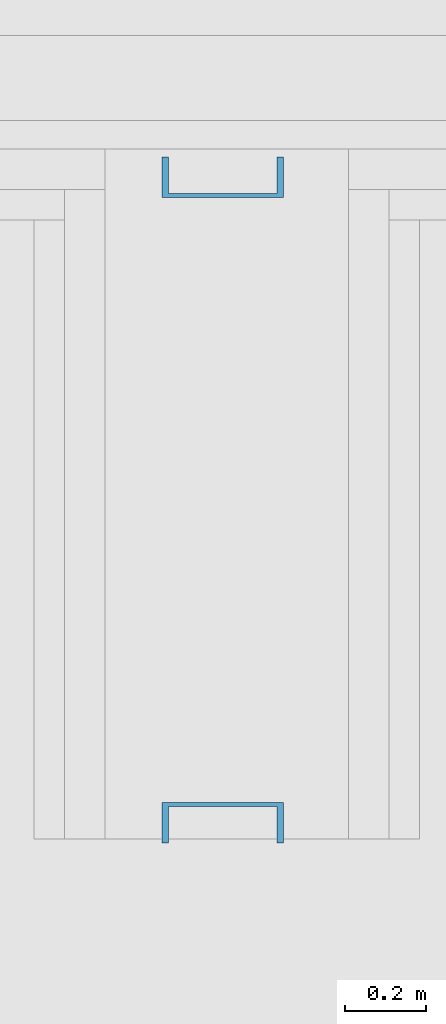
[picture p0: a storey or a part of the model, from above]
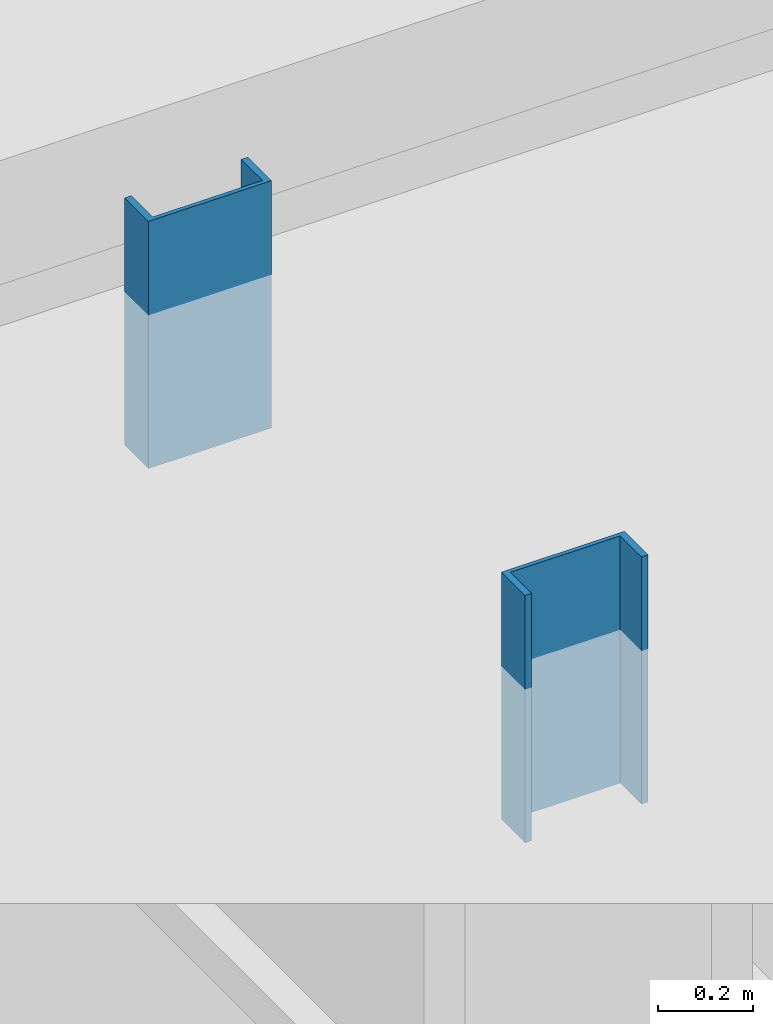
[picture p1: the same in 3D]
Properties of the parts of a building model (IFC2X3), part 1 of 9

# File
Description: ViewDefinition [1, SurfaceGeometryAddOnView, QuantityTakeOffAddOnView, SpaceBoundary2ndLevelAddOnView], Option [Elements to export: Visible elements (on all stories)], Option [Partial Structure Display: Entire Model], Option [IFC Domain: All], Option [Structural Function: All Elements], Option [Convert Grid elements: On], Option [Convert IFC Annotations and ARCHICAD 2D elements: Off], Option [Convert 2D symbols of Doors and Windows: Off], Option [Export geometries that Participates in Collision Detection only: On], Option [Split complex elements: Off], Option [Material Preservation: Explode all], Option [IFC Model position: Project Origin only], Option [Curtain Wall export mode: Container Element], Option [Railing export mode: Container Element], Option [Stair export mode: Container Element], Option [Properties To Export: Current Scheme properties only], Option [Space containment: On], Option [IFC Domain For Space Containment: Custom], Option [Bounding Box: On], Option [Geometry to type objects: On], Option [Element Properties: Off], Option [Building Material Properties: Off], Option [Element Parameters: Off], Option [Component Parameters: IFC Component Quantities Only], Option [IFC Base Quantities: On], Option [Door Window Parameters: Off], Option [IFC Space boundaries: On], Option [ARCHICAD Zone Categories as IFC Space classification data: Off], Option [Element Classifications: On]
File name: P:\Project\2021\21083 1566 Scholen Laren\Archicad\Pdf-Dwg-Ifc-Bimx\21083-TO\IFC\21083-IFC Bouwkundig model.ifc
Time: 2024-04-12T09:14:02
Author: Architect
Organization: Naam bureau
Written by: The EXPRESS Data Manager Version 5.02.0100.09 : 26 Sep 2013
Made in: IFC file generated by GRAPHISOFT ARCHICAD 25.0.0 NED FULL Windows version (IFC add-on version: 7000 NED FULL).
Authorization: The authorising person

# IfcSite, Site
RefLatitude: 51, 27, 0, 0; RefLongitude: 5, 29, 0, 0; RefElevation: 0 mm
BaseQuantities - GrossPerimeter: 0 mm; GrossArea: 0 m2

# IfcBuilding, Naam gebouw
BaseQuantities - GrossFloorArea: 0 m2

# IfcBuildingStorey (5)
In: Naam gebouw
BaseQuantities - GrossFloorArea: 0 m2
Name | Elevation (mm) | NetHeight (mm) = GrossHeight (mm) = Height (mm)
fundering | -1050 | 1050
begane grond | 0 | 3960
verdieping | 3960 | 3960
techniek | 7920 | 3480
dakaanzicht | 11400 | 3500

# IfcBeam: 21 geveldrager (2600+) 208 x 300 (6)
Type - PredefinedType: LINTEL
Classification: 21.22 spouwwanden (NL/SfB (4 cijfers)); Latei (ARCHICAD Classification)
Pset_BeamCommon - Slope: 0 deg; LoadBearing: no; IsExternal: yes; Reference: 21 geveldrager (2600+) 208 x 300
CPset_Phasing - Renovation Phase: Bestaand
BaseQuantities - CrossSectionArea: 0.001983 m2
Name | In | NetSurfaceAreaExtrudedSides (m2) = OuterSurfaceArea (m2) | Length (mm) | TotalSurfaceArea (m2) = GrossSurfaceArea (m2) = NetSurfaceArea (m2) | GrossVolume (m3) = NetVolume (m3)
21_21 geveldrager | begane grond | 33.6494 | 33119.5 | 33.6534 | 0.065676
21_21 geveldrager | begane grond | 29.6365 | 29255 | 29.6405 | 0.0578729
21_21 geveldrager | begane grond | 14.9247 | 14860 | 14.9286 | 0.0291878
21_21 geveldrager | begane grond | 6.87813 | 6855 | 6.8821 | 0.0134537
21_21 geveldrager | verdieping | 14.2494 | 14025 | 14.2534 | 0.0278116
21_21 geveldrager | verdieping | 33.6494 | 33119.5 | 33.6534 | 0.065676

# IfcBeam: 21 geveldrager (3200+) 75 x 300 (4)
In: begane grond
Type - PredefinedType: LINTEL
Classification: 21.22 spouwwanden (NL/SfB (4 cijfers)); Latei (ARCHICAD Classification); Material: Metaal - Staal C beige
Pset_BeamCommon - Slope: 0 deg; LoadBearing: no; IsExternal: yes; Reference: 21 geveldrager (3200+) 75 x 300
CPset_Phasing - Renovation Phase: Bestaand
BaseQuantities - CrossSectionArea: 0.00185 m2
Component Quantities - Metaal - Staal C beige, Component Cross Section Area: 0.00185 m2
Name | NetSurfaceAreaExtrudedSides (m2) = OuterSurfaceArea (m2) | Length (mm) | TotalSurfaceArea (m2) = GrossSurfaceArea (m2) = NetSurfaceArea (m2) | GrossVolume (m3) = NetVolume (m3) = Metaal - Staal C beige, Component Volume (Net) (m3) = Metaal - Staal C beige, Component Volume (Gross) (m3) | Metaal - Staal C beige, Mass (kg)
21_21 geveldrager | 21.4927 | 28722 | 21.4964 | 0.0530147 | 421.467
21_21 geveldrager | 17.8012 | 23800 | 17.8049 | 0.043909 | 349.077
21_21 geveldrager | 1.69872 | 2330 | 1.70242 | 0.0041895 | 33.3065
21_22 geveldrager | 0.562475 | 815 | 0.566175 | 0.00138675 | 11.0247

# IfcBeam: 28 HEB200 200 x 200 (67)
Type - PredefinedType: BEAM
Classification: Balk (ARCHICAD Classification); 28.11 kolom-/liggerconstructies (NL/SfB (4 cijfers))
Pset_BeamCommon - Slope: 0 deg; LoadBearing: yes; IsExternal: no; Reference: 28 HEB200 200 x 200
CPset_Phasing - Renovation Phase: Bestaand
BaseQuantities - CrossSectionArea: 0.00753 m2
Name | In | NetSurfaceAreaExtrudedSides (m2) = OuterSurfaceArea (m2) | Length (mm) | TotalSurfaceArea (m2) = GrossSurfaceArea (m2) = NetSurfaceArea (m2) | GrossVolume (m3) | NetVolume (m3)
30 x 28_Balk-x | begane grond | 0.5319 | 450 | 0.54696 | 0.0033885 | 0.0033885
28_Balk-x | begane grond | 0.46657 | 450 | 0.48163 | 0.0033885 | 0.00292337
28_Balk-x | begane grond | 4.54393 | 3935.8 | 4.55899 | 0.0297872 | 0.0289903
28_Balk-x | begane grond | 3.13411 | 2704.25 | 3.14917 | 0.0216864 | 0.0199231
28_Balk-x | begane grond | 0.520627 | 550 | 0.535687 | 0.00371189 | 0.00331013
5 x 28_Balk-x | begane grond | 0.463409 | 444.5 | 0.478469 | 0.00386862 | 0.00290838
2 x 28_Balk-x | begane grond | 0.5319 | 550 | 0.54696 | 0.0033885 | 0.0033885
28_Balk-x | verdieping | 0.472801 | 400.001 | 0.487861 | 0.00301201 | 0.00301201
28_Balk-x | verdieping | 4.29752 | 3635.8 | 4.31258 | 0.0273776 | 0.0273776
28_Balk-x | verdieping | 2.97618 | 2704.25 | 2.99124 | 0.0215403 | 0.0188632
20 x 28_Balk-x | verdieping | 0.5319 | 450 | 0.54696 | 0.0033885 | 0.0033885
2 x 28_Balk-x | verdieping | 0.5319 | 550 | 0.54696 | 0.0033885 | 0.0033885
28_Balk-x | verdieping | 0.18315 | 450 | 0.19821 | 0.0033885 | 0.00127238 | Material: Metaal - Staal C; Component Quantities - Metaal - Staal C, Mass: 10.1154 kg; Metaal - Staal C, Rectangular Component Height: 15 mm; Metaal - Staal C, Rectangular Component Width: 200 mm; Metaal - Staal C, Component Cross Section Area: 0.003 m2; Metaal - Staal C, Component Volume (Net): 0.00127238 m3; Metaal - Staal C, Component Volume (Gross): 0.00127238 m3

# IfcBeam: 28 HEB280 280 x 280, 28_Balk-x
In: begane grond
Type - PredefinedType: BEAM
Classification: Balk (ARCHICAD Classification); 28.11 kolom-/liggerconstructies (NL/SfB (4 cijfers))
Pset_BeamCommon - Slope: 0 deg; LoadBearing: yes; IsExternal: no; Reference: 28 HEB280 280 x 280
CPset_Phasing - Renovation Phase: Bestaand
BaseQuantities - NetSurfaceAreaExtrudedSides: 23.7237 m2; Length: 14300 mm; CrossSectionArea: 0.011025 m2; OuterSurfaceArea: 23.7237 m2; TotalSurfaceArea: 23.7458 m2; GrossSurfaceArea: 23.7458 m2; GrossVolume: 0.157658 m3; NetSurfaceArea: 23.7458 m2; NetVolume: 0.157658 m3

# IfcBeam: 28 HEB300 300 x 300 (11)
Type - PredefinedType: BEAM
Classification: Balk (ARCHICAD Classification); 28.11 kolom-/liggerconstructies (NL/SfB (4 cijfers))
Pset_BeamCommon - Slope: 0 deg; LoadBearing: yes; IsExternal: no; Reference: 28 HEB300 300 x 300
CPset_Phasing - Renovation Phase: Bestaand
BaseQuantities - CrossSectionArea: 0.014282 m2
Name | In | NetSurfaceAreaExtrudedSides (m2) = OuterSurfaceArea (m2) | Length (mm) | TotalSurfaceArea (m2) = GrossSurfaceArea (m2) = NetSurfaceArea (m2) | GrossVolume (m3) | NetVolume (m3)
28_Balk-x | begane grond | 62.2069 | 34987 | 62.2355 | 0.499684 | 0.499684
28_Balk-x | begane grond | 62.2069 | 34987 | 62.2354 | 0.499684 | 0.499684
28_Balk-x | begane grond | 35.6512 | 20120 | 35.6797 | 0.287639 | 0.28614
28_Balk-x | begane grond | 23.9917 | 13555 | 24.0203 | 0.193593 | 0.192245
28_Balk-x | begane grond | 70.6642 | 39805 | 70.6928 | 0.568495 | 0.567148
28_Balk-x | verdieping | 10.6015 | 6214.5 | 10.63 | 0.0884176 | 0.0849659
28_Balk-x | verdieping | 36.1866 | 20395 | 36.2152 | 0.290865 | 0.290865
28_Balk-x | verdieping | 61.3012 | 34876 | 61.3297 | 0.498256 | 0.491663
28_Balk-x | verdieping | 62.2069 | 34987 | 62.2354 | 0.499684 | 0.499684
28_Balk-x | verdieping | 45.4198 | 25890 | 45.4483 | 0.367619 | 0.364478
28_Balk-x | verdieping | 22.7228 | 13080 | 22.7514 | 0.182524 | 0.182524

# IfcBeam: 28 SFBHE320B/S355 (pet) 425 x 340 (7)
Type - PredefinedType: BEAM
Classification: Balk (ARCHICAD Classification); 28.11 kolom-/liggerconstructies (NL/SfB (4 cijfers))
Pset_BeamCommon - Slope: 0 deg; LoadBearing: yes; IsExternal: no; Reference: 28 SFBHE320B/S355 (pet) 425 x 340
CPset_Phasing - Renovation Phase: Bestaand
BaseQuantities - CrossSectionArea: 0.1109 m2
Name | In | NetSurfaceAreaExtrudedSides (m2) = OuterSurfaceArea (m2) | Length (mm) | TotalSurfaceArea (m2) = GrossSurfaceArea (m2) = NetSurfaceArea (m2) | GrossVolume (m3) | NetVolume (m3)
2 x 28_Balk-x | begane grond | 14.7033 | 9610 | 14.9251 | 1.06575 | 1.06575
28_Balk-x | begane grond | 0.921825 | 602.5 | 1.14362 | 0.0668172 | 0.0668172
28_Balk-x | begane grond | 3.82043 | 2500 | 4.04223 | 0.27725 | 0.277189
2 x 28_Balk-x | verdieping | 3.43615 | 2245.85 | 3.65795 | 0.249065 | 0.249065
28_Balk-x | verdieping | 3.62153 | 2370 | 3.84333 | 0.262833 | 0.262772

# IfcBeam: 28 SFBHE320B/S355 550 x 340 (10)
Type - PredefinedType: BEAM
Classification: Balk (ARCHICAD Classification); 28.11 kolom-/liggerconstructies (NL/SfB (4 cijfers))
Pset_BeamCommon - Slope: 0 deg; LoadBearing: yes; IsExternal: no; Reference: 28 SFBHE320B/S355 550 x 340
CPset_Phasing - Renovation Phase: Bestaand
BaseQuantities - CrossSectionArea: 0.1198 m2
Name | In | NetSurfaceAreaExtrudedSides (m2) = OuterSurfaceArea (m2) | Length (mm) | TotalSurfaceArea (m2) = GrossSurfaceArea (m2) = NetSurfaceArea (m2) | GrossVolume (m3) | NetVolume (m3)
28_Balk-x | begane grond | 23.6691 | 13309.5 | 23.9087 | 1.59448 | 1.58936
28_Balk-x | begane grond | 35.8083 | 20117 | 36.0479 | 2.41002 | 2.41002
28_Balk-x | begane grond | 8.78578 | 4960 | 9.02538 | 0.594208 | 0.592662
28_Balk-x | begane grond | 8.27034 | 4660 | 8.50994 | 0.558268 | 0.55676
28_Balk-x | begane grond | 12.1129 | 6805 | 12.3525 | 0.815239 | 0.815239
28_Balk-x | verdieping | 45.4597 | 26178.5 | 45.6993 | 3.13756 | 3.08051
28_Balk-x | verdieping | 8.01569 | 4510 | 8.25529 | 0.540298 | 0.53944
28_Balk-x | verdieping | 49.904 | 28081.1 | 50.1436 | 3.36412 | 3.35971
28_Balk-x | verdieping | 49.8788 | 28081.1 | 50.1184 | 3.36412 | 3.3606
28_Balk-x | verdieping | 20.5338 | 11560 | 20.7734 | 1.38489 | 1.38334

# IfcBeam: 28 SFHEB200/S440 (pet) 325 x 332 (2)
In: verdieping
Type - PredefinedType: BEAM
Classification: Balk (ARCHICAD Classification); 28.11 kolom-/liggerconstructies (NL/SfB (4 cijfers))
Pset_BeamCommon - Slope: 0 deg; LoadBearing: yes; IsExternal: no; Reference: 28 SFHEB200/S440 (pet) 325 x 332
CPset_Phasing - Renovation Phase: Bestaand
BaseQuantities - NetSurfaceAreaExtrudedSides: 3.24169 m2; Length: 2467.04 mm; CrossSectionArea: 0.07104 m2; OuterSurfaceArea: 3.24169 m2; TotalSurfaceArea: 3.38377 m2; GrossSurfaceArea: 3.38377 m2; GrossVolume: 0.175258 m3; NetSurfaceArea: 3.38377 m2; NetVolume: 0.175258 m3

# IfcBeam: 28 SFHEB200/S440 440 x 332 (2)
In: verdieping
Type - PredefinedType: BEAM
Classification: Balk (ARCHICAD Classification); 28.11 kolom-/liggerconstructies (NL/SfB (4 cijfers))
Pset_BeamCommon - Slope: 0 deg; LoadBearing: yes; IsExternal: no; Reference: 28 SFHEB200/S440 440 x 332
CPset_Phasing - Renovation Phase: Bestaand
BaseQuantities - NetSurfaceAreaExtrudedSides: 3.0494 m2; Length: 1975 mm; CrossSectionArea: 0.07248 m2; OuterSurfaceArea: 3.0494 m2; TotalSurfaceArea: 3.19436 m2; GrossSurfaceArea: 3.19436 m2; GrossVolume: 0.143148 m3; NetSurfaceArea: 3.19436 m2; NetVolume: 0.143148 m3

# IfcBeam: 28 dakrand 500mm 162 x 500 (4)
In: techniek
Type - PredefinedType: LINTEL
Classification: 21.22 spouwwanden (NL/SfB (4 cijfers)); Latei (ARCHICAD Classification)
Pset_BeamCommon - Slope: 0 deg; LoadBearing: no; IsExternal: yes; Reference: 28 dakrand 500mm 162 x 500
CPset_Phasing - Renovation Phase: Bestaand
BaseQuantities - CrossSectionArea: 0.070417 m2
Name | NetSurfaceAreaExtrudedSides (m2) = OuterSurfaceArea (m2) | Length (mm) | TotalSurfaceArea (m2) = GrossSurfaceArea (m2) = NetSurfaceArea (m2) | GrossVolume (m3) | NetVolume (m3)
21_21 geveldrager | 23.0907 | 8340 | 23.2315 | 0.581841 | 0.578875
21_21 geveldrager | 40.5298 | 14650 | 40.6706 | 1.02074 | 1.01553
21_21 geveldrager | 87.5794 | 31550 | 87.7202 | 2.21078 | 2.1995
21_21 geveldrager | 20.2198 | 7338 | 20.3606 | 0.511283 | 0.504103

# IfcBeam: 28 windligger 290 x 180, 28_Balk-x
In: begane grond
Type - PredefinedType: BEAM
Classification: Balk (ARCHICAD Classification); 28.11 kolom-/liggerconstructies (NL/SfB (4 cijfers))
Pset_BeamCommon - Slope: 0 deg; LoadBearing: yes; IsExternal: no; Reference: 28 windligger 290 x 180
CPset_Phasing - Renovation Phase: Bestaand
BaseQuantities - NetSurfaceAreaExtrudedSides: 4.37944 m2; Length: 5450 mm; CrossSectionArea: 0.0265469 m2; OuterSurfaceArea: 4.37944 m2; TotalSurfaceArea: 4.43253 m2; GrossSurfaceArea: 4.43253 m2; GrossVolume: 0.142803 m3; NetSurfaceArea: 4.43253 m2; NetVolume: 0.142803 m3

# IfcBeam: 32 Hout binnenkozijn oregon pine 190 x 75, 28_Balk-x
In: verdieping
Type - PredefinedType: BEAM
Classification: Balk (ARCHICAD Classification); 28.11 kolom-/liggerconstructies (NL/SfB (4 cijfers)); Material: 32 Hout binnenkozijn oregon pine
Pset_BeamCommon - Slope: 0 deg; LoadBearing: yes; IsExternal: no; Reference: 32 Hout binnenkozijn oregon pine 190 x 75
CPset_Phasing - Renovation Phase: Bestaand
BaseQuantities - NetSurfaceAreaExtrudedSides: 0.954 m2; Length: 1800 mm; Width: 190 mm; Depth: 75 mm; CrossSectionArea: 0.01425 m2; OuterSurfaceArea: 0.954 m2; TotalSurfaceArea: 0.9825 m2; GrossSurfaceArea: 0.9825 m2; GrossVolume: 0.02565 m3; NetSurfaceArea: 0.9825 m2; NetVolume: 0.02565 m3
Component Quantities - 32 Hout binnenkozijn oregon pine, Mass: 14.1075 kg; 32 Hout binnenkozijn oregon pine, Projected Component Area (Net): 0.135 m2; 32 Hout binnenkozijn oregon pine, Projected Component Area (Gross): 0.135 m2; 32 Hout binnenkozijn oregon pine, Component Thickness: 190 mm; 32 Hout binnenkozijn oregon pine, Rectangular Component Height: 75 mm; 32 Hout binnenkozijn oregon pine, Rectangular Component Width: 190 mm; 32 Hout binnenkozijn oregon pine, Component Cross Section Area: 0.01425 m2; 32 Hout binnenkozijn oregon pine, Component Volume (Net): 0.02565 m3; 32 Hout binnenkozijn oregon pine, Component Volume (Gross): 0.02565 m3

# IfcBeam: 32 glapkap drsn 60 x 220 (18)
In: techniek
Type - PredefinedType: LINTEL
Classification: 21.22 spouwwanden (NL/SfB (4 cijfers)); Latei (ARCHICAD Classification)
Pset_BeamCommon - LoadBearing: yes; IsExternal: yes; Reference: 32 glapkap drsn 60 x 220
CPset_Phasing - Renovation Phase: Bestaand
BaseQuantities - CrossSectionArea: 0.0118 m2
Name | Slope (deg) | NetSurfaceAreaExtrudedSides (m2) = OuterSurfaceArea (m2) | Length (mm) | TotalSurfaceArea (m2) = GrossSurfaceArea (m2) = NetSurfaceArea (m2) | GrossVolume (m3) | NetVolume (m3)
21_22 geveldrager | 5 | 0.805619 | 1330.03 | 0.829219 | 0.0161664 | 0.014824
21_22 geveldrager | 0 | 4.45102 | 8520 | 4.47462 | 0.101008 | 0.0949741
21_22 geveldrager | 0 | 5.40516 | 8520 | 5.42876 | 0.101008 | 0.0996568
2 x 21_22 geveldrager | 5 | 0.875709 | 1370.03 | 0.899309 | 0.0161664 | 0.0161331
2 x 21_22 geveldrager | 5 | 0.871629 | 1370.03 | 0.895229 | 0.0161664 | 0.0161155
21_22 geveldrager | 5 | 1.93293 | 3091.46 | 1.95653 | 0.0369512 | 0.0356088
21_22 geveldrager | 0 | 4.39767 | 8557.5 | 4.42127 | 0.102394 | 0.0937438
21_22 geveldrager | 0 | 5.33796 | 8557.5 | 5.36156 | 0.102394 | 0.0983585
2 x 21_22 geveldrager | 5 | 2.00302 | 3131.46 | 2.02662 | 0.0369512 | 0.0369179
6 x 21_22 geveldrager | 5 | 1.99894 | 3131.46 | 2.02254 | 0.0369512 | 0.0369003

# IfcBeam: 32 waterslag (dakkap) +200 708 x 66, 28_Balk-x
In: verdieping
Type - PredefinedType: BEAM
Classification: Balk (ARCHICAD Classification); 28.11 kolom-/liggerconstructies (NL/SfB (4 cijfers))
Pset_BeamCommon - Slope: 0 deg; LoadBearing: yes; IsExternal: no; Reference: 32 waterslag (dakkap) +200 708 x 66
CPset_Phasing - Renovation Phase: Bestaand
BaseQuantities - NetSurfaceAreaExtrudedSides: 1.80172 m2; Length: 865 mm; CrossSectionArea: 0.0145938 m2; OuterSurfaceArea: 1.80172 m2; TotalSurfaceArea: 1.83091 m2; GrossSurfaceArea: 1.83091 m2; GrossVolume: 0.00882921 m3; NetSurfaceArea: 1.83091 m2; NetVolume: 0.00882642 m3

# IfcBeam: 32 waterslag (dakkap) 520 x 66 (3)
In: verdieping
Type - PredefinedType: BEAM
Classification: Balk (ARCHICAD Classification); 28.11 kolom-/liggerconstructies (NL/SfB (4 cijfers))
Pset_BeamCommon - Slope: 0 deg; LoadBearing: yes; IsExternal: no; Reference: 32 waterslag (dakkap) 520 x 66
CPset_Phasing - Renovation Phase: Bestaand
BaseQuantities - CrossSectionArea: 0.0104705 m2
Name | NetSurfaceAreaExtrudedSides (m2) = OuterSurfaceArea (m2) | Length (mm) | TotalSurfaceArea (m2) = GrossSurfaceArea (m2) = NetSurfaceArea (m2) | GrossVolume (m3) | NetVolume (m3)
28_Balk-x | 29.4176 | 13443.2 | 29.4385 | 0.138035 | 0.138017
28_Balk-x | 32.1349 | 14920 | 32.1558 | 0.150776 | 0.150776
28_Balk-x | 30.1063 | 14105 | 30.1273 | 0.141258 | 0.141258

# IfcBeam: 34 glazen balustrade 60 x 1200 (4)
Type - PredefinedType: BEAM
Classification: Balk (ARCHICAD Classification); 28.11 kolom-/liggerconstructies (NL/SfB (4 cijfers))
Pset_BeamCommon - LoadBearing: yes; IsExternal: no; Reference: 34 glazen balustrade 60 x 1200
CPset_Phasing - Renovation Phase: Bestaand
BaseQuantities - CrossSectionArea: 0.022944 m2
Name | In | Slope (deg) | NetSurfaceAreaExtrudedSides (m2) = OuterSurfaceArea (m2) | Length (mm) | TotalSurfaceArea (m2) = GrossSurfaceArea (m2) = NetSurfaceArea (m2) | GrossVolume (m3) | NetVolume (m3)
2 x 28_Balk-x | begane grond | 35.7539 | 7.09456 | 3724.26 | 7.14045 | 0.0736797 | 0.0631358
28_Balk-x | verdieping | 0 | 3.97353 | 1705.31 | 4.01942 | 0.0356534 | 0.034134
28_Balk-x | verdieping | 0 | 0.876334 | 505.307 | 0.922222 | 0.00812062 | 0.00732118

# IfcBeam: 34 glazen balustrade 60 x 1370 (2)
In: verdieping
Type - PredefinedType: BEAM
Classification: Balk (ARCHICAD Classification); 28.11 kolom-/liggerconstructies (NL/SfB (4 cijfers))
Pset_BeamCommon - LoadBearing: yes; IsExternal: no; Reference: 34 glazen balustrade 60 x 1370
CPset_Phasing - Renovation Phase: Bestaand
BaseQuantities - CrossSectionArea: 0.025494 m2
Name | Slope (deg) | NetSurfaceAreaExtrudedSides (m2) = OuterSurfaceArea (m2) | Length (mm) | TotalSurfaceArea (m2) = GrossSurfaceArea (m2) = NetSurfaceArea (m2) | GrossVolume (m3) | NetVolume (m3)
28_Balk-x | 35.7539 | 7.25343 | 3774.16 | 7.30442 | 0.0823317 | 0.0645184
28_Balk-x | 0 | 4.64695 | 1755.91 | 4.69794 | 0.0415345 | 0.0393339

# IfcBeam: 34 glazen balustrade 60 x 992 (2)
In: begane grond
Type - PredefinedType: BEAM
Classification: Balk (ARCHICAD Classification); 28.11 kolom-/liggerconstructies (NL/SfB (4 cijfers))
Pset_BeamCommon - Slope: 35.7539 deg; LoadBearing: yes; IsExternal: no; Reference: 34 glazen balustrade 60 x 992
CPset_Phasing - Renovation Phase: Bestaand
BaseQuantities - NetSurfaceAreaExtrudedSides: 5.48389 m2; Length: 3141.41 mm; CrossSectionArea: 0.019817 m2; OuterSurfaceArea: 5.48389 m2; TotalSurfaceArea: 5.52352 m2; GrossSurfaceArea: 5.52352 m2; GrossVolume: 0.0481058 m3; NetSurfaceArea: 5.52352 m2; NetVolume: 0.0481045 m3

# IfcBeam: 42 geleiding strook (mat) 2 x 200 (13)
In: begane grond
Type - PredefinedType: BEAM
Classification: Balk (ARCHICAD Classification); 28.11 kolom-/liggerconstructies (NL/SfB (4 cijfers)); Material: Glas geleiding strook matt
Pset_BeamCommon - Slope: 0 deg; LoadBearing: no; IsExternal: no; Reference: 42 geleiding strook (mat) 2 x 200
CPset_Phasing - Renovation Phase: Bestaand
BaseQuantities - CrossSectionArea: 0.0004 m2
Component Quantities - Glas geleiding strook matt, Rectangular Component Height: 200 mm; Glas geleiding strook matt, Rectangular Component Width: 2 mm; Glas geleiding strook matt, Component Cross Section Area: 0.0004 m2
Name | NetSurfaceAreaExtrudedSides (m2) = OuterSurfaceArea (m2) | Length (mm) | TotalSurfaceArea (m2) = GrossSurfaceArea (m2) = NetSurfaceArea (m2) | GrossVolume (m3) = NetVolume (m3) = Glas geleiding strook matt, Component Volume (Net) (m3) = Glas geleiding strook matt, Component Volume (Gross) (m3) | Glas geleiding strook matt, Mass (kg)
7 x 28_Balk-x | 0.264216 | 654 | 0.265016 | 0.0002616 | 0.570288
2 x 28_Balk-x | 0.280157 | 693.458 | 0.280957 | 0.000277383 | 0.604695
28_Balk-x | 0.339777 | 841.033 | 0.340577 | 0.000336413 | 0.733381
28_Balk-x | 0.190284 | 471 | 0.191084 | 0.0001884 | 0.410712
2 x 28_Balk-x | 0.322897 | 799.25 | 0.323697 | 0.0003197 | 0.696946

# IfcBeam: 42 geleiding strook 20 x 200 (23)
In: begane grond
Type - PredefinedType: BEAM
Classification: Balk (ARCHICAD Classification); 28.11 kolom-/liggerconstructies (NL/SfB (4 cijfers)); Material: Glas geleiding strook
Pset_BeamCommon - Slope: 0 deg; LoadBearing: no; IsExternal: no; Reference: 42 geleiding strook 20 x 200
CPset_Phasing - Renovation Phase: Bestaand
BaseQuantities - CrossSectionArea: 0.004 m2
Component Quantities - Glas geleiding strook, Rectangular Component Height: 200 mm; Glas geleiding strook, Rectangular Component Width: 20 mm; Glas geleiding strook, Component Cross Section Area: 0.004 m2
Name | NetSurfaceAreaExtrudedSides (m2) = OuterSurfaceArea (m2) | Length (mm) | TotalSurfaceArea (m2) = GrossSurfaceArea (m2) = NetSurfaceArea (m2) | GrossVolume (m3) = NetVolume (m3) = Glas geleiding strook, Component Volume (Net) (m3) = Glas geleiding strook, Component Volume (Gross) (m3) | Glas geleiding strook, Mass (kg)
28_Balk-x | 0.319 | 725 | 0.327 | 0.0029 | 6.322
28_Balk-x | 0.65384 | 1496 | 0.66184 | 0.005944 | 12.9579
2 x 28_Balk-x | 0.2376 | 550 | 0.2456 | 0.00216 | 4.7088
28_Balk-x | 0.25124 | 571 | 0.25924 | 0.002284 | 4.97912
28_Balk-x | 0.1474 | 345 | 0.1554 | 0.00134 | 2.9212
28_Balk-x | 3.01884 | 6861 | 3.02684 | 0.027444 | 59.8279
28_Balk-x | 0.077 | 185 | 0.085 | 0.0007 | 1.526
28_Balk-x | 1.03092 | 2353 | 1.03892 | 0.009372 | 20.431
28_Balk-x | 0.25784 | 596 | 0.26584 | 0.002344 | 5.10992
28_Balk-x | 0.30492 | 693 | 0.31292 | 0.002772 | 6.04296
28_Balk-x | 0.75372 | 1723 | 0.76172 | 0.006852 | 14.9374
28_Balk-x | 0.33484 | 761 | 0.34284 | 0.003044 | 6.63592
28_Balk-x | 0.627 | 1425 | 0.635 | 0.0057 | 12.426
28_Balk-x | 2.60084 | 5921 | 2.60884 | 0.023644 | 51.5439
28_Balk-x | 3.77784 | 8586 | 3.78584 | 0.034344 | 74.8699
28_Balk-x | 0.230681 | 534.275 | 0.238681 | 0.0020971 | 4.57168
28_Balk-x | 0.252659 | 574.225 | 0.260659 | 0.0022969 | 5.00724
28_Balk-x | 0.32692 | 743 | 0.33492 | 0.002972 | 6.47896
28_Balk-x | 0.671 | 1525 | 0.679 | 0.0061 | 13.298
28_Balk-x | 0.71676 | 1629 | 0.72476 | 0.006516 | 14.2049
28_Balk-x | 1.54044 | 3501 | 1.54844 | 0.014004 | 30.5287
28_Balk-x | 3.08264 | 7006 | 3.09064 | 0.028024 | 61.0923

# IfcBeam: 80X80X5 80 x 80 (2)
In: techniek
Type - PredefinedType: BEAM
Classification: Balk (ARCHICAD Classification); 28.11 kolom-/liggerconstructies (NL/SfB (4 cijfers)); Material: Metaal - Staal C
Pset_BeamCommon - Slope: 0 deg; LoadBearing: yes; IsExternal: no; Reference: 80X80X5 80 x 80
CPset_Phasing - Renovation Phase: Bestaand
BaseQuantities - CrossSectionArea: 0.0015 m2
Component Quantities - Metaal - Staal C, Component Cross Section Area: 0.0015 m2
Name | NetSurfaceAreaExtrudedSides (m2) = OuterSurfaceArea (m2) | Length (mm) | TotalSurfaceArea (m2) = GrossSurfaceArea (m2) = NetSurfaceArea (m2) | GrossVolume (m3) | NetVolume (m3) = Metaal - Staal C, Component Volume (Net) (m3) = Metaal - Staal C, Component Volume (Gross) (m3) | Metaal - Staal C, Mass (kg)
28_Balk-x | 5.04659 | 8450 | 5.04959 | 0.012705 | 0.0126163 | 100.3
28_Balk-x | 12.1038 | 20195 | 12.1068 | 0.0302925 | 0.0302597 | 240.565

# IfcBeam: ALG - CONSTRUCTIEF 100 x 100 (4)
In: begane grond
Type - PredefinedType: BEAM
Classification: Balk (ARCHICAD Classification); 28.11 kolom-/liggerconstructies (NL/SfB (4 cijfers)); Material: ALG - CONSTRUCTIEF
Pset_BeamCommon - Slope: 0 deg; LoadBearing: yes; IsExternal: no; Reference: ALG - CONSTRUCTIEF 100 x 100
CPset_Phasing - Renovation Phase: Bestaand
BaseQuantities - Width: 100 mm; Depth: 100 mm; CrossSectionArea: 0.01 m2
Component Quantities - ALG - CONSTRUCTIEF, Component Thickness: 100 mm; ALG - CONSTRUCTIEF, Rectangular Component Height: 100 mm; ALG - CONSTRUCTIEF, Rectangular Component Width: 100 mm; ALG - CONSTRUCTIEF, Component Cross Section Area: 0.01 m2
Name | NetSurfaceAreaExtrudedSides (m2) = OuterSurfaceArea (m2) | Length (mm) | TotalSurfaceArea (m2) = GrossSurfaceArea (m2) = NetSurfaceArea (m2) | GrossVolume (m3) | NetVolume (m3) = ALG - CONSTRUCTIEF, Component Volume (Net) (m3) = ALG - CONSTRUCTIEF, Component Volume (Gross) (m3) | ALG - CONSTRUCTIEF, Mass (kg) | ALG - CONSTRUCTIEF, Projected Component Area (Net) (m2) = ALG - CONSTRUCTIEF, Projected Component Area (Gross) (m2)
28_Balk-x | 0.5 | 1250 | 0.52 | 0.0135 | 0.0125 | 28.75 | 0.125
28_Balk-x | 0.52 | 1350 | 0.54 | 0.013 | 0.013 | 29.9 | 0.135
28_Balk-x | 0.405 | 1062.5 | 0.425 | 0.011125 | 0.010125 | 23.2875 | 0.10625
28_Balk-x | 2.8 | 7000 | 2.82 | 0.07 | 0.07 | 161 | 0.7

# IfcBeam: Fundering balk IsoBouw Powerkist 2800 x 850 (26)
In: fundering
Type - PredefinedType: BEAM
Classification: Balk (ARCHICAD Classification); 28.11 kolom-/liggerconstructies (NL/SfB (4 cijfers))
Pset_BeamCommon - Slope: 0 deg; LoadBearing: yes; IsExternal: no; Reference: Fundering balk IsoBouw Powerkist 2800 x 850
CPset_Phasing - Renovation Phase: Bestaand
BaseQuantities - CrossSectionArea: 1.1175 m2
Name | NetSurfaceAreaExtrudedSides (m2) = OuterSurfaceArea (m2) | Length (mm) | TotalSurfaceArea (m2) = GrossSurfaceArea (m2) = NetSurfaceArea (m2) | GrossVolume (m3) | NetVolume (m3)
4 x 28_Balk-x | 5.89448 | 1480 | 8.12948 | 2.29515 | 1.15442
28_Balk-x | 200.404 | 30135 | 202.639 | 35.6598 | 32.5043
28_Balk-x | 22.4512 | 5470 | 24.6862 | 6.78323 | 4.35576
4 x 28_Balk-x | 5.91865 | 1483.45 | 8.15365 | 2.29901 | 1.15828
28_Balk-x | 20.9525 | 3345 | 23.1875 | 3.73804 | 3.57123
28_Balk-x | 47.3641 | 7123.45 | 49.5991 | 7.96046 | 7.73636
2 x 28_Balk-x | 26.2736 | 4475 | 28.5086 | 6.34348 | 4.43352
2 x 28_Balk-x | 45.8817 | 8340 | 48.1167 | 12.0053 | 7.97562
28_Balk-x | 4.30699 | 1785 | 6.54199 | 3.33741 | 1.10142
28_Balk-x | 7.33068 | 1785 | 9.56568 | 3.33741 | 1.42496
28_Balk-x | 266.232 | 39733 | 268.467 | 45.0429 | 43.4576
28_Balk-x | 225.858 | 33083 | 228.093 | 36.9703 | 36.5366
28_Balk-x | 14.3512 | 3345 | 16.5862 | 4.37929 | 2.75389
4 x 28_Balk-x | 5.19377 | 1380 | 7.42877 | 2.1834 | 1.04267
28_Balk-x | 10.6994 | 2155 | 12.9344 | 2.18341 | 1.88579

# IfcBeam: Fundering balk IsoBouw Powerkist buiten 950 x 700 (3)
In: fundering
Type - PredefinedType: BEAM
Classification: Balk (ARCHICAD Classification); 28.11 kolom-/liggerconstructies (NL/SfB (4 cijfers))
Pset_BeamCommon - Slope: 0 deg; LoadBearing: yes; IsExternal: no; Reference: Fundering balk IsoBouw Powerkist buiten 950 x 700
CPset_Phasing - Renovation Phase: Bestaand
BaseQuantities - CrossSectionArea: 0.575001 m2
Name | NetSurfaceAreaExtrudedSides (m2) = OuterSurfaceArea (m2) | Length (mm) | TotalSurfaceArea (m2) = GrossSurfaceArea (m2) = NetSurfaceArea (m2) | GrossVolume (m3) | NetVolume (m3)
28_Balk-x | 6.0555 | 1835 | 7.2055 | 1.05513 | 1.05513
28_Balk-x | 6.1505 | 1885 | 7.3005 | 1.08388 | 1.07788
28_Balk-x | 5.2425 | 1700 | 6.39251 | 1.44413 | 0.948876

# IfcBeam: Fundering balk IsoBouw Powerkist buitenwand 1750 x 850 (14)
In: fundering
Type - PredefinedType: BEAM
Classification: Balk (ARCHICAD Classification); 28.11 kolom-/liggerconstructies (NL/SfB (4 cijfers))
Pset_BeamCommon - Slope: 0 deg; LoadBearing: yes; IsExternal: no; Reference: Fundering balk IsoBouw Powerkist buitenwand 1750 x 850
CPset_Phasing - Renovation Phase: Bestaand
BaseQuantities - CrossSectionArea: 0.815 m2
Name | NetSurfaceAreaExtrudedSides (m2) = OuterSurfaceArea (m2) | Length (mm) | TotalSurfaceArea (m2) = GrossSurfaceArea (m2) = NetSurfaceArea (m2) | GrossVolume (m3) | NetVolume (m3)
28_Balk-x | 33.1224 | 8160 | 34.7524 | 7.38007 | 5.75902
28_Balk-x | 67.8388 | 17705 | 69.4688 | 13.1497 | 11.494
28_Balk-x | 188.748 | 40715 | 190.378 | 32.0991 | 31.5252
28_Balk-x | 68.0436 | 15210 | 69.6736 | 11.3125 | 11.2195
28_Balk-x | 50.7073 | 12145 | 52.3373 | 9.26655 | 8.68128
28_Balk-x | 32.9579 | 7975 | 34.5879 | 5.868 | 5.71056
28_Balk-x | 37.7127 | 8995 | 39.3427 | 6.24731 | 6.24731
28_Balk-x | 37.7885 | 9010 | 39.4185 | 6.25954 | 6.25954
28_Balk-x | 45.4555 | 12065 | 47.0855 | 8.74936 | 7.80175
28_Balk-x | 3.31008 | 2405 | 4.94008 | 0.533825 | 0.533825
28_Balk-x | 138.162 | 28997 | 139.792 | 23.0907 | 22.7019
28_Balk-x | 169.164 | 35897 | 170.794 | 28.1724 | 27.7889
28_Balk-x | 9.16711 | 3563.99 | 10.7971 | 1.4784 | 1.4784
28_Balk-x | 9.16715 | 3564 | 10.7971 | 1.47841 | 1.47841

# IfcBeam: HEB140 140 x 140 (20)
In: verdieping
Type - PredefinedType: BEAM
Classification: Balk (ARCHICAD Classification); 28.11 kolom-/liggerconstructies (NL/SfB (4 cijfers))
Pset_BeamCommon - Slope: 0 deg; LoadBearing: yes; IsExternal: no; Reference: HEB140 140 x 140
CPset_Phasing - Renovation Phase: Bestaand
BaseQuantities - CrossSectionArea: 0.00259 m2
Name | NetSurfaceAreaExtrudedSides (m2) = OuterSurfaceArea (m2) | Length (mm) | TotalSurfaceArea (m2) = GrossSurfaceArea (m2) = NetSurfaceArea (m2) | GrossVolume (m3) = NetVolume (m3)
5 x 28_Balk-x | 0.76775 | 925 | 0.77293 | 0.00239575
7 x 28_Balk-x | 4.10435 | 4945 | 4.10953 | 0.0128075
4 x 28_Balk-x | 3.9757 | 4790 | 3.98088 | 0.0124061
2 x 28_Balk-x | 0.4316 | 520 | 0.43678 | 0.0013468
28_Balk-x | 0.6557 | 790 | 0.66088 | 0.0020461
28_Balk-x | 0.8383 | 1010 | 0.84348 | 0.0026159

# IfcBeam: HEB320 300 x 320, 28_Balk-x
In: begane grond
Type - PredefinedType: BEAM
Classification: Balk (ARCHICAD Classification); 28.11 kolom-/liggerconstructies (NL/SfB (4 cijfers)); Material: Metaal - Staal C
Pset_BeamCommon - Slope: 0 deg; LoadBearing: yes; IsExternal: no; Reference: HEB320 300 x 320
CPset_Phasing - Renovation Phase: Bestaand
BaseQuantities - NetSurfaceAreaExtrudedSides: 71.5565 m2; Length: 39697.8 mm; CrossSectionArea: 0.0155085 m2; OuterSurfaceArea: 71.5565 m2; TotalSurfaceArea: 71.5875 m2; GrossSurfaceArea: 71.5875 m2; GrossVolume: 0.618246 m3; NetSurfaceArea: 71.5875 m2; NetVolume: 0.610081 m3
Component Quantities - Metaal - Staal C, Mass: 4850.14 kg; Metaal - Staal C, Component Cross Section Area: 0.0155085 m2; Metaal - Staal C, Component Volume (Net): 0.610081 m3; Metaal - Staal C, Component Volume (Gross): 0.610081 m3

# IfcBeam: Hout C 38 x 120 (4)
In: begane grond
Type - PredefinedType: BEAM
Classification: Balk (ARCHICAD Classification); 28.11 kolom-/liggerconstructies (NL/SfB (4 cijfers)); Material: Hout C
Pset_BeamCommon - Slope: 0 deg; LoadBearing: yes; IsExternal: no; Reference: Hout C 38 x 120
CPset_Phasing - Renovation Phase: Bestaand
BaseQuantities - NetSurfaceAreaExtrudedSides: 2.09192 m2; Length: 6620 mm; Width: 38 mm; Depth: 120 mm; CrossSectionArea: 0.00456 m2; OuterSurfaceArea: 2.09192 m2; TotalSurfaceArea: 2.10104 m2; GrossSurfaceArea: 2.10104 m2; GrossVolume: 0.0301872 m3; NetSurfaceArea: 2.10104 m2; NetVolume: 0.0301872 m3
Component Quantities - Hout C, Mass: 16.603 kg; Hout C, Projected Component Area (Net): 0.7944 m2; Hout C, Projected Component Area (Gross): 0.7944 m2; Hout C, Component Thickness: 38 mm; Hout C, Rectangular Component Height: 120 mm; Hout C, Rectangular Component Width: 38 mm; Hout C, Component Cross Section Area: 0.00456 m2; Hout C, Component Volume (Net): 0.0301872 m3; Hout C, Component Volume (Gross): 0.0301872 m3

# IfcBeam: IPE200 100 x 200 (4)
In: techniek
Type - PredefinedType: BEAM
Classification: Balk (ARCHICAD Classification); 28.11 kolom-/liggerconstructies (NL/SfB (4 cijfers)); Material: Metaal - Staal C
Pset_BeamCommon - Slope: 0 deg; LoadBearing: yes; IsExternal: no; Reference: IPE200 100 x 200
CPset_Phasing - Renovation Phase: Bestaand
BaseQuantities - NetSurfaceAreaExtrudedSides: 6.66919 m2; Length: 8470 mm; CrossSectionArea: 0.0027248 m2; OuterSurfaceArea: 6.66919 m2; TotalSurfaceArea: 6.67464 m2; GrossSurfaceArea: 6.67464 m2; GrossVolume: 0.0230791 m3; NetSurfaceArea: 6.67464 m2; NetVolume: 0.0230293 m3
Component Quantities - Metaal - Staal C, Mass: 183.083 kg; Metaal - Staal C, Component Cross Section Area: 0.0027248 m2; Metaal - Staal C, Component Volume (Net): 0.0230293 m3; Metaal - Staal C, Component Volume (Gross): 0.0230293 m3

# IfcBeam: L60X6 60 x 60 (12)
In: techniek
Type - PredefinedType: BEAM
Classification: Balk (ARCHICAD Classification); 28.11 kolom-/liggerconstructies (NL/SfB (4 cijfers)); Material: Metaal - Staal C
Pset_BeamCommon - Slope: 0 deg; LoadBearing: yes; IsExternal: no; Reference: L60X6 60 x 60
CPset_Phasing - Renovation Phase: Bestaand
BaseQuantities - CrossSectionArea: 0.000684 m2
Component Quantities - Metaal - Staal C, Component Cross Section Area: 0.000684 m2
Name | NetSurfaceAreaExtrudedSides (m2) = OuterSurfaceArea (m2) | Length (mm) | TotalSurfaceArea (m2) = GrossSurfaceArea (m2) = NetSurfaceArea (m2) | GrossVolume (m3) | NetVolume (m3) = Metaal - Staal C, Component Volume (Net) (m3) = Metaal - Staal C, Component Volume (Gross) (m3) | Metaal - Staal C, Mass (kg)
8 x 28_Balk-x | 1.44951 | 6039.62 | 1.45088 | 0.0041311 | 0.0041311 | 32.8423
2 x 28_Balk-x | 1.15284 | 4803.5 | 1.15421 | 0.00328559 | 0.00328559 | 26.1205
2 x 28_Balk-x | 1.44126 | 6033.83 | 1.44263 | 0.0041311 | 0.00410754 | 32.655

# IfcBeam: Metaal - RVS 40 x 20 (8)
Type - PredefinedType: BEAM
Classification: Balk (ARCHICAD Classification); 28.11 kolom-/liggerconstructies (NL/SfB (4 cijfers)); Material: Metaal - RVS
Pset_BeamCommon - LoadBearing: yes; IsExternal: no; Reference: Metaal - RVS 40 x 20
CPset_Phasing - Renovation Phase: Bestaand
BaseQuantities - Width: 40 mm; Depth: 20 mm; CrossSectionArea: 0.0008 m2
Component Quantities - Metaal - RVS, Component Thickness: 40 mm; Metaal - RVS, Rectangular Component Height: 20 mm; Metaal - RVS, Rectangular Component Width: 40 mm; Metaal - RVS, Component Cross Section Area: 0.0008 m2
Name | In | Slope (deg) | NetSurfaceAreaExtrudedSides (m2) = OuterSurfaceArea (m2) | Length (mm) | TotalSurfaceArea (m2) = GrossSurfaceArea (m2) = NetSurfaceArea (m2) | GrossVolume (m3) | NetVolume (m3) = Metaal - RVS, Component Volume (Net) (m3) = Metaal - RVS, Component Volume (Gross) (m3) | Metaal - RVS, Mass (kg) | Metaal - RVS, Projected Component Area (Net) (m2) = Metaal - RVS, Projected Component Area (Gross) (m2)
2 x 28_Balk-x | begane grond | 35.7539 | 0.399804 | 3343.56 | 0.401404 | 0.00267466 | 0.00266647 | 21.0651 | 0.0666617
2 x 28_Balk-x | begane grond | 35.7539 | 0.292984 | 2458.13 | 0.294584 | 0.00196172 | 0.00195596 | 15.4521 | 0.0488989
28_Balk-x | verdieping | 0 | 0.173613 | 1450 | 0.175213 | 0.00115742 | 0.00115742 | 9.14362 | 0.0289355
28_Balk-x | verdieping | 0 | 0.0296129 | 250 | 0.0312129 | 0.00019742 | 0.00019742 | 1.55962 | 0.00493549
28_Balk-x | verdieping | 35.7539 | 0.447712 | 3741.36 | 0.449312 | 0.00298474 | 0.00298474 | 23.5795 | 0.0746186
28_Balk-x | verdieping | 0 | 0.146667 | 1225.45 | 0.148267 | 0.000977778 | 0.000977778 | 7.72444 | 0.0244444

# IfcBeam: Metaal - Staal C 10 x 60 (8)
In: techniek
Type - PredefinedType: BEAM
Classification: Balk (ARCHICAD Classification); 28.11 kolom-/liggerconstructies (NL/SfB (4 cijfers)); Material: Metaal - Staal C
Pset_BeamCommon - LoadBearing: yes; IsExternal: no; Reference: Metaal - Staal C 10 x 60
CPset_Phasing - Renovation Phase: Bestaand
BaseQuantities - Width: 10 mm; Depth: 60 mm; CrossSectionArea: 0.0006 m2
Component Quantities - Metaal - Staal C, Component Thickness: 10 mm; Metaal - Staal C, Rectangular Component Height: 60 mm; Metaal - Staal C, Rectangular Component Width: 10 mm; Metaal - Staal C, Component Cross Section Area: 0.0006 m2
Name | Slope (deg) | NetSurfaceAreaExtrudedSides (m2) = OuterSurfaceArea (m2) | Length (mm) | TotalSurfaceArea (m2) = GrossSurfaceArea (m2) = NetSurfaceArea (m2) | GrossVolume (m3) = NetVolume (m3) = Metaal - Staal C, Component Volume (Net) (m3) = Metaal - Staal C, Component Volume (Gross) (m3) | Metaal - Staal C, Mass (kg) | Metaal - Staal C, Projected Component Area (Net) (m2) = Metaal - Staal C, Projected Component Area (Gross) (m2)
4 x 28_Balk-x | -28.2374 | 0.686497 | 4935.77 | 0.687697 | 0.00294213 | 23.3899 | 0.294213
4 x 28_Balk-x | -29.1481 | 0.666847 | 4796.65 | 0.668047 | 0.00285792 | 22.7204 | 0.285792

# IfcBeam: Metaal - Staal C 80 x 6, 28_Balk-x
In: begane grond
Type - PredefinedType: BEAM
Classification: Balk (ARCHICAD Classification); 28.11 kolom-/liggerconstructies (NL/SfB (4 cijfers)); Material: Metaal - Staal C
Pset_BeamCommon - Slope: 0 deg; LoadBearing: yes; IsExternal: no; Reference: Metaal - Staal C 80 x 6
CPset_Phasing - Renovation Phase: Bestaand
BaseQuantities - NetSurfaceAreaExtrudedSides: 0.31046 m2; Length: 1805 mm; Width: 80 mm; Depth: 6 mm; CrossSectionArea: 0.00048 m2; OuterSurfaceArea: 0.31046 m2; TotalSurfaceArea: 0.31142 m2; GrossSurfaceArea: 0.31142 m2; GrossVolume: 0.0008664 m3; NetSurfaceArea: 0.31142 m2; NetVolume: 0.0008664 m3
Component Quantities - Metaal - Staal C, Mass: 6.88788 kg; Metaal - Staal C, Projected Component Area (Net): 0.01083 m2; Metaal - Staal C, Projected Component Area (Gross): 0.01083 m2; Metaal - Staal C, Component Thickness: 80 mm; Metaal - Staal C, Rectangular Component Height: 6 mm; Metaal - Staal C, Rectangular Component Width: 80 mm; Metaal - Staal C, Component Cross Section Area: 0.00048 m2; Metaal - Staal C, Component Volume (Net): 0.0008664 m3; Metaal - Staal C, Component Volume (Gross): 0.0008664 m3

# IfcBeam: Metaal - Staal C wit D40 (2)
In: begane grond
Type - PredefinedType: BEAM
Classification: Balk (ARCHICAD Classification); 28.11 kolom-/liggerconstructies (NL/SfB (4 cijfers)); Material: Metaal - Staal C wit
Pset_BeamCommon - Slope: 0 deg; LoadBearing: no; IsExternal: no; Reference: Metaal - Staal C wit D40
CPset_Phasing - Renovation Phase: Bestaand
BaseQuantities - NetSurfaceAreaExtrudedSides: 0.323689 m2; Length: 2605.5 mm; Width: 40 mm; Depth: 40 mm; CrossSectionArea: 0.00125664 m2; OuterSurfaceArea: 0.323689 m2; TotalSurfaceArea: 0.326203 m2; GrossSurfaceArea: 0.326203 m2; GrossVolume: 0.0031266 m3; NetSurfaceArea: 0.326203 m2; NetVolume: 0.0031266 m3
Component Quantities - Metaal - Staal C wit, Mass: 24.8565 kg; Metaal - Staal C wit, Projected Component Area (Net): 0.10422 m2; Metaal - Staal C wit, Projected Component Area (Gross): 0.10422 m2; Metaal - Staal C wit, Component Thickness: 40 mm; Metaal - Staal C wit, Component Cross Section Area: 0.00125664 m2; Metaal - Staal C wit, Component Volume (Net): 0.0031266 m3; Metaal - Staal C wit, Component Volume (Gross): 0.0031266 m3

# IfcBeam: Profiel T algemeen 100 x 100 (4)
In: begane grond
Type - PredefinedType: BEAM
Classification: Balk (ARCHICAD Classification); 28.11 kolom-/liggerconstructies (NL/SfB (4 cijfers)); Material: Metaal - Staal AFW
Pset_BeamCommon - Slope: 0 deg; LoadBearing: yes; IsExternal: no; Reference: Profiel T algemeen 100 x 100
CPset_Phasing - Renovation Phase: Bestaand
BaseQuantities - CrossSectionArea: 0.0019 m2
Component Quantities - Metaal - Staal AFW, Component Cross Section Area: 0.0019 m2
Name | NetSurfaceAreaExtrudedSides (m2) = OuterSurfaceArea (m2) | Length (mm) | TotalSurfaceArea (m2) = GrossSurfaceArea (m2) = NetSurfaceArea (m2) | GrossVolume (m3) | NetVolume (m3) = Metaal - Staal AFW, Component Volume (Net) (m3) = Metaal - Staal AFW, Component Volume (Gross) (m3) | Metaal - Staal AFW, Mass (kg)
2 x 28_Balk-x | 0.2776 | 694 | 0.2814 | 0.0016074 | 0.0013186 | 10.4829
2 x 28_Balk-x | 0.2416 | 604 | 0.2454 | 0.0014364 | 0.0011476 | 9.12342

# IfcBeam: UNP140 60 x 140 (4)
In: verdieping
Type - PredefinedType: BEAM
Classification: Balk (ARCHICAD Classification); 28.11 kolom-/liggerconstructies (NL/SfB (4 cijfers)); Material: Metaal - Staal C
Pset_BeamCommon - Slope: 0 deg; LoadBearing: yes; IsExternal: no; Reference: UNP140 60 x 140
CPset_Phasing - Renovation Phase: Bestaand
BaseQuantities - CrossSectionArea: 0.00204 m2
Component Quantities - Metaal - Staal C, Component Cross Section Area: 0.00204 m2
Name | NetSurfaceAreaExtrudedSides (m2) = OuterSurfaceArea (m2) | Length (mm) | TotalSurfaceArea (m2) = GrossSurfaceArea (m2) = NetSurfaceArea (m2) | GrossVolume (m3) | NetVolume (m3) = Metaal - Staal C, Component Volume (Net) (m3) = Metaal - Staal C, Component Volume (Gross) (m3) | Metaal - Staal C, Mass (kg)
28_Balk-x | 3.73595 | 7400 | 3.74003 | 0.015096 | 0.0150598 | 119.725
28_Balk-x | 4.56619 | 9042.25 | 4.57027 | 0.0184073 | 0.0184073 | 146.338
28_Balk-x | 7.24272 | 14350 | 7.2468 | 0.0291961 | 0.0291961 | 232.109
28_Balk-x | 15.7882 | 31220.2 | 15.7923 | 0.0636503 | 0.0636503 | 506.02

# IfcBeam: UNP300 100 x 300 (7)
In: begane grond
Type - PredefinedType: BEAM
Classification: Balk (ARCHICAD Classification); 28.11 kolom-/liggerconstructies (NL/SfB (4 cijfers)); Material: Metaal - Staal C
Pset_BeamCommon - LoadBearing: yes; IsExternal: no; Reference: UNP300 100 x 300
CPset_Phasing - Renovation Phase: Bestaand
BaseQuantities - CrossSectionArea: 0.00588 m2
Component Quantities - Metaal - Staal C, Component Cross Section Area: 0.00588 m2
Name | Slope (deg) | NetSurfaceAreaExtrudedSides (m2) = OuterSurfaceArea (m2) | Length (mm) | TotalSurfaceArea (m2) = GrossSurfaceArea (m2) = NetSurfaceArea (m2) | GrossVolume (m3) | NetVolume (m3) = Metaal - Staal C, Component Volume (Net) (m3) = Metaal - Staal C, Component Volume (Gross) (m3) | Metaal - Staal C, Mass (kg)
28_Balk-x | 0 | 1.66238 | 1770 | 1.67414 | 0.0103398 | 0.009993 | 79.4444
28_Balk-x | 0 | 2.19264 | 2290 | 2.2044 | 0.0131184 | 0.0131184 | 104.291
28_Balk-x | 0 | 3.44137 | 3633.67 | 3.45313 | 0.0206669 | 0.0206669 | 164.302
2 x 28_Balk-x | -35.7539 | 6.29723 | 6582.12 | 6.30899 | 0.0377834 | 0.0377834 | 300.378
28_Balk-x | 0 | 1.78104 | 1870 | 1.7928 | 0.0106488 | 0.0106488 | 84.658
28_Balk-x | 0 | 1.31763 | 1433.67 | 1.32939 | 0.00820431 | 0.00785751 | 62.4672

# IfcBeam: VI Garderobe 01 3012 x 1122 (5)
In: begane grond
Type - PredefinedType: BEAM
Classification: Balk (ARCHICAD Classification); 28.11 kolom-/liggerconstructies (NL/SfB (4 cijfers))
Pset_BeamCommon - Slope: 0 deg; LoadBearing: yes; IsExternal: no; Reference: VI Garderobe 01 3012 x 1122
CPset_Phasing - Renovation Phase: Bestaand
BaseQuantities - NetSurfaceAreaExtrudedSides: 0.779137 m2; Length: 18 mm; CrossSectionArea: 3.25284 m2; OuterSurfaceArea: 0.779137 m2; TotalSurfaceArea: 7.28482 m2; GrossSurfaceArea: 7.28482 m2; GrossVolume: 0.0585866 m3; NetSurfaceArea: 7.28482 m2; NetVolume: 0.0585866 m3

# IfcBeam: VI Garderobe 05 2412 x 1122 (4)
Type - PredefinedType: BEAM
Classification: Balk (ARCHICAD Classification); 28.11 kolom-/liggerconstructies (NL/SfB (4 cijfers))
Pset_BeamCommon - Slope: 0 deg; LoadBearing: yes; IsExternal: no; Reference: VI Garderobe 05 2412 x 1122
CPset_Phasing - Renovation Phase: Bestaand
BaseQuantities - NetSurfaceAreaExtrudedSides: 0.623698 m2; Length: 18 mm; CrossSectionArea: 2.60627 m2; OuterSurfaceArea: 0.623698 m2; TotalSurfaceArea: 5.83624 m2; GrossSurfaceArea: 5.83624 m2; GrossVolume: 0.0469412 m3; NetSurfaceArea: 5.83624 m2; NetVolume: 0.0469412 m3
Name | In
2 x 28_Balk-x | begane grond
2 x 28_Balk-x | verdieping

# IfcBeam: VI Garderobe 06 1812 x 1122 (2)
In: begane grond
Type - PredefinedType: BEAM
Classification: Balk (ARCHICAD Classification); 28.11 kolom-/liggerconstructies (NL/SfB (4 cijfers))
Pset_BeamCommon - Slope: 0 deg; LoadBearing: yes; IsExternal: no; Reference: VI Garderobe 06 1812 x 1122
CPset_Phasing - Renovation Phase: Bestaand
BaseQuantities - NetSurfaceAreaExtrudedSides: 0.46826 m2; Length: 18 mm; CrossSectionArea: 1.9597 m2; OuterSurfaceArea: 0.46826 m2; TotalSurfaceArea: 4.38766 m2; GrossSurfaceArea: 4.38766 m2; GrossVolume: 0.0352958 m3; NetSurfaceArea: 4.38766 m2; NetVolume: 0.0352958 m3

# IfcBeam: VI Garderobe 10 3612 x 1122 (5)
In: verdieping
Type - PredefinedType: BEAM
Classification: Balk (ARCHICAD Classification); 28.11 kolom-/liggerconstructies (NL/SfB (4 cijfers))
Pset_BeamCommon - Slope: 0 deg; LoadBearing: yes; IsExternal: no; Reference: VI Garderobe 10 3612 x 1122
CPset_Phasing - Renovation Phase: Bestaand
BaseQuantities - NetSurfaceAreaExtrudedSides: 0.934575 m2; Length: 18 mm; CrossSectionArea: 3.89942 m2; OuterSurfaceArea: 0.934575 m2; TotalSurfaceArea: 8.73341 m2; GrossSurfaceArea: 8.73341 m2; GrossVolume: 0.070232 m3; NetSurfaceArea: 8.73341 m2; NetVolume: 0.070232 m3

# IfcBeam: VI Garderobe 8a 2712 x 1122 (2)
In: verdieping
Type - PredefinedType: BEAM
Classification: Balk (ARCHICAD Classification); 28.11 kolom-/liggerconstructies (NL/SfB (4 cijfers))
Pset_BeamCommon - Slope: 0 deg; LoadBearing: yes; IsExternal: no; Reference: VI Garderobe 8a 2712 x 1122
CPset_Phasing - Renovation Phase: Bestaand
BaseQuantities - NetSurfaceAreaExtrudedSides: 0.701418 m2; Length: 18 mm; CrossSectionArea: 2.92956 m2; OuterSurfaceArea: 0.701418 m2; TotalSurfaceArea: 6.56053 m2; GrossSurfaceArea: 6.56053 m2; GrossVolume: 0.0527639 m3; NetSurfaceArea: 6.56053 m2; NetVolume: 0.0527639 m3

# IfcBeam: VI Garderobe 8b 1512 x 1122 (2)
In: verdieping
Type - PredefinedType: BEAM
Classification: Balk (ARCHICAD Classification); 28.11 kolom-/liggerconstructies (NL/SfB (4 cijfers))
Pset_BeamCommon - Slope: 0 deg; LoadBearing: yes; IsExternal: no; Reference: VI Garderobe 8b 1512 x 1122
CPset_Phasing - Renovation Phase: Bestaand
BaseQuantities - NetSurfaceAreaExtrudedSides: 0.39054 m2; Length: 18 mm; CrossSectionArea: 1.63641 m2; OuterSurfaceArea: 0.39054 m2; TotalSurfaceArea: 3.66336 m2; GrossSurfaceArea: 3.66336 m2; GrossVolume: 0.0294731 m3; NetSurfaceArea: 3.66336 m2; NetVolume: 0.0294731 m3

# IfcBuildingElementPart (2190)
Name | In | Material | Mass (kg) | Component Cross Section Area (m2) | Component Volume (Net) (m3) | Component Volume (Gross) (m3)
ALG - TERREIN | fundering | ALG - TERREIN | 3001.33 | 0.24 | 1.36424 | 1.36424
Isolatie - EPS | fundering | Isolatie - EPS | 19.7349 | 0.0871468 | 0.65783 | 0.65783
Isolatie - EPS | fundering | Isolatie - EPS | 14.2032 | 0.0639266 | 0.473441 | 0.473441
Isolatie - EPS | fundering | Isolatie - EPS | 13.0173 | 0.0639266 | 0.433911 | 0.433911
Beton gewapend C | fundering | Beton gewapend C | 6508.08 | 0.36 | 2.8296 | 2.8296 | Component Quantities - Rectangular Component Height: 600 mm; Rectangular Component Width: 600 mm
2 x Beton gewapend prefab vloer | fundering | Beton gewapend prefab vloer | 187.2 |  | 0.078 | 0.078 | Component Quantities - Projected Component Area (Net): 0.3 m2; Projected Component Area (Gross): 0.3 m2; Component Thickness: 260 mm
2 x Isolatie - EPS vloer | fundering | Isolatie - EPS vloer | 1.08 |  | 0.036 | 0.036 | Component Quantities - Projected Component Area (Net): 0.3 m2; Projected Component Area (Gross): 0.3 m2; Component Thickness: 120 mm
4 x ALG - TERREIN | fundering | ALG - TERREIN | 730.501 | 0.5425 | 0.332046 | 0.332046
4 x Isolatie - EPS | fundering | Isolatie - EPS | 3.4118 | 0.0871469 | 0.113727 | 0.113727
8 x Isolatie - EPS | fundering | Isolatie - EPS | 2.63773 | 0.0639266 | 0.0879242 | 0.0879242
4 x Beton gewapend C | fundering | Beton gewapend C | 1225.44 | 0.36 | 0.532801 | 0.532801 | Component Quantities - Rectangular Component Height: 600 mm; Rectangular Component Width: 600.001 mm
Isolatie - EPS | fundering | Isolatie - EPS | 4.79744 | 0.0871469 | 0.159915 | 0.159915
2 x Isolatie - EPS | fundering | Isolatie - EPS | 3.51916 | 0.0639266 | 0.117305 | 0.117305
Beton gewapend C | fundering | Beton gewapend C | 1519.38 | 0.36 | 0.660601 | 0.660601 | Component Quantities - Rectangular Component Height: 600 mm; Rectangular Component Width: 600.001 mm
ALG - TERREIN | fundering | ALG - TERREIN | 33593.7 | 0.5425 | 15.2698 | 15.2698
Isolatie - EPS | fundering | Isolatie - EPS | 77.8702 | 0.087147 | 2.59567 | 2.59567
Isolatie - EPS | fundering | Isolatie - EPS | 56.3116 | 0.0639266 | 1.87705 | 1.87705
Isolatie - EPS | fundering | Isolatie - EPS | 57.3916 | 0.0639266 | 1.91305 | 1.91305
Beton gewapend C | fundering | Beton gewapend C | 24951.8 | 0.360001 | 10.8486 | 10.8486 | Component Quantities - Rectangular Component Height: 600 mm; Rectangular Component Width: 600.001 mm
ALG - TERREIN | fundering | ALG - TERREIN | 6525.98 | 0.24 | 2.96636 | 2.96636
Isolatie - EPS | fundering | Isolatie - EPS | 37.9326 | 0.0871468 | 1.26442 | 1.26442
Isolatie - EPS | fundering | Isolatie - EPS | 25.771 | 0.0639266 | 0.859033 | 0.859033
Isolatie - EPS | fundering | Isolatie - EPS | 28.4512 | 0.0639266 | 0.948373 | 0.948373
Beton gewapend C | fundering | Beton gewapend C | 12548.3 | 0.36 | 5.4558 | 5.4558 | Component Quantities - Rectangular Component Height: 600 mm; Rectangular Component Width: 600 mm
ALG - TERREIN | fundering | ALG - TERREIN | 2894.29 | 0.5425 | 1.31559 | 1.31559
Isolatie - EPS | fundering | Isolatie - EPS | 12.9282 | 0.0871469 | 0.430941 | 0.430941
Isolatie - EPS | fundering | Isolatie - EPS | 9.31251 | 0.0639266 | 0.310417 | 0.310417
Isolatie - EPS | fundering | Isolatie - EPS | 9.88851 | 0.0639266 | 0.329617 | 0.329617
Beton gewapend C | fundering | Beton gewapend C | 4529.16 | 0.36 | 1.9692 | 1.9692 | Component Quantities - Rectangular Component Height: 600 mm; Rectangular Component Width: 600 mm
ALG - TERREIN | fundering | ALG - TERREIN | 19688.3 | 0.24 | 8.94923 | 8.94923
Isolatie - EPS | fundering | Isolatie - EPS | 103.962 | 0.0871468 | 3.46539 | 3.46539
Isolatie - EPS | fundering | Isolatie - EPS | 77.6013 | 0.0639266 | 2.58671 | 2.58671
Isolatie - EPS | fundering | Isolatie - EPS | 68.7669 | 0.0639266 | 2.29223 | 2.29223
Beton gewapend C | fundering | Beton gewapend C | 32732.9 | 0.36 | 14.2317 | 14.2317 | Component Quantities - Rectangular Component Height: 600 mm; Rectangular Component Width: 600 mm
ALG - TERREIN | fundering | ALG - TERREIN | 6723.28 | 0.24 | 3.05604 | 3.05604
Isolatie - EPS | fundering | Isolatie - EPS | 37.2814 | 0.0871468 | 1.24271 | 1.24271
Isolatie - EPS | fundering | Isolatie - EPS | 28.6879 | 0.0639266 | 0.956263 | 0.956263
Isolatie - EPS | fundering | Isolatie - EPS | 24.9277 | 0.0639266 | 0.830923 | 0.830923
Beton gewapend C | fundering | Beton gewapend C | 11807.3 | 0.36 | 5.1336 | 5.1336 | Component Quantities - Rectangular Component Height: 600 mm; Rectangular Component Width: 600 mm
4 x ALG - TERREIN | fundering | ALG - TERREIN | 734.617 | 0.5425 | 0.333917 | 0.333917
4 x Isolatie - EPS | fundering | Isolatie - EPS | 3.42082 | 0.0871469 | 0.114027 | 0.114027
8 x Isolatie - EPS | fundering | Isolatie - EPS | 2.64434 | 0.0639266 | 0.0881447 | 0.0881447
4 x Beton gewapend C | fundering | Beton gewapend C | 1228.3 | 0.36 | 0.534042 | 0.534042 | Component Quantities - Rectangular Component Height: 600 mm; Rectangular Component Width: 600.001 mm
ALG - TERREIN | fundering | ALG - TERREIN | 5163.79 | 0.24 | 2.34718 | 2.34718
Isolatie - EPS | fundering | Isolatie - EPS | 29.4056 | 0.0871468 | 0.980187 | 0.980187
Isolatie - EPS | fundering | Isolatie - EPS | 20.7254 | 0.0639266 | 0.690845 | 0.690845
Isolatie - EPS | fundering | Isolatie - EPS | 20.532 | 0.0639266 | 0.684398 | 0.684398
Beton gewapend C | fundering | Beton gewapend C | 9150.95 | 0.36 | 3.97867 | 3.97867 | Component Quantities - Rectangular Component Height: 600 mm; Rectangular Component Width: 600 mm
ALG - TERREIN | fundering | ALG - TERREIN | 3604.85 | 0.24 | 1.63857 | 1.63857
Isolatie - EPS | fundering | Isolatie - EPS | 18.7825 | 0.0871468 | 0.626083 | 0.626083
Isolatie - EPS | fundering | Isolatie - EPS | 13.8081 | 0.0639266 | 0.460271 | 0.460271
Isolatie - EPS | fundering | Isolatie - EPS | 13.0699 | 0.0639266 | 0.435664 | 0.435664
Beton gewapend C | fundering | Beton gewapend C | 5864.93 | 0.36 | 2.54997 | 2.54997 | Component Quantities - Rectangular Component Height: 600 mm; Rectangular Component Width: 600 mm
ALG - TERREIN | fundering | ALG - TERREIN | 3567.16 | 0.24 | 1.62144 | 1.62144
Isolatie - EPS | fundering | Isolatie - EPS | 21.0329 | 0.0871468 | 0.701096 | 0.701096
Isolatie - EPS | fundering | Isolatie - EPS | 16.7688 | 0.0639266 | 0.55896 | 0.55896
Isolatie - EPS | fundering | Isolatie - EPS | 14.0886 | 0.0639266 | 0.469619 | 0.469619
Beton gewapend C | fundering | Beton gewapend C | 6661.26 | 0.36 | 2.8962 | 2.8962 | Component Quantities - Rectangular Component Height: 600 mm; Rectangular Component Width: 600 mm
ALG - TERREIN | fundering | ALG - TERREIN | 3575.08 | 0.24 | 1.62504 | 1.62504
Isolatie - EPS | fundering | Isolatie - EPS | 21.0721 | 0.0871468 | 0.702403 | 0.702403
Isolatie - EPS | fundering | Isolatie - EPS | 16.7976 | 0.0639266 | 0.559918 | 0.559918
Isolatie - EPS | fundering | Isolatie - EPS | 14.1173 | 0.0639266 | 0.470578 | 0.470578
Beton gewapend C | fundering | Beton gewapend C | 6673.68 | 0.36 | 2.9016 | 2.9016 | Component Quantities - Rectangular Component Height: 600 mm; Rectangular Component Width: 600 mm
ALG - TERREIN | fundering | ALG - TERREIN | 3795.02 | 0.24 | 1.72501 | 1.72501
Isolatie - EPS | fundering | Isolatie - EPS | 27.5476 | 0.0871468 | 0.918254 | 0.918254
Isolatie - EPS | fundering | Isolatie - EPS | 22.6564 | 0.0639266 | 0.755214 | 0.755214
Isolatie - EPS | fundering | Isolatie - EPS | 18.5362 | 0.0639266 | 0.617874 | 0.617874
Beton gewapend C | fundering | Beton gewapend C | 8706.42 | 0.36 | 3.7854 | 3.7854 | Component Quantities - Rectangular Component Height: 600 mm; Rectangular Component Width: 600 mm
ALG - TERREIN | fundering | ALG - TERREIN | 345.84 | 0.24 | 0.1572 | 0.1572
Isolatie - EPS | fundering | Isolatie - EPS | 1.71243 | 0.0871468 | 0.0570812 | 0.0570812
2 x Isolatie - EPS | fundering | Isolatie - EPS | 1.25616 | 0.0639266 | 0.0418719 | 0.0418719
Beton gewapend C | fundering | Beton gewapend C | 542.34 | 0.36 | 0.2358 | 0.2358 | Component Quantities - Rectangular Component Height: 600 mm; Rectangular Component Width: 600 mm
ALG - TERREIN | fundering | ALG - TERREIN | 3635.25 | 0.5425 | 1.65238 | 1.65238
Isolatie - EPS | fundering | Isolatie - EPS | 8.70397 | 0.0871469 | 0.290132 | 0.290132
Isolatie - EPS | fundering | Isolatie - EPS | 6.41503 | 0.0639266 | 0.213834 | 0.213834
Isolatie - EPS | fundering | Isolatie - EPS | 6.32033 | 0.0639266 | 0.210678 | 0.210678
2 x Beton gewapend C | fundering | Beton gewapend C | 2769.66 | 0.36 | 1.2042 | 1.2042 | Component Quantities - Rectangular Component Height: 600 mm; Rectangular Component Width: 600.001 mm
ALG - TERREIN | fundering | ALG - TERREIN | 14217.7 | 0.24 | 6.4626 | 6.4626
Isolatie - EPS | fundering | Isolatie - EPS | 74.568 | 0.0871468 | 2.4856 | 2.4856
Isolatie - EPS | fundering | Isolatie - EPS | 54.8655 | 0.0639266 | 1.82885 | 1.82885
Isolatie - EPS | fundering | Isolatie - EPS | 49.7094 | 0.0639266 | 1.65698 | 1.65698
Beton gewapend C | fundering | Beton gewapend C | 23616.2 | 0.36 | 10.2679 | 10.2679 | Component Quantities - Rectangular Component Height: 600 mm; Rectangular Component Width: 600 mm
ALG - TERREIN | fundering | ALG - TERREIN | 8167.22 | 0.5425 | 3.71237 | 3.71237
Isolatie - EPS | fundering | Isolatie - EPS | 18.6236 | 0.0871469 | 0.620786 | 0.620786
2 x Isolatie - EPS | fundering | Isolatie - EPS | 12.5813 | 0.0639266 | 0.419378 | 0.419378
Beton gewapend C | fundering | Beton gewapend C | 5898.22 | 0.36 | 2.56444 | 2.56444 | Component Quantities - Rectangular Component Height: 600 mm; Rectangular Component Width: 600.001 mm
2 x ALG - TERREIN | fundering | ALG - TERREIN | 4155.85 | 0.5425 | 1.88902 | 1.88902
2 x Isolatie - EPS | fundering | Isolatie - EPS | 11.2419 | 0.0871469 | 0.374732 | 0.374732
4 x Isolatie - EPS | fundering | Isolatie - EPS | 8.38153 | 0.0639266 | 0.279384 | 0.279384
2 x Beton gewapend C | fundering | Beton gewapend C | 3705.3 | 0.36 | 1.611 | 1.611 | Component Quantities - Rectangular Component Height: 600 mm; Rectangular Component Width: 600.001 mm
Beton gewapend prefab vloer | fundering | Beton gewapend prefab vloer | 1061936 |  | 442.473 | 445.124 | Component Quantities - Projected Component Area (Net): 1382.73 m2; Projected Component Area (Gross): 1391.01 m2; Component Thickness: 320 mm
Isolatie - EPS vloer | fundering | Isolatie - EPS vloer | 4977.83 |  | 165.928 | 166.922 | Component Quantities - Projected Component Area (Net): 1382.73 m2; Projected Component Area (Gross): 1391.01 m2; Component Thickness: 120 mm
ALG - TERREIN | fundering | ALG - TERREIN | 17269.8 | 0.24 | 7.84992 | 7.84992
Isolatie - EPS | fundering | Isolatie - EPS | 91.3656 | 0.0871468 | 3.04552 | 3.04552
Isolatie - EPS | fundering | Isolatie - EPS | 68.3614 | 0.0639266 | 2.27871 | 2.27871
Isolatie - EPS | fundering | Isolatie - EPS | 61.3612 | 0.0639266 | 2.04537 | 2.04537
Beton gewapend C | fundering | Beton gewapend C | 28909.6 | 0.36 | 12.5694 | 12.5694 | Component Quantities - Rectangular Component Height: 600 mm; Rectangular Component Width: 600 mm
ALG - TERREIN | fundering | ALG - TERREIN | 957.789 | 0.24 | 0.435358 | 0.435358
Isolatie - EPS | fundering | Isolatie - EPS | 4.74251 | 0.0871468 | 0.158084 | 0.158084
2 x Isolatie - EPS | fundering | Isolatie - EPS | 3.47887 | 0.0639266 | 0.115962 | 0.115962
Beton gewapend C | fundering | Beton gewapend C | 1501.99 | 0.36 | 0.653038 | 0.653038 | Component Quantities - Rectangular Component Height: 600 mm; Rectangular Component Width: 600 mm
2 x ALG - TERREIN | fundering | ALG - TERREIN | 7280.61 | 0.5425 | 3.30937 | 3.30937
2 x Isolatie - EPS | fundering | Isolatie - EPS | 20.8891 | 0.0871469 | 0.696304 | 0.696304
2 x Isolatie - EPS | fundering | Isolatie - EPS | 15.5932 | 0.0639266 | 0.519773 | 0.519773
2 x Isolatie - EPS | fundering | Isolatie - EPS | 13.4332 | 0.0639266 | 0.447773 | 0.447773
2 x Beton gewapend C | fundering | Beton gewapend C | 6905.53 | 0.36 | 3.0024 | 3.0024 | Component Quantities - Rectangular Component Height: 600 mm; Rectangular Component Width: 600.001 mm
Isolatie - EPS | fundering | Isolatie - EPS | 4.92816 | 0.0871469 | 0.164272 | 0.164272
2 x Isolatie - EPS | fundering | Isolatie - EPS | 3.52505 | 0.0639266 | 0.117502 | 0.117502
Beton gewapend C | fundering | Beton gewapend C | 1560.78 | 0.36 | 0.678601 | 0.678601 | Component Quantities - Rectangular Component Height: 600 mm; Rectangular Component Width: 600.001 mm
ALG - TERREIN | fundering | ALG - TERREIN | 228.071 | 0.5425 | 0.103669 | 0.103669
2 x Isolatie - EPS | fundering | Isolatie - EPS | 4.2092 | 0.0871469 | 0.140307 | 0.140307
4 x Isolatie - EPS | fundering | Isolatie - EPS | 3.22265 | 0.0639266 | 0.107422 | 0.107422
2 x Beton gewapend C | fundering | Beton gewapend C | 1477.98 | 0.360001 | 0.642601 | 0.642601 | Component Quantities - Rectangular Component Height: 600 mm; Rectangular Component Width: 600.001 mm
ALG - TERREIN | fundering | ALG - TERREIN | 939.864 | 0.5425 | 0.427211 | 0.427211
Beton gewapend prefab vloer | fundering | Beton gewapend prefab vloer | 80847.7 |  | 33.6866 | 33.6866 | Component Quantities - Projected Component Area (Net): 105.271 m2; Projected Component Area (Gross): 105.271 m2; Component Thickness: 320 mm
Isolatie - EPS vloer | fundering | Isolatie - EPS vloer | 378.974 |  | 12.6325 | 12.6325 | Component Quantities - Projected Component Area (Net): 105.271 m2; Projected Component Area (Gross): 105.271 m2; Component Thickness: 120 mm
ALG - TERREIN | fundering | ALG - TERREIN | 45875.1 | 0.5425 | 20.8523 | 20.8523
Isolatie - EPS | fundering | Isolatie - EPS | 103.421 | 0.0871469 | 3.44736 | 3.44736
Isolatie - EPS | fundering | Isolatie - EPS | 72.7993 | 0.0639266 | 2.42664 | 2.42664
Isolatie - EPS | fundering | Isolatie - EPS | 74.9192 | 0.0639266 | 2.49731 | 2.49731
Beton gewapend C | fundering | Beton gewapend C | 32738.1 | 0.36 | 14.234 | 14.234 | Component Quantities - Rectangular Component Height: 600 mm; Rectangular Component Width: 600.001 mm
ALG - TERREIN | fundering | ALG - TERREIN | 38922.3 | 0.5425 | 17.692 | 17.692
Isolatie - EPS | fundering | Isolatie - EPS | 86.4924 | 0.0871469 | 2.88308 | 2.88308
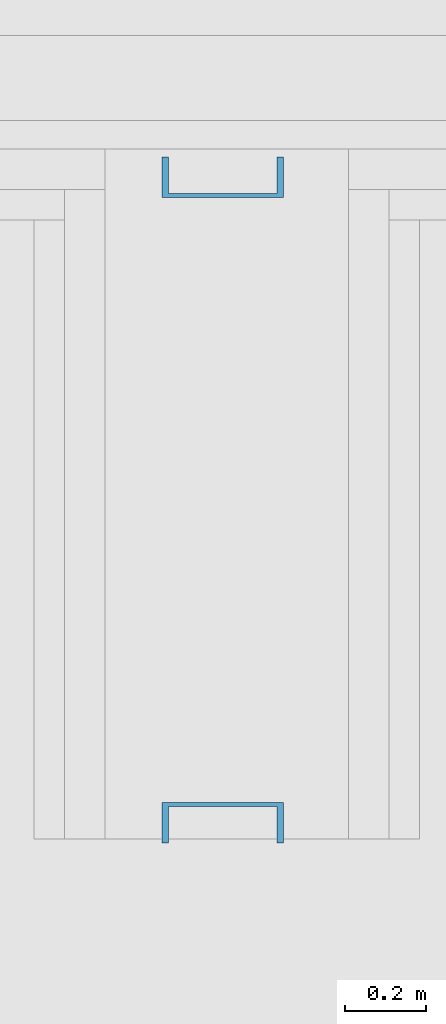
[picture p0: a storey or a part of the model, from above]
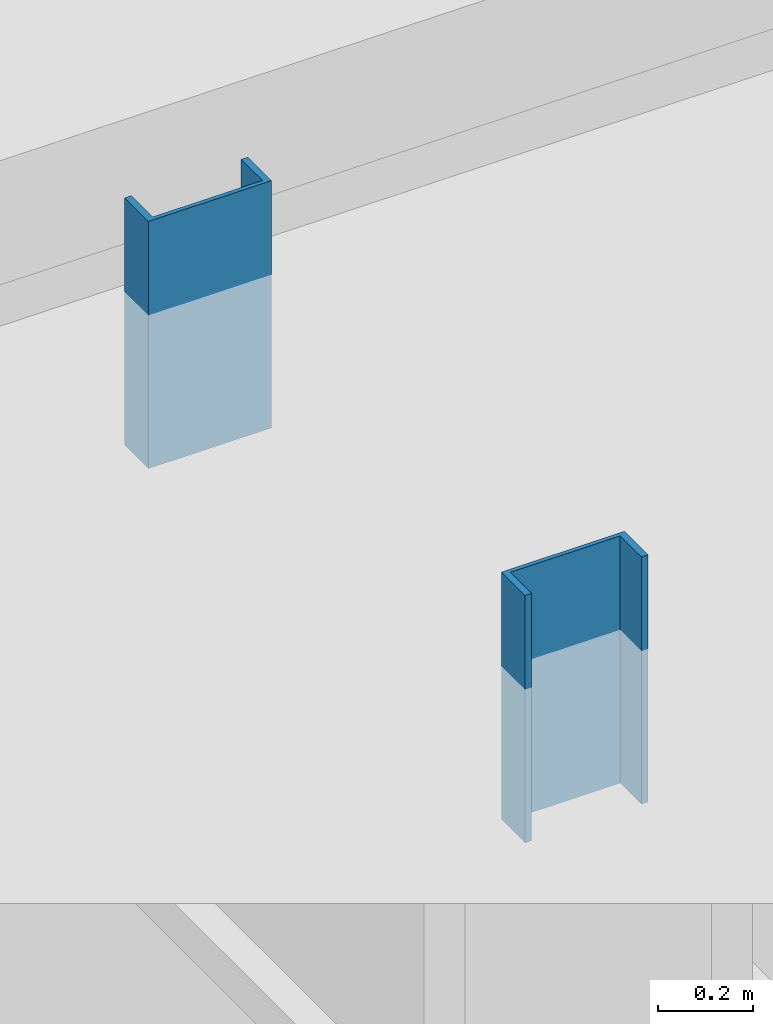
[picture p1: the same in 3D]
Properties of the parts of a building model (IFC2X3), part 2 of 9

# IfcBuildingElementPart (2190)
Name | In | Material | Mass (kg) | Component Cross Section Area (m2) | Component Volume (Net) (m3) | Component Volume (Gross) (m3)
Isolatie - EPS | fundering | Isolatie - EPS | 62.4565 | 0.0639266 | 2.08188 | 2.08188
Isolatie - EPS | fundering | Isolatie - EPS | 59.8956 | 0.0639266 | 1.99652 | 1.99652
Beton gewapend C | fundering | Beton gewapend C | 27331.3 | 0.36 | 11.8832 | 11.8832 | Component Quantities - Rectangular Component Height: 600 mm; Rectangular Component Width: 600.001 mm
ALG - TERREIN | fundering | ALG - TERREIN | 2032.28 | 0.5425 | 0.923763 | 0.923763
Isolatie - EPS | fundering | Isolatie - EPS | 7.90083 | 0.0871469 | 0.263361 | 0.263361
Isolatie - EPS | fundering | Isolatie - EPS | 6.21442 | 0.0639266 | 0.207147 | 0.207147
Isolatie - EPS | fundering | Isolatie - EPS | 4.66252 | 0.0639266 | 0.155417 | 0.155417
ALG - TERREIN | fundering | ALG - TERREIN | 957.792 | 0.24 | 0.43536 | 0.43536
Isolatie - EPS | fundering | Isolatie - EPS | 4.74253 | 0.0871468 | 0.158084 | 0.158084
2 x Isolatie - EPS | fundering | Isolatie - EPS | 3.47889 | 0.0639266 | 0.115963 | 0.115963
Beton gewapend C | fundering | Beton gewapend C | 1501.99 | 0.36 | 0.65304 | 0.65304 | Component Quantities - Rectangular Component Height: 600 mm; Rectangular Component Width: 600 mm
4 x ALG - TERREIN | fundering | ALG - TERREIN | 611.151 | 0.5425 | 0.277796 | 0.277796
3 x Isolatie - EPS | fundering | Isolatie - EPS | 3.15036 | 0.087147 | 0.105012 | 0.105012
8 x Isolatie - EPS | fundering | Isolatie - EPS | 2.44595 | 0.0639266 | 0.0815315 | 0.0815315
3 x Beton gewapend C | fundering | Beton gewapend C | 1142.64 | 0.360001 | 0.496801 | 0.496801 | Component Quantities - Rectangular Component Height: 600 mm; Rectangular Component Width: 600.001 mm
Isolatie - EPS | fundering | Isolatie - EPS | 3.15037 | 0.087147 | 0.105012 | 0.105012
Beton gewapend C | fundering | Beton gewapend C | 1142.64 | 0.360001 | 0.496802 | 0.496802 | Component Quantities - Rectangular Component Height: 600 mm; Rectangular Component Width: 600.002 mm
ALG - TERREIN | fundering | ALG - TERREIN | 1853.56 | 0.5425 | 0.842526 | 0.842526
Isolatie - EPS | fundering | Isolatie - EPS | 4.63947 | 0.0871471 | 0.154649 | 0.154649
2 x Isolatie - EPS | fundering | Isolatie - EPS | 2.63714 | 0.0639266 | 0.0879046 | 0.0879046
Beton gewapend C | fundering | Beton gewapend C | 1639.45 | 0.360002 | 0.712804 | 0.712804 | Component Quantities - Rectangular Component Height: 600 mm; Rectangular Component Width: 600.003 mm
Isolatie - EPS | fundering | Isolatie - EPS | 3.98697 | 0.0871469 | 0.132899 | 0.132899
2 x Isolatie - EPS | fundering | Isolatie - EPS | 3.05964 | 0.0639266 | 0.101988 | 0.101988
Beton gewapend C | fundering | Beton gewapend C | 1407.6 | 0.360001 | 0.612001 | 0.612001 | Component Quantities - Rectangular Component Height: 600 mm; Rectangular Component Width: 600.001 mm
48 vloeivloer Bolidt | begane grond | 48 vloeivloer Bolidt | 0.344441 | 0.0000999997 | 0.000247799 | 0.000247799 | Component Quantities - Rectangular Component Height: 50 mm; Rectangular Component Width: 1.99999 mm
Tegels - Wand | begane grond | Tegels - Wand | 144.865 | 0.0255 | 0.062985 | 0.062985 | Component Quantities - Rectangular Component Height: 2550 mm; Rectangular Component Width: 10 mm
48 vloeivloer Bolidt | begane grond | 48 vloeivloer Bolidt | 0.233241 | 0.0000999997 | 0.0001678 | 0.0001678 | Component Quantities - Rectangular Component Height: 50 mm; Rectangular Component Width: 1.99999 mm
Tegels - Wand | begane grond | Tegels - Wand | 97.9455 | 0.0255 | 0.042585 | 0.042585 | Component Quantities - Rectangular Component Height: 2550 mm; Rectangular Component Width: 10 mm
5 x 32 Hout binnenkozijn | begane grond | 32 Hout binnenkozijn | 3.718 |  | 0.00676 | 0.00676
5 x Membraan - rubber | begane grond | Membraan - rubber | 1.70625 |  | 0.001625 | 0.001625
5 x 32 Hout binnenkozijn oregon pine | begane grond | 32 Hout binnenkozijn oregon pine | 66.6099 |  | 0.121109 | 0.121109
5 x Glas | begane grond | Glas | 108.49 |  | 0.0497659 | 0.0497659
5 x Membraan - rubber | begane grond | Membraan - rubber | 1.02211 |  | 0.000973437 | 0.000973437
7 x  | begane grond |  |  |  | 0.0435626 | 0.0435626
Hout - Multiplex wbp | begane grond | Hout - Multiplex wbp | 152.51 | 0.13662 | 0.217872 | 0.217872 | Component Quantities - Rectangular Component Height: 7590 mm; Rectangular Component Width: 18 mm; Projected Component Area (Net): 12.104 m2; Projected Component Area (Gross): 12.104 m2; Component Thickness: 18 mm
ALG - LICHTE SCHEIDINGSWAND AFW | begane grond | ALG - LICHTE SCHEIDINGSWAND AFW | 116.198 | 0.09108 | 0.145248 | 0.145248 | Component Quantities - Rectangular Component Height: 7590 mm; Rectangular Component Width: 12 mm; Projected Component Area (Net): 12.104 m2; Projected Component Area (Gross): 12.104 m2; Component Thickness: 12 mm
65 x Metaal - Staal C | begane grond | Metaal - Staal C | 10.7325 | 0.003 | 0.00135 | 0.00135 | Component Quantities - Rectangular Component Height: 15 mm; Rectangular Component Width: 200 mm
8 x Metaal - Staal C | begane grond | Metaal - Staal C | 5.47357 | 0.00153 | 0.0006885 | 0.0006885 | Component Quantities - Rectangular Component Height: 170 mm; Rectangular Component Width: 9 mm
2 x Beton gewapend C vloer | begane grond | Beton gewapend C vloer | 2004.07 | 0.0868915 | 0.835027 | 0.835027
4 x Metaal - Staal C | begane grond | Metaal - Staal C | 469.857 | 0.00615 | 0.0591015 | 0.0591015 | Component Quantities - Rectangular Component Height: 20.5 mm; Rectangular Component Width: 300 mm
2 x Metaal - Staal C | begane grond | Metaal - Staal C | 245.128 | 0.0032085 | 0.0308337 | 0.0308337 | Component Quantities - Rectangular Component Height: 279 mm; Rectangular Component Width: 11.5 mm
2 x Metaal - Staal C | begane grond | Metaal - Staal C | 649.396 | 0.0085 | 0.081685 | 0.081685 | Component Quantities - Rectangular Component Height: 20 mm; Rectangular Component Width: 425 mm
Metaal - Staal C | begane grond | Metaal - Staal C | 9.47441 | 0.003 | 0.00119175 | 0.00119175 | Component Quantities - Rectangular Component Height: 15 mm; Rectangular Component Width: 200 mm
Metaal - Staal C | begane grond | Metaal - Staal C | 8.3475 | 0.003 | 0.00105 | 0.00105 | Component Quantities - Rectangular Component Height: 15 mm; Rectangular Component Width: 200 mm
Metaal - Staal C | begane grond | Metaal - Staal C | 5.41884 | 0.00153 | 0.000681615 | 0.000681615 | Component Quantities - Rectangular Component Height: 170 mm; Rectangular Component Width: 9 mm
24 x Metaal - Staal C | begane grond | Metaal - Staal C | 5.47358 | 0.00153 | 0.0006885 | 0.0006885 | Component Quantities - Rectangular Component Height: 170 mm; Rectangular Component Width: 9 mm
2 x Glas | begane grond | Glas | 89.3759 | 0.01635 | 0.0409981 | 0.0503021 | Component Quantities - Rectangular Component Height: 1090 mm; Rectangular Component Width: 15 mm
2 x Membraan - rubber | begane grond | Membraan - rubber | 9.29591 | 0.00265 | 0.00885324 | 0.00885324
2 x Metaal - Staal C wit | begane grond | Metaal - Staal C wit | 53.6013 | 0.002 | 0.0067423 | 0.0067423 | Component Quantities - Rectangular Component Height: 200 mm; Rectangular Component Width: 10 mm
2 x Metaal - Staal C wit | begane grond | Metaal - Staal C wit | 40.0825 | 0.0015 | 0.00504182 | 0.00504182 | Component Quantities - Rectangular Component Height: 150 mm; Rectangular Component Width: 10 mm
2 x Metaal - Staal C wit | begane grond | Metaal - Staal C wit | 11.9275 | 0.000444 | 0.00150032 | 0.00150032
Beton gewapend C vloer | begane grond | Beton gewapend C vloer | 2974.48 | 0.0932915 | 1.23937 | 1.23937
Metaal - Staal C | begane grond | Metaal - Staal C | 629.828 | 0.00615 | 0.0792236 | 0.0792236 | Component Quantities - Rectangular Component Height: 20.5 mm; Rectangular Component Width: 300 mm
Metaal - Staal C | begane grond | Metaal - Staal C | 338.314 | 0.0032085 | 0.0425552 | 0.0425552 | Component Quantities - Rectangular Component Height: 279 mm; Rectangular Component Width: 11.5 mm
Metaal - Staal C | begane grond | Metaal - Staal C | 650.377 | 0.00615 | 0.0818084 | 0.0818084 | Component Quantities - Rectangular Component Height: 20.5 mm; Rectangular Component Width: 300 mm
Metaal - Staal C | begane grond | Metaal - Staal C | 1163.92 | 0.011 | 0.146405 | 0.146405 | Component Quantities - Rectangular Component Height: 20 mm; Rectangular Component Width: 550 mm
Metaal - Staal C | begane grond | Metaal - Staal C | 230.731 | 0.00534071 | 0.0290228 | 0.0290228
Metaal - Staal C | begane grond | Metaal - Staal C | 47.6602 | 0.0011 | 0.005995 | 0.005995 | Component Quantities - Rectangular Component Height: 10 mm; Rectangular Component Width: 110 mm
48 vloeivloer Bolidt | begane grond | 48 vloeivloer Bolidt | 0.170136 | 0.0000999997 | 0.0001224 | 0.0001224 | Component Quantities - Rectangular Component Height: 50 mm; Rectangular Component Width: 1.99999 mm
Tegels - Wand | begane grond | Tegels - Wand | 71.3184 | 0.0255 | 0.031008 | 0.031008 | Component Quantities - Rectangular Component Height: 2550 mm; Rectangular Component Width: 10 mm
2 x Glas | begane grond | Glas | 58.6287 |  | 0.0268939 | 0.0268939
2 x Metaal - Aluminium | begane grond | Metaal - Aluminium | 1.45688 |  | 0.000520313 | 0.000520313
2 x 32 Hout binnenkozijn oregon pine | begane grond | 32 Hout binnenkozijn oregon pine | 54.3715 |  | 0.0988573 | 0.0988573
13 x  | begane grond |  |  |  | 0.0699171 | 0.0699171
3 x Hout C | begane grond | Hout C | 23.4225 |  | 0.0425863 | 0.0425863
3 x Glas | begane grond | Glas | 56.4052 |  | 0.0258739 | 0.0258739
2 x Hout AFW | begane grond | Hout AFW | 2.50688 |  | 0.00455797 | 0.00455797
2 x Metaal - RVS | begane grond | Metaal - RVS | 0.394685 |  | 0.0000499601 | 0.0000499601
2 x Hout AFW | begane grond | Hout AFW | 0.537224 |  | 0.000976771 | 0.000976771
4 x Metaal - RVS | begane grond | Metaal - RVS | 0.129093 |  | 0.0000163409 | 0.0000163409
2 x Hout AFW | begane grond | Hout AFW | 4.6339 |  | 0.00842527 | 0.00842527
2 x Metaal - RVS | begane grond | Metaal - RVS | 0.78937 |  | 0.0000999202 | 0.0000999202
Hout AFW | begane grond | Hout AFW | 0.770311 |  | 0.00140057 | 0.00140057
2 x Glas | begane grond | Glas | 69.9755 | 0.013223 | 0.0320989 | 0.0320989 | Component Quantities - Rectangular Component Height: 881.534 mm; Rectangular Component Width: 15 mm
2 x Membraan - rubber | begane grond | Membraan - rubber | 6.7531 | 0.00265 | 0.00643152 | 0.00643152
2 x Metaal - Staal C wit | begane grond | Metaal - Staal C wit | 38.5973 | 0.002 | 0.004855 | 0.004855 | Component Quantities - Rectangular Component Height: 200 mm; Rectangular Component Width: 10 mm
2 x Metaal - Staal C wit | begane grond | Metaal - Staal C wit | 28.9479 | 0.0015 | 0.00364125 | 0.00364125 | Component Quantities - Rectangular Component Height: 150 mm; Rectangular Component Width: 10 mm
2 x Metaal - Staal C wit | begane grond | Metaal - Staal C wit | 8.56859 | 0.000444 | 0.00107781 | 0.00107781
Hout - Multiplex wbp | begane grond | Hout - Multiplex wbp | 227.482 | 0.13662 | 0.324974 | 0.324974 | Component Quantities - Rectangular Component Height: 7590 mm; Rectangular Component Width: 18 mm; Projected Component Area (Net): 18.0541 m2; Projected Component Area (Gross): 18.0541 m2; Component Thickness: 18 mm
ALG - LICHTE SCHEIDINGSWAND AFW | begane grond | ALG - LICHTE SCHEIDINGSWAND AFW | 173.319 | 0.09108 | 0.216649 | 0.216649 | Component Quantities - Rectangular Component Height: 7590 mm; Rectangular Component Width: 12 mm; Projected Component Area (Net): 18.0541 m2; Projected Component Area (Gross): 18.0541 m2; Component Thickness: 12 mm
3 x Glas sticker | begane grond | Glas sticker | 16.2767 |  | 0.00746636 | 0.00746636
3 x Hout C | begane grond | Hout C | 47.7772 |  | 0.0868676 | 0.0868676
5 x Glas sticker | begane grond | Glas sticker | 24.9117 |  | 0.0114274 | 0.0114274
5 x Hout C | begane grond | Hout C | 45.5986 |  | 0.0829066 | 0.0829066
48 vloeivloer Bolidt | begane grond | 48 vloeivloer Bolidt | 0.0707508 | 0.0000999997 | 0.0000508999 | 0.0000508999 | Component Quantities - Rectangular Component Height: 50 mm; Rectangular Component Width: 1.99999 mm
Tegels - Wand | begane grond | Tegels - Wand | 29.8528 | 0.0255 | 0.0129795 | 0.0129795 | Component Quantities - Rectangular Component Height: 2550 mm; Rectangular Component Width: 10 mm
48 vloeivloer Bolidt | begane grond | 48 vloeivloer Bolidt | 0.126212 | 0.0000999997 | 0.0000907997 | 0.0000907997 | Component Quantities - Rectangular Component Height: 50 mm; Rectangular Component Width: 1.99999 mm
Tegels - Wand | begane grond | Tegels - Wand | 52.785 | 0.0255 | 0.02295 | 0.02295 | Component Quantities - Rectangular Component Height: 2550 mm; Rectangular Component Width: 10 mm
Kunststof Kupan | begane grond | Kunststof Kupan | 43.9806 | 0.0273 | 0.0316407 | 0.0971607 | Component Quantities - Rectangular Component Height: 2100 mm; Rectangular Component Width: 13 mm
Metaal - Aluminium | begane grond | Metaal - Aluminium | 9.9932 | 0.001 | 0.003569 | 0.003569 | Component Quantities - Rectangular Component Height: 50 mm; Rectangular Component Width: 20 mm
Hout - Multiplex wbp | begane grond | Hout - Multiplex wbp | 130.637 | 0.05184 | 0.186624 | 0.186624 | Component Quantities - Rectangular Component Height: 2880 mm; Rectangular Component Width: 18 mm; Projected Component Area (Net): 10.368 m2; Projected Component Area (Gross): 10.368 m2; Component Thickness: 18 mm
ALG - LICHTE SCHEIDINGSWAND AFW | begane grond | ALG - LICHTE SCHEIDINGSWAND AFW | 99.5328 | 0.03456 | 0.124416 | 0.124416 | Component Quantities - Rectangular Component Height: 2880 mm; Rectangular Component Width: 12 mm; Projected Component Area (Net): 10.368 m2; Projected Component Area (Gross): 10.368 m2; Component Thickness: 12 mm
2 x 48 vloeivloer Bolidt | begane grond | 48 vloeivloer Bolidt | 0.198213 | 0.0000999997 | 0.0001426 | 0.0001426 | Component Quantities - Rectangular Component Height: 50 mm; Rectangular Component Width: 1.99999 mm
2 x Tegels - Wand | begane grond | Tegels - Wand | 83.6349 | 0.0255 | 0.036363 | 0.036363 | Component Quantities - Rectangular Component Height: 2550 mm; Rectangular Component Width: 10 mm
2 x 48 vloeivloer Bolidt | begane grond | 48 vloeivloer Bolidt | 0.340549 | 0.0000999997 | 0.000244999 | 0.000244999 | Component Quantities - Rectangular Component Height: 50 mm; Rectangular Component Width: 1.99999 mm
Tegels - Wand | begane grond | Tegels - Wand | 143.67 | 0.0255 | 0.062465 | 0.062465 | Component Quantities - Rectangular Component Height: 2550 mm; Rectangular Component Width: 10 mm
48 vloeivloer Bolidt | begane grond | 48 vloeivloer Bolidt | 0.497341 | 0.0000999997 | 0.000357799 | 0.000357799 | Component Quantities - Rectangular Component Height: 50 mm; Rectangular Component Width: 1.99999 mm
Tegels - Wand | begane grond | Tegels - Wand | 209.381 | 0.0255 | 0.091035 | 0.091035 | Component Quantities - Rectangular Component Height: 2550 mm; Rectangular Component Width: 10 mm
2 x 48 vloeivloer Bolidt | begane grond | 48 vloeivloer Bolidt | 0.339993 | 0.0000999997 | 0.000244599 | 0.000244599 | Component Quantities - Rectangular Component Height: 50 mm; Rectangular Component Width: 1.99999 mm
2 x Tegels - Wand | begane grond | Tegels - Wand | 142.52 | 0.0255 | 0.061965 | 0.061965 | Component Quantities - Rectangular Component Height: 2550 mm; Rectangular Component Width: 10 mm
Metaal - Staal C | begane grond | Metaal - Staal C | 90.4285 | 0.003 | 0.0113747 | 0.0113747 | Component Quantities - Rectangular Component Height: 15 mm; Rectangular Component Width: 200 mm
Metaal - Staal C | begane grond | Metaal - Staal C | 93.8689 | 0.003 | 0.0118074 | 0.0118074 | Component Quantities - Rectangular Component Height: 15 mm; Rectangular Component Width: 200 mm
Metaal - Staal C | begane grond | Metaal - Staal C | 46.1753 | 0.00153 | 0.00580821 | 0.00580821 | Component Quantities - Rectangular Component Height: 170 mm; Rectangular Component Width: 9 mm
48 vloeivloer Bolidt | begane grond | 48 vloeivloer Bolidt | 0.151232 | 0.0000999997 | 0.0001088 | 0.0001088 | Component Quantities - Rectangular Component Height: 50 mm; Rectangular Component Width: 1.99999 mm
Tegels - Wand | begane grond | Tegels - Wand | 63.342 | 0.0255 | 0.02754 | 0.02754 | Component Quantities - Rectangular Component Height: 2550 mm; Rectangular Component Width: 10 mm
ALG - LICHTE SCHEIDINGSWAND AFW | begane grond | ALG - LICHTE SCHEIDINGSWAND AFW | 74.1605 | 0.04356 | 0.0927006 | 0.0927006 | Component Quantities - Rectangular Component Height: 3630 mm; Rectangular Component Width: 12 mm; Projected Component Area (Net): 7.73189 m2; Projected Component Area (Gross): 7.73189 m2; Component Thickness: 12 mm
Hout - Multiplex wbp | begane grond | Hout - Multiplex wbp | 97.6426 | 0.06534 | 0.139489 | 0.139489 | Component Quantities - Rectangular Component Height: 3630 mm; Rectangular Component Width: 18 mm; Projected Component Area (Net): 7.76782 m2; Projected Component Area (Gross): 7.76782 m2; Component Thickness: 18 mm
Kunststof Kupan | begane grond | Kunststof Kupan | 21.1744 | 0.0273 | 0.0152334 | 0.0479934 | Component Quantities - Rectangular Component Height: 2100 mm; Rectangular Component Width: 13 mm
Metaal - Aluminium | begane grond | Metaal - Aluminium | 4.9224 | 0.001 | 0.001758 | 0.001758 | Component Quantities - Rectangular Component Height: 50 mm; Rectangular Component Width: 20 mm
ALG - LICHTE SCHEIDINGSWAND AFW | begane grond | ALG - LICHTE SCHEIDINGSWAND AFW | 34.6886 | 0.04356 | 0.0433608 | 0.0433608 | Component Quantities - Rectangular Component Height: 3630 mm; Rectangular Component Width: 12 mm; Projected Component Area (Net): 3.6134 m2; Projected Component Area (Gross): 3.6134 m2; Component Thickness: 12 mm
Hout - Multiplex wbp | begane grond | Hout - Multiplex wbp | 44.9906 | 0.06534 | 0.0642722 | 0.0642722 | Component Quantities - Rectangular Component Height: 3630 mm; Rectangular Component Width: 18 mm; Projected Component Area (Net): 3.57068 m2; Projected Component Area (Gross): 3.57068 m2; Component Thickness: 18 mm
ALG - LICHTE SCHEIDINGSWAND AFW | begane grond | ALG - LICHTE SCHEIDINGSWAND AFW | 39.1315 | 0.04356 | 0.0489144 | 0.0489144 | Component Quantities - Rectangular Component Height: 3630 mm; Rectangular Component Width: 12 mm; Projected Component Area (Net): 4.0762 m2; Projected Component Area (Gross): 4.0762 m2; Component Thickness: 12 mm
Hout - Multiplex wbp | begane grond | Hout - Multiplex wbp | 51.3601 | 0.06534 | 0.0733716 | 0.0733716 | Component Quantities - Rectangular Component Height: 3630 mm; Rectangular Component Width: 18 mm; Projected Component Area (Net): 4.0762 m2; Projected Component Area (Gross): 4.0762 m2; Component Thickness: 18 mm
48 vloeivloer Bolidt | begane grond | 48 vloeivloer Bolidt | 0.233519 | 0.0000999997 | 0.000168 | 0.000168 | Component Quantities - Rectangular Component Height: 50 mm; Rectangular Component Width: 1.99999 mm
Tegels - Wand | begane grond | Tegels - Wand | 98.532 | 0.0255 | 0.04284 | 0.04284 | Component Quantities - Rectangular Component Height: 2550 mm; Rectangular Component Width: 10 mm
ALG - LICHTE SCHEIDINGSWAND AFW | begane grond | ALG - LICHTE SCHEIDINGSWAND AFW | 41.5526 | 0.04356 | 0.0519408 | 0.0519408 | Component Quantities - Rectangular Component Height: 3630 mm; Rectangular Component Width: 12 mm; Projected Component Area (Net): 4.3284 m2; Projected Component Area (Gross): 4.3284 m2; Component Thickness: 12 mm
Hout - Multiplex wbp | begane grond | Hout - Multiplex wbp | 54.5378 | 0.06534 | 0.0779112 | 0.0779112 | Component Quantities - Rectangular Component Height: 3630 mm; Rectangular Component Width: 18 mm; Projected Component Area (Net): 4.3284 m2; Projected Component Area (Gross): 4.3284 m2; Component Thickness: 18 mm
ALG - LICHTE SCHEIDINGSWAND AFW | begane grond | ALG - LICHTE SCHEIDINGSWAND AFW | 102.528 | 0.04272 | 0.12816 | 0.12816 | Component Quantities - Rectangular Component Height: 3560 mm; Rectangular Component Width: 12 mm; Projected Component Area (Net): 10.68 m2; Projected Component Area (Gross): 10.68 m2; Component Thickness: 12 mm
Hout - Multiplex wbp | begane grond | Hout - Multiplex wbp | 134.568 | 0.06408 | 0.19224 | 0.19224 | Component Quantities - Rectangular Component Height: 3560 mm; Rectangular Component Width: 18 mm; Projected Component Area (Net): 10.68 m2; Projected Component Area (Gross): 10.68 m2; Component Thickness: 18 mm
Tegels - Wand | begane grond | Tegels - Wand | 162.461 | 0.0255 | 0.070635 | 0.070635 | Component Quantities - Rectangular Component Height: 2550 mm; Rectangular Component Width: 10 mm
48 vloeivloer Bolidt | begane grond | 48 vloeivloer Bolidt | 0.386141 | 0.0000999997 | 0.000277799 | 0.000277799 | Component Quantities - Rectangular Component Height: 50 mm; Rectangular Component Width: 1.99999 mm
6 x Membraan - rubber | begane grond | Membraan - rubber | 1.2222 | 0.00015 | 0.001164 | 0.001164 | Component Quantities - Rectangular Component Height: 10 mm; Rectangular Component Width: 15 mm
6 x Membraan - rubber | begane grond | Membraan - rubber | 0.6111 | 0.000075 | 0.000582 | 0.000582 | Component Quantities - Rectangular Component Height: 5 mm; Rectangular Component Width: 15 mm
6 x Membraan - rubber | begane grond | Membraan - rubber | 3.70734 | 0.000455 | 0.0035308 | 0.0035308 | Component Quantities - Rectangular Component Height: 35 mm; Rectangular Component Width: 13 mm
4 x Metaal - Aluminium | begane grond | Metaal - Aluminium | 186.592 | 0.0085 | 0.06664 | 0.06664
5 x Metaal - Aluminium | begane grond | Metaal - Aluminium | 16.464 | 0.00075 | 0.00588 | 0.00588 | Component Quantities - Rectangular Component Height: 15 mm; Rectangular Component Width: 50 mm
Hout AFW | begane grond | Hout AFW | 0.764703 |  | 0.00139037 | 0.00139037
4 x Metaal - Staal C | begane grond | Metaal - Staal C | 1585.44 | 0.0057 | 0.199426 | 0.199426 | Component Quantities - Rectangular Component Height: 19 mm; Rectangular Component Width: 300 mm
2 x Metaal - Staal C | begane grond | Metaal - Staal C | 801.619 | 0.002882 | 0.100833 | 0.100833 | Component Quantities - Rectangular Component Height: 262 mm; Rectangular Component Width: 11 mm
Steen - Baksteen | begane grond | Steen - Baksteen | 385.051 | 0.3031 | 0.240657 | 0.240657 | Component Quantities - Rectangular Component Height: 4330 mm; Rectangular Component Width: 70.0001 mm
Isolatie - Kunststof hard | begane grond | Isolatie - Kunststof hard | 39.6445 | 0.6062 | 0.396445 | 0.396445 | Component Quantities - Rectangular Component Height: 4330 mm; Rectangular Component Width: 140 mm
Membraan - rubber | begane grond | Membraan - rubber | 0.77175 | 0.00015 | 0.000735 | 0.000735 | Component Quantities - Rectangular Component Height: 10 mm; Rectangular Component Width: 15 mm
Membraan - rubber | begane grond | Membraan - rubber | 0.77805 | 0.00015 | 0.000741 | 0.000741 | Component Quantities - Rectangular Component Height: 10 mm; Rectangular Component Width: 15 mm
Membraan - rubber | begane grond | Membraan - rubber | 0.617139 | 0.000075 | 0.000587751 | 0.000587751 | Component Quantities - Rectangular Component Height: 5 mm; Rectangular Component Width: 15 mm
Membraan - rubber | begane grond | Membraan - rubber | 0.6132 | 0.000075 | 0.000584 | 0.000584 | Component Quantities - Rectangular Component Height: 5 mm; Rectangular Component Width: 15 mm
Membraan - rubber | begane grond | Membraan - rubber | 2.286 | 0.000455 | 0.00217714 | 0.00217714 | Component Quantities - Rectangular Component Height: 35 mm; Rectangular Component Width: 13 mm
Membraan - rubber | begane grond | Membraan - rubber | 2.3033 | 0.000455 | 0.00219362 | 0.00219362 | Component Quantities - Rectangular Component Height: 35 mm; Rectangular Component Width: 13 mm
Metaal - Aluminium | begane grond | Metaal - Aluminium | 186.034 | 0.0085 | 0.0664408 | 0.0664408
3 x Metaal - Aluminium | begane grond | Metaal - Aluminium | 8.3328 | 0.0006 | 0.002976 | 0.002976 | Component Quantities - Rectangular Component Height: 50 mm; Rectangular Component Width: 12 mm
Metaal - Aluminium | begane grond | Metaal - Aluminium | 6.3336 | 0.0006 | 0.002262 | 0.002976 | Component Quantities - Rectangular Component Height: 50 mm; Rectangular Component Width: 12 mm
2 x Membraan - rubber | begane grond | Membraan - rubber | 0.296888 | 0.000075 | 0.00028275 | 0.000372 | Component Quantities - Rectangular Component Height: 15 mm; Rectangular Component Width: 5 mm
6 x Membraan - rubber | begane grond | Membraan - rubber | 0.3906 | 0.000075 | 0.000372 | 0.000372 | Component Quantities - Rectangular Component Height: 15 mm; Rectangular Component Width: 5 mm
4 x Membraan - rubber | begane grond | Membraan - rubber | 2.37633 | 0.000455 | 0.00226317 | 0.00226317 | Component Quantities - Rectangular Component Height: 13 mm; Rectangular Component Width: 35 mm
2 x Membraan - rubber | begane grond | Membraan - rubber | 1.8059 | 0.000455 | 0.0017199 | 0.00226307 | Component Quantities - Rectangular Component Height: 13 mm; Rectangular Component Width: 35 mm
Glas | begane grond | Glas | 945.516 | 0.10864 | 0.433723 | 0.54035
Glas | begane grond | Glas | 468.323 | 0.04319 | 0.214827 | 0.214827
2 x Membraan - rubber | begane grond | Membraan - rubber | 2.37622 | 0.000455 | 0.00226307 | 0.00226307 | Component Quantities - Rectangular Component Height: 13 mm; Rectangular Component Width: 35 mm
Glas | begane grond | Glas | 1257.69 | 0.11599 | 0.57692 | 0.57692
6 x Membraan - rubber | begane grond | Membraan - rubber | 0.7812 | 0.00015 | 0.000744 | 0.000744 | Component Quantities - Rectangular Component Height: 15 mm; Rectangular Component Width: 10 mm
2 x Membraan - rubber | begane grond | Membraan - rubber | 0.593775 | 0.00015 | 0.0005655 | 0.000744 | Component Quantities - Rectangular Component Height: 15 mm; Rectangular Component Width: 10 mm
Isolatie - EPS | begane grond | Isolatie - EPS | 7.68936 | 0.051 | 0.256312 | 0.26112 | Component Quantities - Rectangular Component Height: 510 mm; Rectangular Component Width: 100 mm
Metaal - Aluminium | begane grond | Metaal - Aluminium | 45.4147 | 0.00325 | 0.0162195 | 0.0162195
Metaal - Aluminium | begane grond | Metaal - Aluminium | 45.416 | 0.00325 | 0.01622 | 0.01622
Metaal - Aluminium | begane grond | Metaal - Aluminium | 89.9724 | 0.0085 | 0.032133 | 0.0422595
Metaal - Aluminium | begane grond | Metaal - Aluminium | 118.328 | 0.0085 | 0.04226 | 0.04226
2 x Membraan - rubber | begane grond | Membraan - rubber | 1.2348 | 0.00015 | 0.001176 | 0.001176 | Component Quantities - Rectangular Component Height: 10 mm; Rectangular Component Width: 15 mm
2 x Membraan - rubber | begane grond | Membraan - rubber | 0.6174 | 0.000075 | 0.000588 | 0.000588 | Component Quantities - Rectangular Component Height: 5 mm; Rectangular Component Width: 15 mm
Membraan - rubber | begane grond | Membraan - rubber | 3.6582 | 0.000455 | 0.003484 | 0.003484 | Component Quantities - Rectangular Component Height: 35 mm; Rectangular Component Width: 13 mm
Membraan - rubber | begane grond | Membraan - rubber | 3.74556 | 0.000455 | 0.0035672 | 0.0035672 | Component Quantities - Rectangular Component Height: 35 mm; Rectangular Component Width: 13 mm
Isolatie - Kunststof hard | begane grond | Isolatie - Kunststof hard | 272.656 | 0.6146 | 2.72656 | 3.28196 | Component Quantities - Rectangular Component Height: 4390 mm; Rectangular Component Width: 140 mm
Steen - Baksteen | begane grond | Steen - Baksteen | 2250.08 | 0.3073 | 1.4063 | 1.68401 | Component Quantities - Rectangular Component Height: 4390 mm; Rectangular Component Width: 70.0001 mm
36 x Hout - Lockers | begane grond | Hout - Lockers | 1.21032 | 0.112001 | 0.0020172 | 0.0020172
120 x Hout - Lockers | begane grond | Hout - Lockers | 1.17407 | 0.108644 | 0.00195678 | 0.00195678
18 x Hout - Lockers | begane grond | Hout - Lockers | 1.18087 | 0.109274 | 0.00196812 | 0.00196812
60 x Hout - Lockers | begane grond | Hout - Lockers | 1.14549 | 0.105998 | 0.00190915 | 0.00190915
Metaal - Staal C | begane grond | Metaal - Staal C | 905.373 | 0.0057 | 0.113883 | 0.113883 | Component Quantities - Rectangular Component Height: 19 mm; Rectangular Component Width: 300 mm
Metaal - Staal C | begane grond | Metaal - Staal C | 911.738 | 0.0057 | 0.114684 | 0.114684 | Component Quantities - Rectangular Component Height: 19 mm; Rectangular Component Width: 300 mm
Metaal - Staal C | begane grond | Metaal - Staal C | 457.701 | 0.002882 | 0.0575725 | 0.0575725 | Component Quantities - Rectangular Component Height: 262 mm; Rectangular Component Width: 11 mm
48 vloeivloer Bolidt | begane grond | 48 vloeivloer Bolidt | 0.0261319 | 0.0000999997 | 0.0000187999 | 0.0000187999 | Component Quantities - Rectangular Component Height: 50 mm; Rectangular Component Width: 1.99999 mm
Tegels - Wand | begane grond | Tegels - Wand | 10.557 | 0.0255 | 0.00459 | 0.00459 | Component Quantities - Rectangular Component Height: 2550 mm; Rectangular Component Width: 10 mm
Beton gewapend C vloer | begane grond | Beton gewapend C vloer | 4504.19 | 0.0932915 | 1.87675 | 1.87675
2 x Metaal - Staal C | begane grond | Metaal - Staal C | 983.57 | 0.00615 | 0.12372 | 0.12372 | Component Quantities - Rectangular Component Height: 20.5 mm; Rectangular Component Width: 300 mm
Metaal - Staal C | begane grond | Metaal - Staal C | 513.136 | 0.0032085 | 0.0645454 | 0.0645454 | Component Quantities - Rectangular Component Height: 279 mm; Rectangular Component Width: 11.5 mm
Metaal - Staal C | begane grond | Metaal - Staal C | 1759.23 | 0.011 | 0.221287 | 0.221287 | Component Quantities - Rectangular Component Height: 20 mm; Rectangular Component Width: 550 mm
Metaal - Staal C | begane grond | Metaal - Staal C | 604.128 | 0.0057 | 0.0759909 | 0.0759909 | Component Quantities - Rectangular Component Height: 19 mm; Rectangular Component Width: 300 mm
Metaal - Staal C | begane grond | Metaal - Staal C | 614.245 | 0.0057 | 0.0772635 | 0.0772635 | Component Quantities - Rectangular Component Height: 19 mm; Rectangular Component Width: 300 mm
Metaal - Staal C | begane grond | Metaal - Staal C | 309.978 | 0.002882 | 0.0389909 | 0.0389909 | Component Quantities - Rectangular Component Height: 262 mm; Rectangular Component Width: 11 mm
Beton gewapend C vloer | begane grond | Beton gewapend C vloer | 1106.83 | 0.0932915 | 0.46118 | 0.46118
2 x Metaal - Staal C | begane grond | Metaal - Staal C | 242.507 | 0.00615 | 0.030504 | 0.030504 | Component Quantities - Rectangular Component Height: 20.5 mm; Rectangular Component Width: 300 mm
Metaal - Staal C | begane grond | Metaal - Staal C | 126.518 | 0.0032085 | 0.0159142 | 0.0159142 | Component Quantities - Rectangular Component Height: 279 mm; Rectangular Component Width: 11.5 mm
Metaal - Staal C | begane grond | Metaal - Staal C | 433.752 | 0.011 | 0.05456 | 0.05456 | Component Quantities - Rectangular Component Height: 20 mm; Rectangular Component Width: 550 mm
Metaal - Staal C | begane grond | Metaal - Staal C | 1793.65 | 0.0057 | 0.225616 | 0.225616 | Component Quantities - Rectangular Component Height: 19 mm; Rectangular Component Width: 300 mm
Metaal - Staal C | begane grond | Metaal - Staal C | 1803.76 | 0.0057 | 0.226889 | 0.226889 | Component Quantities - Rectangular Component Height: 19 mm; Rectangular Component Width: 300 mm
Metaal - Staal C | begane grond | Metaal - Staal C | 911.415 | 0.002882 | 0.114643 | 0.114643 | Component Quantities - Rectangular Component Height: 262 mm; Rectangular Component Width: 11 mm
Steen - Kalkzandsteen C | begane grond | Steen - Kalkzandsteen C | 16772 | 0.594 | 8.82737 | 15.6469 | Component Quantities - Rectangular Component Height: 3960 mm; Rectangular Component Width: 150 mm
Isolatie - Kunststof hard | begane grond | Isolatie - Kunststof hard | 1126.89 | 0.611 | 11.2689 | 17.7037
24 Hout gevelbekleding Lariks | begane grond | 24 Hout gevelbekleding Lariks | 186.392 | 0.0475 | 0.286758 | 1.38462 | Component Quantities - Rectangular Component Height: 1900 mm; Rectangular Component Width: 25 mm
Steen - Baksteen | begane grond | Steen - Baksteen | 4183.97 | 0.0896001 | 2.61498 | 2.61498 | Component Quantities - Rectangular Component Height: 1280 mm; Rectangular Component Width: 70.0001 mm
Steen - Baksteen | begane grond | Steen - Baksteen | 3549.03 | 0.08155 | 2.21814 | 2.38004 | Component Quantities - Rectangular Component Height: 1165 mm; Rectangular Component Width: 70 mm
Steen - Kalkzandsteen C | begane grond | Steen - Kalkzandsteen C | 4850.97 | 0.594 | 2.55314 | 7.76701 | Component Quantities - Rectangular Component Height: 3960 mm; Rectangular Component Width: 150 mm
Isolatie - Kunststof hard | begane grond | Isolatie - Kunststof hard | 711.777 | 0.611 | 7.11777 | 8.90795
24 Hout gevelbekleding Lariks | begane grond | 24 Hout gevelbekleding Lariks | 242.369 | 0.0475 | 0.372875 | 0.698249 | Component Quantities - Rectangular Component Height: 1900 mm; Rectangular Component Width: 25 mm
Steen - Baksteen | begane grond | Steen - Baksteen | 2130.33 | 0.0896001 | 1.33146 | 1.33146 | Component Quantities - Rectangular Component Height: 1280 mm; Rectangular Component Width: 70.0001 mm
Steen - Baksteen | begane grond | Steen - Baksteen | 1938.93 | 0.08155 | 1.21183 | 1.21183 | Component Quantities - Rectangular Component Height: 1165 mm; Rectangular Component Width: 70 mm
2 x Metaal - Staal C | begane grond | Metaal - Staal C | 477.477 | 0.0042 | 0.06006 | 0.06006 | Component Quantities - Rectangular Component Height: 15 mm; Rectangular Component Width: 280 mm
Metaal - Staal C | begane grond | Metaal - Staal C | 298.423 | 0.002625 | 0.0375375 | 0.0375375 | Component Quantities - Rectangular Component Height: 250 mm; Rectangular Component Width: 10.5 mm
Steen - Kalkzandsteen C | begane grond | Steen - Kalkzandsteen C | 1681.14 | 0.546 | 0.884812 | 0.884812 | Component Quantities - Rectangular Component Height: 3640 mm; Rectangular Component Width: 150 mm
Isolatie - Kunststof hard | begane grond | Isolatie - Kunststof hard | 81.7895 | 0.511 | 0.817895 | 0.817895 | Component Quantities - Rectangular Component Height: 3650 mm; Rectangular Component Width: 140 mm
24 Hout gevelbekleding Lariks | begane grond | 24 Hout gevelbekleding Lariks | 84.4999 | 0.0799999 | 0.13 | 0.13 | Component Quantities - Rectangular Component Height: 3200 mm; Rectangular Component Width: 25 mm
Steen - Kalkzandsteen C | begane grond | Steen - Kalkzandsteen C | 1466.47 | 0.546 | 0.771829 | 0.771829 | Component Quantities - Rectangular Component Height: 3640 mm; Rectangular Component Width: 150 mm
Isolatie - Kunststof hard | begane grond | Isolatie - Kunststof hard | 71.1863 | 0.511 | 0.711863 | 0.711863 | Component Quantities - Rectangular Component Height: 3650 mm; Rectangular Component Width: 140 mm
24 Hout gevelbekleding Lariks | begane grond | 24 Hout gevelbekleding Lariks | 73.7099 | 0.0799999 | 0.1134 | 0.1134 | Component Quantities - Rectangular Component Height: 3200 mm; Rectangular Component Width: 25 mm
Steen - Kalkzandsteen C | begane grond | Steen - Kalkzandsteen C | 1846.15 | 0.546 | 0.97166 | 0.97166 | Component Quantities - Rectangular Component Height: 3640 mm; Rectangular Component Width: 150 mm
Isolatie - Kunststof hard | begane grond | Isolatie - Kunststof hard | 91.188 | 0.511 | 0.91188 | 0.91188 | Component Quantities - Rectangular Component Height: 3650 mm; Rectangular Component Width: 140 mm
24 Hout gevelbekleding Lariks | begane grond | 24 Hout gevelbekleding Lariks | 92.7939 | 0.0799999 | 0.14276 | 0.14276 | Component Quantities - Rectangular Component Height: 3200 mm; Rectangular Component Width: 25 mm
Steen - Kalkzandsteen C | begane grond | Steen - Kalkzandsteen C | 2457.06 | 0.546 | 1.29319 | 1.29319 | Component Quantities - Rectangular Component Height: 3640 mm; Rectangular Component Width: 150 mm
Isolatie - Kunststof hard | begane grond | Isolatie - Kunststof hard | 120.739 | 0.511 | 1.20739 | 1.20739 | Component Quantities - Rectangular Component Height: 3650 mm; Rectangular Component Width: 140 mm
24 Hout gevelbekleding Lariks | begane grond | 24 Hout gevelbekleding Lariks | 123.5 | 0.0799999 | 0.19 | 0.19 | Component Quantities - Rectangular Component Height: 3200 mm; Rectangular Component Width: 25 mm
Beton gewapend prefab wand | begane grond | Beton gewapend prefab wand | 16184.6 | 0.8547 | 6.74358 | 6.74358 | Component Quantities - Rectangular Component Height: 4070 mm; Rectangular Component Width: 210 mm
Beton gewapend prefab wand | begane grond | Beton gewapend prefab wand | 14469.2 | 0.764104 | 6.02884 | 6.02884
Isolatie - Kunststof hard | begane grond | Isolatie - Kunststof hard | 946.89 | 1.1774 | 9.4689 | 9.53694 | Component Quantities - Rectangular Component Height: 8410 mm; Rectangular Component Width: 140 mm
Steen - Baksteen | begane grond | Steen - Baksteen | 7771.52 | 0.5887 | 4.8572 | 4.8921 | Component Quantities - Rectangular Component Height: 8410 mm; Rectangular Component Width: 70 mm
Beton gewapend prefab wand | begane grond | Beton gewapend prefab wand | 1743.48 | 0.8547 | 0.726449 | 0.726449 | Component Quantities - Rectangular Component Height: 4070 mm; Rectangular Component Width: 210 mm
Beton gewapend prefab wand | begane grond | Beton gewapend prefab wand | 1558.77 | 0.764104 | 0.649489 | 0.649489
Isolatie - Kunststof hard | begane grond | Isolatie - Kunststof hard | 113.861 | 1.1774 | 1.13861 | 1.16383 | Component Quantities - Rectangular Component Height: 8410 mm; Rectangular Component Width: 140 mm
Steen - Baksteen | begane grond | Steen - Baksteen | 1046.77 | 0.5887 | 0.654231 | 0.664335 | Component Quantities - Rectangular Component Height: 8410 mm; Rectangular Component Width: 70 mm
Tegels - Wand | begane grond | Tegels - Wand | 16.422 | 0.0255 | 0.00714 | 0.00714 | Component Quantities - Rectangular Component Height: 2550 mm; Rectangular Component Width: 10 mm
48 vloeivloer Bolidt | begane grond | 48 vloeivloer Bolidt | 0.0400319 | 0.0000999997 | 0.0000287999 | 0.0000287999 | Component Quantities - Rectangular Component Height: 50 mm; Rectangular Component Width: 1.99999 mm
Steen - Baksteen | begane grond | Steen - Baksteen | 1019.37 | 0.5887 | 0.637105 | 0.637105 | Component Quantities - Rectangular Component Height: 8410 mm; Rectangular Component Width: 70 mm
Isolatie - Kunststof hard | begane grond | Isolatie - Kunststof hard | 111.853 | 1.1774 | 1.11853 | 1.11853 | Component Quantities - Rectangular Component Height: 8410 mm; Rectangular Component Width: 140 mm
Beton gewapend prefab wand | begane grond | Beton gewapend prefab wand | 1637.04 | 0.8547 | 0.682101 | 0.682101 | Component Quantities - Rectangular Component Height: 4070 mm; Rectangular Component Width: 210 mm
Beton gewapend prefab wand | begane grond | Beton gewapend prefab wand | 1467.12 | 0.764104 | 0.611301 | 0.611301
Steen - Baksteen | begane grond | Steen - Baksteen | 8585.13 | 0.5887 | 5.36571 | 5.36571 | Component Quantities - Rectangular Component Height: 8410 mm; Rectangular Component Width: 70 mm
Isolatie - Kunststof hard | begane grond | Isolatie - Kunststof hard | 1056.13 | 1.1774 | 10.5613 | 10.5613 | Component Quantities - Rectangular Component Height: 8410 mm; Rectangular Component Width: 140 mm
Beton gewapend prefab wand | begane grond | Beton gewapend prefab wand | 17704.3 | 0.8547 | 7.3768 | 7.3768 | Component Quantities - Rectangular Component Height: 4070 mm; Rectangular Component Width: 210 mm
Beton gewapend prefab wand | begane grond | Beton gewapend prefab wand | 15804.2 | 0.764104 | 6.58508 | 6.58508
Metaal - Staal C | begane grond | Metaal - Staal C | 487.105 | 0.00185 | 0.0612711 | 0.0612711
Metaal - Staal C | begane grond | Metaal - Staal C | 35.0189 | 0.000133 | 0.00440489 | 0.00440489 | Component Quantities - Rectangular Component Height: 1 mm; Rectangular Component Width: 133 mm
Isolatie - Kunststof hard | begane grond | Isolatie - Kunststof hard | 91.282 | 0.6146 | 0.91282 | 0.91282 | Component Quantities - Rectangular Component Height: 4390 mm; Rectangular Component Width: 140 mm
Steen - Baksteen | begane grond | Steen - Baksteen | 730.256 | 0.3073 | 0.45641 | 0.45641 | Component Quantities - Rectangular Component Height: 4390 mm; Rectangular Component Width: 70.0001 mm
ALG - LICHTE SCHEIDINGSWAND | begane grond | ALG - LICHTE SCHEIDINGSWAND | 759.707 | 0.388 | 0.949634 | 3.05006 | Component Quantities - Rectangular Component Height: 3880 mm; Rectangular Component Width: 100 mm; Projected Component Area (Net): 10.0699 m2; Projected Component Area (Gross): 31.1044 m2; Component Thickness: 100 mm
ALG - LICHTE SCHEIDINGSWAND | begane grond | ALG - LICHTE SCHEIDINGSWAND | 874.404 | 0.388 | 1.093 | 3.22502 | Component Quantities - Rectangular Component Height: 3880 mm; Rectangular Component Width: 100 mm; Projected Component Area (Net): 12.3998 m2; Projected Component Area (Gross): 33.7202 m2; Component Thickness: 100 mm
Metaal - Staal C | begane grond | Metaal - Staal C | 64.4964 | 0.003 | 0.00811275 | 0.00811275 | Component Quantities - Rectangular Component Height: 15 mm; Rectangular Component Width: 200 mm
Metaal - Staal C | begane grond | Metaal - Staal C | 61.056 | 0.003 | 0.00768 | 0.00768 | Component Quantities - Rectangular Component Height: 15 mm; Rectangular Component Width: 200 mm
Metaal - Staal C | begane grond | Metaal - Staal C | 32.8364 | 0.00153 | 0.00413036 | 0.00413036 | Component Quantities - Rectangular Component Height: 170 mm; Rectangular Component Width: 9 mm
48 vloeivloer Bolidt | begane grond | 48 vloeivloer Bolidt | 0.016124 | 0.0000999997 | 0.0000116 | 0.0000116 | Component Quantities - Rectangular Component Height: 50 mm; Rectangular Component Width: 1.99999 mm
Tegels - Wand | begane grond | Tegels - Wand | 6.8034 | 0.0255 | 0.002958 | 0.002958 | Component Quantities - Rectangular Component Height: 2550 mm; Rectangular Component Width: 10 mm
48 vloeivloer Bolidt | begane grond | 48 vloeivloer Bolidt | 0.181672 | 0.0000999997 | 0.0001307 | 0.0001307 | Component Quantities - Rectangular Component Height: 50 mm; Rectangular Component Width: 1.99999 mm
Tegels - Wand | begane grond | Tegels - Wand | 77.1248 | 0.0255 | 0.0335325 | 0.0335325 | Component Quantities - Rectangular Component Height: 2550 mm; Rectangular Component Width: 10 mm
48 vloeivloer Bolidt | begane grond | 48 vloeivloer Bolidt | 0.163255 | 0.0000999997 | 0.00011745 | 0.00011745 | Component Quantities - Rectangular Component Height: 50 mm; Rectangular Component Width: 1.99999 mm
Tegels - Wand | begane grond | Tegels - Wand | 69.3536 | 0.0255 | 0.0301538 | 0.0301538 | Component Quantities - Rectangular Component Height: 2550 mm; Rectangular Component Width: 10 mm
48 vloeivloer Bolidt | begane grond | 48 vloeivloer Bolidt | 0.184452 | 0.0000999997 | 0.0001327 | 0.0001327 | Component Quantities - Rectangular Component Height: 50 mm; Rectangular Component Width: 1.99999 mm
Tegels - Wand | begane grond | Tegels - Wand | 78.2978 | 0.0255 | 0.0340425 | 0.0340425 | Component Quantities - Rectangular Component Height: 2550 mm; Rectangular Component Width: 10 mm
48 vloeivloer Bolidt | begane grond | 48 vloeivloer Bolidt | 0.380099 | 0.000100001 | 0.000273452 | 0.000273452 | Component Quantities - Rectangular Component Height: 50 mm; Rectangular Component Width: 2.00002 mm
Tegels - Wand | begane grond | Tegels - Wand | 110.386 | 0.0175 | 0.0479938 | 0.0479938 | Component Quantities - Rectangular Component Height: 1750 mm; Rectangular Component Width: 10 mm
48 vloeivloer Bolidt | begane grond | 48 vloeivloer Bolidt | 0.411722 | 0.000100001 | 0.000296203 | 0.000296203 | Component Quantities - Rectangular Component Height: 50 mm; Rectangular Component Width: 2.00002 mm
Tegels - Wand | begane grond | Tegels - Wand | 119.543 | 0.0175 | 0.051975 | 0.051975 | Component Quantities - Rectangular Component Height: 1750 mm; Rectangular Component Width: 10 mm
48 vloeivloer Bolidt | begane grond | 48 vloeivloer Bolidt | 0.301911 | 0.000100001 | 0.000217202 | 0.000217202 | Component Quantities - Rectangular Component Height: 50 mm; Rectangular Component Width: 2.00002 mm
Tegels - Wand | begane grond | Tegels - Wand | 87.7451 | 0.0175 | 0.03815 | 0.03815 | Component Quantities - Rectangular Component Height: 1750 mm; Rectangular Component Width: 10 mm
48 vloeivloer Bolidt | begane grond | 48 vloeivloer Bolidt | 0.125101 | 0.000100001 | 0.0000900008 | 0.0000900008 | Component Quantities - Rectangular Component Height: 50 mm; Rectangular Component Width: 2.00002 mm
Tegels - Wand | begane grond | Tegels - Wand | 36.225 | 0.0175 | 0.01575 | 0.01575 | Component Quantities - Rectangular Component Height: 1750 mm; Rectangular Component Width: 10 mm
48 vloeivloer Bolidt | begane grond | 48 vloeivloer Bolidt | 0.0781882 | 0.000100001 | 0.0000562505 | 0.0000562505 | Component Quantities - Rectangular Component Height: 50 mm; Rectangular Component Width: 2.00002 mm
Tegels - Wand | begane grond | Tegels - Wand | 22.6406 | 0.0175 | 0.00984376 | 0.00984376 | Component Quantities - Rectangular Component Height: 1750 mm; Rectangular Component Width: 10 mm
48 vloeivloer Bolidt | begane grond | 48 vloeivloer Bolidt | 0.0530985 | 0.000100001 | 0.0000382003 | 0.0000382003 | Component Quantities - Rectangular Component Height: 50 mm; Rectangular Component Width: 2.00002 mm
Tegels - Wand | begane grond | Tegels - Wand | 15.6975 | 0.0175 | 0.00682501 | 0.00682501 | Component Quantities - Rectangular Component Height: 1750 mm; Rectangular Component Width: 10 mm
48 vloeivloer Bolidt | begane grond | 48 vloeivloer Bolidt | 0.0856247 | 0.000100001 | 0.0000616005 | 0.0000616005 | Component Quantities - Rectangular Component Height: 50 mm; Rectangular Component Width: 2.00002 mm
Tegels - Wand | begane grond | Tegels - Wand | 24.794 | 0.0175 | 0.01078 | 0.01078 | Component Quantities - Rectangular Component Height: 1750 mm; Rectangular Component Width: 10 mm
48 vloeivloer Bolidt | begane grond | 48 vloeivloer Bolidt | 0.153873 | 0.0000999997 | 0.0001107 | 0.0001107 | Component Quantities - Rectangular Component Height: 50 mm; Rectangular Component Width: 1.99999 mm
Tegels - Wand | begane grond | Tegels - Wand | 65.3948 | 0.0255 | 0.0284325 | 0.0284325 | Component Quantities - Rectangular Component Height: 2550 mm; Rectangular Component Width: 10 mm
3 x 48 vloeivloer Bolidt | begane grond | 48 vloeivloer Bolidt | 0.161518 | 0.0000999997 | 0.0001162 | 0.0001162 | Component Quantities - Rectangular Component Height: 50 mm; Rectangular Component Width: 1.99999 mm
3 x Tegels - Wand | begane grond | Tegels - Wand | 68.6205 | 0.0255 | 0.029835 | 0.029835 | Component Quantities - Rectangular Component Height: 2550 mm; Rectangular Component Width: 10 mm
48 vloeivloer Bolidt | begane grond | 48 vloeivloer Bolidt | 0.00875697 | 0.0000999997 | 0.00000629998 | 0.00000629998 | Component Quantities - Rectangular Component Height: 50 mm; Rectangular Component Width: 1.99999 mm
Tegels - Wand | begane grond | Tegels - Wand | 4.16415 | 0.0255 | 0.0018105 | 0.0018105 | Component Quantities - Rectangular Component Height: 2550 mm; Rectangular Component Width: 10 mm
48 vloeivloer Bolidt | begane grond | 48 vloeivloer Bolidt | 0.16124 | 0.0000999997 | 0.000116 | 0.000116 | Component Quantities - Rectangular Component Height: 50 mm; Rectangular Component Width: 1.99999 mm
Tegels - Wand | begane grond | Tegels - Wand | 68.034 | 0.0255 | 0.02958 | 0.02958 | Component Quantities - Rectangular Component Height: 2550 mm; Rectangular Component Width: 10 mm
48 vloeivloer Bolidt | begane grond | 48 vloeivloer Bolidt | 0.147618 | 0.0000999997 | 0.0001062 | 0.0001062 | Component Quantities - Rectangular Component Height: 50 mm; Rectangular Component Width: 1.99999 mm
Tegels - Wand | begane grond | Tegels - Wand | 62.7555 | 0.0255 | 0.027285 | 0.027285 | Component Quantities - Rectangular Component Height: 2550 mm; Rectangular Component Width: 10 mm
48 vloeivloer Bolidt | begane grond | 48 vloeivloer Bolidt | 0.0573373 | 0.0000999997 | 0.0000412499 | 0.0000412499 | Component Quantities - Rectangular Component Height: 50 mm; Rectangular Component Width: 1.99999 mm
Tegels - Wand | begane grond | Tegels - Wand | 24.1931 | 0.0255 | 0.0105188 | 0.0105188 | Component Quantities - Rectangular Component Height: 2550 mm; Rectangular Component Width: 10 mm
48 vloeivloer Bolidt | begane grond | 48 vloeivloer Bolidt | 0.141085 | 0.0000999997 | 0.0001015 | 0.0001015 | Component Quantities - Rectangular Component Height: 50 mm; Rectangular Component Width: 1.99999 mm
Tegels - Wand | begane grond | Tegels - Wand | 59.5298 | 0.0255 | 0.0258825 | 0.0258825 | Component Quantities - Rectangular Component Height: 2550 mm; Rectangular Component Width: 10 mm
48 vloeivloer Bolidt | begane grond | 48 vloeivloer Bolidt | 0.244917 | 0.0000999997 | 0.000176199 | 0.000176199 | Component Quantities - Rectangular Component Height: 50 mm; Rectangular Component Width: 1.99999 mm
Tegels - Wand | begane grond | Tegels - Wand | 103.81 | 0.0255 | 0.045135 | 0.045135 | Component Quantities - Rectangular Component Height: 2550 mm; Rectangular Component Width: 10 mm
48 vloeivloer Bolidt | begane grond | 48 vloeivloer Bolidt | 0.288702 | 0.0000999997 | 0.000207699 | 0.000207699 | Component Quantities - Rectangular Component Height: 50 mm; Rectangular Component Width: 1.99999 mm
Tegels - Wand | begane grond | Tegels - Wand | 122.285 | 0.0255 | 0.0531675 | 0.0531675 | Component Quantities - Rectangular Component Height: 2550 mm; Rectangular Component Width: 10 mm
48 vloeivloer Bolidt | begane grond | 48 vloeivloer Bolidt | 0.0773151 | 0.0000999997 | 0.0000556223 | 0.0000556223 | Component Quantities - Rectangular Component Height: 50 mm; Rectangular Component Width: 1.99999 mm
Tegels - Wand | begane grond | Tegels - Wand | 33.0918 | 0.0255 | 0.0143877 | 0.0143877 | Component Quantities - Rectangular Component Height: 2550 mm; Rectangular Component Width: 10 mm
48 vloeivloer Bolidt | begane grond | 48 vloeivloer Bolidt | 0.077044 | 0.0000999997 | 0.0000554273 | 0.0000554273 | Component Quantities - Rectangular Component Height: 50 mm; Rectangular Component Width: 1.99999 mm
Tegels - Wand | begane grond | Tegels - Wand | 32.5082 | 0.0255 | 0.014134 | 0.014134 | Component Quantities - Rectangular Component Height: 2550 mm; Rectangular Component Width: 10 mm
48 vloeivloer Bolidt | begane grond | 48 vloeivloer Bolidt | 0.163047 | 0.0000999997 | 0.0001173 | 0.0001173 | Component Quantities - Rectangular Component Height: 50 mm; Rectangular Component Width: 1.99999 mm
Tegels - Wand | begane grond | Tegels - Wand | 68.7964 | 0.0255 | 0.0299115 | 0.0299115 | Component Quantities - Rectangular Component Height: 2550 mm; Rectangular Component Width: 10 mm
2 x 48 vloeivloer Bolidt | begane grond | 48 vloeivloer Bolidt | 0.1709 | 0.0000999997 | 0.00012295 | 0.00012295 | Component Quantities - Rectangular Component Height: 50 mm; Rectangular Component Width: 1.99999 mm
2 x Tegels - Wand | begane grond | Tegels - Wand | 72.5794 | 0.0255 | 0.0315563 | 0.0315563 | Component Quantities - Rectangular Component Height: 2550 mm; Rectangular Component Width: 10 mm
48 vloeivloer Bolidt | begane grond | 48 vloeivloer Bolidt | 0.0257844 | 0.0000999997 | 0.0000185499 | 0.0000185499 | Component Quantities - Rectangular Component Height: 50 mm; Rectangular Component Width: 1.99999 mm
Tegels - Wand | begane grond | Tegels - Wand | 11.3488 | 0.0255 | 0.00493425 | 0.00493425 | Component Quantities - Rectangular Component Height: 2550 mm; Rectangular Component Width: 10 mm
48 vloeivloer Bolidt | begane grond | 48 vloeivloer Bolidt | 0.0255064 | 0.0000999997 | 0.0000183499 | 0.0000183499 | Component Quantities - Rectangular Component Height: 50 mm; Rectangular Component Width: 1.99999 mm
Tegels - Wand | begane grond | Tegels - Wand | 10.7623 | 0.0255 | 0.00467925 | 0.00467925 | Component Quantities - Rectangular Component Height: 2550 mm; Rectangular Component Width: 10 mm
48 vloeivloer Bolidt | begane grond | 48 vloeivloer Bolidt | 0.163325 | 0.0000999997 | 0.0001175 | 0.0001175 | Component Quantities - Rectangular Component Height: 50 mm; Rectangular Component Width: 1.99999 mm
Tegels - Wand | begane grond | Tegels - Wand | 69.383 | 0.0255 | 0.0301665 | 0.0301665 | Component Quantities - Rectangular Component Height: 2550 mm; Rectangular Component Width: 10 mm
Kunststof Kupan | begane grond | Kunststof Kupan | 36.3532 | 0.0273 | 0.0261534 | 0.0752934 | Component Quantities - Rectangular Component Height: 2100 mm; Rectangular Component Width: 13 mm
Metaal - Aluminium | begane grond | Metaal - Aluminium | 7.7224 | 0.001 | 0.002758 | 0.002758 | Component Quantities - Rectangular Component Height: 50 mm; Rectangular Component Width: 20 mm
ALG - LICHTE SCHEIDINGSWAND AFW | begane grond | ALG - LICHTE SCHEIDINGSWAND AFW | 77.4144 | 0.03456 | 0.096768 | 0.096768 | Component Quantities - Rectangular Component Height: 2880 mm; Rectangular Component Width: 12 mm; Projected Component Area (Net): 8.064 m2; Projected Component Area (Gross): 8.064 m2; Component Thickness: 12 mm
Hout - Multiplex wbp | begane grond | Hout - Multiplex wbp | 101.606 | 0.05184 | 0.145152 | 0.145152 | Component Quantities - Rectangular Component Height: 2880 mm; Rectangular Component Width: 18 mm; Projected Component Area (Net): 8.064 m2; Projected Component Area (Gross): 8.064 m2; Component Thickness: 18 mm
Tegels - Wand | begane grond | Tegels - Wand | 143.693 | 0.0255 | 0.062475 | 0.062475 | Component Quantities - Rectangular Component Height: 2550 mm; Rectangular Component Width: 10 mm
Steen - Kalkzandsteen C | begane grond | Steen - Kalkzandsteen C | 4520.98 | 0.5445 | 2.37946 | 2.37946 | Component Quantities - Rectangular Component Height: 3630 mm; Rectangular Component Width: 150 mm
Isolatie - Kunststof hard | begane grond | Isolatie - Kunststof hard | 281.487 | 0.6146 | 2.81487 | 2.81487 | Component Quantities - Rectangular Component Height: 4390 mm; Rectangular Component Width: 140 mm
Steen - Baksteen | begane grond | Steen - Baksteen | 2353.74 | 0.3073 | 1.47109 | 1.47109 | Component Quantities - Rectangular Component Height: 4390 mm; Rectangular Component Width: 70.0001 mm
Steen - Kalkzandsteen C | begane grond | Steen - Kalkzandsteen C | 10769.7 | 0.5445 | 5.66824 | 5.66824 | Component Quantities - Rectangular Component Height: 3630 mm; Rectangular Component Width: 150 mm
Isolatie - Kunststof hard | begane grond | Isolatie - Kunststof hard | 665.612 | 0.6146 | 6.65612 | 6.65612 | Component Quantities - Rectangular Component Height: 4390 mm; Rectangular Component Width: 140 mm
Steen - Baksteen | begane grond | Steen - Baksteen | 5428.15 | 0.3073 | 3.39259 | 3.39259 | Component Quantities - Rectangular Component Height: 4390 mm; Rectangular Component Width: 70.0001 mm
Steen - Kalkzandsteen C | begane grond | Steen - Kalkzandsteen C | 4125.79 | 0.546 | 2.17147 | 2.17147 | Component Quantities - Rectangular Component Height: 3640 mm; Rectangular Component Width: 150 mm
Isolatie - Kunststof hard | begane grond | Isolatie - Kunststof hard | 203.787 | 0.511 | 2.03787 | 2.03787 | Component Quantities - Rectangular Component Height: 3650 mm; Rectangular Component Width: 140 mm
24 Hout gevelbekleding Lariks | begane grond | 24 Hout gevelbekleding Lariks | 207.376 | 0.0799999 | 0.31904 | 0.31904 | Component Quantities - Rectangular Component Height: 3200 mm; Rectangular Component Width: 25 mm
Metaal - Staal C | begane grond | Metaal - Staal C | 429.306 | 0.00185 | 0.0540008 | 0.0540008
Metaal - Staal C | begane grond | Metaal - Staal C | 30.7832 | 0.000133 | 0.0038721 | 0.0038721 | Component Quantities - Rectangular Component Height: 1 mm; Rectangular Component Width: 133 mm
Metaal - Staal C | begane grond | Metaal - Staal C | 216.63 | 0.00185 | 0.027249 | 0.027249
Metaal - Staal C | begane grond | Metaal - Staal C | 15.413 | 0.000133 | 0.00193874 | 0.00193874 | Component Quantities - Rectangular Component Height: 1 mm; Rectangular Component Width: 133 mm
Metaal - Staal C | begane grond | Metaal - Staal C | 99.858 | 0.00185 | 0.0125608 | 0.0125608
Metaal - Staal C | begane grond | Metaal - Staal C | 7.09852 | 0.000133 | 0.000892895 | 0.000892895 | Component Quantities - Rectangular Component Height: 1 mm; Rectangular Component Width: 133 mm
Steen - Kalkzandsteen C | begane grond | Steen - Kalkzandsteen C | 3655.2 | 0.594 | 1.92379 | 3.48184 | Component Quantities - Rectangular Component Height: 3960 mm; Rectangular Component Width: 150 mm
Isolatie - Kunststof hard | begane grond | Isolatie - Kunststof hard | 250.777 | 0.611 | 2.50777 | 4.01732
24 Hout gevelbekleding Lariks | begane grond | 24 Hout gevelbekleding Lariks | 27.7875 | 0.0475 | 0.04275 | 0.320625 | Component Quantities - Rectangular Component Height: 1900 mm; Rectangular Component Width: 25 mm
Steen - Baksteen | begane grond | Steen - Baksteen | 972.698 | 0.0896001 | 0.607937 | 0.607937 | Component Quantities - Rectangular Component Height: 1280 mm; Rectangular Component Width: 70.0001 mm
Steen - Baksteen | begane grond | Steen - Baksteen | 885.307 | 0.08155 | 0.553317 | 0.553317 | Component Quantities - Rectangular Component Height: 1165 mm; Rectangular Component Width: 70 mm
Steen - Kalkzandsteen C | begane grond | Steen - Kalkzandsteen C | 234.063 | 0.546 | 0.123191 | 0.123191 | Component Quantities - Rectangular Component Height: 3640 mm; Rectangular Component Width: 150 mm
Isolatie - Kunststof hard | begane grond | Isolatie - Kunststof hard | 9.7461 | 0.4284 | 0.097461 | 0.097461 | Component Quantities - Rectangular Component Height: 3060 mm; Rectangular Component Width: 140 mm
Steen - Baksteen | begane grond | Steen - Baksteen | 77.9689 | 0.2142 | 0.0487305 | 0.0487305 | Component Quantities - Rectangular Component Height: 3060 mm; Rectangular Component Width: 70.0001 mm
Beton gewapend C vloer | begane grond | Beton gewapend C vloer | 1039.75 | 0.0932915 | 0.43323 | 0.43323
2 x Metaal - Staal C | begane grond | Metaal - Staal C | 227.839 | 0.00615 | 0.028659 | 0.028659 | Component Quantities - Rectangular Component Height: 20.5 mm; Rectangular Component Width: 300 mm
Metaal - Staal C | begane grond | Metaal - Staal C | 118.865 | 0.0032085 | 0.0149516 | 0.0149516 | Component Quantities - Rectangular Component Height: 279 mm; Rectangular Component Width: 11.5 mm
Metaal - Staal C | begane grond | Metaal - Staal C | 407.517 | 0.011 | 0.05126 | 0.05126 | Component Quantities - Rectangular Component Height: 20 mm; Rectangular Component Width: 550 mm
Steen - Baksteen | begane grond | Steen - Baksteen | 149.94 | 0.1275 | 0.0937125 | 0.0937125 | Component Quantities - Rectangular Component Height: 1275 mm; Rectangular Component Width: 100 mm; Projected Component Area (Net): 0.937125 m2; Projected Component Area (Gross): 0.937125 m2; Component Thickness: 100 mm
Isolatie - Kunststof hard | begane grond | Isolatie - Kunststof hard | 9.55155 | 0.1785 | 0.0955155 | 0.0955155 | Component Quantities - Rectangular Component Height: 1275 mm; Rectangular Component Width: 140 mm; Projected Component Area (Net): 0.707625 m2; Projected Component Area (Gross): 0.707625 m2; Component Thickness: 140 mm
ALG - LICHTE SCHEIDINGSWAND AFW | begane grond | ALG - LICHTE SCHEIDINGSWAND AFW | 13.8017 | 0.04356 | 0.0172522 | 0.0172522 | Component Quantities - Rectangular Component Height: 3630 mm; Rectangular Component Width: 12 mm; Projected Component Area (Net): 1.43768 m2; Projected Component Area (Gross): 1.43768 m2; Component Thickness: 12 mm
Hout - Multiplex wbp | begane grond | Hout - Multiplex wbp | 17.3074 | 0.06534 | 0.0247248 | 0.0247248 | Component Quantities - Rectangular Component Height: 3630 mm; Rectangular Component Width: 18 mm; Projected Component Area (Net): 1.3736 m2; Projected Component Area (Gross): 1.3736 m2; Component Thickness: 18 mm
Steen - Baksteen | begane grond | Steen - Baksteen | 475.32 | 0.1275 | 0.297075 | 0.297075 | Component Quantities - Rectangular Component Height: 1275 mm; Rectangular Component Width: 100 mm; Projected Component Area (Net): 2.97075 m2; Projected Component Area (Gross): 2.97075 m2; Component Thickness: 100 mm
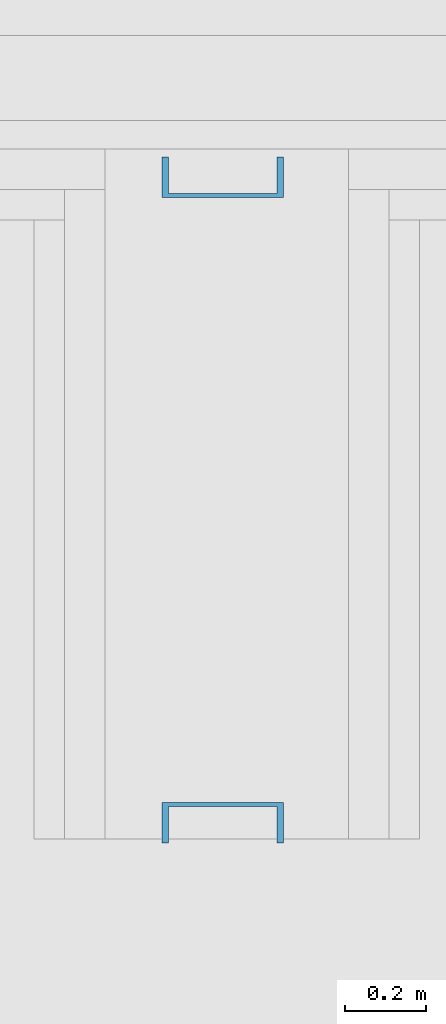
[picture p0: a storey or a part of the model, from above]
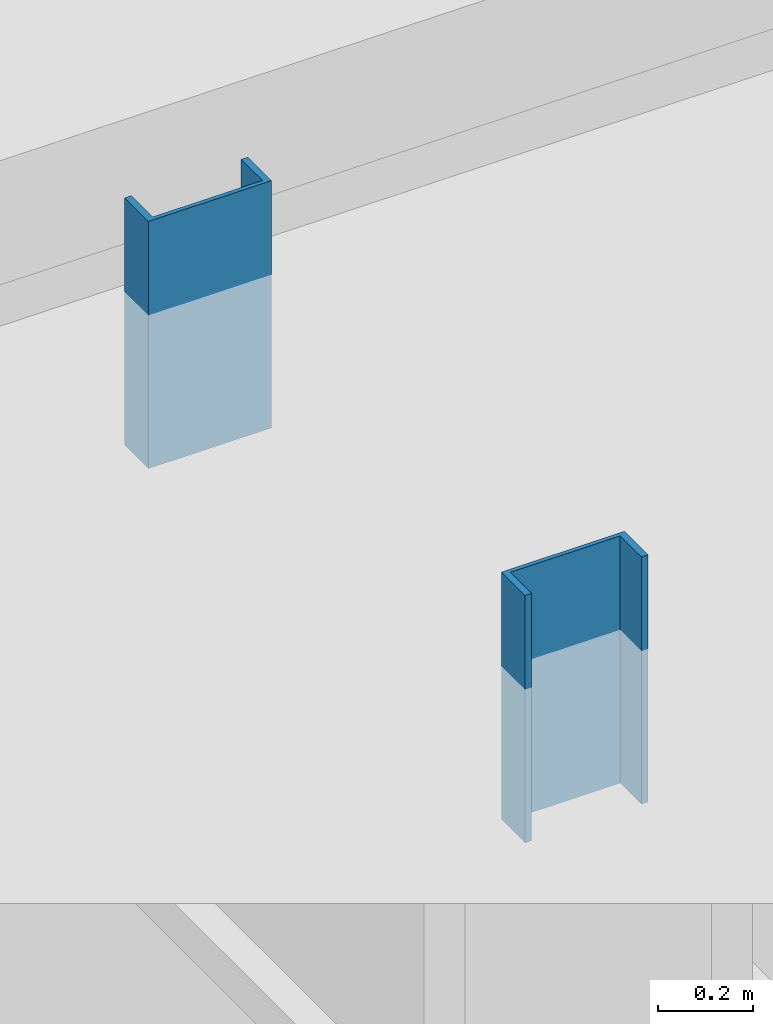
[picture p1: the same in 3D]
Properties of the parts of a building model (IFC2X3), part 3 of 9

# IfcBuildingElementPart (2190)
Name | In | Material | Mass (kg) | Component Cross Section Area (m2) | Component Volume (Net) (m3) | Component Volume (Gross) (m3)
Isolatie - Kunststof hard | begane grond | Isolatie - Kunststof hard | 39.0915 | 0.1785 | 0.390915 | 0.390915 | Component Quantities - Rectangular Component Height: 1275 mm; Rectangular Component Width: 140 mm; Projected Component Area (Net): 2.79225 m2; Projected Component Area (Gross): 2.79225 m2; Component Thickness: 140 mm
2 x Hout C | begane grond | Hout C | 47.5983 |  | 0.0865424 | 0.0865424
2 x Glas sticker | begane grond | Glas sticker | 16.9856 |  | 0.00779158 | 0.00779158
Beton gewapend C vloer | begane grond | Beton gewapend C vloer | 1523.64 | 0.0932915 | 0.634849 | 0.634849
2 x Metaal - Staal C | begane grond | Metaal - Staal C | 332.713 | 0.00615 | 0.0418508 | 0.0418508 | Component Quantities - Rectangular Component Height: 20.5 mm; Rectangular Component Width: 300 mm
Metaal - Staal C | begane grond | Metaal - Staal C | 173.579 | 0.0032085 | 0.0218338 | 0.0218338 | Component Quantities - Rectangular Component Height: 279 mm; Rectangular Component Width: 11.5 mm
Metaal - Staal C | begane grond | Metaal - Staal C | 595.097 | 0.011 | 0.074855 | 0.074855 | Component Quantities - Rectangular Component Height: 20 mm; Rectangular Component Width: 550 mm
Beton gewapend C vloer | begane grond | Beton gewapend C vloer | 125.645 | 0.0868915 | 0.0523521 | 0.0523521
2 x Metaal - Staal C | begane grond | Metaal - Staal C | 29.4577 | 0.00615 | 0.00370537 | 0.00370537 | Component Quantities - Rectangular Component Height: 20.5 mm; Rectangular Component Width: 300 mm
Metaal - Staal C | begane grond | Metaal - Staal C | 15.3683 | 0.0032085 | 0.00193312 | 0.00193312 | Component Quantities - Rectangular Component Height: 279 mm; Rectangular Component Width: 11.5 mm
Metaal - Staal C | begane grond | Metaal - Staal C | 40.7139 | 0.0085 | 0.00512125 | 0.00512125 | Component Quantities - Rectangular Component Height: 20 mm; Rectangular Component Width: 425 mm
Hout - Multiplex wbp | begane grond | Hout - Multiplex wbp | 39.8321 | 0.06534 | 0.056903 | 0.056903 | Component Quantities - Rectangular Component Height: 3630 mm; Rectangular Component Width: 18 mm; Projected Component Area (Net): 3.16128 m2; Projected Component Area (Gross): 3.16128 m2; Component Thickness: 18 mm
ALG - LICHTE SCHEIDINGSWAND AFW | begane grond | ALG - LICHTE SCHEIDINGSWAND AFW | 30.7584 | 0.04356 | 0.038448 | 0.038448 | Component Quantities - Rectangular Component Height: 3630 mm; Rectangular Component Width: 12 mm; Projected Component Area (Net): 3.204 m2; Projected Component Area (Gross): 3.204 m2; Component Thickness: 12 mm
Hout - Multiplex wbp | begane grond | Hout - Multiplex wbp | 24.0358 | 0.06534 | 0.0343368 | 0.0343368 | Component Quantities - Rectangular Component Height: 3630 mm; Rectangular Component Width: 18 mm; Projected Component Area (Net): 1.9076 m2; Projected Component Area (Gross): 1.9076 m2; Component Thickness: 18 mm
ALG - LICHTE SCHEIDINGSWAND AFW | begane grond | ALG - LICHTE SCHEIDINGSWAND AFW | 18.9281 | 0.04356 | 0.0236602 | 0.0236602 | Component Quantities - Rectangular Component Height: 3630 mm; Rectangular Component Width: 12 mm; Projected Component Area (Net): 1.97168 m2; Projected Component Area (Gross): 1.97168 m2; Component Thickness: 12 mm
Steen - Kalkzandsteen C | begane grond | Steen - Kalkzandsteen C | 19782.5 | 0.594 | 10.4119 | 17.9656 | Component Quantities - Rectangular Component Height: 3960 mm; Rectangular Component Width: 150 mm
Isolatie - Kunststof hard | begane grond | Isolatie - Kunststof hard | 725.204 | 0.611 | 7.25204 | 14.343
24 Hout gevelbekleding Lariks | begane grond | 24 Hout gevelbekleding Lariks | 250.381 | 0.0475 | 0.385201 | 1.5727 | Component Quantities - Rectangular Component Height: 1900 mm; Rectangular Component Width: 25 mm
Steen - Baksteen | begane grond | Steen - Baksteen | 37.0827 | 0.0896001 | 0.0231767 | 0.0231767 | Component Quantities - Rectangular Component Height: 1280 mm; Rectangular Component Width: 70.0001 mm
Steen - Baksteen | begane grond | Steen - Baksteen | 3977.41 | 0.08155 | 2.48588 | 2.70008 | Component Quantities - Rectangular Component Height: 1165 mm; Rectangular Component Width: 70 mm
Kunststof - massief | begane grond | Kunststof - massief | 0.0288426 | 0.000250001 | 0.0000207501 | 0.0000207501 | Component Quantities - Rectangular Component Height: 50 mm; Rectangular Component Width: 5.00002 mm
Vilton | begane grond | Vilton | 1.4945 | 0.08415 | 0.00934065 | 0.00934065 | Component Quantities - Rectangular Component Height: 2550 mm; Rectangular Component Width: 33 mm
Kunststof - massief | begane grond | Kunststof - massief | 0.738441 | 0.000250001 | 0.000531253 | 0.000531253 | Component Quantities - Rectangular Component Height: 50 mm; Rectangular Component Width: 5.00002 mm
Vilton | begane grond | Vilton | 28.611 | 0.08415 | 0.178819 | 0.178819 | Component Quantities - Rectangular Component Height: 2550 mm; Rectangular Component Width: 33 mm
2 x Kunststof - massief | begane grond | Kunststof - massief | 0.300589 | 0.000250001 | 0.000216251 | 0.000216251 | Component Quantities - Rectangular Component Height: 50 mm; Rectangular Component Width: 5.00002 mm
2 x Vilton | begane grond | Vilton | 11.2694 | 0.08415 | 0.0704336 | 0.0704336 | Component Quantities - Rectangular Component Height: 2550 mm; Rectangular Component Width: 33 mm
Kunststof - massief | begane grond | Kunststof - massief | 0.302326 | 0.000250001 | 0.000217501 | 0.000217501 | Component Quantities - Rectangular Component Height: 50 mm; Rectangular Component Width: 5.00002 mm
2 x Vilton | begane grond | Vilton | 11.7137 | 0.08415 | 0.0732105 | 0.0732105 | Component Quantities - Rectangular Component Height: 2550 mm; Rectangular Component Width: 33 mm
Kunststof - massief | begane grond | Kunststof - massief | 1.8322 | 0.000250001 | 0.00131813 | 0.00131813 | Component Quantities - Rectangular Component Height: 50 mm; Rectangular Component Width: 5.00002 mm
Vilton | begane grond | Vilton | 70.9888 | 0.08415 | 0.44368 | 0.44368 | Component Quantities - Rectangular Component Height: 2550 mm; Rectangular Component Width: 33 mm
Kunststof - massief | begane grond | Kunststof - massief | 0.0271051 | 0.000250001 | 0.0000195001 | 0.0000195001 | Component Quantities - Rectangular Component Height: 50 mm; Rectangular Component Width: 5.00002 mm
Vilton | begane grond | Vilton | 1.05019 | 0.08415 | 0.0065637 | 0.0065637 | Component Quantities - Rectangular Component Height: 2550 mm; Rectangular Component Width: 33 mm
Kunststof - massief | begane grond | Kunststof - massief | 0.0747127 | 0.000250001 | 0.0000537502 | 0.0000537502 | Component Quantities - Rectangular Component Height: 50 mm; Rectangular Component Width: 5.00002 mm
Vilton | begane grond | Vilton | 3.27175 | 0.08415 | 0.0204484 | 0.0204484 | Component Quantities - Rectangular Component Height: 2550 mm; Rectangular Component Width: 33 mm
Kunststof - massief | begane grond | Kunststof - massief | 0.0521252 | 0.000250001 | 0.0000375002 | 0.0000375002 | Component Quantities - Rectangular Component Height: 50 mm; Rectangular Component Width: 5.00002 mm
Vilton | begane grond | Vilton | 2.0196 | 0.08415 | 0.0126225 | 0.0126225 | Component Quantities - Rectangular Component Height: 2550 mm; Rectangular Component Width: 33 mm
Kunststof - massief | begane grond | Kunststof - massief | 0.0747129 | 0.000250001 | 0.0000537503 | 0.0000537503 | Component Quantities - Rectangular Component Height: 50 mm; Rectangular Component Width: 5.00002 mm
Vilton | begane grond | Vilton | 3.27175 | 0.08415 | 0.0204485 | 0.0204485 | Component Quantities - Rectangular Component Height: 2550 mm; Rectangular Component Width: 33 mm
Kunststof - massief | begane grond | Kunststof - massief | 0.517774 | 0.000250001 | 0.000372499 | 0.000372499 | Component Quantities - Rectangular Component Height: 50 mm; Rectangular Component Width: 5.00002 mm
Vilton | begane grond | Vilton | 20.4382 | 0.08415 | 0.127739 | 0.127739 | Component Quantities - Rectangular Component Height: 2550 mm; Rectangular Component Width: 33 mm
Kunststof - massief | begane grond | Kunststof - massief | 0.0729751 | 0.000250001 | 0.0000525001 | 0.0000525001 | Component Quantities - Rectangular Component Height: 50 mm; Rectangular Component Width: 5.00002 mm
Vilton | begane grond | Vilton | 2.82743 | 0.08415 | 0.0176714 | 0.0176714 | Component Quantities - Rectangular Component Height: 2550 mm; Rectangular Component Width: 33 mm
Kunststof - massief | begane grond | Kunststof - massief | 0.302327 | 0.000250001 | 0.000217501 | 0.000217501 | Component Quantities - Rectangular Component Height: 50 mm; Rectangular Component Width: 5.00002 mm
Kunststof - massief | begane grond | Kunststof - massief | 1.76357 | 0.000250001 | 0.00126876 | 0.00126876 | Component Quantities - Rectangular Component Height: 50 mm; Rectangular Component Width: 5.00002 mm
Vilton | begane grond | Vilton | 68.3298 | 0.08415 | 0.427061 | 0.427061 | Component Quantities - Rectangular Component Height: 2550 mm; Rectangular Component Width: 33 mm
Kunststof - massief | begane grond | Kunststof - massief | 0.0729753 | 0.000250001 | 0.0000525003 | 0.0000525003 | Component Quantities - Rectangular Component Height: 50 mm; Rectangular Component Width: 5.00002 mm
Vilton | begane grond | Vilton | 2.82744 | 0.08415 | 0.0176715 | 0.0176715 | Component Quantities - Rectangular Component Height: 2550 mm; Rectangular Component Width: 33 mm
Beton gewapend C vloer | begane grond | Beton gewapend C vloer | 521.201 | 0.0868915 | 0.217167 | 0.217167
2 x Metaal - Staal C | begane grond | Metaal - Staal C | 122.231 | 0.00615 | 0.015375 | 0.015375 | Component Quantities - Rectangular Component Height: 20.5 mm; Rectangular Component Width: 300 mm
Metaal - Staal C | begane grond | Metaal - Staal C | 63.7689 | 0.0032085 | 0.00802125 | 0.00802125 | Component Quantities - Rectangular Component Height: 279 mm; Rectangular Component Width: 11.5 mm
Metaal - Staal C | begane grond | Metaal - Staal C | 168.937 | 0.0085 | 0.02125 | 0.02125 | Component Quantities - Rectangular Component Height: 20 mm; Rectangular Component Width: 425 mm
Metaal - Staal C | begane grond | Metaal - Staal C | 10.1363 | 0.003 | 0.001275 | 0.001275 | Component Quantities - Rectangular Component Height: 15 mm; Rectangular Component Width: 200 mm
Metaal - Staal C | begane grond | Metaal - Staal C | 5.44682 | 0.00153 | 0.000685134 | 0.000685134 | Component Quantities - Rectangular Component Height: 170 mm; Rectangular Component Width: 9 mm
5 x Metaal - Staal C | begane grond | Metaal - Staal C | 10.6013 | 0.003 | 0.0013335 | 0.0013335 | Component Quantities - Rectangular Component Height: 15 mm; Rectangular Component Width: 200 mm
5 x Metaal - Staal C | begane grond | Metaal - Staal C | 7.155 | 0.003 | 0.0009 | 0.0009 | Component Quantities - Rectangular Component Height: 15 mm; Rectangular Component Width: 200 mm
5 x Metaal - Staal C | begane grond | Metaal - Staal C | 5.36532 | 0.00153 | 0.000674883 | 0.000674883 | Component Quantities - Rectangular Component Height: 170 mm; Rectangular Component Width: 9 mm
Hout - OSB | verdieping | Hout - OSB | 0.954 | 0.00424 | 0.00159 | 0.00159 | Component Quantities - Rectangular Component Height: 530 mm; Rectangular Component Width: 8 mm
Membraan - waterdicht | verdieping | Membraan - waterdicht | 0.548986 | 0.00130061 | 0.000522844 | 0.000522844 | Component Quantities - Rectangular Component Height: 433.535 mm; Rectangular Component Width: 3 mm
Hout - OSB | verdieping | Hout - OSB | 2.94516 | 0.01212 | 0.0049086 | 0.0049086
Isolatie - Kunststof hard | verdieping | Isolatie - Kunststof hard | 1.22098 | 0.02928 | 0.0122098 | 0.0122098 | Component Quantities - Rectangular Component Height: 244 mm; Rectangular Component Width: 120 mm
3 x Hout - Vloer | verdieping | Hout - Vloer | 1.04584 | 0.00456 | 0.00190152 | 0.00190152 | Component Quantities - Rectangular Component Height: 38 mm; Rectangular Component Width: 120 mm
Hout - OSB | verdieping | Hout - OSB | 5.85759 | 0.01818 | 0.00976266 | 0.00976266 | Component Quantities - Rectangular Component Height: 1010 mm; Rectangular Component Width: 18 mm
Isolatie - Kunststof hard | verdieping | Isolatie - Kunststof hard | 2.34654 | 0.04228 | 0.0234654 | 0.0234654 | Component Quantities - Rectangular Component Height: 302 mm; Rectangular Component Width: 140 mm
Steen - Baksteen | verdieping | Steen - Baksteen | 88.0301 | 0.07192 | 0.0550188 | 0.0550188 | Component Quantities - Rectangular Component Height: 1027.43 mm; Rectangular Component Width: 70 mm
Hout - OSB | verdieping | Hout - OSB | 33.4104 | 0.00424 | 0.0556839 | 0.0556839 | Component Quantities - Rectangular Component Height: 530 mm; Rectangular Component Width: 8 mm
Membraan - waterdicht | verdieping | Membraan - waterdicht | 18.0018 | 0.00130061 | 0.0171446 | 0.0171446 | Component Quantities - Rectangular Component Height: 433.535 mm; Rectangular Component Width: 3 mm
Hout - OSB | verdieping | Hout - OSB | 95.9686 | 0.01212 | 0.159948 | 0.159948
Isolatie - Kunststof hard | verdieping | Isolatie - Kunststof hard | 39.0273 | 0.02928 | 0.390273 | 0.390273 | Component Quantities - Rectangular Component Height: 244 mm; Rectangular Component Width: 120 mm
2 x Hout - Vloer | verdieping | Hout - Vloer | 33.4291 | 0.00456 | 0.0607803 | 0.0607803 | Component Quantities - Rectangular Component Height: 38 mm; Rectangular Component Width: 120 mm
Hout - Vloer | verdieping | Hout - Vloer | 33.4291 | 0.00456 | 0.0607802 | 0.0607802 | Component Quantities - Rectangular Component Height: 38 mm; Rectangular Component Width: 120 mm
Hout - OSB | verdieping | Hout - OSB | 146.898 | 0.01818 | 0.24483 | 0.24483 | Component Quantities - Rectangular Component Height: 1010 mm; Rectangular Component Width: 18 mm
Isolatie - Kunststof hard | verdieping | Isolatie - Kunststof hard | 57.6065 | 0.04228 | 0.576065 | 0.576065 | Component Quantities - Rectangular Component Height: 302 mm; Rectangular Component Width: 140 mm
Steen - Baksteen | verdieping | Steen - Baksteen | 1608.13 | 0.07192 | 1.00508 | 1.00508 | Component Quantities - Rectangular Component Height: 1027.43 mm; Rectangular Component Width: 70 mm
Hout - OSB | verdieping | Hout - OSB | 35.4837 | 0.00424 | 0.0591395 | 0.0591395 | Component Quantities - Rectangular Component Height: 530 mm; Rectangular Component Width: 8 mm
Membraan - waterdicht | verdieping | Membraan - waterdicht | 18.888 | 0.00130061 | 0.0179886 | 0.0179886 | Component Quantities - Rectangular Component Height: 433.535 mm; Rectangular Component Width: 3 mm
Hout - OSB | verdieping | Hout - OSB | 101.895 | 0.01212 | 0.169825 | 0.169825
Isolatie - Kunststof hard | verdieping | Isolatie - Kunststof hard | 41.4136 | 0.02928 | 0.414136 | 0.414136 | Component Quantities - Rectangular Component Height: 244 mm; Rectangular Component Width: 120 mm
3 x Hout - Vloer | verdieping | Hout - Vloer | 35.4732 | 0.00456 | 0.0644967 | 0.0644967 | Component Quantities - Rectangular Component Height: 38 mm; Rectangular Component Width: 120 mm
Hout - OSB | verdieping | Hout - OSB | 155.788 | 0.01818 | 0.259647 | 0.259647 | Component Quantities - Rectangular Component Height: 1010 mm; Rectangular Component Width: 18 mm
Isolatie - Kunststof hard | verdieping | Isolatie - Kunststof hard | 61.0523 | 0.04228 | 0.610523 | 0.610523 | Component Quantities - Rectangular Component Height: 302 mm; Rectangular Component Width: 140 mm
Steen - Baksteen | verdieping | Steen - Baksteen | 1701.92 | 0.07192 | 1.0637 | 1.0637 | Component Quantities - Rectangular Component Height: 1027.43 mm; Rectangular Component Width: 70 mm
Hout - OSB | verdieping | Hout - OSB | 33.6559 | 0.00424 | 0.0560932 | 0.0560932 | Component Quantities - Rectangular Component Height: 530 mm; Rectangular Component Width: 8 mm
Membraan - waterdicht | verdieping | Membraan - waterdicht | 18.1015 | 0.00130061 | 0.0172395 | 0.0172395 | Component Quantities - Rectangular Component Height: 433.535 mm; Rectangular Component Width: 3 mm
Hout - OSB | verdieping | Hout - OSB | 96.4773 | 0.01212 | 0.160795 | 0.160795
Isolatie - Kunststof hard | verdieping | Isolatie - Kunststof hard | 39.1971 | 0.02928 | 0.391971 | 0.391971 | Component Quantities - Rectangular Component Height: 244 mm; Rectangular Component Width: 120 mm
Hout - Vloer | verdieping | Hout - Vloer | 33.5716 | 0.00456 | 0.0610392 | 0.0610392 | Component Quantities - Rectangular Component Height: 38 mm; Rectangular Component Width: 120 mm
2 x Hout - Vloer | verdieping | Hout - Vloer | 33.5746 | 0.00456 | 0.0610447 | 0.0610447 | Component Quantities - Rectangular Component Height: 38 mm; Rectangular Component Width: 120 mm
Hout - OSB | verdieping | Hout - OSB | 146.221 | 0.01818 | 0.243702 | 0.243702 | Component Quantities - Rectangular Component Height: 1010 mm; Rectangular Component Width: 18 mm
Isolatie - Kunststof hard | verdieping | Isolatie - Kunststof hard | 57.2683 | 0.04228 | 0.572683 | 0.572683 | Component Quantities - Rectangular Component Height: 302 mm; Rectangular Component Width: 140 mm
Steen - Baksteen | verdieping | Steen - Baksteen | 1574.76 | 0.07192 | 0.984223 | 0.984223 | Component Quantities - Rectangular Component Height: 1027.43 mm; Rectangular Component Width: 70 mm
48 vloeivloer Bolidt | verdieping | 48 vloeivloer Bolidt | 0.170136 | 0.0000999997 | 0.0001224 | 0.0001224 | Component Quantities - Rectangular Component Height: 50 mm; Rectangular Component Width: 1.99999 mm
Tegels - Wand | verdieping | Tegels - Wand | 71.3184 | 0.0255 | 0.031008 | 0.031008 | Component Quantities - Rectangular Component Height: 2550 mm; Rectangular Component Width: 10 mm
10 x 32 Hout binnenkozijn | verdieping | 32 Hout binnenkozijn | 3.718 |  | 0.00676 | 0.00676
10 x Membraan - rubber | verdieping | Membraan - rubber | 1.70625 |  | 0.001625 | 0.001625
44 x Hout - Lockers | verdieping | Hout - Lockers | 1.21032 | 0.112001 | 0.0020172 | 0.0020172
164 x Hout - Lockers | verdieping | Hout - Lockers | 1.17407 | 0.108644 | 0.00195678 | 0.00195678
22 x Hout - Lockers | verdieping | Hout - Lockers | 1.18087 | 0.109274 | 0.00196812 | 0.00196812
82 x Hout - Lockers | verdieping | Hout - Lockers | 1.14549 | 0.105998 | 0.00190915 | 0.00190915
Glas | verdieping | Glas | 53.8308 | 0.01635 | 0.024693 | 0.0257784 | Component Quantities - Rectangular Component Height: 1090 mm; Rectangular Component Width: 15 mm
Membraan - rubber | verdieping | Membraan - rubber | 4.00541 | 0.00265 | 0.00381468 | 0.00381468
Metaal - Staal C wit | verdieping | Metaal - Staal C wit | 22.6447 | 0.002 | 0.00284839 | 0.00284839 | Component Quantities - Rectangular Component Height: 200 mm; Rectangular Component Width: 10 mm
Metaal - Staal C wit | verdieping | Metaal - Staal C wit | 17.0797 | 0.0015 | 0.00214839 | 0.00214839 | Component Quantities - Rectangular Component Height: 150 mm; Rectangular Component Width: 10 mm
Metaal - Staal C wit | verdieping | Metaal - Staal C wit | 5.00436 | 0.000444 | 0.000629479 | 0.000629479
Cement - Dekvloer | verdieping | Cement - Dekvloer | 2380.57 |  | 1.25293 | 1.25293 | Component Quantities - Projected Component Area (Net): 15.8168 m2; Projected Component Area (Gross): 15.8168 m2; Component Thickness: 80 mm
Beton gewapend C vloer | verdieping | Beton gewapend C vloer | 18575.6 |  | 7.73984 | 7.73984 | Component Quantities - Projected Component Area (Net): 24.187 m2; Projected Component Area (Gross): 24.187 m2; Component Thickness: 320 mm
5 x 32 Hout binnenkozijn oregon pine | verdieping | 32 Hout binnenkozijn oregon pine | 66.6099 |  | 0.121109 | 0.121109
5 x Glas | verdieping | Glas | 108.49 |  | 0.0497659 | 0.0497659
5 x Membraan - rubber | verdieping | Membraan - rubber | 1.02211 |  | 0.000973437 | 0.000973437
7 x  | verdieping |  |  |  | 0.0435626 | 0.0435626
Steen - Baksteen | verdieping | Steen - Baksteen | 631.096 | 0.0738501 | 0.394435 | 0.399529 | Component Quantities - Rectangular Component Height: 1055 mm; Rectangular Component Width: 70.0001 mm
Isolatie - Kunststof hard | verdieping | Isolatie - Kunststof hard | 305.906 | 1.3901 | 3.05906 | 6.67489
Steen - Kalkzandsteen C | verdieping | Steen - Kalkzandsteen C | 1583.17 | 0.165 | 0.83325 | 0.83325 | Component Quantities - Rectangular Component Height: 1100 mm; Rectangular Component Width: 150 mm
Steen - Baksteen | verdieping | Steen - Baksteen | 3152.51 | 0.0738501 | 1.97032 | 1.97032 | Component Quantities - Rectangular Component Height: 1055 mm; Rectangular Component Width: 70.0001 mm
Isolatie - Kunststof hard | verdieping | Isolatie - Kunststof hard | 400.573 | 1.3901 | 4.00573 | 36.9634
Steen - Kalkzandsteen C | verdieping | Steen - Kalkzandsteen C | 8276.4 | 0.165 | 4.356 | 4.356 | Component Quantities - Rectangular Component Height: 1100 mm; Rectangular Component Width: 150 mm
48 vloeivloer Bolidt | verdieping | 48 vloeivloer Bolidt | 0.0728358 | 0.0000999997 | 0.0000523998 | 0.0000523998 | Component Quantities - Rectangular Component Height: 50 mm; Rectangular Component Width: 1.99999 mm
Tegels - Wand | verdieping | Tegels - Wand | 30.7326 | 0.0255 | 0.013362 | 0.013362 | Component Quantities - Rectangular Component Height: 2550 mm; Rectangular Component Width: 10 mm
48 vloeivloer Bolidt | verdieping | 48 vloeivloer Bolidt | 0.126212 | 0.0000999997 | 0.0000907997 | 0.0000907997 | Component Quantities - Rectangular Component Height: 50 mm; Rectangular Component Width: 1.99999 mm
Tegels - Wand | verdieping | Tegels - Wand | 52.785 | 0.0255 | 0.02295 | 0.02295 | Component Quantities - Rectangular Component Height: 2550 mm; Rectangular Component Width: 10 mm
ALG - LICHTE SCHEIDINGSWAND | verdieping | ALG - LICHTE SCHEIDINGSWAND | 1409.01 | 0.364 | 1.76126 | 3.28957 | Component Quantities - Rectangular Component Height: 3640 mm; Rectangular Component Width: 100 mm; Projected Component Area (Net): 17.7665 m2; Projected Component Area (Gross): 33.432 m2; Component Thickness: 100 mm
ALG - LICHTE SCHEIDINGSWAND | verdieping | ALG - LICHTE SCHEIDINGSWAND | 1248.51 | 0.364 | 1.56064 | 3.05409 | Component Quantities - Rectangular Component Height: 3640 mm; Rectangular Component Width: 100 mm; Projected Component Area (Net): 17.9062 m2; Projected Component Area (Gross): 32.8407 m2; Component Thickness: 100 mm
Tegels - Wand | verdieping | Tegels - Wand | 90.6729 | 0.0255 | 0.039423 | 0.039423 | Component Quantities - Rectangular Component Height: 2550 mm; Rectangular Component Width: 10 mm
48 vloeivloer Bolidt | verdieping | 48 vloeivloer Bolidt | 0.216005 | 0.0000999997 | 0.0001554 | 0.0001554 | Component Quantities - Rectangular Component Height: 50 mm; Rectangular Component Width: 1.99999 mm
4 x  | verdieping |  |  |  | 0.0699171 | 0.0699171
3 x Hout C | verdieping | Hout C | 23.4225 |  | 0.0425863 | 0.0425863
3 x Glas | verdieping | Glas | 56.4052 |  | 0.0258739 | 0.0258739
2 x Metaal - Staal C | verdieping | Metaal - Staal C | 268.265 | 0.0057 | 0.033744 | 0.033744 | Component Quantities - Rectangular Component Height: 19 mm; Rectangular Component Width: 300 mm
Metaal - Staal C | verdieping | Metaal - Staal C | 138.949 | 0.002882 | 0.0174779 | 0.0174779 | Component Quantities - Rectangular Component Height: 262 mm; Rectangular Component Width: 11 mm
10 x Metaal - Staal C | verdieping | Metaal - Staal C | 7.20667 | 0.00098 | 0.0009065 | 0.0009065 | Component Quantities - Rectangular Component Height: 7 mm; Rectangular Component Width: 140 mm
5 x Metaal - Staal C | verdieping | Metaal - Staal C | 4.63286 | 0.00063 | 0.00058275 | 0.00058275 | Component Quantities - Rectangular Component Height: 126 mm; Rectangular Component Width: 5 mm
2 x Beton gewapend C vloer | verdieping | Beton gewapend C vloer | 282.03 | 0.0595 | 0.117513 | 0.117513
4 x Metaal - Staal C | verdieping | Metaal - Staal C | 47.1037 | 0.003 | 0.005925 | 0.005925 | Component Quantities - Rectangular Component Height: 15 mm; Rectangular Component Width: 200 mm
2 x Metaal - Staal C | verdieping | Metaal - Staal C | 26.6921 | 0.0017 | 0.0033575 | 0.0033575 | Component Quantities - Rectangular Component Height: 170 mm; Rectangular Component Width: 10 mm
2 x Metaal - Staal C | verdieping | Metaal - Staal C | 82.9026 | 0.00528 | 0.010428 | 0.010428 | Component Quantities - Rectangular Component Height: 12 mm; Rectangular Component Width: 440 mm
ALG - LICHTE SCHEIDINGSWAND | verdieping | ALG - LICHTE SCHEIDINGSWAND | 1243.9 | 0.364 | 1.55488 | 3.04833 | Component Quantities - Rectangular Component Height: 3640 mm; Rectangular Component Width: 100 mm; Projected Component Area (Net): 17.9062 m2; Projected Component Area (Gross): 32.8407 m2; Component Thickness: 100 mm
ALG - LICHTE SCHEIDINGSWAND | verdieping | ALG - LICHTE SCHEIDINGSWAND | 1409.05 | 0.364 | 1.76132 | 3.28962 | Component Quantities - Rectangular Component Height: 3640 mm; Rectangular Component Width: 100 mm; Projected Component Area (Net): 17.7677 m2; Projected Component Area (Gross): 33.4332 m2; Component Thickness: 100 mm
ALG - LICHTE SCHEIDINGSWAND | verdieping | ALG - LICHTE SCHEIDINGSWAND | 1267.69 | 0.364 | 1.58461 | 3.05171 | Component Quantities - Rectangular Component Height: 3640 mm; Rectangular Component Width: 100 mm; Projected Component Area (Net): 17.0518 m2; Projected Component Area (Gross): 31.7738 m2; Component Thickness: 100 mm
ALG - LICHTE SCHEIDINGSWAND | verdieping | ALG - LICHTE SCHEIDINGSWAND | 1233.25 | 0.364 | 1.54156 | 2.99677 | Component Quantities - Rectangular Component Height: 3640 mm; Rectangular Component Width: 100 mm; Projected Component Area (Net): 16.5037 m2; Projected Component Area (Gross): 31.0557 m2; Component Thickness: 100 mm
Glas sticker | verdieping | Glas sticker | 24.9117 |  | 0.0114274 | 0.0114274
Hout C | verdieping | Hout C | 45.5986 |  | 0.0829066 | 0.0829066
2 x Glas | verdieping | Glas | 58.6287 |  | 0.0268939 | 0.0268939
2 x Metaal - Aluminium | verdieping | Metaal - Aluminium | 1.45688 |  | 0.000520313 | 0.000520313
2 x 32 Hout binnenkozijn oregon pine | verdieping | 32 Hout binnenkozijn oregon pine | 54.3715 |  | 0.0988573 | 0.0988573
3 x Kunststof Kupan | verdieping | Kunststof Kupan | 36.3532 | 0.0273 | 0.0261534 | 0.0752934 | Component Quantities - Rectangular Component Height: 2100 mm; Rectangular Component Width: 13 mm
3 x Metaal - Aluminium | verdieping | Metaal - Aluminium | 7.7224 | 0.001 | 0.002758 | 0.002758 | Component Quantities - Rectangular Component Height: 50 mm; Rectangular Component Width: 20 mm
3 x ALG - LICHTE SCHEIDINGSWAND AFW | verdieping | ALG - LICHTE SCHEIDINGSWAND AFW | 95.6928 | 0.04272 | 0.119616 | 0.119616 | Component Quantities - Rectangular Component Height: 3560 mm; Rectangular Component Width: 12 mm; Projected Component Area (Net): 9.968 m2; Projected Component Area (Gross): 9.968 m2; Component Thickness: 12 mm
3 x Hout - Multiplex wbp | verdieping | Hout - Multiplex wbp | 125.597 | 0.06408 | 0.179424 | 0.179424 | Component Quantities - Rectangular Component Height: 3560 mm; Rectangular Component Width: 18 mm; Projected Component Area (Net): 9.968 m2; Projected Component Area (Gross): 9.968 m2; Component Thickness: 18 mm
Tegels - Wand | verdieping | Tegels - Wand | 9.38401 | 0.0255 | 0.00408 | 0.00408 | Component Quantities - Rectangular Component Height: 2550 mm; Rectangular Component Width: 10 mm
48 vloeivloer Bolidt | verdieping | 48 vloeivloer Bolidt | 0.0222399 | 0.0000999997 | 0.000016 | 0.000016 | Component Quantities - Rectangular Component Height: 50 mm; Rectangular Component Width: 1.99999 mm
2 x Tegels - Wand | verdieping | Tegels - Wand | 143.693 | 0.0255 | 0.062475 | 0.062475 | Component Quantities - Rectangular Component Height: 2550 mm; Rectangular Component Width: 10 mm
2 x 48 vloeivloer Bolidt | verdieping | 48 vloeivloer Bolidt | 0.340549 | 0.0000999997 | 0.000244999 | 0.000244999 | Component Quantities - Rectangular Component Height: 50 mm; Rectangular Component Width: 1.99999 mm
4 x Tegels - Wand | verdieping | Tegels - Wand | 162.461 | 0.0255 | 0.070635 | 0.070635 | Component Quantities - Rectangular Component Height: 2550 mm; Rectangular Component Width: 10 mm
4 x 48 vloeivloer Bolidt | verdieping | 48 vloeivloer Bolidt | 0.386141 | 0.0000999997 | 0.000277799 | 0.000277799 | Component Quantities - Rectangular Component Height: 50 mm; Rectangular Component Width: 1.99999 mm
2 x Tegels - Wand | verdieping | Tegels - Wand | 142.52 | 0.0255 | 0.061965 | 0.061965 | Component Quantities - Rectangular Component Height: 2550 mm; Rectangular Component Width: 10 mm
2 x 48 vloeivloer Bolidt | verdieping | 48 vloeivloer Bolidt | 0.339993 | 0.0000999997 | 0.000244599 | 0.000244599 | Component Quantities - Rectangular Component Height: 50 mm; Rectangular Component Width: 1.99999 mm
48 vloeivloer Bolidt | verdieping | 48 vloeivloer Bolidt | 0.172916 | 0.0000999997 | 0.0001244 | 0.0001244 | Component Quantities - Rectangular Component Height: 50 mm; Rectangular Component Width: 1.99999 mm
Tegels - Wand | verdieping | Tegels - Wand | 72.4914 | 0.0255 | 0.031518 | 0.031518 | Component Quantities - Rectangular Component Height: 2550 mm; Rectangular Component Width: 10 mm
48 vloeivloer Bolidt | verdieping | 48 vloeivloer Bolidt | 0.386836 | 0.0000999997 | 0.000278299 | 0.000278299 | Component Quantities - Rectangular Component Height: 50 mm; Rectangular Component Width: 1.99999 mm
Tegels - Wand | verdieping | Tegels - Wand | 163.223 | 0.0255 | 0.0709665 | 0.0709665 | Component Quantities - Rectangular Component Height: 2550 mm; Rectangular Component Width: 10 mm
48 vloeivloer Bolidt | verdieping | 48 vloeivloer Bolidt | 0.194043 | 0.0000999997 | 0.0001396 | 0.0001396 | Component Quantities - Rectangular Component Height: 50 mm; Rectangular Component Width: 1.99999 mm
Tegels - Wand | verdieping | Tegels - Wand | 81.8754 | 0.0255 | 0.035598 | 0.035598 | Component Quantities - Rectangular Component Height: 2550 mm; Rectangular Component Width: 10 mm
Metaal - Staal C | verdieping | Metaal - Staal C | 206.273 | 0.00185 | 0.0259463 | 0.0259463
Metaal - Staal C | verdieping | Metaal - Staal C | 14.8293 | 0.000133 | 0.00186532 | 0.00186532 | Component Quantities - Rectangular Component Height: 1 mm; Rectangular Component Width: 133 mm
Glas | verdieping | Glas | 12.6288 | 0.01635 | 0.00579303 | 0.00651845 | Component Quantities - Rectangular Component Height: 1090 mm; Rectangular Component Width: 15 mm
Membraan - rubber | verdieping | Membraan - rubber | 0.666414 | 0.00265 | 0.00063468 | 0.00063468
Metaal - Staal C wit | verdieping | Metaal - Staal C wit | 3.56472 | 0.002 | 0.000448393 | 0.000448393 | Component Quantities - Rectangular Component Height: 200 mm; Rectangular Component Width: 10 mm
Metaal - Staal C wit | verdieping | Metaal - Staal C wit | 2.7697 | 0.0015 | 0.00034839 | 0.00034839 | Component Quantities - Rectangular Component Height: 150 mm; Rectangular Component Width: 10 mm
Metaal - Staal C wit | verdieping | Metaal - Staal C wit | 0.768598 | 0.000444 | 0.0000966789 | 0.0000966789
Glas | verdieping | Glas | 91.6153 | 0.0189 | 0.0420254 | 0.0589179 | Component Quantities - Rectangular Component Height: 1260 mm; Rectangular Component Width: 15 mm
Membraan - rubber | verdieping | Membraan - rubber | 9.46489 | 0.00265 | 0.00901418 | 0.00901418
Metaal - Staal C wit | verdieping | Metaal - Staal C wit | 54.385 | 0.002 | 0.00684088 | 0.00684088 | Component Quantities - Rectangular Component Height: 200 mm; Rectangular Component Width: 10 mm
Metaal - Staal C wit | verdieping | Metaal - Staal C wit | 40.6702 | 0.0015 | 0.00511575 | 0.00511575 | Component Quantities - Rectangular Component Height: 150 mm; Rectangular Component Width: 10 mm
Metaal - Staal C wit | verdieping | Metaal - Staal C wit | 12.1015 | 0.000444 | 0.0015222 | 0.0015222
Glas | verdieping | Glas | 64.4479 | 0.0189 | 0.0295633 | 0.0313835 | Component Quantities - Rectangular Component Height: 1260 mm; Rectangular Component Width: 15 mm
Membraan - rubber | verdieping | Membraan - rubber | 4.14454 | 0.00265 | 0.00394718 | 0.00394718
Metaal - Staal C wit | verdieping | Metaal - Staal C wit | 23.4397 | 0.002 | 0.00294839 | 0.00294839 | Component Quantities - Rectangular Component Height: 200 mm; Rectangular Component Width: 10 mm
Metaal - Staal C wit | verdieping | Metaal - Staal C wit | 17.676 | 0.0015 | 0.00222339 | 0.00222339 | Component Quantities - Rectangular Component Height: 150 mm; Rectangular Component Width: 10 mm
Metaal - Staal C wit | verdieping | Metaal - Staal C wit | 5.18085 | 0.000444 | 0.000651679 | 0.000651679
2 x ALG - LICHTE SCHEIDINGSWAND | verdieping | ALG - LICHTE SCHEIDINGSWAND | 230.4 | 0.356 | 0.288 | 1.068 | Component Quantities - Rectangular Component Height: 3560 mm; Rectangular Component Width: 100 mm; Projected Component Area (Net): 2.88 m2; Projected Component Area (Gross): 10.68 m2; Component Thickness: 100 mm
Hout - Multiplex wbp | verdieping | Hout - Multiplex wbp | 41.7161 | 0.06408 | 0.0595944 | 0.0595944 | Component Quantities - Rectangular Component Height: 3560 mm; Rectangular Component Width: 18 mm; Projected Component Area (Net): 3.3108 m2; Projected Component Area (Gross): 3.3108 m2; Component Thickness: 18 mm
ALG - LICHTE SCHEIDINGSWAND AFW | verdieping | ALG - LICHTE SCHEIDINGSWAND AFW | 31.7837 | 0.04272 | 0.0397296 | 0.0397296 | Component Quantities - Rectangular Component Height: 3560 mm; Rectangular Component Width: 12 mm; Projected Component Area (Net): 3.3108 m2; Projected Component Area (Gross): 3.3108 m2; Component Thickness: 12 mm
2 x Metaal - Staal C | verdieping | Metaal - Staal C | 9.54002 | 0.003 | 0.0012 | 0.0012 | Component Quantities - Rectangular Component Height: 15 mm; Rectangular Component Width: 200 mm
Metaal - Staal C | verdieping | Metaal - Staal C | 4.86541 | 0.00153 | 0.000612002 | 0.000612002 | Component Quantities - Rectangular Component Height: 170 mm; Rectangular Component Width: 9 mm
ALG - LICHTE SCHEIDINGSWAND | verdieping | ALG - LICHTE SCHEIDINGSWAND | 107.728 | 0.356 | 0.13466 | 0.4984 | Component Quantities - Rectangular Component Height: 3560 mm; Rectangular Component Width: 100 mm; Projected Component Area (Net): 1.3466 m2; Projected Component Area (Gross): 4.984 m2; Component Thickness: 100 mm
ALG - LICHTE SCHEIDINGSWAND | verdieping | ALG - LICHTE SCHEIDINGSWAND | 143.328 | 0.356 | 0.17916 | 0.5429 | Component Quantities - Rectangular Component Height: 3560 mm; Rectangular Component Width: 100 mm; Projected Component Area (Net): 1.7916 m2; Projected Component Area (Gross): 5.429 m2; Component Thickness: 100 mm
ALG - LICHTE SCHEIDINGSWAND | verdieping | ALG - LICHTE SCHEIDINGSWAND | 245.022 | 0.14 | 0.306277 | 0.306277 | Component Quantities - Rectangular Component Height: 1400 mm; Rectangular Component Width: 100 mm; Projected Component Area (Net): 3.16628 m2; Projected Component Area (Gross): 3.16628 m2; Component Thickness: 100 mm
ALG - LICHTE SCHEIDINGSWAND | verdieping | ALG - LICHTE SCHEIDINGSWAND | 295.236 | 0.14 | 0.369045 | 0.369045 | Component Quantities - Rectangular Component Height: 1400 mm; Rectangular Component Width: 100 mm; Projected Component Area (Net): 3.71 m2; Projected Component Area (Gross): 3.71 m2; Component Thickness: 100 mm
ALG - LICHTE SCHEIDINGSWAND | verdieping | ALG - LICHTE SCHEIDINGSWAND | 211.968 | 0.356 | 0.26496 | 0.970363 | Component Quantities - Rectangular Component Height: 3560 mm; Rectangular Component Width: 100 mm; Projected Component Area (Net): 2.6496 m2; Projected Component Area (Gross): 9.8256 m2; Component Thickness: 100 mm
ALG - LICHTE SCHEIDINGSWAND | verdieping | ALG - LICHTE SCHEIDINGSWAND | 211.968 | 0.356 | 0.26496 | 0.966661 | Component Quantities - Rectangular Component Height: 3560 mm; Rectangular Component Width: 100 mm; Projected Component Area (Net): 2.6496 m2; Projected Component Area (Gross): 9.8256 m2; Component Thickness: 100 mm
48 vloeivloer Bolidt | verdieping | 48 vloeivloer Bolidt | 0.019182 | 0.0000999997 | 0.0000138 | 0.0000138 | Component Quantities - Rectangular Component Height: 50 mm; Rectangular Component Width: 1.99999 mm
Tegels - Wand | verdieping | Tegels - Wand | 7.62451 | 0.0255 | 0.003315 | 0.003315 | Component Quantities - Rectangular Component Height: 2550 mm; Rectangular Component Width: 10 mm
48 vloeivloer Bolidt | verdieping | 48 vloeivloer Bolidt | 0.233241 | 0.0000999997 | 0.0001678 | 0.0001678 | Component Quantities - Rectangular Component Height: 50 mm; Rectangular Component Width: 1.99999 mm
Tegels - Wand | verdieping | Tegels - Wand | 97.9455 | 0.0255 | 0.042585 | 0.042585 | Component Quantities - Rectangular Component Height: 2550 mm; Rectangular Component Width: 10 mm
48 vloeivloer Bolidt | verdieping | 48 vloeivloer Bolidt | 0.0261319 | 0.0000999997 | 0.0000187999 | 0.0000187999 | Component Quantities - Rectangular Component Height: 50 mm; Rectangular Component Width: 1.99999 mm
Tegels - Wand | verdieping | Tegels - Wand | 10.557 | 0.0255 | 0.00459 | 0.00459 | Component Quantities - Rectangular Component Height: 2550 mm; Rectangular Component Width: 10 mm
48 vloeivloer Bolidt | verdieping | 48 vloeivloer Bolidt | 0.233519 | 0.0000999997 | 0.000168 | 0.000168 | Component Quantities - Rectangular Component Height: 50 mm; Rectangular Component Width: 1.99999 mm
Tegels - Wand | verdieping | Tegels - Wand | 98.532 | 0.0255 | 0.04284 | 0.04284 | Component Quantities - Rectangular Component Height: 2550 mm; Rectangular Component Width: 10 mm
48 vloeivloer Bolidt | verdieping | 48 vloeivloer Bolidt | 0.344441 | 0.0000999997 | 0.000247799 | 0.000247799 | Component Quantities - Rectangular Component Height: 50 mm; Rectangular Component Width: 1.99999 mm
Tegels - Wand | verdieping | Tegels - Wand | 144.865 | 0.0255 | 0.062985 | 0.062985 | Component Quantities - Rectangular Component Height: 2550 mm; Rectangular Component Width: 10 mm
2 x ALG - LICHTE SCHEIDINGSWAND | verdieping | ALG - LICHTE SCHEIDINGSWAND | 475.024 | 0.356 | 0.59378 | 0.59378 | Component Quantities - Rectangular Component Height: 3560 mm; Rectangular Component Width: 100 mm; Projected Component Area (Net): 5.9378 m2; Projected Component Area (Gross): 5.9378 m2; Component Thickness: 100 mm
2 x Metaal - Staal C | verdieping | Metaal - Staal C | 924.199 | 0.0057 | 0.116251 | 0.116251 | Component Quantities - Rectangular Component Height: 19 mm; Rectangular Component Width: 300 mm
Metaal - Staal C | verdieping | Metaal - Staal C | 463.977 | 0.002882 | 0.0583619 | 0.0583619 | Component Quantities - Rectangular Component Height: 262 mm; Rectangular Component Width: 11 mm
Metaal - Staal C | verdieping | Metaal - Staal C | 1542.39 | 0.0057 | 0.194011 | 0.194011 | Component Quantities - Rectangular Component Height: 19 mm; Rectangular Component Width: 300 mm
Metaal - Staal C | verdieping | Metaal - Staal C | 1567.31 | 0.0057 | 0.197146 | 0.197146 | Component Quantities - Rectangular Component Height: 19 mm; Rectangular Component Width: 300 mm
Metaal - Staal C | verdieping | Metaal - Staal C | 799.027 | 0.002882 | 0.100507 | 0.100507 | Component Quantities - Rectangular Component Height: 262 mm; Rectangular Component Width: 11 mm
2 x Metaal - Staal C | verdieping | Metaal - Staal C | 1585.44 | 0.0057 | 0.199426 | 0.199426 | Component Quantities - Rectangular Component Height: 19 mm; Rectangular Component Width: 300 mm
Metaal - Staal C | verdieping | Metaal - Staal C | 801.619 | 0.002882 | 0.100833 | 0.100833 | Component Quantities - Rectangular Component Height: 262 mm; Rectangular Component Width: 11 mm
Beton gewapend C vloer | verdieping | Beton gewapend C vloer | 5765.51 | 0.0932915 | 2.40229 | 2.40229
2 x Metaal - Staal C | verdieping | Metaal - Staal C | 1262.16 | 0.00615 | 0.158762 | 0.158762 | Component Quantities - Rectangular Component Height: 20.5 mm; Rectangular Component Width: 300 mm
Metaal - Staal C | verdieping | Metaal - Staal C | 667.75 | 0.0032085 | 0.0839937 | 0.0839937 | Component Quantities - Rectangular Component Height: 279 mm; Rectangular Component Width: 11.5 mm
Metaal - Staal C | verdieping | Metaal - Staal C | 2199.76 | 0.011 | 0.276699 | 0.276699 | Component Quantities - Rectangular Component Height: 20 mm; Rectangular Component Width: 550 mm
Metaal - Staal C | verdieping | Metaal - Staal C | 1141.48 | 0.0057 | 0.143583 | 0.143583 | Component Quantities - Rectangular Component Height: 19 mm; Rectangular Component Width: 300 mm
Metaal - Staal C | verdieping | Metaal - Staal C | 1166.41 | 0.0057 | 0.146718 | 0.146718 | Component Quantities - Rectangular Component Height: 19 mm; Rectangular Component Width: 300 mm
Metaal - Staal C | verdieping | Metaal - Staal C | 589.704 | 0.002882 | 0.0741766 | 0.0741766 | Component Quantities - Rectangular Component Height: 262 mm; Rectangular Component Width: 11 mm
2 x Metaal - Staal C | verdieping | Metaal - Staal C | 579.126 | 0.0057 | 0.072846 | 0.072846 | Component Quantities - Rectangular Component Height: 19 mm; Rectangular Component Width: 300 mm
Metaal - Staal C | verdieping | Metaal - Staal C | 292.814 | 0.002882 | 0.036832 | 0.036832 | Component Quantities - Rectangular Component Height: 262 mm; Rectangular Component Width: 11 mm
Hout - Spaanplaat | verdieping | Hout - Spaanplaat | 58.9123 | 0.004164 | 0.0981871 | 0.0981871 | Component Quantities - Rectangular Component Height: 347 mm; Rectangular Component Width: 12 mm
Steen - Kalkzandsteen C | verdieping | Steen - Kalkzandsteen C | 14225.8 | 0.546 | 7.48725 | 12.9129 | Component Quantities - Rectangular Component Height: 3640 mm; Rectangular Component Width: 150 mm
Hout - Vloer | verdieping | Hout - Vloer | 62.1272 | 0.004788 | 0.112958 | 0.112958 | Component Quantities - Rectangular Component Height: 38 mm; Rectangular Component Width: 126 mm
Isolatie - Steenwol LSW | verdieping | Isolatie - Steenwol LSW | 44.3065 | 0.034146 | 0.805572 | 0.805572 | Component Quantities - Rectangular Component Height: 271 mm; Rectangular Component Width: 126 mm
Hout - Vloer | verdieping | Hout - Vloer | 62.1271 | 0.004788 | 0.112958 | 0.112958 | Component Quantities - Rectangular Component Height: 38 mm; Rectangular Component Width: 126 mm
ALG - LICHTE SCHEIDINGSWAND | verdieping | ALG - LICHTE SCHEIDINGSWAND | 3.31199 | 0.00195 | 0.00413999 | 0.00413999 | Component Quantities - Rectangular Component Height: 13 mm; Rectangular Component Width: 150 mm
Hout - Spaanplaat | verdieping | Hout - Spaanplaat | 59.257 | 0.004164 | 0.0987617 | 0.0987617 | Component Quantities - Rectangular Component Height: 347 mm; Rectangular Component Width: 12 mm
Isolatie - Kunststof hard | verdieping | Isolatie - Kunststof hard | 1028.83 | 0.6482 | 10.2883 | 15.4137 | Component Quantities - Rectangular Component Height: 4630 mm; Rectangular Component Width: 140 mm
Steen - Baksteen | verdieping | Steen - Baksteen | 7767.52 | 0.3248 | 4.8547 | 7.79826 | Component Quantities - Rectangular Component Height: 4640 mm; Rectangular Component Width: 70 mm
Beton gewapend C vloer | verdieping | Beton gewapend C vloer | 1007.73 | 0.0932915 | 0.419886 | 0.419886
2 x Metaal - Staal C | verdieping | Metaal - Staal C | 220.505 | 0.00615 | 0.0277365 | 0.0277365 | Component Quantities - Rectangular Component Height: 20.5 mm; Rectangular Component Width: 300 mm
Metaal - Staal C | verdieping | Metaal - Staal C | 115.039 | 0.0032085 | 0.0144703 | 0.0144703 | Component Quantities - Rectangular Component Height: 279 mm; Rectangular Component Width: 11.5 mm
Metaal - Staal C | verdieping | Metaal - Staal C | 394.399 | 0.011 | 0.04961 | 0.04961 | Component Quantities - Rectangular Component Height: 20 mm; Rectangular Component Width: 550 mm
Cement - Dekvloer | verdieping | Cement - Dekvloer | 288.739 |  | 0.151968 | 0.1392 | Component Quantities - Projected Component Area (Net): 1.8996 m2; Projected Component Area (Gross): 1.74 m2; Component Thickness: 80 mm
Beton gewapend C vloer | verdieping | Beton gewapend C vloer | 1981.44 |  | 0.8256 | 0.8256 | Component Quantities - Projected Component Area (Net): 2.58 m2; Projected Component Area (Gross): 2.58 m2; Component Thickness: 320 mm
Cement - Dekvloer | verdieping | Cement - Dekvloer | 604.926 |  | 0.318382 | 0.297102 | Component Quantities - Projected Component Area (Net): 3.97978 m2; Projected Component Area (Gross): 3.71378 m2; Component Thickness: 80 mm
Beton gewapend prefab vloer | verdieping | Beton gewapend prefab vloer | 3832.82 |  | 1.59701 | 1.59701 | Component Quantities - Projected Component Area (Net): 4.99065 m2; Projected Component Area (Gross): 4.99065 m2; Component Thickness: 320 mm
Cement - Dekvloer | verdieping | Cement - Dekvloer | 1233.18 |  | 0.64904 | 0.64904 | Component Quantities - Projected Component Area (Net): 8.113 m2; Projected Component Area (Gross): 8.113 m2; Component Thickness: 80 mm
Beton gewapend prefab vloer | verdieping | Beton gewapend prefab vloer | 6816.38 |  | 2.84016 | 2.84016 | Component Quantities - Projected Component Area (Net): 8.8755 m2; Projected Component Area (Gross): 8.8755 m2; Component Thickness: 320 mm
Cement - Dekvloer | verdieping | Cement - Dekvloer | 1190.53 |  | 0.626595 | 0.621488 | Component Quantities - Projected Component Area (Net): 7.83244 m2; Projected Component Area (Gross): 7.7686 m2; Component Thickness: 80 mm
2 x Beton gewapend prefab vloer | verdieping | Beton gewapend prefab vloer | 6641.09 |  | 2.76712 | 2.76712 | Component Quantities - Projected Component Area (Net): 8.64725 m2; Projected Component Area (Gross): 8.64725 m2; Component Thickness: 320 mm
Cement - Dekvloer | verdieping | Cement - Dekvloer | 12319.7 |  | 6.48406 | 6.48406 | Component Quantities - Projected Component Area (Net): 81.0507 m2; Projected Component Area (Gross): 81.0507 m2; Component Thickness: 80 mm
Beton gewapend prefab vloer | verdieping | Beton gewapend prefab vloer | 62246.9 |  | 25.9362 | 25.9362 | Component Quantities - Projected Component Area (Net): 81.0507 m2; Projected Component Area (Gross): 81.0507 m2; Component Thickness: 320 mm
Cement - Dekvloer | verdieping | Cement - Dekvloer | 15286.9 |  | 8.04576 | 8.04576 | Component Quantities - Projected Component Area (Net): 100.572 m2; Projected Component Area (Gross): 100.572 m2; Component Thickness: 80 mm
Beton gewapend prefab vloer | verdieping | Beton gewapend prefab vloer | 78609 |  | 32.7538 | 32.7538 | Component Quantities - Projected Component Area (Net): 102.356 m2; Projected Component Area (Gross): 102.356 m2; Component Thickness: 320 mm
Cement - Dekvloer | verdieping | Cement - Dekvloer | 1197 |  | 0.63 | 0.621488 | Component Quantities - Projected Component Area (Net): 7.875 m2; Projected Component Area (Gross): 7.7686 m2; Component Thickness: 80 mm
Cement - Dekvloer | verdieping | Cement - Dekvloer | 57809.5 |  | 30.4261 | 30.4093 | Component Quantities - Projected Component Area (Net): 380.476 m2; Projected Component Area (Gross): 380.266 m2; Component Thickness: 80 mm
Beton gewapend prefab vloer | verdieping | Beton gewapend prefab vloer | 296229 |  | 123.429 | 123.429 | Component Quantities - Projected Component Area (Net): 385.714 m2; Projected Component Area (Gross): 385.714 m2; Component Thickness: 320 mm
Cement - Dekvloer | verdieping | Cement - Dekvloer | 43742.3 |  | 23.0222 | 22.9969 | Component Quantities - Projected Component Area (Net): 287.91 m2; Projected Component Area (Gross): 287.593 m2; Component Thickness: 80 mm
Beton gewapend prefab vloer | verdieping | Beton gewapend prefab vloer | 222143 |  | 92.5597 | 92.5597 | Component Quantities - Projected Component Area (Net): 289.249 m2; Projected Component Area (Gross): 289.249 m2; Component Thickness: 320 mm
Cement - Dekvloer | verdieping | Cement - Dekvloer | 12509.3 |  | 6.58383 | 6.58383 | Component Quantities - Projected Component Area (Net): 82.2978 m2; Projected Component Area (Gross): 82.2978 m2; Component Thickness: 80 mm
Beton gewapend prefab vloer | verdieping | Beton gewapend prefab vloer | 63866.4 |  | 26.611 | 26.611 | Component Quantities - Projected Component Area (Net): 83.1594 m2; Projected Component Area (Gross): 83.1594 m2; Component Thickness: 320 mm
Cement - Dekvloer | verdieping | Cement - Dekvloer | 17502.3 |  | 9.21174 | 9.21174 | Component Quantities - Projected Component Area (Net): 115.147 m2; Projected Component Area (Gross): 115.147 m2; Component Thickness: 80 mm
Beton gewapend prefab vloer | verdieping | Beton gewapend prefab vloer | 88530.1 |  | 36.8875 | 36.8875 | Component Quantities - Projected Component Area (Net): 115.274 m2; Projected Component Area (Gross): 115.274 m2; Component Thickness: 320 mm
14 x Metaal - Staal C | verdieping | Metaal - Staal C | 38.5265 | 0.00098 | 0.0048461 | 0.0048461 | Component Quantities - Rectangular Component Height: 7 mm; Rectangular Component Width: 140 mm
7 x Metaal - Staal C | verdieping | Metaal - Staal C | 24.767 | 0.00063 | 0.00311535 | 0.00311535 | Component Quantities - Rectangular Component Height: 126 mm; Rectangular Component Width: 5 mm
8 x Metaal - Staal C | verdieping | Metaal - Staal C | 37.3189 | 0.00098 | 0.0046942 | 0.0046942 | Component Quantities - Rectangular Component Height: 7 mm; Rectangular Component Width: 140 mm
4 x Metaal - Staal C | verdieping | Metaal - Staal C | 23.9907 | 0.00063 | 0.0030177 | 0.0030177 | Component Quantities - Rectangular Component Height: 126 mm; Rectangular Component Width: 5 mm
Beton gewapend C vloer | verdieping | Beton gewapend C vloer | 6284.3 | 0.0932915 | 2.61846 | 2.61846
4 x Metaal - Staal C | verdieping | Metaal - Staal C | 1372.96 | 0.00615 | 0.172699 | 0.172699 | Component Quantities - Rectangular Component Height: 20.5 mm; Rectangular Component Width: 300 mm
2 x Metaal - Staal C | verdieping | Metaal - Staal C | 716.282 | 0.0032085 | 0.0900984 | 0.0900984 | Component Quantities - Rectangular Component Height: 279 mm; Rectangular Component Width: 11.5 mm
Metaal - Staal C | verdieping | Metaal - Staal C | 2430.73 | 0.011 | 0.305752 | 0.305752 | Component Quantities - Rectangular Component Height: 20 mm; Rectangular Component Width: 550 mm
Beton gewapend C vloer | verdieping | Beton gewapend C vloer | 6287.36 | 0.0932915 | 2.61973 | 2.61973
Metaal - Staal C | verdieping | Metaal - Staal C | 2427.7 | 0.011 | 0.305371 | 0.305371 | Component Quantities - Rectangular Component Height: 20 mm; Rectangular Component Width: 550 mm
Cement - Dekvloer | verdieping | Cement - Dekvloer | 88.5255 |  | 0.0465924 | 0.0465924 | Component Quantities - Projected Component Area (Net): 0.582405 m2; Projected Component Area (Gross): 0.582405 m2; Component Thickness: 80 mm
Beton gewapend C vloer | verdieping | Beton gewapend C vloer | 3974.15 |  | 1.65589 | 1.65589 | Component Quantities - Projected Component Area (Net): 5.1756 m2; Projected Component Area (Gross): 5.1756 m2; Component Thickness: 320 mm
Hout - Multiplex | verdieping | Hout - Multiplex | 5.48855 | 0.01296 | 0.00784079 | 0.00784079 | Component Quantities - Rectangular Component Height: 20 mm; Rectangular Component Width: 648 mm
Metaal - Aluminium beige | verdieping | Metaal - Aluminium beige | 1.71316 | 0.000816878 | 0.000611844 | 0.000611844
Metaal - Aluminium beige | verdieping | Metaal - Aluminium beige | 1.04661 | 0.000816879 | 0.000373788 | 0.000373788
48 vloeivloer Bolidt | verdieping | 48 vloeivloer Bolidt | 0.163047 | 0.0000999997 | 0.0001173 | 0.0001173 | Component Quantities - Rectangular Component Height: 50 mm; Rectangular Component Width: 1.99999 mm
Tegels - Wand | verdieping | Tegels - Wand | 68.7964 | 0.0255 | 0.0299115 | 0.0299115 | Component Quantities - Rectangular Component Height: 2550 mm; Rectangular Component Width: 10 mm
2 x 48 vloeivloer Bolidt | verdieping | 48 vloeivloer Bolidt | 0.1709 | 0.0000999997 | 0.00012295 | 0.00012295 | Component Quantities - Rectangular Component Height: 50 mm; Rectangular Component Width: 1.99999 mm
2 x Tegels - Wand | verdieping | Tegels - Wand | 72.5794 | 0.0255 | 0.0315563 | 0.0315563 | Component Quantities - Rectangular Component Height: 2550 mm; Rectangular Component Width: 10 mm
2 x 48 vloeivloer Bolidt | verdieping | 48 vloeivloer Bolidt | 0.161518 | 0.0000999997 | 0.0001162 | 0.0001162 | Component Quantities - Rectangular Component Height: 50 mm; Rectangular Component Width: 1.99999 mm
2 x Tegels - Wand | verdieping | Tegels - Wand | 68.6205 | 0.0255 | 0.029835 | 0.029835 | Component Quantities - Rectangular Component Height: 2550 mm; Rectangular Component Width: 10 mm
48 vloeivloer Bolidt | verdieping | 48 vloeivloer Bolidt | 0.0257844 | 0.0000999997 | 0.0000185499 | 0.0000185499 | Component Quantities - Rectangular Component Height: 50 mm; Rectangular Component Width: 1.99999 mm
Tegels - Wand | verdieping | Tegels - Wand | 11.3488 | 0.0255 | 0.00493425 | 0.00493425 | Component Quantities - Rectangular Component Height: 2550 mm; Rectangular Component Width: 10 mm
48 vloeivloer Bolidt | verdieping | 48 vloeivloer Bolidt | 0.0255064 | 0.0000999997 | 0.0000183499 | 0.0000183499 | Component Quantities - Rectangular Component Height: 50 mm; Rectangular Component Width: 1.99999 mm
Tegels - Wand | verdieping | Tegels - Wand | 10.7623 | 0.0255 | 0.00467925 | 0.00467925 | Component Quantities - Rectangular Component Height: 2550 mm; Rectangular Component Width: 10 mm
48 vloeivloer Bolidt | verdieping | 48 vloeivloer Bolidt | 0.163325 | 0.0000999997 | 0.0001175 | 0.0001175 | Component Quantities - Rectangular Component Height: 50 mm; Rectangular Component Width: 1.99999 mm
Tegels - Wand | verdieping | Tegels - Wand | 69.383 | 0.0255 | 0.0301665 | 0.0301665 | Component Quantities - Rectangular Component Height: 2550 mm; Rectangular Component Width: 10 mm
2 x Beton gewapend C vloer | verdieping | Beton gewapend C vloer | 468.349 | 0.0868915 | 0.195145 | 0.195145
4 x Metaal - Staal C | verdieping | Metaal - Staal C | 109.805 | 0.00615 | 0.013812 | 0.013812 | Component Quantities - Rectangular Component Height: 20.5 mm; Rectangular Component Width: 300 mm
2 x Metaal - Staal C | verdieping | Metaal - Staal C | 57.2862 | 0.0032085 | 0.00720582 | 0.00720582 | Component Quantities - Rectangular Component Height: 279 mm; Rectangular Component Width: 11.5 mm
2 x Metaal - Staal C | verdieping | Metaal - Staal C | 151.763 | 0.0085 | 0.0190897 | 0.0190897 | Component Quantities - Rectangular Component Height: 20 mm; Rectangular Component Width: 425 mm
Beton gewapend C vloer | verdieping | Beton gewapend C vloer | 2584.57 | 0.0932915 | 1.0769 | 1.0769
2 x Metaal - Staal C | verdieping | Metaal - Staal C | 565.197 | 0.00615 | 0.071094 | 0.071094 | Component Quantities - Rectangular Component Height: 20.5 mm; Rectangular Component Width: 300 mm
Metaal - Staal C | verdieping | Metaal - Staal C | 294.868 | 0.0032085 | 0.0370903 | 0.0370903 | Component Quantities - Rectangular Component Height: 279 mm; Rectangular Component Width: 11.5 mm
Metaal - Staal C | verdieping | Metaal - Staal C | 1010.92 | 0.011 | 0.12716 | 0.12716 | Component Quantities - Rectangular Component Height: 20 mm; Rectangular Component Width: 550 mm
Hout - Spaanplaat | verdieping | Hout - Spaanplaat | 52.7213 | 0.004164 | 0.0878688 | 0.0878688 | Component Quantities - Rectangular Component Height: 347 mm; Rectangular Component Width: 12 mm
Steen - Kalkzandsteen C | verdieping | Steen - Kalkzandsteen C | 23144.5 | 0.546 | 12.1813 | 15.5293 | Component Quantities - Rectangular Component Height: 3640 mm; Rectangular Component Width: 150 mm
2 x Hout - Vloer | verdieping | Hout - Vloer | 55.9018 | 0.004788 | 0.10164 | 0.10164 | Component Quantities - Rectangular Component Height: 38 mm; Rectangular Component Width: 126 mm
Isolatie - Steenwol LSW | verdieping | Isolatie - Steenwol LSW | 39.8668 | 0.034146 | 0.724851 | 0.724851 | Component Quantities - Rectangular Component Height: 271 mm; Rectangular Component Width: 126 mm
ALG - LICHTE SCHEIDINGSWAND | verdieping | ALG - LICHTE SCHEIDINGSWAND | 30.5035 | 0.00195 | 0.0381294 | 0.0381294 | Component Quantities - Rectangular Component Height: 13 mm; Rectangular Component Width: 150 mm
Hout - Spaanplaat | verdieping | Hout - Spaanplaat | 53.066 | 0.004164 | 0.0884433 | 0.0884433 | Component Quantities - Rectangular Component Height: 347 mm; Rectangular Component Width: 12 mm
Isolatie - Kunststof hard | verdieping | Isolatie - Kunststof hard | 1535.63 | 0.6482 | 15.3563 | 18.519 | Component Quantities - Rectangular Component Height: 4630 mm; Rectangular Component Width: 140 mm
Steen - Baksteen | verdieping | Steen - Baksteen | 12023.6 | 0.3248 | 7.51474 | 9.32891 | Component Quantities - Rectangular Component Height: 4640 mm; Rectangular Component Width: 70 mm
Cement - Dekvloer | verdieping | Cement - Dekvloer | 4888.46 |  | 2.57288 | 2.47821 | Component Quantities - Projected Component Area (Net): 32.1609 m2; Projected Component Area (Gross): 30.9776 m2; Component Thickness: 80 mm
Beton gewapend prefab vloer | verdieping | Beton gewapend prefab vloer | 26091.2 |  | 10.8713 | 10.8713 | Component Quantities - Projected Component Area (Net): 33.9729 m2; Projected Component Area (Gross): 33.9729 m2; Component Thickness: 320 mm
Metaal - Staal C | verdieping | Metaal - Staal C | 487.105 | 0.00185 | 0.0612711 | 0.0612711
Metaal - Staal C | verdieping | Metaal - Staal C | 35.0189 | 0.000133 | 0.00440489 | 0.00440489 | Component Quantities - Rectangular Component Height: 1 mm; Rectangular Component Width: 133 mm
2 x Metaal - Staal C | verdieping | Metaal - Staal C | 86.7139 | 0.003 | 0.0109074 | 0.0109074 | Component Quantities - Rectangular Component Height: 15 mm; Rectangular Component Width: 200 mm
Metaal - Staal C | verdieping | Metaal - Staal C | 44.2241 | 0.00153 | 0.00556278 | 0.00556278 | Component Quantities - Rectangular Component Height: 170 mm; Rectangular Component Width: 9 mm
Metaal - Staal C wit | verdieping | Metaal - Staal C wit | 187.103 | 0.00180956 | 0.023535 | 0.023535
Metaal - Staal C wit | verdieping | Metaal - Staal C wit | 189.796 | 0.00180956 | 0.0238737 | 0.0238737
Metaal - Staal C wit | verdieping | Metaal - Staal C wit | 172.778 | 0.00180956 | 0.021733 | 0.021733
Metaal - Staal C wit | verdieping | Metaal - Staal C wit | 175.47 | 0.00180956 | 0.0220717 | 0.0220717
Metaal - Staal C wit | verdieping | Metaal - Staal C wit | 1.64983 | 0.00180956 | 0.000207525 | 0.000207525
Metaal - Staal C wit | verdieping | Metaal - Staal C wit | 2.99611 | 0.00180956 | 0.000376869 | 0.000376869
Metaal - Staal C wit | verdieping | Metaal - Staal C wit | 174.359 | 0.00180956 | 0.0219319 | 0.0219319
Metaal - Staal C wit | verdieping | Metaal - Staal C wit | 175.705 | 0.00180956 | 0.0221013 | 0.0221013
4 x Metaal - Staal C | verdieping | Metaal - Staal C | 4.05132 | 0.00098 | 0.0005096 | 0.0005096 | Component Quantities - Rectangular Component Height: 7 mm; Rectangular Component Width: 140 mm
2 x Metaal - Staal C | verdieping | Metaal - Staal C | 2.60442 | 0.00063 | 0.0003276 | 0.0003276 | Component Quantities - Rectangular Component Height: 126 mm; Rectangular Component Width: 5 mm
2 x Metaal - Staal C | verdieping | Metaal - Staal C | 6.15489 | 0.00098 | 0.0007742 | 0.0007742 | Component Quantities - Rectangular Component Height: 7 mm; Rectangular Component Width: 140 mm
Metaal - Staal C | verdieping | Metaal - Staal C | 3.95671 | 0.00063 | 0.0004977 | 0.0004977 | Component Quantities - Rectangular Component Height: 126 mm; Rectangular Component Width: 5 mm
2 x Metaal - Staal C | verdieping | Metaal - Staal C | 7.86891 | 0.00098 | 0.0009898 | 0.0009898 | Component Quantities - Rectangular Component Height: 7 mm; Rectangular Component Width: 140 mm
Metaal - Staal C | verdieping | Metaal - Staal C | 5.05858 | 0.00063 | 0.0006363 | 0.0006363 | Component Quantities - Rectangular Component Height: 126 mm; Rectangular Component Width: 5 mm
Cement - Dekvloer | verdieping | Cement - Dekvloer | 3451.3 |  | 1.81647 | 1.99791 | Component Quantities - Projected Component Area (Net): 22.7247 m2; Projected Component Area (Gross): 24.9927 m2; Component Thickness: 80 mm
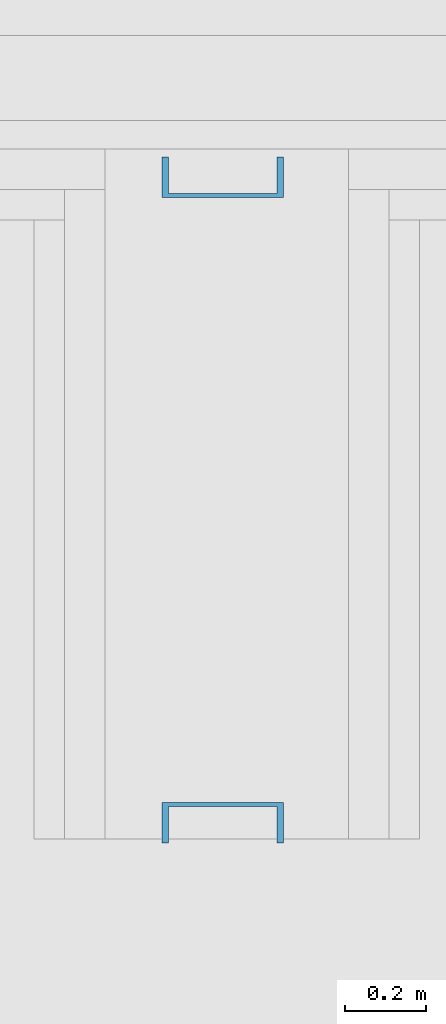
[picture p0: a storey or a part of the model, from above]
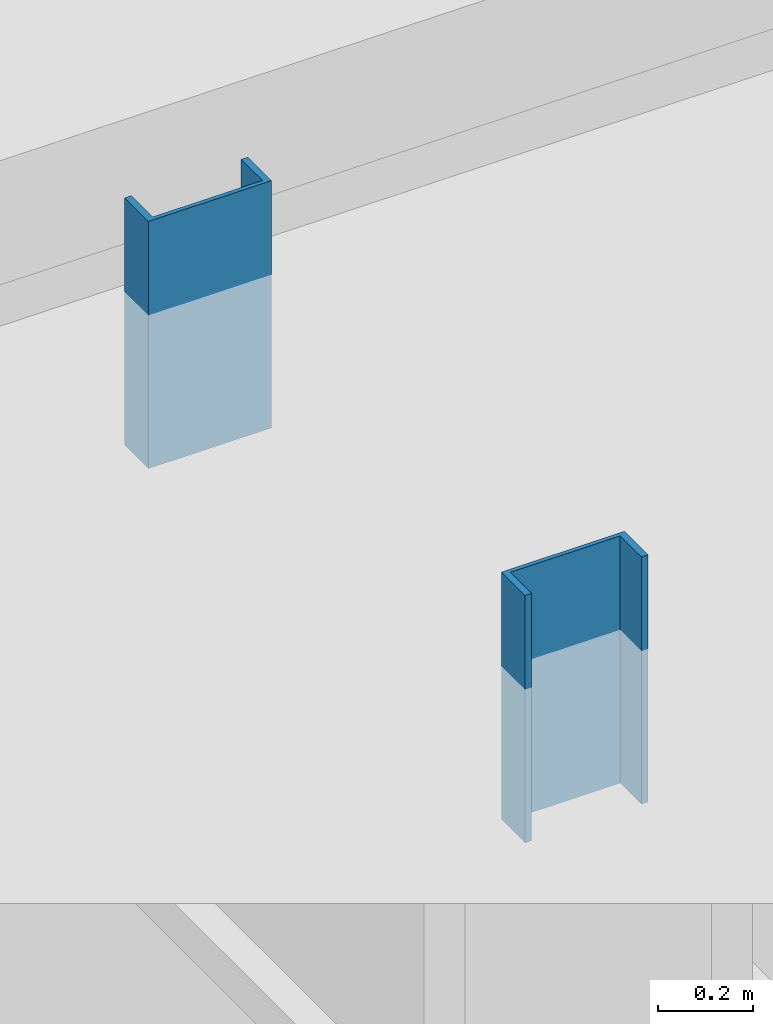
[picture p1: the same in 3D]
Properties of the parts of a building model (IFC2X3), part 4 of 9

# IfcBuildingElementPart (2190)
Name | In | Material | Mass (kg) | Component Cross Section Area (m2) | Component Volume (Net) (m3) | Component Volume (Gross) (m3)
Beton gewapend prefab vloer | verdieping | Beton gewapend prefab vloer | 17624.6 |  | 7.34358 | 8.06934 | Component Quantities - Projected Component Area (Net): 22.9491 m2; Projected Component Area (Gross): 25.2171 m2; Component Thickness: 320 mm
2 x Beton gewapend C vloer | verdieping | Beton gewapend C vloer | 352.293 | 0.0595 | 0.146789 | 0.146789
4 x Metaal - Staal C | verdieping | Metaal - Staal C | 58.8388 | 0.003 | 0.00740111 | 0.00740111 | Component Quantities - Rectangular Component Height: 15 mm; Rectangular Component Width: 200 mm
2 x Metaal - Staal C | verdieping | Metaal - Staal C | 33.342 | 0.0017 | 0.00419396 | 0.00419396 | Component Quantities - Rectangular Component Height: 170 mm; Rectangular Component Width: 10 mm
2 x Metaal - Staal C | verdieping | Metaal - Staal C | 75.3137 | 0.00384 | 0.00947342 | 0.00947342 | Component Quantities - Rectangular Component Height: 12 mm; Rectangular Component Width: 320 mm
Steen - Baksteen | verdieping | Steen - Baksteen | 12660.7 | 0.3661 | 7.91293 | 12.2047 | Component Quantities - Rectangular Component Height: 5230 mm; Rectangular Component Width: 70 mm
Isolatie - Kunststof hard | verdieping | Isolatie - Kunststof hard | 1800.92 | 0.7322 | 18.0092 | 24.3887 | Component Quantities - Rectangular Component Height: 5230 mm; Rectangular Component Width: 140 mm
Steen - Kalkzandsteen C | verdieping | Steen - Kalkzandsteen C | 21753.6 | 0.546 | 11.4492 | 18.202 | Component Quantities - Rectangular Component Height: 3640 mm; Rectangular Component Width: 150 mm
Cement - Dekvloer | verdieping | Cement - Dekvloer | 827.469 |  | 0.43551 | 0.43551 | Component Quantities - Projected Component Area (Net): 5.44387 m2; Projected Component Area (Gross): 5.44387 m2; Component Thickness: 80 mm
Beton gewapend C vloer | verdieping | Beton gewapend C vloer | 7229.91 |  | 3.01246 | 3.01246 | Component Quantities - Projected Component Area (Net): 9.41395 m2; Projected Component Area (Gross): 9.41395 m2; Component Thickness: 320 mm
ALG - LICHTE SCHEIDINGSWAND | verdieping | ALG - LICHTE SCHEIDINGSWAND | 423.322 | 0.14 | 0.529152 | 0.529152 | Component Quantities - Rectangular Component Height: 1400 mm; Rectangular Component Width: 100 mm; Projected Component Area (Net): 5.824 m2; Projected Component Area (Gross): 5.824 m2; Component Thickness: 100 mm
ALG - LICHTE SCHEIDINGSWAND | verdieping | ALG - LICHTE SCHEIDINGSWAND | 359.424 | 0.14 | 0.44928 | 0.44928 | Component Quantities - Rectangular Component Height: 1400 mm; Rectangular Component Width: 100 mm; Projected Component Area (Net): 4.4928 m2; Projected Component Area (Gross): 4.4928 m2; Component Thickness: 100 mm
Metaal - Staal C | verdieping | Metaal - Staal C | 60.9189 | 0.003 | 0.00766275 | 0.00766275 | Component Quantities - Rectangular Component Height: 15 mm; Rectangular Component Width: 200 mm
Metaal - Staal C | verdieping | Metaal - Staal C | 57.4785 | 0.003 | 0.00723 | 0.00723 | Component Quantities - Rectangular Component Height: 15 mm; Rectangular Component Width: 200 mm
Metaal - Staal C | verdieping | Metaal - Staal C | 31.5653 | 0.00153 | 0.00397048 | 0.00397048 | Component Quantities - Rectangular Component Height: 170 mm; Rectangular Component Width: 9 mm
Beton gewapend C vloer | verdieping | Beton gewapend C vloer | 494.091 | 0.0868915 | 0.205871 | 0.205871
2 x Metaal - Staal C | verdieping | Metaal - Staal C | 115.875 | 0.00615 | 0.0145755 | 0.0145755 | Component Quantities - Rectangular Component Height: 20.5 mm; Rectangular Component Width: 300 mm
Metaal - Staal C | verdieping | Metaal - Staal C | 60.453 | 0.0032085 | 0.00760415 | 0.00760415 | Component Quantities - Rectangular Component Height: 279 mm; Rectangular Component Width: 11.5 mm
Metaal - Staal C | verdieping | Metaal - Staal C | 160.153 | 0.0085 | 0.020145 | 0.020145 | Component Quantities - Rectangular Component Height: 20 mm; Rectangular Component Width: 425 mm
Cement - Dekvloer | verdieping | Cement - Dekvloer | 1090.17 |  | 0.573774 | 0.573774 | Component Quantities - Projected Component Area (Net): 7.18468 m2; Projected Component Area (Gross): 7.18468 m2; Component Thickness: 80 mm
Beton gewapend C vloer | verdieping | Beton gewapend C vloer | 9616.53 |  | 4.00689 | 4.00689 | Component Quantities - Projected Component Area (Net): 12.5215 m2; Projected Component Area (Gross): 12.5215 m2; Component Thickness: 320 mm
Cement - Dekvloer | verdieping | Cement - Dekvloer | 74.784 |  | 0.03936 | 0.03936 | Component Quantities - Projected Component Area (Net): 0.492 m2; Projected Component Area (Gross): 0.492 m2; Component Thickness: 80 mm
Beton gewapend C vloer | verdieping | Beton gewapend C vloer | 409.344 |  | 0.17056 | 0.17056 | Component Quantities - Projected Component Area (Net): 0.533 m2; Projected Component Area (Gross): 0.533 m2; Component Thickness: 320 mm
ALG - LICHTE SCHEIDINGSWAND | verdieping | ALG - LICHTE SCHEIDINGSWAND | 519.76 | 0.356 | 0.6497 | 0.6497 | Component Quantities - Rectangular Component Height: 3560 mm; Rectangular Component Width: 100 mm; Projected Component Area (Net): 6.497 m2; Projected Component Area (Gross): 6.497 m2; Component Thickness: 100 mm
ALG - LICHTE SCHEIDINGSWAND | verdieping | ALG - LICHTE SCHEIDINGSWAND | 484.16 | 0.356 | 0.6052 | 0.6052 | Component Quantities - Rectangular Component Height: 3560 mm; Rectangular Component Width: 100 mm; Projected Component Area (Net): 6.052 m2; Projected Component Area (Gross): 6.052 m2; Component Thickness: 100 mm
44 x Metaal - Staal C | verdieping | Metaal - Staal C | 10.7325 | 0.003 | 0.00135 | 0.00135 | Component Quantities - Rectangular Component Height: 15 mm; Rectangular Component Width: 200 mm
8 x Metaal - Staal C | verdieping | Metaal - Staal C | 5.47357 | 0.00153 | 0.0006885 | 0.0006885 | Component Quantities - Rectangular Component Height: 170 mm; Rectangular Component Width: 9 mm
14 x Metaal - Staal C | verdieping | Metaal - Staal C | 5.47358 | 0.00153 | 0.0006885 | 0.0006885 | Component Quantities - Rectangular Component Height: 170 mm; Rectangular Component Width: 9 mm
Membraan - waterdicht | verdieping | Membraan - waterdicht | 5.41538 | 0.00130061 | 0.0051575 | 0.0051595 | Component Quantities - Rectangular Component Height: 433.535 mm; Rectangular Component Width: 3 mm
Hout - OSB | verdieping | Hout - OSB | 10.0717 | 0.00424 | 0.0167862 | 0.0168201 | Component Quantities - Rectangular Component Height: 530 mm; Rectangular Component Width: 8 mm
Hout - Multiplex | verdieping | Hout - Multiplex | 84.8871 | 0.0092 | 0.121267 | 0.121267 | Component Quantities - Rectangular Component Height: 20 mm; Rectangular Component Width: 460 mm
Metaal - Aluminium beige | verdieping | Metaal - Aluminium beige | 23.7209 | 0.000635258 | 0.00847175 | 0.00847175
Metaal - Aluminium beige | verdieping | Metaal - Aluminium beige | 23.1779 | 0.000635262 | 0.00827781 | 0.00827781
Hout - Multiplex | verdieping | Hout - Multiplex | 92.736 | 0.0092 | 0.13248 | 0.13248 | Component Quantities - Rectangular Component Height: 20 mm; Rectangular Component Width: 460 mm
Metaal - Aluminium beige | verdieping | Metaal - Aluminium beige | 26.1568 | 0.000635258 | 0.00934172 | 0.00934172
Metaal - Aluminium beige | verdieping | Metaal - Aluminium beige | 25.0706 | 0.000635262 | 0.00895378 | 0.00895378
Hout - Multiplex | verdieping | Hout - Multiplex | 86.8821 | 0.0092 | 0.124117 | 0.124117 | Component Quantities - Rectangular Component Height: 20 mm; Rectangular Component Width: 460 mm
Metaal - Aluminium beige | verdieping | Metaal - Aluminium beige | 24.6381 | 0.000635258 | 0.00879934 | 0.00879934
Metaal - Aluminium beige | verdieping | Metaal - Aluminium beige | 23.3555 | 0.000635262 | 0.00834126 | 0.00834126
Hout - OSB | verdieping | Hout - OSB | 3.73968 | 0.00424 | 0.0062328 | 0.0062328 | Component Quantities - Rectangular Component Height: 530 mm; Rectangular Component Width: 8 mm
Membraan - waterdicht | verdieping | Membraan - waterdicht | 2.04436 | 0.00130061 | 0.00194701 | 0.00194701 | Component Quantities - Rectangular Component Height: 433.535 mm; Rectangular Component Width: 3 mm
Membraan - waterdicht | techniek | Membraan - waterdicht | 31.3376 | 0.00156185 | 0.0298453 | 0.0298453
Membraan - waterdicht | techniek | Membraan - waterdicht | 1.60704 | 0.000080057 | 0.00153051 | 0.00153051
Hout - Multiplex | techniek | Hout - Multiplex | 106.242 | 0.00792413 | 0.151774 | 0.151774
Membraan - waterdicht | techniek | Membraan - waterdicht | 24.7874 | 0.00122583 | 0.0236071 | 0.0236071
Steen - Cellenbeton | techniek | Steen - Cellenbeton | 1043.52 | 0.078 | 1.49074 | 1.49074 | Component Quantities - Rectangular Component Height: 520 mm; Rectangular Component Width: 150 mm
Isolatie - Kunststof hard | techniek | Isolatie - Kunststof hard | 140.227 | 0.0728 | 1.40227 | 1.40227 | Component Quantities - Rectangular Component Height: 520 mm; Rectangular Component Width: 140 mm
Steen - Baksteen | techniek | Steen - Baksteen | 1134.05 | 0.0364001 | 0.708782 | 0.708782 | Component Quantities - Rectangular Component Height: 520 mm; Rectangular Component Width: 70.0001 mm
Metaal - Aluminium beige | techniek | Metaal - Aluminium beige | 31.3383 | 0.000573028 | 0.0111923 | 0.0111923
Metaal - Aluminium beige | techniek | Metaal - Aluminium beige | 15.0835 | 0.000573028 | 0.00538697 | 0.00538697
Steen - Baksteen | techniek | Steen - Baksteen | 543.103 | 0.0364001 | 0.339439 | 0.339439 | Component Quantities - Rectangular Component Height: 520 mm; Rectangular Component Width: 70.0001 mm
Isolatie - Kunststof hard | techniek | Isolatie - Kunststof hard | 66.3936 | 0.0728 | 0.663936 | 0.663936 | Component Quantities - Rectangular Component Height: 520 mm; Rectangular Component Width: 140 mm
Steen - Cellenbeton | techniek | Steen - Cellenbeton | 489.762 | 0.078 | 0.69966 | 0.69966 | Component Quantities - Rectangular Component Height: 520 mm; Rectangular Component Width: 150 mm
Membraan - waterdicht | techniek | Membraan - waterdicht | 11.7335 | 0.00122583 | 0.0111748 | 0.0111748
Hout - Multiplex | techniek | Hout - Multiplex | 49.9286 | 0.00792413 | 0.0713266 | 0.0713266
Membraan - waterdicht | techniek | Membraan - waterdicht | 0.7545 | 0.000080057 | 0.000718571 | 0.000718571
Membraan - waterdicht | techniek | Membraan - waterdicht | 14.7052 | 0.00156185 | 0.0140049 | 0.0140049
Membraan - waterdicht | techniek | Membraan - waterdicht | 56.8664 | 0.00156185 | 0.0541585 | 0.0541585
Membraan - waterdicht | techniek | Membraan - waterdicht | 2.91583 | 0.000080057 | 0.00277698 | 0.00277698
Hout - Multiplex | techniek | Hout - Multiplex | 197.024 | 0.00792413 | 0.281462 | 0.281462
Membraan - waterdicht | techniek | Membraan - waterdicht | 45.4961 | 0.00122583 | 0.0433297 | 0.0433297
Steen - Cellenbeton | techniek | Steen - Cellenbeton | 1910.29 | 0.078 | 2.72899 | 2.72899 | Component Quantities - Rectangular Component Height: 520 mm; Rectangular Component Width: 150 mm
Isolatie - Kunststof hard | techniek | Isolatie - Kunststof hard | 256.744 | 0.0728 | 2.56744 | 2.56744 | Component Quantities - Rectangular Component Height: 520 mm; Rectangular Component Width: 140 mm
Steen - Baksteen | techniek | Steen - Baksteen | 2070.26 | 0.0364001 | 1.29391 | 1.29391 | Component Quantities - Rectangular Component Height: 520 mm; Rectangular Component Width: 70.0001 mm
Metaal - Aluminium beige | techniek | Metaal - Aluminium beige | 57.0681 | 0.000573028 | 0.0203815 | 0.0203815
Membraan - waterdicht | techniek | Membraan - waterdicht | 51.8171 | 0.00156185 | 0.0493497 | 0.0493497
Membraan - waterdicht | techniek | Membraan - waterdicht | 2.65759 | 0.000080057 | 0.00253104 | 0.00253104
Hout - Multiplex | techniek | Hout - Multiplex | 177.821 | 0.00792413 | 0.25403 | 0.25403
Membraan - waterdicht | techniek | Membraan - waterdicht | 41.2433 | 0.00122583 | 0.0392793 | 0.0392793
Steen - Cellenbeton | techniek | Steen - Cellenbeton | 1733.55 | 0.078 | 2.4765 | 2.4765 | Component Quantities - Rectangular Component Height: 520 mm; Rectangular Component Width: 150 mm
Isolatie - Kunststof hard | techniek | Isolatie - Kunststof hard | 233.251 | 0.0728 | 2.33251 | 2.33251 | Component Quantities - Rectangular Component Height: 520 mm; Rectangular Component Width: 140 mm
Steen - Baksteen | techniek | Steen - Baksteen | 1886.4 | 0.0364001 | 1.179 | 1.179 | Component Quantities - Rectangular Component Height: 520 mm; Rectangular Component Width: 70.0001 mm
Metaal - Aluminium beige | techniek | Metaal - Aluminium beige | 52.0903 | 0.000573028 | 0.0186037 | 0.0186037
2 x Hout - Vloer | techniek | Hout - Vloer | 15.3449 | 0.003382 | 0.0278998 | 0.0278998 | Component Quantities - Rectangular Component Height: 38 mm; Rectangular Component Width: 89 mm
Hout - OSB | techniek | Hout - OSB | 26.3286 | 0.005352 | 0.043881 | 0.043881 | Component Quantities - Rectangular Component Height: 446 mm; Rectangular Component Width: 12 mm
Hout - OSB | techniek | Hout - OSB | 47.3469 | 0.00948 | 0.0789115 | 0.0789115 | Component Quantities - Rectangular Component Height: 474 mm; Rectangular Component Width: 20 mm
Membraan - waterdicht | techniek | Membraan - waterdicht | 5.16063 | 0.000599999 | 0.00491489 | 0.00491489 | Component Quantities - Rectangular Component Height: 200 mm; Rectangular Component Width: 2.99999 mm
Metaal - Staal C | techniek | Metaal - Staal C | 153.244 | 0.002319 | 0.0192759 | 0.0192759
Metaal - Staal C | techniek | Metaal - Staal C | 7.85905 | 0.00048 | 0.00098856 | 0.00395424
2 x Hout - Vloer | techniek | Hout - Vloer | 26.9138 | 0.003382 | 0.0489342 | 0.0489342 | Component Quantities - Rectangular Component Height: 38 mm; Rectangular Component Width: 89 mm
Hout - OSB | techniek | Hout - OSB | 46.1385 | 0.005352 | 0.0768975 | 0.0768975 | Component Quantities - Rectangular Component Height: 446 mm; Rectangular Component Width: 12 mm
Hout - OSB | techniek | Hout - OSB | 83.1472 | 0.00948 | 0.138579 | 0.138579 | Component Quantities - Rectangular Component Height: 474 mm; Rectangular Component Width: 20 mm
Membraan - waterdicht | techniek | Membraan - waterdicht | 9.04237 | 0.000599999 | 0.00861178 | 0.00861178 | Component Quantities - Rectangular Component Height: 200 mm; Rectangular Component Width: 2.99999 mm
Metaal - Staal C | techniek | Metaal - Staal C | 269.062 | 0.002319 | 0.0338443 | 0.0338443
Metaal - Staal C | techniek | Metaal - Staal C | 13.7815 | 0.00048 | 0.00173352 | 0.00693408
2 x Hout - Vloer | techniek | Hout - Vloer | 58.3495 | 0.003382 | 0.10609 | 0.10609 | Component Quantities - Rectangular Component Height: 38 mm; Rectangular Component Width: 89 mm
Hout - OSB | techniek | Hout - OSB | 100.408 | 0.005352 | 0.167346 | 0.167346 | Component Quantities - Rectangular Component Height: 446 mm; Rectangular Component Width: 12 mm
Hout - OSB | techniek | Hout - OSB | 179.274 | 0.00948 | 0.298791 | 0.298791 | Component Quantities - Rectangular Component Height: 474 mm; Rectangular Component Width: 20 mm
Membraan - waterdicht | techniek | Membraan - waterdicht | 19.6894 | 0.000599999 | 0.0187518 | 0.0187518 | Component Quantities - Rectangular Component Height: 200 mm; Rectangular Component Width: 2.99999 mm
Metaal - Staal C | techniek | Metaal - Staal C | 580.631 | 0.002319 | 0.0730354 | 0.0730354
Metaal - Staal C | techniek | Metaal - Staal C | 29.9041 | 0.00048 | 0.00376152 | 0.0150461
2 x Hout - Vloer | techniek | Hout - Vloer | 13.3546 | 0.003382 | 0.0242811 | 0.0242811 | Component Quantities - Rectangular Component Height: 38 mm; Rectangular Component Width: 89 mm
Hout - OSB | techniek | Hout - OSB | 22.8926 | 0.005352 | 0.0381544 | 0.0381544 | Component Quantities - Rectangular Component Height: 446 mm; Rectangular Component Width: 12 mm
Hout - OSB | techniek | Hout - OSB | 41.2608 | 0.00948 | 0.0687679 | 0.0687679 | Component Quantities - Rectangular Component Height: 474 mm; Rectangular Component Width: 20 mm
Membraan - waterdicht | techniek | Membraan - waterdicht | 4.48661 | 0.000599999 | 0.00427296 | 0.00427296 | Component Quantities - Rectangular Component Height: 200 mm; Rectangular Component Width: 2.99999 mm
Metaal - Staal C | techniek | Metaal - Staal C | 134.771 | 0.002319 | 0.0169523 | 0.0169523
Metaal - Staal C | techniek | Metaal - Staal C | 6.90314 | 0.00048 | 0.00086832 | 0.00347328
Steen - Baksteen | techniek | Steen - Baksteen | 2934.48 | 0.21 | 1.83405 | 1.83405
Isolatie - Kunststof hard | techniek | Isolatie - Kunststof hard | 66.3598 | 0.0726001 | 0.663598 | 0.663598 | Component Quantities - Rectangular Component Height: 330 mm; Rectangular Component Width: 220 mm
Steen - Baksteen | techniek | Steen - Baksteen | 3084.48 | 0.21 | 1.9278 | 1.9278 | Component Quantities - Rectangular Component Height: 3000 mm; Rectangular Component Width: 70.0001 mm
30 x Metaal - Aluminium | techniek | Metaal - Aluminium | 12.0099 | 0.000209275 | 0.00428924 | 0.00428924
22 x Metaal - Aluminium | techniek | Metaal - Aluminium | 12.0099 | 0.000209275 | 0.00428923 | 0.00428923
12 x Metaal - Aluminium | techniek | Metaal - Aluminium | 12.0098 | 0.000209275 | 0.00428923 | 0.00428923
4 x Metaal - Staal C | techniek | Metaal - Staal C | 243.3 | 0.0015 | 0.0306038 | 0.0306038
2 x Metaal - Staal C | techniek | Metaal - Staal C | 243.3 | 0.0015 | 0.0306037 | 0.0306037
7 x Metaal - Aluminium | techniek | Metaal - Aluminium | 5.318 | 0.000209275 | 0.00189929 | 0.00189929
2 x Metaal - Aluminium | techniek | Metaal - Aluminium | 5.318 | 0.000209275 | 0.00189928 | 0.00189928
8 x Metaal - Aluminium | techniek | Metaal - Aluminium | 5.31799 | 0.000209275 | 0.00189928 | 0.00189928
3 x Metaal - Aluminium | techniek | Metaal - Aluminium | 5.31802 | 0.000209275 | 0.00189929 | 0.00189929
11 x Metaal - Aluminium | techniek | Metaal - Aluminium | 5.31801 | 0.000209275 | 0.00189929 | 0.00189929
Metaal - Aluminium | techniek | Metaal - Aluminium | 5.31798 | 0.000209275 | 0.00189928 | 0.00189928
Metaal - Staal C | techniek | Metaal - Staal C | 104.995 | 0.0015 | 0.0132069 | 0.0132069
2 x Metaal - Staal C | techniek | Metaal - Staal C | 104.996 | 0.0015 | 0.0132071 | 0.0132071
2 x Membraan - waterdicht | techniek | Membraan - waterdicht | 0.157504 | 0.00012 | 0.000150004 | 0.000150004 | Component Quantities - Rectangular Component Height: 6 mm; Rectangular Component Width: 20 mm
2 x Membraan - waterdicht | techniek | Membraan - waterdicht | 0.131253 | 0.0001 | 0.000125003 | 0.000125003 | Component Quantities - Rectangular Component Height: 5 mm; Rectangular Component Width: 20 mm
Metaal - Aluminium | techniek | Metaal - Aluminium | 33.6008 | 0.0096 | 0.0120003 | 0.0078198 | Component Quantities - Rectangular Component Height: 160 mm; Rectangular Component Width: 60 mm
Metaal - Aluminium | techniek | Metaal - Aluminium | 3.42616 | 0.00092 | 0.00122363 | 0.00122363 | Component Quantities - Rectangular Component Height: 46 mm; Rectangular Component Width: 20 mm
Metaal - Aluminium | techniek | Metaal - Aluminium | 2.94007 | 0.00084 | 0.00105002 | 0.00105002 | Component Quantities - Rectangular Component Height: 14 mm; Rectangular Component Width: 60 mm
4 x Membraan - waterdicht | techniek | Membraan - waterdicht | 1.06092 | 0.00012 | 0.0010104 | 0.0010104 | Component Quantities - Rectangular Component Height: 6 mm; Rectangular Component Width: 20 mm
4 x Membraan - waterdicht | techniek | Membraan - waterdicht | 0.8841 | 0.0001 | 0.000842 | 0.000842 | Component Quantities - Rectangular Component Height: 5 mm; Rectangular Component Width: 20 mm
Metaal - Aluminium | techniek | Metaal - Aluminium | 213.756 | 0.0096 | 0.0763413 | 0.0237781 | Component Quantities - Rectangular Component Height: 160 mm; Rectangular Component Width: 60 mm
2 x Metaal - Aluminium | techniek | Metaal - Aluminium | 21.9475 | 0.00092 | 0.0078384 | 0.0078384 | Component Quantities - Rectangular Component Height: 46 mm; Rectangular Component Width: 20 mm
2 x Metaal - Aluminium | techniek | Metaal - Aluminium | 19.8509 | 0.00084 | 0.0070896 | 0.0070896 | Component Quantities - Rectangular Component Height: 14 mm; Rectangular Component Width: 60 mm
Metaal - Aluminium | techniek | Metaal - Aluminium | 226.867 | 0.0096 | 0.081024 | 0.081024 | Component Quantities - Rectangular Component Height: 160 mm; Rectangular Component Width: 60 mm
4 x Membraan - waterdicht | techniek | Membraan - waterdicht | 0.172624 | 0.00012 | 0.000164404 | 0.000164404 | Component Quantities - Rectangular Component Height: 6 mm; Rectangular Component Width: 20 mm
4 x Membraan - waterdicht | techniek | Membraan - waterdicht | 0.143853 | 0.0001 | 0.000137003 | 0.000137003 | Component Quantities - Rectangular Component Height: 5 mm; Rectangular Component Width: 20 mm
4 x Metaal - Aluminium | techniek | Metaal - Aluminium | 36.7332 | 0.0096 | 0.013119 | 0.00856446 | Component Quantities - Rectangular Component Height: 160 mm; Rectangular Component Width: 60 mm
4 x Metaal - Aluminium | techniek | Metaal - Aluminium | 3.5292 | 0.00092 | 0.00126043 | 0.00126043 | Component Quantities - Rectangular Component Height: 46 mm; Rectangular Component Width: 20 mm
4 x Metaal - Aluminium | techniek | Metaal - Aluminium | 3.22231 | 0.00084 | 0.00115082 | 0.00115082 | Component Quantities - Rectangular Component Height: 14 mm; Rectangular Component Width: 60 mm
4 x Membraan - waterdicht | techniek | Membraan - waterdicht | 0.167584 | 0.00012 | 0.000159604 | 0.000159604 | Component Quantities - Rectangular Component Height: 6 mm; Rectangular Component Width: 20 mm
4 x Membraan - waterdicht | techniek | Membraan - waterdicht | 0.139653 | 0.0001 | 0.000133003 | 0.000133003 | Component Quantities - Rectangular Component Height: 5 mm; Rectangular Component Width: 20 mm
2 x Membraan - waterdicht | techniek | Membraan - waterdicht | 0.379444 | 0.00012 | 0.000361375 | 0.000361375 | Component Quantities - Rectangular Component Height: 6 mm; Rectangular Component Width: 20 mm
2 x Membraan - waterdicht | techniek | Membraan - waterdicht | 0.316203 | 0.0001 | 0.000301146 | 0.000301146 | Component Quantities - Rectangular Component Height: 5 mm; Rectangular Component Width: 20 mm
Metaal - Aluminium | techniek | Metaal - Aluminium | 80.948 | 0.0096 | 0.02891 | 0.0247291 | Component Quantities - Rectangular Component Height: 160 mm; Rectangular Component Width: 60 mm
Metaal - Aluminium | techniek | Metaal - Aluminium | 7.9636 | 0.00092 | 0.00284414 | 0.00284414 | Component Quantities - Rectangular Component Height: 46 mm; Rectangular Component Width: 20 mm
Metaal - Aluminium | techniek | Metaal - Aluminium | 7.08295 | 0.00084 | 0.00252963 | 0.00252963 | Component Quantities - Rectangular Component Height: 14 mm; Rectangular Component Width: 60 mm
3 x Membraan - waterdicht | techniek | Membraan - waterdicht | 1.04548 | 0.00012 | 0.0009957 | 0.0009957 | Component Quantities - Rectangular Component Height: 6 mm; Rectangular Component Width: 20 mm
Membraan - waterdicht | techniek | Membraan - waterdicht | 1.04549 | 0.00012 | 0.0009957 | 0.0009957 | Component Quantities - Rectangular Component Height: 6 mm; Rectangular Component Width: 20 mm
4 x Membraan - waterdicht | techniek | Membraan - waterdicht | 0.871238 | 0.0001 | 0.00082975 | 0.00082975 | Component Quantities - Rectangular Component Height: 5 mm; Rectangular Component Width: 20 mm
Metaal - Aluminium | techniek | Metaal - Aluminium | 210.653 | 0.0096 | 0.0752333 | 0.023433 | Component Quantities - Rectangular Component Height: 160 mm; Rectangular Component Width: 60 mm
2 x Metaal - Aluminium | techniek | Metaal - Aluminium | 22.0441 | 0.00092 | 0.0078729 | 0.0078729 | Component Quantities - Rectangular Component Height: 46 mm; Rectangular Component Width: 20 mm
2 x Metaal - Aluminium | techniek | Metaal - Aluminium | 19.5628 | 0.00084 | 0.0069867 | 0.0069867 | Component Quantities - Rectangular Component Height: 14 mm; Rectangular Component Width: 60 mm
Metaal - Aluminium | techniek | Metaal - Aluminium | 223.574 | 0.0096 | 0.079848 | 0.079848 | Component Quantities - Rectangular Component Height: 160 mm; Rectangular Component Width: 60 mm
4 x Membraan - waterdicht | techniek | Membraan - waterdicht | 0.394564 | 0.00012 | 0.000375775 | 0.000375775 | Component Quantities - Rectangular Component Height: 6 mm; Rectangular Component Width: 20 mm
4 x Membraan - waterdicht | techniek | Membraan - waterdicht | 0.328803 | 0.0001 | 0.000313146 | 0.000313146 | Component Quantities - Rectangular Component Height: 5 mm; Rectangular Component Width: 20 mm
8 x Metaal - Aluminium | techniek | Metaal - Aluminium | 84.0804 | 0.0096 | 0.0300287 | 0.0254742 | Component Quantities - Rectangular Component Height: 160 mm; Rectangular Component Width: 60 mm
8 x Metaal - Aluminium | techniek | Metaal - Aluminium | 8.06664 | 0.00092 | 0.00288094 | 0.00288094 | Component Quantities - Rectangular Component Height: 46 mm; Rectangular Component Width: 20 mm
8 x Metaal - Aluminium | techniek | Metaal - Aluminium | 7.36519 | 0.00084 | 0.00263043 | 0.00263043 | Component Quantities - Rectangular Component Height: 14 mm; Rectangular Component Width: 60 mm
12 x Membraan - waterdicht | techniek | Membraan - waterdicht | 0.389524 | 0.00012 | 0.000370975 | 0.000370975 | Component Quantities - Rectangular Component Height: 6 mm; Rectangular Component Width: 20 mm
12 x Membraan - waterdicht | techniek | Membraan - waterdicht | 0.324603 | 0.0001 | 0.000309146 | 0.000309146 | Component Quantities - Rectangular Component Height: 5 mm; Rectangular Component Width: 20 mm
Isolatie - Kunststof hard afschot | techniek | Isolatie - Kunststof hard afschot | 437.917 |  | 4.37917 | 11.2837 | Component Quantities - Projected Component Area (Net): 75.2248 m2; Projected Component Area (Gross): 75.2248 m2; Component Thickness: 150 mm
Hout - OSB | techniek | Hout - OSB | 812.428 |  | 1.35405 | 1.35405 | Component Quantities - Projected Component Area (Net): 75.2248 m2; Projected Component Area (Gross): 75.2248 m2; Component Thickness: 18 mm
Isolatie - Kunststof hard | techniek | Isolatie - Kunststof hard | 1053.15 |  | 10.5315 | 10.5315 | Component Quantities - Projected Component Area (Net): 75.2248 m2; Projected Component Area (Gross): 75.2248 m2; Component Thickness: 140 mm

# IfcBuildingElementProxy: 31 vliesgevel drsn 212 x 8350, 42_53 wandtegels keramisch
In: begane grond
Classification: Keramische bekleding & afwerking (ARCHICAD Classification); 42.12 bekledingen (NL/SfB (4 cijfers))

# IfcBuildingElementProxy: 48 Desso airmaster 1958 2 (4)
In: begane grond
Material: 48 Desso airmaster 1958
Component Quantities - 48 Desso airmaster 1958, Component Thickness: 2 mm
Name | 48 Desso airmaster 1958, Mass (kg) | 48 Desso airmaster 1958, Projected Component Area (Net) (m2) = 48 Desso airmaster 1958, Projected Component Area (Gross) (m2) | 48 Desso airmaster 1958, Component Volume (Net) (m3) = 48 Desso airmaster 1958, Component Volume (Gross) (m3)
_43 tapijt | 56.2005 | 12.2175 | 0.024435
_43 tapijt | 74.3375 | 16.1603 | 0.0323207
_43 tapijt | 76.3358 | 16.5947 | 0.0331895
_43 tapijt | 76.089 | 16.5411 | 0.0330822

# IfcBuildingElementProxy: 48 Desso airmaster 9504 2 (3)
Material: 48 Desso airmaster 9504
Component Quantities - 48 Desso airmaster 9504, Component Thickness: 2 mm
Name | In | 48 Desso airmaster 9504, Mass (kg) | 48 Desso airmaster 9504, Projected Component Area (Net) (m2) = 48 Desso airmaster 9504, Projected Component Area (Gross) (m2) | 48 Desso airmaster 9504, Component Volume (Net) (m3) = 48 Desso airmaster 9504, Component Volume (Gross) (m3)
_43 tapijt | begane grond | 38.71 | 8.41522 | 0.0168305
_43 tapijt | begane grond | 38.6953 | 8.41203 | 0.0168241
_43 tapijt | verdieping | 342.552 | 74.4677 | 0.148935

# IfcBuildingElementProxy: 48 Emco Maximus 15 (4)
Material: 48 Emco Maximus
Component Quantities - 48 Emco Maximus, Component Thickness: 15 mm
Name | In | 48 Emco Maximus, Mass (kg) | 48 Emco Maximus, Projected Component Area (Net) (m2) = 48 Emco Maximus, Projected Component Area (Gross) (m2) | 48 Emco Maximus, Component Volume (Net) (m3) = 48 Emco Maximus, Component Volume (Gross) (m3)
_schoonloop zone 3 | begane grond | 198.72 | 5.76 | 0.0864
_schoonloop zone 3 | begane grond | 171.123 | 4.9601 | 0.0744015
_43 schoonloop zone 3 | begane grond | 277.121 | 8.0325 | 0.120487
_schoonloop zone 3 | verdieping | 146.142 | 4.236 | 0.06354

# IfcBuildingElementProxy: 48 Emco Scratch2 15 (3)
In: begane grond
Material: 48 Emco Scratch2
Component Quantities - 48 Emco Scratch2, Component Thickness: 15 mm
Name | 48 Emco Scratch2, Mass (kg) | 48 Emco Scratch2, Projected Component Area (Net) (m2) = 48 Emco Scratch2, Projected Component Area (Gross) (m2) | 48 Emco Scratch2, Component Volume (Net) (m3) = 48 Emco Scratch2, Component Volume (Gross) (m3)
_43 schoonloop zone 2 | 199.548 | 5.784 | 0.08676
_43 schoonloop zone 2 | 297.369 | 8.61938 | 0.129291
_43 schoonloop zone 2 | 314.179 | 9.10665 | 0.1366

# IfcBuildingElementProxy: 48 Emco Scratch2 30 (84)
In: begane grond
Material: 48 Emco Scratch2
Component Quantities - 48 Emco Scratch2, Component Thickness: 30 mm
Name | 48 Emco Scratch2, Mass (kg) | 48 Emco Scratch2, Projected Component Area (Net) (m2) = 48 Emco Scratch2, Projected Component Area (Gross) (m2) | 48 Emco Scratch2, Component Volume (Net) (m3) = 48 Emco Scratch2, Component Volume (Gross) (m3)
6 x _43 schoonloop zone 1 | 24.978 | 0.362 | 0.01086
9 x _43 schoonloop zone 1 | 15.7182 | 0.2278 | 0.006834
_43 schoonloop zone 1 | 12.2602 | 0.177684 | 0.00533052
8 x _43 schoonloop zone 1 | 43.47 | 0.63 | 0.0189
60 x _43 schoonloop zone 1 | 7.935 | 0.115 | 0.00345

# IfcBuildingElementProxy: ALG - BUITENAFWERKING 60, 42_53 wandtegels keramisch
In: begane grond
Classification: Keramische bekleding & afwerking (ARCHICAD Classification); 42.12 bekledingen (NL/SfB (4 cijfers)); Material: ALG - BUITENAFWERKING
Component Quantities - ALG - BUITENAFWERKING, Mass: 245.573 kg; ALG - BUITENAFWERKING, Projected Component Area (Net): 2.1788 m2; ALG - BUITENAFWERKING, Projected Component Area (Gross): 7.6908 m2; ALG - BUITENAFWERKING, Component Thickness: 60 mm; ALG - BUITENAFWERKING, Rectangular Component Height: 2900 mm; ALG - BUITENAFWERKING, Rectangular Component Width: 60 mm; ALG - BUITENAFWERKING, Component Cross Section Area: 0.174 m2; ALG - BUITENAFWERKING, Component Volume (Net): 0.129249 m3; ALG - BUITENAFWERKING, Component Volume (Gross): 0.459969 m3

# IfcBuildingElementProxy: ALG - BUITENkozijn 72, 42_53 wandtegels keramisch
In: begane grond
Classification: Keramische bekleding & afwerking (ARCHICAD Classification); 42.12 bekledingen (NL/SfB (4 cijfers)); Material: ALG - BUITENkozijn
Component Quantities - ALG - BUITENkozijn, Mass: 36.4025 kg; ALG - BUITENkozijn, Projected Component Area (Net): 0.2661 m2; ALG - BUITENkozijn, Projected Component Area (Gross): 16.38 m2; ALG - BUITENkozijn, Component Thickness: 72 mm; ALG - BUITENkozijn, Rectangular Component Height: 2600 mm; ALG - BUITENkozijn, Rectangular Component Width: 72 mm; ALG - BUITENkozijn, Component Cross Section Area: 0.1872 m2; ALG - BUITENkozijn, Component Volume (Net): 0.0191592 m3; ALG - BUITENkozijn, Component Volume (Gross): 1.17936 m3

# IfcBuildingElementProxy: Brandslang haspelkast 25 (6)
Classification: 65.1 brandmeldings- en ontruimingsinstallatie (NL/SfB (4 cijfers))
Component Quantities - Component, Component Volume (Net): 0.0304069 m3; Component, Component Volume (Gross): 0.0304069 m3
Name | In
3 x 65_Object-x | begane grond
3 x 65_Object-x | verdieping

# IfcBuildingElementProxy: Digitaal bord 25 (21)
Classification: 82.22 instrumenten/apparatuur (NL/SfB (4 cijfers)); Onderwijsruimte (ARCHICAD Classification)
CPset_Phasing - Renovation Phase: Bestaand
Name | In | Component, Component Volume (Net) (m3) = Component, Component Volume (Gross) (m3)
10 x 82_DiGi-bord | begane grond | 0.0672931
2 x 82_DiGi-bord | begane grond | 0.0471176
9 x 82_DiGi-bord | verdieping | 0.0672931

# IfcBuildingElementProxy: Kast modulair 25 (20)
Classification: 72.0 algemeen (NL/SfB (4 cijfers)); Verkeersruimte (ARCHICAD Classification)
CPset_Phasing - Renovation Phase: Bestaand
Name | In | Component, Component Volume (Net) (m3) = Component, Component Volume (Gross) (m3)
5 x 72_72 garderobe | begane grond | 0.283007
2 x 72_72 garderobe | begane grond | 0.173193
2 x 72_72 garderobe | begane grond | 0.2281
5 x 72_72 garderobe | verdieping | 0.337914
2 x 72_72 garderobe | verdieping | 0.14574
2 x 72_72 garderobe | verdieping | 0.255554
2 x 72_72 garderobe | verdieping | 0.2281

# IfcBuildingElementProxy: Onderkast recht 25 (31)
Name | In | Component, Component Volume (Net) (m3) | Component, Component Volume (Gross) (m3)
3 x _73 pantryblok | begane grond | 0.0774978 | 0.0780882
5 x _73 pantryblok | begane grond | 0.131434 | 0.132024
2 x _73 pantryblok | begane grond | 0.07477 | 0.0753604
10 x _73 pantryblok | begane grond | 0.0775108 | 0.0781012
_73 pantryblok | begane grond | 0.074757 | 0.0753474
_73 pantryblok | begane grond | 0.13006 | 0.13064
2 x _73 pantryblok | begane grond | 0.0755098 | 0.0781012
4 x _73 pantryblok | verdieping | 0.0746178 | 0.0752082
_73 pantryblok | verdieping | 0.0721403 | 0.0727061
2 x _73 pantryblok | verdieping | 0.0726169 | 0.0752082

# IfcBuildingElementProxy: Screen 25 KM (80)
Name | In | Component, Component Volume (Net) (m3) = Component, Component Volume (Gross) (m3)
22 x _78 garderobe | begane grond | 0.001131
_78 garderobe | begane grond | 0.001563
11 x _78 garderobe | begane grond | 0.00239568
27 x _78 garderobe | verdieping | 0.001083
16 x _78 garderobe | verdieping | 0.001719
3 x _78 garderobe | verdieping | 0.00262632

# IfcBuildingElementProxy: Viltonwand 2600+ 33 x 2600 (15)
In: begane grond
Classification: Keramische bekleding & afwerking (ARCHICAD Classification); 42.12 bekledingen (NL/SfB (4 cijfers))
Name
42_46 wandtegels keramisch
42_47 wandtegels keramisch
42_48 wandtegels keramisch
42_49 wandtegels keramisch
42_50 wandtegels keramisch
42_51 wandtegels keramisch
42_52 wandtegels keramisch
42_53 wandtegels keramisch
42_54 wandtegels keramisch
42_55 wandtegels keramisch
42_56 wandtegels keramisch
42_57 wandtegels keramisch
42_58 wandtegels keramisch
42_59 wandtegels keramisch
42_60 wandtegels keramisch

# IfcBuildingElementProxy: wandtegels 150x300 1800+ 10 x 1800 (7)
In: begane grond
Classification: Keramische bekleding & afwerking (ARCHICAD Classification); 42.12 bekledingen (NL/SfB (4 cijfers))
Name
42_61 wandtegels keramisch
42_60 wandtegels keramisch
42_59 wandtegels keramisch
42_58 wandtegels keramisch
42_57 wandtegels keramisch
42_56 wandtegels keramisch
42_62 wandtegels keramisch

# IfcBuildingElementProxy: wandtegels 150x300 2600+ 10 x 2600 (69)
Classification: Keramische bekleding & afwerking (ARCHICAD Classification); 42.12 bekledingen (NL/SfB (4 cijfers))
Name | In
4 x 42_50 wandtegels keramisch | begane grond
5 x 42_51 wandtegels keramisch | begane grond
5 x 42_52 wandtegels keramisch | begane grond
4 x 42_44 wandtegels keramisch | begane grond
2 x 42_45 wandtegels keramisch | begane grond
2 x 42_46 wandtegels keramisch | begane grond
2 x 42_47 wandtegels keramisch | begane grond
3 x 42_49 wandtegels keramisch | begane grond
42_61 wandtegels keramisch | begane grond
42_60 wandtegels keramisch | begane grond
42_59 wandtegels keramisch | begane grond
42_58 wandtegels keramisch | begane grond
2 x 42_54 wandtegels keramisch | begane grond
2 x 42_53 wandtegels keramisch | begane grond
2 x 42_55 wandtegels keramisch | begane grond
42_56 wandtegels keramisch | begane grond
2 x 42_48 wandtegels keramisch | begane grond
3 x 42_52 wandtegels keramisch | verdieping
4 x 42_51 wandtegels keramisch | verdieping
4 x 42_44 wandtegels keramisch | verdieping
3 x 42_45 wandtegels keramisch | verdieping
3 x 42_46 wandtegels keramisch | verdieping
4 x 42_47 wandtegels keramisch | verdieping
3 x 42_49 wandtegels keramisch | verdieping
3 x 42_50 wandtegels keramisch | verdieping
2 x 42_48 wandtegels keramisch | verdieping

# IfcColumn: 31 vliesgevelstijl 50 x 215 (5)
In: begane grond
Type - PredefinedType: COLUMN
Classification: 28.11 kolom-/liggerconstructies (NL/SfB (4 cijfers)); Kolom (ARCHICAD Classification)
Pset_ColumnCommon - Slope: 90 deg; LoadBearing: yes; IsExternal: no; Reference: 31 vliesgevelstijl 50 x 215
CPset_Phasing - Renovation Phase: Bestaand
BaseQuantities - Length: 7840 mm; CrossSectionArea: 0.01061 m2
Name | OuterSurfaceArea (m2) | TotalSurfaceArea (m2) = GrossSurfaceArea (m2) | GrossVolume (m3) = NetVolume (m3)
3 x 28_kolom ø 275mm | 4.20928 | 4.2305 | 0.0830736
28_kolom ø 275mm | 3.93365 | 3.95362 | 0.0793393
28_kolom ø 275mm | 4.21152 | 4.23271 | 0.0830992

# IfcColumn: 32 Hout binnenkozijn oregon pine 90 x 114 (2)
In: begane grond
Type - PredefinedType: COLUMN
Classification: 28.11 kolom-/liggerconstructies (NL/SfB (4 cijfers)); Kolom (ARCHICAD Classification); Material: 32 Hout binnenkozijn oregon pine
Pset_ColumnCommon - Slope: 90 deg; LoadBearing: yes; IsExternal: no; Reference: 32 Hout binnenkozijn oregon pine 90 x 114
CPset_Phasing - Renovation Phase: Bestaand
BaseQuantities - Length: 3960 mm; Width: 90 mm; Depth: 114 mm; CrossSectionArea: 0.01026 m2; OuterSurfaceArea: 1.61568 m2; TotalSurfaceArea: 1.6362 m2; GrossSurfaceArea: 1.6362 m2; GrossVolume: 0.0406296 m3; NetVolume: 0.0406296 m3
Component Quantities - 32 Hout binnenkozijn oregon pine, Mass: 22.3463 kg; 32 Hout binnenkozijn oregon pine, Component Thickness: 90 mm; 32 Hout binnenkozijn oregon pine, Rectangular Component Height: 114 mm; 32 Hout binnenkozijn oregon pine, Rectangular Component Width: 90 mm; 32 Hout binnenkozijn oregon pine, Component Cross Section Area: 0.01026 m2; 32 Hout binnenkozijn oregon pine, Component Volume (Net): 0.0406296 m3; 32 Hout binnenkozijn oregon pine, Component Volume (Gross): 0.0406296 m3

# IfcColumn: 32 Hout binnenkozijn oregon pine 90 x 210 (2)
In: begane grond
Type - PredefinedType: COLUMN
Classification: 28.11 kolom-/liggerconstructies (NL/SfB (4 cijfers)); Kolom (ARCHICAD Classification); Material: 32 Hout binnenkozijn oregon pine
Pset_ColumnCommon - Slope: 90 deg; LoadBearing: yes; IsExternal: no; Reference: 32 Hout binnenkozijn oregon pine 90 x 210
CPset_Phasing - Renovation Phase: Bestaand
BaseQuantities - Length: 2600 mm; Width: 90 mm; Depth: 210 mm; CrossSectionArea: 0.0189 m2; OuterSurfaceArea: 1.56 m2; TotalSurfaceArea: 1.5978 m2; GrossSurfaceArea: 1.5978 m2; GrossVolume: 0.04914 m3; NetVolume: 0.04914 m3
Component Quantities - 32 Hout binnenkozijn oregon pine, Mass: 27.027 kg; 32 Hout binnenkozijn oregon pine, Component Thickness: 90 mm; 32 Hout binnenkozijn oregon pine, Rectangular Component Height: 210 mm; 32 Hout binnenkozijn oregon pine, Rectangular Component Width: 90 mm; 32 Hout binnenkozijn oregon pine, Component Cross Section Area: 0.0189 m2; 32 Hout binnenkozijn oregon pine, Component Volume (Net): 0.04914 m3; 32 Hout binnenkozijn oregon pine, Component Volume (Gross): 0.04914 m3

# IfcColumn: Hout C 120 x 38 (8)
In: begane grond
Type - PredefinedType: COLUMN
Classification: 28.11 kolom-/liggerconstructies (NL/SfB (4 cijfers)); Kolom (ARCHICAD Classification); Material: Hout C
Pset_ColumnCommon - Slope: 90 deg; LoadBearing: yes; IsExternal: no; Reference: Hout C 120 x 38
CPset_Phasing - Renovation Phase: Bestaand
BaseQuantities - Length: 2690 mm; Width: 120 mm; Depth: 38 mm; CrossSectionArea: 0.00456 m2; OuterSurfaceArea: 0.85004 m2; TotalSurfaceArea: 0.85916 m2; GrossSurfaceArea: 0.85916 m2; GrossVolume: 0.0122664 m3; NetVolume: 0.0122664 m3
Component Quantities - Hout C, Mass: 6.74652 kg; Hout C, Component Thickness: 120 mm; Hout C, Rectangular Component Height: 38 mm; Hout C, Rectangular Component Width: 120 mm; Hout C, Component Cross Section Area: 0.00456 m2; Hout C, Component Volume (Net): 0.0122664 m3; Hout C, Component Volume (Gross): 0.0122664 m3

# IfcColumn: Isolatie - Kunststof hard 105 x 60 (6)
In: verdieping
Type - PredefinedType: COLUMN
Classification: 28.11 kolom-/liggerconstructies (NL/SfB (4 cijfers)); Kolom (ARCHICAD Classification); Material: Isolatie - Kunststof hard
Pset_ColumnCommon - Slope: 90 deg; LoadBearing: no; IsExternal: no; Reference: Isolatie - Kunststof hard 105 x 60
CPset_Phasing - Renovation Phase: Bestaand
BaseQuantities - Width: 105 mm; Depth: 60 mm; CrossSectionArea: 0.0063 m2
Component Quantities - Isolatie - Kunststof hard, Component Thickness: 105 mm; Isolatie - Kunststof hard, Rectangular Component Height: 60 mm; Isolatie - Kunststof hard, Rectangular Component Width: 105 mm; Isolatie - Kunststof hard, Component Cross Section Area: 0.0063 m2
Name | Length (mm) | OuterSurfaceArea (m2) | TotalSurfaceArea (m2) = GrossSurfaceArea (m2) | GrossVolume (m3) = NetVolume (m3) = Isolatie - Kunststof hard, Component Volume (Net) (m3) = Isolatie - Kunststof hard, Component Volume (Gross) (m3) | Isolatie - Kunststof hard, Mass (kg)
28_kolom koker | 3550 | 1.1715 | 1.1841 | 0.022365 | 2.2365
5 x 28_kolom koker | 2860 | 0.9438 | 0.9564 | 0.018018 | 1.8018

# IfcColumn: Lucht 100 x 100 (6)
In: begane grond
Type - PredefinedType: COLUMN
Classification: 28.11 kolom-/liggerconstructies (NL/SfB (4 cijfers)); Kolom (ARCHICAD Classification)
Pset_ColumnCommon - Slope: 90 deg; LoadBearing: yes; IsExternal: no; Reference: Lucht 100 x 100
CPset_Phasing - Renovation Phase: Bestaand
BaseQuantities - Length: 2690 mm; Width: 100 mm; Depth: 100 mm; CrossSectionArea: 0.01 m2; OuterSurfaceArea: 1.076 m2; TotalSurfaceArea: 1.0879 m2; GrossSurfaceArea: 1.0879 m2
Name | Material | GrossVolume (m3) = NetVolume (m3) | Metaal - Staal C, Mass (kg) | Metaal - Staal C, Projected Component Area (Net) (m2) = Metaal - Staal C, Projected Component Area (Gross) (m2) | Metaal - Staal C, Component Thickness (mm) | Metaal - Staal C, Component Cross Section Area (m2) | Metaal - Staal C, Component Volume (Net) (m3) = Metaal - Staal C, Component Volume (Gross) (m3)
4 x 28_kolom ø 273mm | Metaal - Staal C | 0.005678 | 40.6324 | 1.0222 | 5 | 0.0019 | 0.005111
2 x 28_kolom ø 273mm | Metaal - Staal C wit | 0.026576 | Component Quantities - Metaal - Staal C wit, Mass: 40.6324 kg; Metaal - Staal C wit, Projected Component Area (Net): 1.0222 m2; Metaal - Staal C wit, Projected Component Area (Gross): 1.0222 m2; Metaal - Staal C wit, Component Thickness: 5 mm; Metaal - Staal C wit, Component Cross Section Area: 0.0019 m2; Metaal - Staal C wit, Component Volume (Net): 0.005111 m3; Metaal - Staal C wit, Component Volume (Gross): 0.005111 m3

# IfcColumn: Lucht 150 x 150 (20)
Type - PredefinedType: COLUMN
Classification: 28.11 kolom-/liggerconstructies (NL/SfB (4 cijfers)); Kolom (ARCHICAD Classification); Material: Metaal - Staal C wit
Pset_ColumnCommon - Slope: 90 deg; LoadBearing: yes; IsExternal: no; Reference: Lucht 150 x 150
CPset_Phasing - Renovation Phase: Bestaand
BaseQuantities - Width: 150 mm; Depth: 150 mm; CrossSectionArea: 0.0225 m2
Component Quantities - Metaal - Staal C wit, Component Thickness: 10 mm; Metaal - Staal C wit, Component Cross Section Area: 0.0056 m2
Name | In | Length (mm) | OuterSurfaceArea (m2) | TotalSurfaceArea (m2) = GrossSurfaceArea (m2) | GrossVolume (m3) = NetVolume (m3) | Metaal - Staal C wit, Mass (kg) | Metaal - Staal C wit, Projected Component Area (Net) (m2) = Metaal - Staal C wit, Projected Component Area (Gross) (m2) | Metaal - Staal C wit, Component Volume (Net) (m3) = Metaal - Staal C wit, Component Volume (Gross) (m3)
6 x 28_kolom koker | verdieping | 3940 | 2.364 | 2.3921 | 0.083242 | 175.409 | 2.2064 | 0.022064
11 x 28_kolom ø 273mm | techniek | 2930 | 1.758 | 1.7861 | 0.057644 | 130.444 | 1.6408 | 0.016408
2 x 28_kolom ø 273mm | techniek | 2930 | 1.758 | 1.7939 | 0.062922 | 130.444 | 1.6408 | 0.016408
28_kolom ø 273mm | techniek | 2930 | 1.758 | 1.7848 | 0.0627855 | 130.444 | 1.6408 | 0.016408

# IfcColumn: Lucht 80 x 80 (2)
In: begane grond
Type - PredefinedType: COLUMN
Classification: 28.11 kolom-/liggerconstructies (NL/SfB (4 cijfers)); Kolom (ARCHICAD Classification); Material: Metaal - Staal C wit
Pset_ColumnCommon - Slope: 90 deg; LoadBearing: yes; IsExternal: no; Reference: Lucht 80 x 80
CPset_Phasing - Renovation Phase: Bestaand
BaseQuantities - Length: 940 mm; Width: 80 mm; Depth: 80 mm; CrossSectionArea: 0.0064 m2; OuterSurfaceArea: 0.3008 m2; TotalSurfaceArea: 0.3087 m2; GrossSurfaceArea: 0.3087 m2; GrossVolume: 0.0053055 m3; NetVolume: 0.0053055 m3
Component Quantities - Metaal - Staal C wit, Mass: 11.2095 kg; Metaal - Staal C wit, Projected Component Area (Net): 0.282 m2; Metaal - Staal C wit, Projected Component Area (Gross): 0.282 m2; Metaal - Staal C wit, Component Thickness: 5 mm; Metaal - Staal C wit, Component Cross Section Area: 0.0015 m2; Metaal - Staal C wit, Component Volume (Net): 0.00141 m3; Metaal - Staal C wit, Component Volume (Gross): 0.00141 m3

# IfcColumn: Lucht D194, 28_kolom ø 193,7mm
In: verdieping
Type - PredefinedType: COLUMN
Classification: 28.11 kolom-/liggerconstructies (NL/SfB (4 cijfers)); Kolom (ARCHICAD Classification); Material: Metaal - Staal C wit
Pset_ColumnCommon - Slope: 90 deg; LoadBearing: yes; IsExternal: no; Reference: Lucht D194
CPset_Phasing - Renovation Phase: Bestaand
BaseQuantities - Length: 3340 mm; Width: 193.7 mm; Depth: 193.7 mm; CrossSectionArea: 0.0294679 m2; OuterSurfaceArea: 2.02668 m2; TotalSurfaceArea: 2.08494 m2; GrossSurfaceArea: 2.08494 m2; GrossVolume: 0.0973023 m3; NetVolume: 0.0973023 m3
Component Quantities - Metaal - Staal C wit, Mass: 123.935 kg; Metaal - Staal C wit, Projected Component Area (Net): 1.94854 m2; Metaal - Staal C wit, Projected Component Area (Gross): 1.94854 m2; Metaal - Staal C wit, Component Thickness: 8 mm; Metaal - Staal C wit, Component Cross Section Area: 0.00466715 m2; Metaal - Staal C wit, Component Volume (Net): 0.0155893 m3; Metaal - Staal C wit, Component Volume (Gross): 0.0155893 m3

# IfcColumn: Lucht D219 (4)
In: begane grond
Type - PredefinedType: COLUMN
Classification: 28.11 kolom-/liggerconstructies (NL/SfB (4 cijfers)); Kolom (ARCHICAD Classification); Material: Metaal - Staal C wit
Pset_ColumnCommon - Slope: 90 deg; LoadBearing: yes; IsExternal: no; Reference: Lucht D219
CPset_Phasing - Renovation Phase: Bestaand
BaseQuantities - Width: 219.1 mm; Depth: 219.1 mm; CrossSectionArea: 0.0377029 m2
Component Quantities - Metaal - Staal C wit, Component Thickness: 16 mm; Metaal - Staal C wit, Component Cross Section Area: 0.0102089 m2
Name | Length (mm) | OuterSurfaceArea (m2) | TotalSurfaceArea (m2) = GrossSurfaceArea (m2) | GrossVolume (m3) = NetVolume (m3) | Metaal - Staal C wit, Mass (kg) | Metaal - Staal C wit, Projected Component Area (Net) (m2) = Metaal - Staal C wit, Projected Component Area (Gross) (m2) | Metaal - Staal C wit, Component Volume (Net) (m3) = Metaal - Staal C wit, Component Volume (Gross) (m3)
2 x 28_kolom ø 273mm | 3610 | 2.47776 | 2.5523 | 0.134558 | 291.356 | 2.30339 | 0.0366485
2 x 28_kolom ø 273mm | 3659.54 | 2.51176 | 2.55919 | 0.135603 | 295.355 | 2.335 | 0.0371515

# IfcColumn: Lucht D245 (53)
Type - PredefinedType: COLUMN
Classification: 28.11 kolom-/liggerconstructies (NL/SfB (4 cijfers)); Kolom (ARCHICAD Classification); Material: Metaal - Staal C wit
Pset_ColumnCommon - LoadBearing: yes; IsExternal: no; Reference: Lucht D245
CPset_Phasing - Renovation Phase: Bestaand
BaseQuantities - Width: 244.5 mm; Depth: 244.5 mm; CrossSectionArea: 0.0469513 m2
Component Quantities - Metaal - Staal C wit, Component Thickness: 16 mm; Metaal - Staal C wit, Component Cross Section Area: 0.0114857 m2
Name | In | Slope (deg) | Length (mm) | OuterSurfaceArea (m2) | TotalSurfaceArea (m2) = GrossSurfaceArea (m2) | GrossVolume (m3) = NetVolume (m3) | Metaal - Staal C wit, Mass (kg) | Metaal - Staal C wit, Projected Component Area (Net) (m2) = Metaal - Staal C wit, Projected Component Area (Gross) (m2) | Metaal - Staal C wit, Component Volume (Net) (m3) = Metaal - Staal C wit, Component Volume (Gross) (m3)
19 x 28_kolom ø 273mm | begane grond | 90 | 3330 | 2.55247 | 2.64559 | 0.155039 | 304.349 | 2.39045 | 0.0382829
2 x 28_kolom ø 273mm | begane grond | 90 | 3610 | 2.7671 | 2.86021 | 0.168075 | 329.94 | 2.59145 | 0.0415018
28_kolom ø 273mm | begane grond | 90 | 3630 | 2.78243 | 2.87554 | 0.169006 | 331.768 | 2.60581 | 0.0417318
28_kolom ø 273mm | begane grond | 90 | 3330 | 2.52483 | 2.61794 | 0.154696 | 301.795 | 2.37834 | 0.0379617
3 x 28_kolom ø 273mm | begane grond | 90 | 3610 | 2.73945 | 2.83257 | 0.167733 | 327.386 | 2.57934 | 0.0411806
4 x 28_kolom ø 273mm | begane grond | 82.5 | 3673.34 | 2.79097 | 2.88489 | 0.169526 | 332.787 | 2.61478 | 0.04186
7 x 28_kolom ø 273mm | verdieping | 90 | 3340 | 2.56014 | 2.65326 | 0.155505 | 305.263 | 2.39763 | 0.0383978
28_kolom ø 273mm | verdieping | 90 | 3350 | 2.5678 | 2.66092 | 0.15597 | 306.177 | 2.40481 | 0.0385128
3 x 28_kolom ø 273mm | verdieping | 90 | 3620 | 2.77476 | 2.86788 | 0.168541 | 330.854 | 2.59863 | 0.0416168
11 x 28_kolom ø 273mm | verdieping | 90 | 3330 | 2.55247 | 2.64559 | 0.155039 | 304.349 | 2.39045 | 0.0382829
28_kolom ø 273mm | verdieping | 90 | 3620 | 2.77476 | 2.86788 | 0.168246 | 330.854 | 2.59863 | 0.0416168

# IfcColumn: Metaal - Aluminium beige 15 x 80 (15)
Type - PredefinedType: COLUMN
Classification: 28.11 kolom-/liggerconstructies (NL/SfB (4 cijfers)); Kolom (ARCHICAD Classification); Material: Metaal - Aluminium beige
Pset_ColumnCommon - Slope: 90 deg; LoadBearing: no; IsExternal: no; Reference: Metaal - Aluminium beige 15 x 80
CPset_Phasing - Renovation Phase: Bestaand
BaseQuantities - Width: 15 mm; Depth: 80 mm; CrossSectionArea: 0.0012 m2
Component Quantities - Metaal - Aluminium beige, Component Thickness: 15 mm; Metaal - Aluminium beige, Rectangular Component Height: 80 mm; Metaal - Aluminium beige, Rectangular Component Width: 15 mm; Metaal - Aluminium beige, Component Cross Section Area: 0.0012 m2
Name | In | Length (mm) | OuterSurfaceArea (m2) | TotalSurfaceArea (m2) = GrossSurfaceArea (m2) | GrossVolume (m3) = NetVolume (m3) = Metaal - Aluminium beige, Component Volume (Net) (m3) = Metaal - Aluminium beige, Component Volume (Gross) (m3) | Metaal - Aluminium beige, Mass (kg)
7 x 28_kolom koker | begane grond | 3210 | 0.6099 | 0.6123 | 0.003852 | 10.7856
7 x 28_kolom koker | verdieping | 2860 | 0.5434 | 0.5458 | 0.003432 | 9.6096
28_kolom koker | verdieping | 3547 | 0.67393 | 0.67633 | 0.0042564 | 11.9179

# IfcColumn: Metaal - RVS 40 x 20 (4)
In: begane grond
Type - PredefinedType: COLUMN
Classification: 28.11 kolom-/liggerconstructies (NL/SfB (4 cijfers)); Kolom (ARCHICAD Classification); Material: Metaal - RVS
Pset_ColumnCommon - Slope: 90 deg; LoadBearing: yes; IsExternal: no; Reference: Metaal - RVS 40 x 20
CPset_Phasing - Renovation Phase: Bestaand
BaseQuantities - Length: 1021.6 mm; Width: 40 mm; Depth: 20 mm; CrossSectionArea: 0.0008 m2; OuterSurfaceArea: 0.122592 m2; TotalSurfaceArea: 0.124192 m2; GrossSurfaceArea: 0.124192 m2; GrossVolume: 0.00081728 m3; NetVolume: 0.00081728 m3
Component Quantities - Metaal - RVS, Mass: 6.45651 kg; Metaal - RVS, Component Thickness: 40 mm; Metaal - RVS, Rectangular Component Height: 20 mm; Metaal - RVS, Rectangular Component Width: 40 mm; Metaal - RVS, Component Cross Section Area: 0.0008 m2; Metaal - RVS, Component Volume (Net): 0.00081728 m3; Metaal - RVS, Component Volume (Gross): 0.00081728 m3

# IfcColumn: Metaal - Staal C wit 20 x 130 (15)
Type - PredefinedType: COLUMN
Classification: 28.11 kolom-/liggerconstructies (NL/SfB (4 cijfers)); Kolom (ARCHICAD Classification); Material: Metaal - Staal C wit
Pset_ColumnCommon - Slope: 90 deg; LoadBearing: no; IsExternal: no; Reference: Metaal - Staal C wit 20 x 130
CPset_Phasing - Renovation Phase: Bestaand
BaseQuantities - Width: 20 mm; Depth: 130 mm; CrossSectionArea: 0.0026 m2
Component Quantities - Metaal - Staal C wit, Component Thickness: 20 mm; Metaal - Staal C wit, Rectangular Component Height: 130 mm; Metaal - Staal C wit, Rectangular Component Width: 20 mm; Metaal - Staal C wit, Component Cross Section Area: 0.0026 m2
Name | In | Length (mm) | OuterSurfaceArea (m2) | TotalSurfaceArea (m2) = GrossSurfaceArea (m2) | GrossVolume (m3) = NetVolume (m3) = Metaal - Staal C wit, Component Volume (Net) (m3) = Metaal - Staal C wit, Component Volume (Gross) (m3) | Metaal - Staal C wit, Mass (kg)
7 x 28_kolom koker | begane grond | 3210 | 0.963 | 0.9682 | 0.008346 | 66.3507
7 x 28_kolom koker | verdieping | 2860 | 0.858 | 0.8632 | 0.007436 | 59.1162
28_kolom koker | verdieping | 3547 | 1.0641 | 1.0693 | 0.0092222 | 73.3165

# IfcColumn: Metaal - Staal C wit 80 x 15, 28_kolom koker
In: verdieping
Type - PredefinedType: COLUMN
Classification: 28.11 kolom-/liggerconstructies (NL/SfB (4 cijfers)); Kolom (ARCHICAD Classification); Material: Metaal - Staal C wit
Pset_ColumnCommon - Slope: 90 deg; LoadBearing: yes; IsExternal: no; Reference: Metaal - Staal C wit 80 x 15
CPset_Phasing - Renovation Phase: Bestaand
BaseQuantities - Length: 4040 mm; Width: 80 mm; Depth: 15 mm; CrossSectionArea: 0.0012 m2; OuterSurfaceArea: 0.7676 m2; TotalSurfaceArea: 0.77 m2; GrossSurfaceArea: 0.77 m2; GrossVolume: 0.004848 m3; NetVolume: 0.004848 m3
Component Quantities - Metaal - Staal C wit, Mass: 38.5416 kg; Metaal - Staal C wit, Component Thickness: 80 mm; Metaal - Staal C wit, Rectangular Component Height: 15 mm; Metaal - Staal C wit, Rectangular Component Width: 80 mm; Metaal - Staal C wit, Component Cross Section Area: 0.0012 m2; Metaal - Staal C wit, Component Volume (Net): 0.004848 m3; Metaal - Staal C wit, Component Volume (Gross): 0.004848 m3

# IfcColumn: UNP300 100 x 300 (2)
In: fundering
Type - PredefinedType: COLUMN
Classification: 28.11 kolom-/liggerconstructies (NL/SfB (4 cijfers)); Kolom (ARCHICAD Classification); Material: Metaal - Staal C
Pset_ColumnCommon - Slope: 90 deg; LoadBearing: yes; IsExternal: no; Reference: UNP300 100 x 300
CPset_Phasing - Renovation Phase: Bestaand
BaseQuantities - Length: 637 mm; CrossSectionArea: 0.00588 m2; OuterSurfaceArea: 0.62426 m2; TotalSurfaceArea: 0.63602 m2; GrossSurfaceArea: 0.63602 m2; GrossVolume: 0.00374556 m3; NetVolume: 0.00374556 m3
Component Quantities - Metaal - Staal C, Mass: 29.7772 kg; Metaal - Staal C, Component Cross Section Area: 0.00588 m2; Metaal - Staal C, Component Volume (Net): 0.00374556 m3; Metaal - Staal C, Component Volume (Gross): 0.00374556 m3

# IfcCovering: Ceiling Editor INT_v2.01 (94)
Type - PredefinedType: CEILING
Classification: Plafondafwerking (ARCHICAD Classification); 45 Plafondafwerkingen (NL/SfB (4 cijfers))
Pset_CoveringCommon - Material: Lege arcering (01)
CPset_Phasing - Renovation Phase: Bestaand
Name | In | Component, Component Volume (Net) (m3) | Component, Component Volume (Gross) (m3)
45 Plafondafwerkingen_77 garderobe | begane grond | 0.908137 | 0.910077
2 x 45 Plafondafwerkingen_77 garderobe | begane grond | 0.537133 | 0.537133
45 Plafondafwerkingen_77 garderobe | begane grond | 0.220514 | 0.220514
45 Plafondafwerkingen_77 garderobe | begane grond | 0.0281791 | 0.0281791
45 Plafondafwerkingen_77 garderobe | begane grond | 0.0873301 | 0.0873301
45 Plafondafwerkingen_77 garderobe | begane grond | 0.0881943 | 0.0881943
3 x 45 Plafondafwerkingen_77 garderobe | begane grond | 0.910077 | 0.910077
2 x 45 Plafondafwerkingen_77 garderobe | begane grond | 0.305983 | 0.305983
2 x 45 Plafondafwerkingen_77 garderobe | begane grond | 0.108793 | 0.108793
45 Plafondafwerkingen_77 garderobe | begane grond | 0.158759 | 0.158759
2 x 45 Plafondafwerkingen_77 garderobe | begane grond | 0.283077 | 0.283077
45 Plafondafwerkingen_77 garderobe | begane grond | 0.0688089 | 0.0688089
45 Plafondafwerkingen_77 garderobe | begane grond | 1.49301 | 1.49301
45 Plafondafwerkingen_77 garderobe | begane grond | 0.319027 | 0.319027
45 Plafondafwerkingen_77 garderobe | begane grond | 0.180989 | 0.180989
45 Plafondafwerkingen_77 garderobe | begane grond | 0.0335133 | 0.0335133
3 x 45 Plafondafwerkingen_77 garderobe | begane grond | 0.768561 | 0.768561
45 Plafondafwerkingen_77 garderobe | begane grond | 0.206027 | 0.206027
45 Plafondafwerkingen_77 garderobe | begane grond | 0.299651 | 0.299651
45 Plafondafwerkingen_77 garderobe | begane grond | 0.0628886 | 0.0628886
45 Plafondafwerkingen_77 garderobe | begane grond | 0.869643 | 0.869643
45 Plafondafwerkingen_77 garderobe | begane grond | 0.135464 | 0.135464
45 Plafondafwerkingen_77 garderobe | begane grond | 0.259569 | 0.259569
45 Plafondafwerkingen_77 garderobe | begane grond | 0.198381 | 0.198381
45 Plafondafwerkingen_77 garderobe | begane grond | 0.375262 | 0.375262
45 Plafondafwerkingen_77 garderobe | begane grond | 0.0871191 | 0.0871191
45 Plafondafwerkingen_77 garderobe | begane grond | 0.05538 | 0.05538
2 x 45 Plafondafwerkingen_77 garderobe | begane grond | 0.0312972 | 0.0312972
45 Plafondafwerkingen_77 garderobe | begane grond | 0.119474 | 0.119474
45 Plafondafwerkingen_77 garderobe | begane grond | 0.141515 | 0.141515
45 Plafondafwerkingen_77 garderobe | begane grond | 0.181903 | 0.181903
45 Plafondafwerkingen_77 garderobe | begane grond | 0.178153 | 0.178153
2 x 45 Plafondafwerkingen_77 garderobe | begane grond | 0.175431 | 0.175431
45 Plafondafwerkingen_77 garderobe | begane grond | 0.654127 | 0.654127
45 Plafondafwerkingen_77 garderobe | begane grond | 0.177901 | 0.177901
2 x 45 Plafondafwerkingen_77 garderobe | begane grond | 0.952049 | 0.952049
45 Plafondafwerkingen_77 garderobe | begane grond | 0.0442034 | 0.0442034
45 Plafondafwerkingen_77 garderobe | begane grond | 0.668558 | 0.668558
45 Plafondafwerkingen_77 garderobe | begane grond | 0.158315 | 0.158315
45 Plafondafwerkingen_77 garderobe | begane grond | 0.900849 | 0.900849
45 Plafondafwerkingen_77 garderobe | begane grond | 0.445558 | 0.445558
45 Plafondafwerkingen_77 garderobe | begane grond | 0.0295169 | 0.0295169
45 Plafondafwerkingen_77 garderobe | verdieping | 0.62784 | 0.62784
45 Plafondafwerkingen_77 garderobe | verdieping | 0.106009 | 0.106009
45 Plafondafwerkingen_77 garderobe | verdieping | 0.188648 | 0.188648
45 Plafondafwerkingen_77 garderobe | verdieping | 0.95162 | 0.95162
45 Plafondafwerkingen_77 garderobe | verdieping | 0.710514 | 0.710514
45 Plafondafwerkingen_77 garderobe | verdieping | 0.0871191 | 0.0871191
45 Plafondafwerkingen_77 garderobe | verdieping | 0.05538 | 0.05538
45 Plafondafwerkingen_77 garderobe | verdieping | 0.284932 | 0.284932
2 x 45 Plafondafwerkingen_77 garderobe | verdieping | 0.305983 | 0.305983
45 Plafondafwerkingen_77 garderobe | verdieping | 0.303557 | 0.303557
45 Plafondafwerkingen_77 garderobe | verdieping | 0.668558 | 0.668558
45 Plafondafwerkingen_77 garderobe | verdieping | 0.730417 | 0.730417
45 Plafondafwerkingen_77 garderobe | verdieping | 0.296056 | 0.296056
45 Plafondafwerkingen_77 garderobe | verdieping | 0.303558 | 0.303558
45 Plafondafwerkingen_77 garderobe | verdieping | 0.330434 | 0.330434
45 Plafondafwerkingen_77 garderobe | verdieping | 0.170981 | 0.170981
45 Plafondafwerkingen_77 garderobe | verdieping | 0.174545 | 0.174545
45 Plafondafwerkingen_77 garderobe | verdieping | 0.429779 | 0.429779
45 Plafondafwerkingen_77 garderobe | verdieping | 0.465718 | 0.465718
45 Plafondafwerkingen_77 garderobe | verdieping | 0.856243 | 0.856243
4 x 45 Plafondafwerkingen_77 garderobe | verdieping | 0.910077 | 0.910077
2 x 45 Plafondafwerkingen_77 garderobe | verdieping | 0.952049 | 0.952049
2 x 45 Plafondafwerkingen_77 garderobe | verdieping | 1.0297 | 1.0297
3 x 45 Plafondafwerkingen_77 garderobe | verdieping | 0.141515 | 0.141515
2 x 45 Plafondafwerkingen_77 garderobe | verdieping | 0.0312972 | 0.0312972
45 Plafondafwerkingen_77 garderobe | verdieping | 0.900849 | 0.900849
2 x 45 Plafondafwerkingen_77 garderobe | verdieping | 0.51741 | 0.51741
2 x 45 Plafondafwerkingen_77 garderobe | verdieping | 0.108793 | 0.108793
45 Plafondafwerkingen_77 garderobe | verdieping | 0.0229402 | 0.0229402
45 Plafondafwerkingen_77 garderobe | verdieping | 0.0295169 | 0.0295169

# IfcCovering: Cement - Dekvloer 70 (2)
In: begane grond
Type - PredefinedType: FLOORING
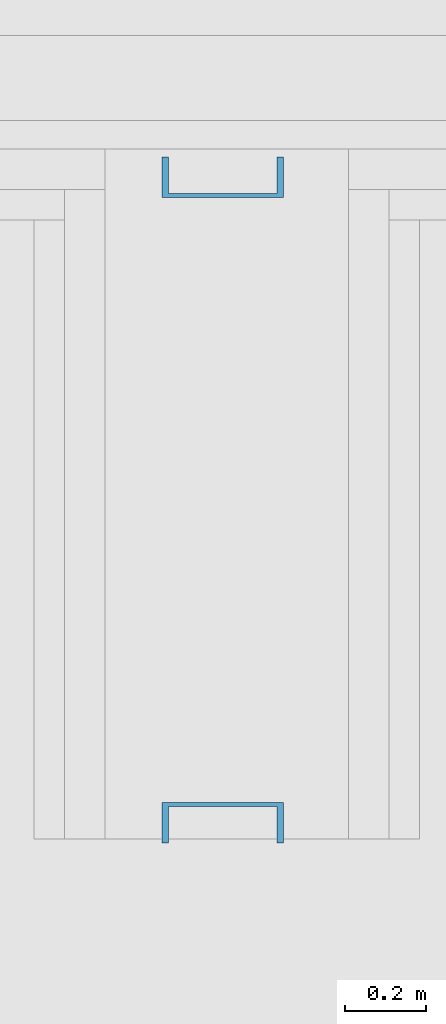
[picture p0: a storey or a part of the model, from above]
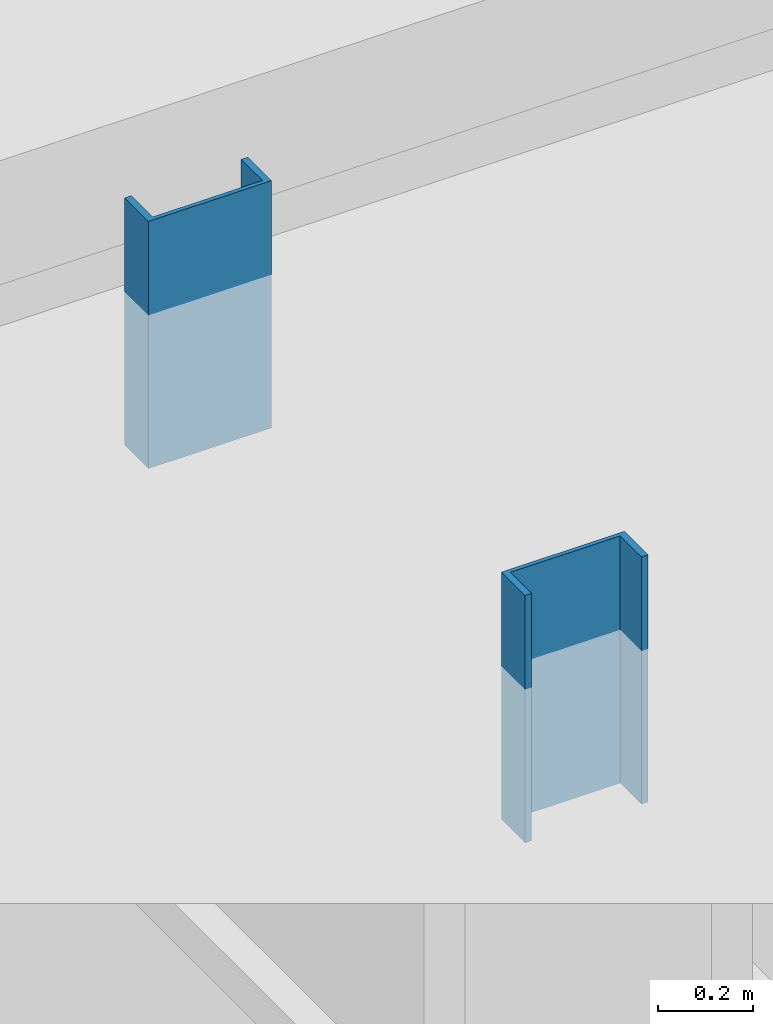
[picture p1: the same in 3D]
Properties of the parts of a building model (IFC2X3), part 5 of 9

# IfcCovering: Cement - Dekvloer 70 (2)
Classification: Vloerafwerking (ARCHICAD Classification); 23.1 niet constructief (NL/SfB (4 cijfers)); Material: Cement - Dekvloer
Pset_CoveringCommon - Material: Cement - Dekvloer
CPset_Phasing - Renovation Phase: Bestaand
Component Quantities - Cement - Dekvloer, Component Thickness: 70 mm
Name | GrossArea (m2) | NetArea (m2) | Cement - Dekvloer, Mass (kg) | Cement - Dekvloer, Projected Component Area (Net) (m2) | Cement - Dekvloer, Projected Component Area (Gross) (m2) | Cement - Dekvloer, Component Volume (Net) (m3) | Cement - Dekvloer, Component Volume (Gross) (m3)
23_cemendekvloer | 1391.15 | 1360.58 | 180961 | 1360.62 | 1366.1 | 95.2424 | 95.6261
23_cemendekvloer | 105.271 | 103.304 | 13739.4 | 103.304 | 103.304 | 7.23128 | 7.23128

# IfcCovering: Isolatie - Kunststof hard 30, 23_cemendekvloer
In: begane grond
Type - PredefinedType: FLOORING
Classification: Vloerafwerking (ARCHICAD Classification); 23.1 niet constructief (NL/SfB (4 cijfers)); Material: Isolatie - Kunststof hard
Pset_CoveringCommon - Material: Isolatie - Kunststof hard
CPset_Phasing - Renovation Phase: Bestaand
BaseQuantities - GrossArea: 105.271 m2; NetArea: 105.271 m2
Component Quantities - Isolatie - Kunststof hard, Mass: 315.812 kg; Isolatie - Kunststof hard, Projected Component Area (Net): 105.271 m2; Isolatie - Kunststof hard, Projected Component Area (Gross): 105.271 m2; Isolatie - Kunststof hard, Component Thickness: 30 mm; Isolatie - Kunststof hard, Component Volume (Net): 3.15812 m3; Isolatie - Kunststof hard, Component Volume (Gross): 3.15812 m3

# IfcDistributionElement: Bovenkast recht 25 (4)
In: begane grond
Classification: Installaties (ARCHICAD Classification); 65 Beveiliging (NL/SfB (4 cijfers))
CPset_Phasing - Renovation Phase: Bestaand
Component Quantities - Component, Component Volume (Net): 0.031868 m3; Component, Component Volume (Gross): 0.031868 m3

# IfcDistributionElement: Hoge kast recht 25 (27)
In: begane grond
Classification: Installaties (ARCHICAD Classification); 65 Beveiliging (NL/SfB (4 cijfers))
CPset_Phasing - Renovation Phase: Bestaand
Name | Component, Component Volume (Net) (m3) = Component, Component Volume (Gross) (m3)
2 x 65 Beveiliging_80 garderobe | 0.105176
18 x 65 Beveiliging_80 garderobe | 0.127392
2 x 65 Beveiliging_80 garderobe | 0.122314
4 x 65 Beveiliging_80 garderobe | 0.112166
65 Beveiliging_80 garderobe | 0.100511

# IfcDistributionElement: Onderkast recht 25 (36)
Classification: Installaties (ARCHICAD Classification); 65 Beveiliging (NL/SfB (4 cijfers))
CPset_Phasing - Renovation Phase: Bestaand
Name | In | Component, Component Volume (Net) (m3) | Component, Component Volume (Gross) (m3)
12 x 65 Beveiliging_82 pantryblok | begane grond | 0.0577876 | 0.0608108
8 x 65 Beveiliging_82 pantryblok | begane grond | 0.0635937 | 0.0666168
16 x 65 Beveiliging_82 pantryblok | verdieping | 0.0635937 | 0.0666168

# IfcDistributionElement: Schoolstoel 25 (110)
Classification: Installaties (ARCHICAD Classification); 65 Beveiliging (NL/SfB (4 cijfers))
CPset_Phasing - Renovation Phase: Bestaand
Component Quantities - Component, Component Volume (Net): 0.00380569 m3; Component, Component Volume (Gross): 0.00380569 m3
Name | In
26 x 65 Beveiliging_73 pantryblok | begane grond
84 x 65 Beveiliging_73 pantryblok | verdieping

# IfcDistributionElement: Tafel rechthoekig 01 25 (26)
Classification: Installaties (ARCHICAD Classification); 65 Beveiliging (NL/SfB (4 cijfers))
CPset_Phasing - Renovation Phase: Bestaand
Name | In | Component, Component Volume (Net) (m3) = Component, Component Volume (Gross) (m3)
4 x 65 Beveiliging_73 pantryblok | begane grond | 0.02355
65 Beveiliging_73 pantryblok | begane grond | 0.0672
21 x 65 Beveiliging_73 pantryblok | verdieping | 0.02355

# IfcDoor: 32 schuifdeurkozijn 2675 KRAR (4)
Type - ParameterTakesPrecedence: no; Sizeable: no
OverallHeight: 2600 mm; OverallWidth: 3400 mm; Classification: Deur (ARCHICAD Classification); 31.31 draaideuren (NL/SfB (4 cijfers))
CPset_Phasing - Renovation Phase: Bestaand
Pset_DoorCommon - IsExternal: yes
BaseQuantities - Height: 2600 mm; Width: 3400 mm; Perimeter: 12000 mm; Area: 8.84 m2; Volume: 0.169834 m3; Depth: 125 mm; NetVolume: 0.169834 m3
Name | In
31_06.03 | begane grond
31_06.04 | begane grond
31_06.03 | verdieping
31_06.04 | verdieping

# IfcDoor: 32 schuifdeurkozijn 3400 KRAR (10)
Type - ParameterTakesPrecedence: no; Sizeable: no
OverallHeight: 2600 mm; OverallWidth: 3400 mm; Classification: Deur (ARCHICAD Classification); 32.32 schuifdeuren (NL/SfB (4 cijfers))
CPset_Phasing - Renovation Phase: Bestaand
Pset_DoorCommon - IsExternal: yes
BaseQuantities - Height: 2600 mm; Width: 3400 mm; Perimeter: 12000 mm; Area: 8.84 m2; Volume: 0.215411 m3; Depth: 125 mm; NetVolume: 0.215411 m3
Name | In
3 x 32_06.02 | begane grond
2 x 32_06.01 | begane grond
3 x 32_06.02 | verdieping
2 x 32_06.01 | verdieping

# IfcDoor: D1 25 (32)
Type - OperationType: SINGLE_SWING_LEFT; ParameterTakesPrecedence: no; Sizeable: no
Pset_DoorCommon - ThermalTransmittance: 0
Material - Frame / Draaiend deel: n.v.t.; Deurblad: n.v.t.; Onderdorpel: n.v.t.; Stofdorpel: n.v.t.; Vensterbank: n.v.t.; Ventilatierooster: n.v.t.; Spouwlat: n.v.t.; Rollaag / Latei: n.v.t.; Afwerking dagkant buiten: n.v.t.; Afwerking dagkant binnen: n.v.t.; Zonwering - behuizing: n.v.t.; Zonwering - isolatie: n.v.t.; Glas: Glas - algemeen
CPset_Phasing - Renovation Phase: Bestaand
Name | In | OverallHeight (mm) | OverallWidth (mm) | Classification | IsExternal | FireResistanceRating | Height (mm) | Width (mm) | Perimeter (mm) | Area (m2) | Volume (m3) = NetVolume (m3) | Depth (mm) | Component, Component Volume (Net) (m3) = Component, Component Volume (Gross) (m3)
32_01.03 | begane grond | 2600 | 1064 | Deur (ARCHICAD Classification); 32.31 draaideuren (NL/SfB (4 cijfers)) | no | --- | 2600 | 1064 | 7328 | 2.7664 | 0.163376 | 125 | 0.163376
32_01.04 | begane grond | 2600 | 1064 | Deur (ARCHICAD Classification); 32.31 draaideuren (NL/SfB (4 cijfers)) | no | --- | 3050 | 1064 | 8228 | 3.2452 | 0.138377 | 210
2 x 32_01.06 | begane grond | 2600 | 1064 | Deur (ARCHICAD Classification); 32.31 draaideuren (NL/SfB (4 cijfers)) | no | --- | 2600 | 1064 | 7328 | 2.7664 | 0.164251 | 125
4 x 74_A. | begane grond | 2100 | 600 | Deur (ARCHICAD Classification); 74.0 algemeen (NL/SfB (4 cijfers)) | yes |  | 2100 | 600 | 5400 | 1.26 | 0.01638 | 20 | 0.01638
7 x 32_01.01 | begane grond | 2600 | 1064 | Deur (ARCHICAD Classification); 32.31 draaideuren (NL/SfB (4 cijfers)) | no | --- | 2600 | 1064 | 7328 | 2.7664 | 0.12458 | 125 | 0.12458 | Pset_DoorCommon - GlazingAreaFraction: 1.30473
32_01.02 | begane grond | 2600 | 1064 | Deur (ARCHICAD Classification); 32.31 draaideuren (NL/SfB (4 cijfers)) | no | --- | 2600 | 1064 | 7328 | 2.7664 | 0.163376 | 125 | 0.163376
32_03.01 | begane grond | 2600 | 1250 | Deur (ARCHICAD Classification); 32.31 draaideuren (NL/SfB (4 cijfers)) | no | --- | 2600 | 1250 | 7700 | 3.25 | 0.132051 | 125 | 0.132051 | Pset_DoorCommon - GlazingAreaFraction: 1.6758
32_01.02 | begane grond | 2600 | 1064 | Deur (ARCHICAD Classification); 32.31 draaideuren (NL/SfB (4 cijfers)) | no | --- | 2600 | 1064 | 7328 | 2.7664 | 0.164251 | 125 | 0.164251
32_merk-C1 | begane grond | 2640 | 1204 | Deur (ARCHICAD Classification); 32.31 draaideuren (NL/SfB (4 cijfers)) | no |  | 2640 | 1202 | 7684 | 3.17568 | 0.0778404 |  | 0.0778404 | Pset_DoorCommon - GlazingAreaFraction: 2.04311
2 x 32_01.07 | begane grond | 2600 | 1064 | Deur (ARCHICAD Classification); 32.31 draaideuren (NL/SfB (4 cijfers)) | no | --- | 2600 | 1064 | 7328 | 2.7664 | 0.164251 | 125
32_01.03 | verdieping | 2600 | 1064 | Deur (ARCHICAD Classification); 32.31 draaideuren (NL/SfB (4 cijfers)) | no | --- | 2600 | 1064 | 7328 | 2.7664 | 0.163376 | 125 | 0.163376
32_01.05 | verdieping | 2600 | 1064 | Deur (ARCHICAD Classification); 32.31 draaideuren (NL/SfB (4 cijfers)) | no | --- | 2600 | 1064 | 7328 | 2.7664 | 0.164251 | 125
4 x 32_01.01 | verdieping | 2600 | 1064 | Deur (ARCHICAD Classification); 32.31 draaideuren (NL/SfB (4 cijfers)) | no | --- | 2600 | 1064 | 7328 | 2.7664 | 0.12458 | 125 | 0.12458 | Pset_DoorCommon - GlazingAreaFraction: 1.30473
4 x 74_A. | verdieping | 2100 | 600 | Deur (ARCHICAD Classification); 74.0 algemeen (NL/SfB (4 cijfers)) | yes |  | 2100 | 600 | 5400 | 1.26 | 0.01638 | 20 | 0.01638
32_01.02 | verdieping | 2600 | 1064 | Deur (ARCHICAD Classification); 32.31 draaideuren (NL/SfB (4 cijfers)) | no | --- | 2600 | 1064 | 7328 | 2.7664 | 0.163376 | 125 | 0.163376

# IfcDoor: D1 25 (39)
Type - OperationType: SINGLE_SWING_RIGHT; ParameterTakesPrecedence: no; Sizeable: no
Pset_DoorCommon - ThermalTransmittance: 0
Material - Frame / Draaiend deel: n.v.t.; Deurblad: n.v.t.; Onderdorpel: n.v.t.; Stofdorpel: n.v.t.; Vensterbank: n.v.t.; Ventilatierooster: n.v.t.; Spouwlat: n.v.t.; Rollaag / Latei: n.v.t.; Afwerking dagkant buiten: n.v.t.; Afwerking dagkant binnen: n.v.t.; Zonwering - behuizing: n.v.t.; Zonwering - isolatie: n.v.t.; Glas: Glas - algemeen
CPset_Phasing - Renovation Phase: Bestaand
Name | In | OverallHeight (mm) | OverallWidth (mm) = Width (mm) | Classification | IsExternal | FireResistanceRating | Height (mm) | Perimeter (mm) | Area (m2) | Volume (m3) = NetVolume (m3) | Depth (mm) | Component, Component Volume (Net) (m3) = Component, Component Volume (Gross) (m3)
6 x 32_02.01 | begane grond | 2600 | 1064 | Deur (ARCHICAD Classification); 32.31 draaideuren (NL/SfB (4 cijfers)) | no | --- | 2600 | 7328 | 2.7664 | 0.12458 | 125 | 0.12458 | Pset_DoorCommon - GlazingAreaFraction: 1.30473
5 x 32_02.05 | begane grond | 2600 | 1064 | Deur (ARCHICAD Classification); 32.31 draaideuren (NL/SfB (4 cijfers)) | no | --- | 2600 | 7328 | 2.7664 | 0.164251 | 125
32_02.05 | begane grond | 2600 | 1064 | Deur (ARCHICAD Classification); 32.31 draaideuren (NL/SfB (4 cijfers)) | no | --- | 2600 | 7328 | 2.7664 | 0.164251 | 125 | 0.164251
5 x 74_A. | begane grond | 2100 | 600 | Deur (ARCHICAD Classification); 74.0 algemeen (NL/SfB (4 cijfers)) | yes |  | 2100 | 5400 | 1.26 | 0.01638 | 20 | 0.01638
32_02.03 | begane grond | 2600 | 1064 | Deur (ARCHICAD Classification); 32.31 draaideuren (NL/SfB (4 cijfers)) | no | --- | 2600 | 7328 | 2.7664 | 0.163376 | 125 | 0.163376
32_02.06 | begane grond | 2600 | 1064 | Deur (ARCHICAD Classification); 32.31 draaideuren (NL/SfB (4 cijfers)) | no | --- | 2600 | 7328 | 2.7664 | 0.164251 | 125
32_02.04 | begane grond | 2600 | 1064 | Deur (ARCHICAD Classification); 32.31 draaideuren (NL/SfB (4 cijfers)) | no | --- | 2600 | 7328 | 2.7664 | 0.138377 | 125
32_02.04 | begane grond | 2600 | 1064 | Deur (ARCHICAD Classification); 32.31 draaideuren (NL/SfB (4 cijfers)) | no | --- | 3050 | 8228 | 3.2452 | 0.138377 | 210
2 x 32_Lift deur | begane grond | 2600 | 1462 | Deur (ARCHICAD Classification); 32.31 draaideuren (NL/SfB (4 cijfers)) | no |  | 2600 | 8124 | 3.8012 | 0.10454 | 40 | 0.10454 | Pset_DoorCommon - GlazingAreaFraction: 1.2152
32_02.03 | verdieping | 2600 | 1064 | Deur (ARCHICAD Classification); 32.31 draaideuren (NL/SfB (4 cijfers)) | no | --- | 2600 | 7328 | 2.7664 | 0.163376 | 125 | 0.163376
6 x 32_02.01 | verdieping | 2600 | 1064 | Deur (ARCHICAD Classification); 32.31 draaideuren (NL/SfB (4 cijfers)) | no | --- | 2600 | 7328 | 2.7664 | 0.12458 | 125 | 0.12458 | Pset_DoorCommon - GlazingAreaFraction: 1.30473
2 x 32_02.04 | verdieping | 2600 | 1064 | Deur (ARCHICAD Classification); 32.31 draaideuren (NL/SfB (4 cijfers)) | no | --- | 2600 | 7328 | 2.7664 | 0.138377 | 210
32_02.04 | verdieping | 2600 | 1064 | Deur (ARCHICAD Classification); 32.31 draaideuren (NL/SfB (4 cijfers)) | no | --- | 2600 | 7328 | 2.7664 | 0.138377 | 125
5 x 74_A. | verdieping | 2100 | 600 | Deur (ARCHICAD Classification); 74.0 algemeen (NL/SfB (4 cijfers)) | yes |  | 2100 | 5400 | 1.26 | 0.01638 | 20 | 0.01638
32_02.02 | verdieping | 2600 | 1064 | Deur (ARCHICAD Classification); 32.31 draaideuren (NL/SfB (4 cijfers)) | no | --- | 2600 | 7328 | 2.7664 | 0.163376 | 125 | 0.163376

# IfcDoor: D1 bl 25, 32_merk-AM
In: begane grond
Type - OperationType: SINGLE_SWING_LEFT; ParameterTakesPrecedence: no; Sizeable: no
OverallHeight: 3240 mm; OverallWidth: 1150 mm; Classification: Deur (ARCHICAD Classification); 32.31 draaideuren (NL/SfB (4 cijfers))
Pset_DoorCommon - ThermalTransmittance: 0; GlazingAreaFraction: 2.7017; IsExternal: no
Material - Frame / Draaiend deel: n.v.t.; Deurblad: n.v.t.; Onderdorpel: n.v.t.; Stofdorpel: n.v.t.; Vensterbank: n.v.t.; Ventilatierooster: n.v.t.; Spouwlat: n.v.t.; Rollaag / Latei: n.v.t.; Afwerking dagkant buiten: n.v.t.; Afwerking dagkant binnen: n.v.t.; Zonwering - behuizing: n.v.t.; Zonwering - isolatie: n.v.t.; Glas: Glas - algemeen
Pset_FireRatingProperties - FireResistanceRating: ---
CPset_Phasing - Renovation Phase: Bestaand
BaseQuantities - Height: 3200 mm; Width: 1150 mm; Perimeter: 8700 mm; Area: 3.68 m2; Volume: 0.0712857 m3; Depth: 62 mm; NetVolume: 0.0712857 m3
Component Quantities - Component, Component Volume (Net): 0.0712857 m3; Component, Component Volume (Gross): 0.0712857 m3

# IfcDoor: D1 bl zl1-a 25 (3)
Type - OperationType: SINGLE_SWING_RIGHT; ParameterTakesPrecedence: no; Sizeable: no
Classification: Deur (ARCHICAD Classification); 32.31 draaideuren (NL/SfB (4 cijfers))
Pset_DoorCommon - ThermalTransmittance: 0; IsExternal: no
Material - Frame / Draaiend deel: n.v.t.; Deurblad: n.v.t.; Onderdorpel: n.v.t.; Stofdorpel: n.v.t.; Vensterbank: n.v.t.; Ventilatierooster: n.v.t.; Spouwlat: n.v.t.; Rollaag / Latei: n.v.t.; Afwerking dagkant buiten: n.v.t.; Afwerking dagkant binnen: n.v.t.; Zonwering - behuizing: n.v.t.; Zonwering - isolatie: n.v.t.; Glas: Glas - algemeen
Pset_FireRatingProperties - FireResistanceRating: ---
CPset_Phasing - Renovation Phase: Bestaand
Name | In | OverallHeight (mm) = Height (mm) | OverallWidth (mm) = Width (mm) | GlazingAreaFraction | Perimeter (mm) | Area (m2) | Volume (m3) = NetVolume (m3) = Component, Component Volume (Net) (m3) = Component, Component Volume (Gross) (m3)
32_merk-AS | begane grond | 3590 | 2278 | 6.67801 | 11736 | 8.15677 | 0.088416
32_merk-BM3 | verdieping | 3547 | 3540 | 9.37513 | 14174 | 10.9145 | 0.107741
32_merk-BN | verdieping | 3920 | 2278 | 7.37856 | 12396 | 8.89226 | 0.0909315

# IfcDoor: D1 bl zl1-b 25 (4)
Type - OperationType: SINGLE_SWING_RIGHT; ParameterTakesPrecedence: no; Sizeable: no
Classification: Deur (ARCHICAD Classification); 32.31 draaideuren (NL/SfB (4 cijfers))
Pset_DoorCommon - ThermalTransmittance: 0; IsExternal: no
Material - Frame / Draaiend deel: n.v.t.; Deurblad: n.v.t.; Onderdorpel: n.v.t.; Stofdorpel: n.v.t.; Vensterbank: n.v.t.; Ventilatierooster: n.v.t.; Spouwlat: n.v.t.; Rollaag / Latei: n.v.t.; Afwerking dagkant buiten: n.v.t.; Afwerking dagkant binnen: n.v.t.; Zonwering - behuizing: n.v.t.; Zonwering - isolatie: n.v.t.; Glas: Glas - algemeen
CPset_Phasing - Renovation Phase: Bestaand
Name | In | OverallHeight (mm) | OverallWidth (mm) = Width (mm) | GlazingAreaFraction | FireResistanceRating | Height (mm) | Perimeter (mm) | Area (m2) | Volume (m3) = NetVolume (m3) = Component, Component Volume (Net) (m3) = Component, Component Volume (Gross) (m3)
32_merk-AT | begane grond | 3590 | 1400 | 2.5298 | --- | 3590 | 9980 | 5.01934 | 0.154537
32_merk-AJ3 | begane grond | 3240 | 2617.5 | 6.87928 | --- | 3200 | 11635 | 8.376 | 0.108274
32_merk-AJ1 | begane grond | 3240 | 2717.5 | 7.18408 | --- | 3200 | 11835 | 8.696 | 0.10944
32_merk-BO | verdieping | 3920 | 1400 | 2.5298 | 30 minuten brandwerend en zelfsluitend | 3920 | 10640 | 5.48134 | 0.180127

# IfcDoor: D1 zl1-a 25 (2)
Type - OperationType: SINGLE_SWING_RIGHT; ParameterTakesPrecedence: no; Sizeable: no
OverallHeight: 2600 mm; Classification: Deur (ARCHICAD Classification); 32.31 draaideuren (NL/SfB (4 cijfers))
Pset_DoorCommon - ThermalTransmittance: 0; IsExternal: no
Material - Frame / Draaiend deel: n.v.t.; Deurblad: n.v.t.; Onderdorpel: n.v.t.; Stofdorpel: n.v.t.; Vensterbank: n.v.t.; Ventilatierooster: n.v.t.; Spouwlat: n.v.t.; Rollaag / Latei: n.v.t.; Afwerking dagkant buiten: n.v.t.; Afwerking dagkant binnen: n.v.t.; Zonwering - behuizing: n.v.t.; Zonwering - isolatie: n.v.t.; Glas: Glas - algemeen
CPset_Phasing - Renovation Phase: Bestaand
BaseQuantities - Height: 2600 mm
Name | In | OverallWidth (mm) = Width (mm) | GlazingAreaFraction | FireResistanceRating | Perimeter (mm) | Area (m2) | Volume (m3) = NetVolume (m3) = Component, Component Volume (Net) (m3) = Component, Component Volume (Gross) (m3) | Depth (mm)
32_04.07 | begane grond | 1432.1 | 1.97774 | --- | 8064.2 | 3.72347 | 0.164064 | 125
32_04.09 | verdieping | 2760 | 4.97345 | 30 minuten brandwerend en zelfsluitend | 10720 | 7.176 | 0.227562 | 210

# IfcDoor: D1 zl1-b 25 (8)
In: begane grond
Type - OperationType: SINGLE_SWING_LEFT; ParameterTakesPrecedence: no; Sizeable: no
Classification: Deur (ARCHICAD Classification); 32.31 draaideuren (NL/SfB (4 cijfers))
Pset_DoorCommon - ThermalTransmittance: 0; IsExternal: no
Material - Frame / Draaiend deel: n.v.t.; Deurblad: n.v.t.; Onderdorpel: n.v.t.; Stofdorpel: n.v.t.; Vensterbank: n.v.t.; Ventilatierooster: n.v.t.; Spouwlat: n.v.t.; Rollaag / Latei: n.v.t.; Afwerking dagkant buiten: n.v.t.; Afwerking dagkant binnen: n.v.t.; Zonwering - behuizing: n.v.t.; Zonwering - isolatie: n.v.t.; Glas: Glas - algemeen
Pset_FireRatingProperties - FireResistanceRating: ---
CPset_Phasing - Renovation Phase: Bestaand
Name | OverallHeight (mm) | OverallWidth (mm) = Width (mm) | GlazingAreaFraction | Height (mm) | Perimeter (mm) | Area (m2) | Volume (m3) = NetVolume (m3) = Component, Component Volume (Net) (m3) = Component, Component Volume (Gross) (m3)
32_03.02 | 2600 | 1336 | 1.74517 | 2600 | 7872 | 3.4736 | 0.161659 | BaseQuantities - Depth: 125 mm
32_03.03 | 2600 | 2100 | 3.5728 | 3050 | 10300 | 6.405 | 0.168524 | BaseQuantities - Depth: 210 mm
3 x 32_merk-AC2 | 2640 | 2900 | 5.01553 | 2065 | 9930 | 5.66974 | 0.0919148
3 x 32_merk-AA2 | 2640 | 2725 | 4.70543 | 2065 | 9580 | 5.34074 | 0.090554

# IfcDoor: D1 zl1-b 25 (8)
Type - OperationType: SINGLE_SWING_RIGHT; ParameterTakesPrecedence: no; Sizeable: no
Classification: Deur (ARCHICAD Classification); 32.31 draaideuren (NL/SfB (4 cijfers))
Pset_DoorCommon - ThermalTransmittance: 0; IsExternal: no
Material - Frame / Draaiend deel: n.v.t.; Deurblad: n.v.t.; Onderdorpel: n.v.t.; Stofdorpel: n.v.t.; Vensterbank: n.v.t.; Ventilatierooster: n.v.t.; Spouwlat: n.v.t.; Rollaag / Latei: n.v.t.; Afwerking dagkant buiten: n.v.t.; Afwerking dagkant binnen: n.v.t.; Zonwering - behuizing: n.v.t.; Zonwering - isolatie: n.v.t.; Glas: Glas - algemeen
CPset_Phasing - Renovation Phase: Bestaand
Name | In | OverallHeight (mm) | OverallWidth (mm) = Width (mm) | GlazingAreaFraction | FireResistanceRating | Height (mm) | Perimeter (mm) | Area (m2) | Volume (m3) = NetVolume (m3) = Component, Component Volume (Net) (m3) = Component, Component Volume (Gross) (m3) | Depth (mm)
32_04.02 | begane grond | 2600 | 1336 | 1.74517 | --- | 2600 | 7872 | 3.4736 | 0.161659 | 125
32_04.05 | begane grond | 2600 | 2100 | 3.5728 | --- | 3050 | 10300 | 6.405 | 0.168524 | 210
32_merk-AB1 | begane grond | 2640 | 2625 | 4.52823 | --- | 2065 | 9380 | 5.15274 | 0.0897764
32_04.04 | begane grond | 2600 | 1625 | 2.44455 | 30 minuten brandwerend en zelfsluitend | 2600 | 8450 | 4.225 | 0.16889 | 125
32_04.06 | begane grond | 2600 | 2455.5 | 4.45436 | 30 minuten brandwerend en zelfsluitend | 2600 | 10111 | 6.3843 | 0.189669 | 125
32_04.01 | verdieping | 2600 | 2100 | 3.5728 | 30 minuten brandwerend en zelfsluitend | 2600 | 9400 | 5.46 | 0.168524 | 125
32_04.03 | verdieping | 2600 | 1399 | 1.87638 | --- | 2600 | 7998 | 3.6374 | 0.150985 | 210
32_04.01 | verdieping | 2600 | 2100 | 3.5728 | 30 minuten brandwerend en zelfsluitend | 2670 | 9540 | 5.607 | 0.168524 | 210

# IfcDoor: D1 zl2 25, 32_04.08
In: verdieping
Type - OperationType: USERDEFINED; ParameterTakesPrecedence: no; Sizeable: no
OverallHeight: 2600 mm; OverallWidth: 3295 mm; Classification: Deur (ARCHICAD Classification); 32.31 draaideuren (NL/SfB (4 cijfers))
Pset_DoorCommon - ThermalTransmittance: 0; GlazingAreaFraction: 6.2469; IsExternal: no
Material - Frame / Draaiend deel: n.v.t.; Deurblad: n.v.t.; Onderdorpel: n.v.t.; Stofdorpel: n.v.t.; Vensterbank: n.v.t.; Ventilatierooster: n.v.t.; Spouwlat: n.v.t.; Rollaag / Latei: n.v.t.; Afwerking dagkant buiten: n.v.t.; Afwerking dagkant binnen: n.v.t.; Zonwering - behuizing: n.v.t.; Zonwering - isolatie: n.v.t.; Glas: Glas - algemeen
Pset_FireRatingProperties - FireResistanceRating: 30 minuten brandwerend en zelfsluitend
CPset_Phasing - Renovation Phase: Bestaand
BaseQuantities - Height: 2600 mm; Width: 3295 mm; Perimeter: 11790 mm; Area: 8.567 m2; Volume: 0.241705 m3; Depth: 125 mm; NetVolume: 0.241705 m3
Component Quantities - Component, Component Volume (Net): 0.241705 m3; Component, Component Volume (Gross): 0.241705 m3

# IfcDoor: D2 25 (11)
In: begane grond
Type - OperationType: DOUBLE_DOOR_SINGLE_SWING; ParameterTakesPrecedence: no; Sizeable: no
Pset_DoorCommon - ThermalTransmittance: 0
Material - Frame / Draaiend deel: n.v.t.; Deurblad: n.v.t.; Onderdorpel: n.v.t.; Stofdorpel: n.v.t.; Vensterbank: n.v.t.; Ventilatierooster: n.v.t.; Spouwlat: n.v.t.; Rollaag / Latei: n.v.t.; Afwerking dagkant buiten: n.v.t.; Afwerking dagkant binnen: n.v.t.; Zonwering - behuizing: n.v.t.; Zonwering - isolatie: n.v.t.; Glas: Glas - algemeen
CPset_Phasing - Renovation Phase: Bestaand
Name | OverallHeight (mm) | OverallWidth (mm) = Width (mm) | Classification | IsExternal | FireResistanceRating | Height (mm) | Perimeter (mm) | Area (m2) | Volume (m3) = NetVolume (m3) = Component, Component Volume (Net) (m3) = Component, Component Volume (Gross) (m3) | Depth (mm) | GlazingAreaFraction
2 x 32_05.07 | 2600 | 1700 | Deur (ARCHICAD Classification); 32.31 draaideuren (NL/SfB (4 cijfers)) | no | --- | 2600 | 8600 | 4.42 | 0.209779 | 125
3 x 31_merk-AV | 2620 | 2090 | Deur (ARCHICAD Classification); 31.31 draaideuren (NL/SfB (4 cijfers)) | yes | --- | 2570 | 9320 | 5.3713 | 0.127243 |  | 3.57433
32_05.08 | 2600 | 1244 | Deur (ARCHICAD Classification); 32.31 draaideuren (NL/SfB (4 cijfers)) | no | --- | 2670 | 7828 | 3.32148 | 0.159883 | 210
31_merk-AU | 2640 | 2120 | Deur (ARCHICAD Classification); 31.31 draaideuren (NL/SfB (4 cijfers)) | yes | --- | 2600 | 9440 | 5.512 | 0.12973 |  | 3.67516
32_05.02 | 2600 | 2120 | Deur (ARCHICAD Classification); 32.31 draaideuren (NL/SfB (4 cijfers)) | no | --- | 2600 | 9440 | 5.512 | 0.205465 | 125 | 2.7186
2 x 32_05.06 | 2475 | 1544 | Deur (ARCHICAD Classification); 32.31 draaideuren (NL/SfB (4 cijfers)) | no | --- | 2475 | 8038 | 3.8214 | 0.183857 | 125
32_05.03 | 2600 | 2212.5 | Deur (ARCHICAD Classification); 32.31 draaideuren (NL/SfB (4 cijfers)) | no | 30 minuten brandwerend en zelfsluitend | 2670 | 9765 | 5.90738 | 0.17056 | 210 | 3.03739

# IfcDoor: D2 25 (3)
In: begane grond
Type - OperationType: DOUBLE_DOOR_SINGLE_SWING_OPPOSITE_RIGHT; ParameterTakesPrecedence: no; Sizeable: no
OverallHeight: 2600 mm; OverallWidth: 2100 mm; Classification: Deur (ARCHICAD Classification); 32.31 draaideuren (NL/SfB (4 cijfers))
Pset_DoorCommon - ThermalTransmittance: 0; GlazingAreaFraction: 2.6792; IsExternal: no
Material - Frame / Draaiend deel: n.v.t.; Deurblad: n.v.t.; Onderdorpel: n.v.t.; Stofdorpel: n.v.t.; Vensterbank: n.v.t.; Ventilatierooster: n.v.t.; Spouwlat: n.v.t.; Rollaag / Latei: n.v.t.; Afwerking dagkant buiten: n.v.t.; Afwerking dagkant binnen: n.v.t.; Zonwering - behuizing: n.v.t.; Zonwering - isolatie: n.v.t.; Glas: Glas - algemeen
Pset_FireRatingProperties - FireResistanceRating: ---
CPset_Phasing - Renovation Phase: Bestaand
BaseQuantities - Height: 2600 mm; Width: 2100 mm; Perimeter: 9400 mm; Area: 5.46 m2; Volume: 0.204631 m3; Depth: 125 mm; NetVolume: 0.204631 m3
Component Quantities - Component, Component Volume (Net): 0.204631 m3; Component, Component Volume (Gross): 0.204631 m3

# IfcDoor: D2 bl 25, 32_merk-BL2
In: verdieping
Type - OperationType: DOUBLE_DOOR_SINGLE_SWING; ParameterTakesPrecedence: no; Sizeable: no
OverallHeight: 3547 mm; OverallWidth: 2300 mm; Classification: Deur (ARCHICAD Classification); 32.31 draaideuren (NL/SfB (4 cijfers))
Pset_DoorCommon - ThermalTransmittance: 0; GlazingAreaFraction: 6.24752; IsExternal: no
Material - Frame / Draaiend deel: n.v.t.; Deurblad: n.v.t.; Onderdorpel: n.v.t.; Stofdorpel: n.v.t.; Vensterbank: n.v.t.; Ventilatierooster: n.v.t.; Spouwlat: n.v.t.; Rollaag / Latei: n.v.t.; Afwerking dagkant buiten: n.v.t.; Afwerking dagkant binnen: n.v.t.; Zonwering - behuizing: n.v.t.; Zonwering - isolatie: n.v.t.; Glas: Glas - algemeen
Pset_FireRatingProperties - FireResistanceRating: ---
CPset_Phasing - Renovation Phase: Bestaand
BaseQuantities - Height: 3547 mm; Width: 2307.5 mm; Perimeter: 11709 mm; Area: 8.1847 m2; Volume: 0.0967309 m3; NetVolume: 0.0967309 m3
Component Quantities - Component, Component Volume (Net): 0.0967309 m3; Component, Component Volume (Gross): 0.0967309 m3

# IfcDoor: D2 zl2 25 (2)
In: begane grond
Type - OperationType: USERDEFINED; ParameterTakesPrecedence: no; Sizeable: no
OverallHeight: 2600 mm; OverallWidth: 4155.5 mm; Classification: Deur (ARCHICAD Classification); 32.31 draaideuren (NL/SfB (4 cijfers))
Pset_DoorCommon - ThermalTransmittance: 0; GlazingAreaFraction: 6.92031; IsExternal: no
Material - Frame / Draaiend deel: n.v.t.; Deurblad: n.v.t.; Onderdorpel: n.v.t.; Stofdorpel: n.v.t.; Vensterbank: n.v.t.; Ventilatierooster: n.v.t.; Spouwlat: n.v.t.; Rollaag / Latei: n.v.t.; Afwerking dagkant buiten: n.v.t.; Afwerking dagkant binnen: n.v.t.; Zonwering - behuizing: n.v.t.; Zonwering - isolatie: n.v.t.; Glas: Glas - algemeen
Pset_FireRatingProperties - FireResistanceRating: 30 minuten brandwerend en zelfsluitend
CPset_Phasing - Renovation Phase: Bestaand
BaseQuantities - Height: 2600 mm; Width: 4155.5 mm; Perimeter: 13511 mm; Area: 10.8043 m2; Volume: 0.361777 m3; Depth: 125 mm; NetVolume: 0.361777 m3
Component Quantities - Component, Component Volume (Net): 0.361777 m3; Component, Component Volume (Gross): 0.361777 m3
Name
32_05.05
32_05.04

# IfcDoor: DS1 voor wand 25 (34)
Type - OperationType: SLIDING_TO_LEFT; ParameterTakesPrecedence: no; Sizeable: no
OverallHeight: 2590 mm; Classification: Deur (ARCHICAD Classification); 32.32 schuifdeuren (NL/SfB (4 cijfers))
Pset_DoorCommon - ThermalTransmittance: 0; IsExternal: yes
Material - Frame / Draaiend deel: n.v.t.; Deurblad: n.v.t.; Onderdorpel: n.v.t.; Stofdorpel: n.v.t.; Vensterbank: n.v.t.; Spouwlat: n.v.t.; Rollaag / Latei: n.v.t.; Afwerking dagkant buiten: n.v.t.; Afwerking dagkant binnen: n.v.t.; Zonwering - behuizing: n.v.t.; Zonwering - isolatie: n.v.t.; Glas: Glas - algemeen
CPset_Phasing - Renovation Phase: Bestaand
BaseQuantities - Height: 2600 mm; Depth: 1 mm
Name | In | OverallWidth (mm) = Width (mm) | Perimeter (mm) | Area (m2) | Volume (m3) = NetVolume (m3) = Component, Component Volume (Net) (m3) = Component, Component Volume (Gross) (m3)
4 x 32_01. | begane grond | 1750 | 8700 | 4.55 | 0.1813
3 x 32_01. | begane grond | 1320 | 7840 | 3.432 | 0.136752
11 x 32_01. | begane grond | 1450 | 8100 | 3.77 | 0.15022
32_01. | begane grond | 1389 | 7977.99 | 3.61139 | 0.1439
12 x 32_01. | verdieping | 1450 | 8100 | 3.77 | 0.15022
3 x 32_01. | verdieping | 1320 | 7840 | 3.432 | 0.136752

# IfcDoor: DS1 voor wand 25 (30)
Type - OperationType: SLIDING_TO_RIGHT; ParameterTakesPrecedence: no; Sizeable: no
OverallHeight: 2590 mm; Classification: Deur (ARCHICAD Classification); 32.32 schuifdeuren (NL/SfB (4 cijfers))
Pset_DoorCommon - ThermalTransmittance: 0; IsExternal: yes
Material - Frame / Draaiend deel: n.v.t.; Deurblad: n.v.t.; Onderdorpel: n.v.t.; Stofdorpel: n.v.t.; Vensterbank: n.v.t.; Spouwlat: n.v.t.; Rollaag / Latei: n.v.t.; Afwerking dagkant buiten: n.v.t.; Afwerking dagkant binnen: n.v.t.; Zonwering - behuizing: n.v.t.; Zonwering - isolatie: n.v.t.; Glas: Glas - algemeen
CPset_Phasing - Renovation Phase: Bestaand
BaseQuantities - Height: 2600 mm; Depth: 1 mm
Name | In | OverallWidth (mm) = Width (mm) | Perimeter (mm) | Area (m2) | Volume (m3) = NetVolume (m3) = Component, Component Volume (Net) (m3) = Component, Component Volume (Gross) (m3)
4 x 32_01. | begane grond | 1000 | 7200 | 2.6 | 0.1036
4 x 32_01. | begane grond | 900 | 7000 | 2.34 | 0.09324
8 x 32_01. | begane grond | 1450 | 8100 | 3.77 | 0.15022
3 x 32_01. | begane grond | 1320 | 7840 | 3.432 | 0.136752
3 x 32_01. | verdieping | 1320 | 7840 | 3.432 | 0.136752
8 x 32_01. | verdieping | 1450 | 8100 | 3.77 | 0.15022

# IfcDoor: DV1 25, 32_08.01
In: begane grond
Type - OperationType: FOLDING_TO_LEFT; ParameterTakesPrecedence: no; Sizeable: no
OverallHeight: 2990 mm; OverallWidth: 7000 mm; Classification: Deur (ARCHICAD Classification); 32.31 draaideuren (NL/SfB (4 cijfers))
Pset_DoorCommon - ThermalTransmittance: 0; GlazingAreaFraction: 10.994; IsExternal: no
Material - Frame / Draaiend deel: n.v.t.; Deurblad: n.v.t.; Onderdorpel: n.v.t.; Stofdorpel: n.v.t.; Vensterbank: n.v.t.; Ventilatierooster: n.v.t.; Spouwlat: n.v.t.; Rollaag / Latei: n.v.t.; Afwerking dagkant buiten: n.v.t.; Afwerking dagkant binnen: n.v.t.; Zonwering - behuizing: n.v.t.; Zonwering - isolatie: n.v.t.; Glas: Glas - algemeen
Pset_FireRatingProperties - FireResistanceRating: ---
CPset_Phasing - Renovation Phase: Bestaand
BaseQuantities - Height: 2990 mm; Width: 7000 mm; Perimeter: 19980 mm; Area: 20.93 m2; Volume: 1.04328 m3; Depth: 105 mm; NetVolume: 1.04328 m3
Component Quantities - Component, Component Volume (Net): 1.04328 m3; Component, Component Volume (Gross): 1.04328 m3

# IfcEnergyConversionDevice: Zonnepaneel 25 (334)
In: techniek
Type - ElementType: SOLARPANEL; PredefinedType: USERDEFINED
Classification: Zonnepaneel (ARCHICAD Classification); 61.15 Photo Voltaic (PV) panelen (NL/SfB (4 cijfers))
CPset_Phasing - Renovation Phase: Bestaand
Component Quantities - Component, Component Volume (Net): 0.0550868 m3; Component, Component Volume (Gross): 0.0550868 m3

# IfcFlowTerminal: Droger 25, 53_kopieerapparaat
In: begane grond
Type - PredefinedType: SINK
Classification: Gootsteen (ARCHICAD Classification); 53.21 met voorraad (NL/SfB (4 cijfers))
CPset_Phasing - Renovation Phase: Bestaand
Component Quantities - Component, Component Volume (Net): 0.0187356 m3; Component, Component Volume (Gross): 0.0187356 m3

# IfcFlowTerminal: Gootsteen 01 25 (20)
Type - PredefinedType: SINK
Classification: Gootsteen (ARCHICAD Classification); 53.21 met voorraad (NL/SfB (4 cijfers))
CPset_Phasing - Renovation Phase: Bestaand
Component Quantities - Component, Component Volume (Net): 0.000318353 m3; Component, Component Volume (Gross): 0.000318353 m3
Name | In
10 x 53_83 pantryblok | begane grond
53_81 pantryblok | begane grond
8 x 53_83 pantryblok | verdieping
53_81 pantryblok | verdieping

# IfcFlowTerminal: Gootsteen 02 25 (2)
Type - PredefinedType: SINK
Classification: Gootsteen (ARCHICAD Classification); 52.30 algemeen (verzamelniveau) (NL/SfB (4 cijfers))
CPset_Phasing - Renovation Phase: Bestaand
Component Quantities - Component, Component Volume (Net): 0.0287816 m3; Component, Component Volume (Gross): 0.0287816 m3
Name | In
52_Sanitair uitstortgootsteen | begane grond
52_Sanitair uitstortgootsteen | verdieping

# IfcFlowTerminal: Inbouwreservoir 25 KM (28)
Type - PredefinedType: CISTERN
Classification: Spoelreservoir (ARCHICAD Classification); 53.0 algemeen (NL/SfB (4 cijfers))
CPset_Phasing - Renovation Phase: Bestaand
Component Quantities - Component, Component Volume (Net): 0.06835 m3; Component, Component Volume (Gross): 0.06835 m3
Name | In
15 x 53_Sanitair-inbouw DuoFix | begane grond
13 x 53_Sanitair-inbouw DuoFix | verdieping

# IfcFlowTerminal: Invalidentoilet 25 (3)
Type - PredefinedType: TOILETPAN
Classification: Toiletpot (ARCHICAD Classification); 52.20 algemeen (verzamelniveau) (NL/SfB (4 cijfers))
CPset_Phasing - Renovation Phase: Bestaand
Component Quantities - Component, Component Volume (Net): 0.0150151 m3; Component, Component Volume (Gross): 0.0150151 m3
Name | In
2 x 52_Sanitair-toiletpot | begane grond
52_Sanitair-toiletpot | verdieping

# IfcFlowTerminal: Luchtverdeler 01 25 (153)
Type - PredefinedType: GRILLE
Classification: Rooster (ARCHICAD Classification); 57.20 algemeen (verzamelniveau) (NL/SfB (4 cijfers))
CPset_Phasing - Renovation Phase: Bestaand
Component Quantities - Component, Component Volume (Net): 0.000823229 m3; Component, Component Volume (Gross): 0.000823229 m3
Name | In
83 x 57_77 garderobe | begane grond
70 x 57_77 garderobe | verdieping

# IfcFlowTerminal: Rooster plafond rond 25 (36)
Type - PredefinedType: GRILLE
Classification: Rooster (ARCHICAD Classification); 57.20 algemeen (verzamelniveau) (NL/SfB (4 cijfers))
CPset_Phasing - Renovation Phase: Bestaand
Component Quantities - Component, Component Volume (Net): 0.0000298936 m3; Component, Component Volume (Gross): 0.0000298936 m3
Name | In
21 x 57_78 garderobe | begane grond
15 x 57_78 garderobe | verdieping

# IfcFlowTerminal: Spot plafond 01 25 (195)
Classification: Verlichting - lamp (ARCHICAD Classification); 63.20 algemeen (verzamelniveau) (NL/SfB (4 cijfers))
CPset_Phasing - Renovation Phase: Bestaand
Component Quantities - Component, Component Volume (Net): 0.0000275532 m3; Component, Component Volume (Gross): 0.0000275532 m3
Name | In
99 x 63_Lamp-x | begane grond
96 x 63_Lamp-x | verdieping

# IfcFlowTerminal: TL plafond 25 (260)
Classification: Verlichting - lamp (ARCHICAD Classification); 63.20 algemeen (verzamelniveau) (NL/SfB (4 cijfers))
CPset_Phasing - Renovation Phase: Bestaand
Component Quantities - Component, Component Volume (Net): 0.0134596 m3; Component, Component Volume (Gross): 0.0134596 m3
Name | In
145 x 63_Lamp-x | begane grond
115 x 63_Lamp-x | verdieping

# IfcFlowTerminal: Toilet 25 (25)
Type - PredefinedType: TOILETPAN
Classification: Toiletpot (ARCHICAD Classification); 74.11 sanitaire toestellen; normaal (NL/SfB (4 cijfers))
CPset_Phasing - Renovation Phase: Bestaand
Component Quantities - Component, Component Volume (Net): 0.0135775 m3; Component, Component Volume (Gross): 0.0135775 m3
Name | In
13 x 74_Sanitair-toiletpot | begane grond
12 x 74_Sanitair-toiletpot | verdieping

# IfcFlowTerminal: Wasbak 25 (7)
Type - PredefinedType: SANITARYFOUNTAIN
Classification: Fontein (ARCHICAD Classification); 52.0 algemeen (NL/SfB (4 cijfers))
CPset_Phasing - Renovation Phase: Bestaand
Name | In | Component, Component Volume (Net) (m3) = Component, Component Volume (Gross) (m3)
2 x 52_Sanitair wastafel | begane grond | 0.01476
2 x 52_Sanitair wastafel | begane grond | 0.0130746
52_Sanitair wastafel | verdieping | 0.00896075
2 x 52_Sanitair wastafel | verdieping | 0.01476

# IfcFlowTerminal: Wasbak 25 (9)
Type - PredefinedType: WASHHANDBASIN
Classification: 52.30 algemeen (verzamelniveau) (NL/SfB (4 cijfers)); Wasbak (ARCHICAD Classification)
CPset_Phasing - Renovation Phase: Bestaand
Name | In | Component, Component Volume (Net) (m3) = Component, Component Volume (Gross) (m3)
2 x 52_Sanitair wastafel | begane grond | 0.000197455
2 x 52_Sanitair wastafel | begane grond | 0.0282176
52_Sanitair wastafel | begane grond | 0.0260207
3 x 52_Sanitair wastafel | verdieping | 0.0282176
52_Sanitair wastafel | verdieping | 0.000197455

# IfcFlowTerminal: Wasmachine 25, 53_kopieerapparaat
In: begane grond
Type - PredefinedType: SINK
Classification: Gootsteen (ARCHICAD Classification); 53.21 met voorraad (NL/SfB (4 cijfers))
CPset_Phasing - Renovation Phase: Bestaand
Component Quantities - Component, Component Volume (Net): 0.0504689 m3; Component, Component Volume (Gross): 0.0504689 m3

# IfcFurnishingElement: 23 kanaaplaat VBI Rc 3,7 132mm excl. afwerklaag 440 (2)
In: fundering
Type - ElementType: SHELF
Classification: Legplank (ARCHICAD Classification); 72.1 standaard (NL/SfB (4 cijfers))
CPset_Phasing - Renovation Phase: Bestaand

# IfcFurnishingElement: 24 Hout gevelbekleding Lariks master 1820 (2)
In: verdieping
Type - ElementType: SHELF
Classification: Legplank (ARCHICAD Classification); 72.1 standaard (NL/SfB (4 cijfers)); Material: 24 Hout gevelbekleding Lariks master
CPset_Phasing - Renovation Phase: Bestaand
Component Quantities - 24 Hout gevelbekleding Lariks master, Component Thickness: 1820 mm
Name | 24 Hout gevelbekleding Lariks master, Mass (kg) | 24 Hout gevelbekleding Lariks master, Projected Component Area (Net) (m2) = 24 Hout gevelbekleding Lariks master, Projected Component Area (Gross) (m2) | 24 Hout gevelbekleding Lariks master, Component Volume (Net) (m3) = 24 Hout gevelbekleding Lariks master, Component Volume (Gross) (m3)
72_74 vaste inrichting | 45.9287 | 0.038825 | 0.0706595
72_74 vaste inrichting | 46.668 | 0.03945 | 0.071797

# IfcFurnishingElement: 24 Hout gevelbekleding Lariks master 1864 (4)
In: verdieping
Type - ElementType: SHELF
Classification: Legplank (ARCHICAD Classification); 72.1 standaard (NL/SfB (4 cijfers)); Material: 24 Hout gevelbekleding Lariks master
CPset_Phasing - Renovation Phase: Bestaand
Component Quantities - 24 Hout gevelbekleding Lariks master, Component Thickness: 1863.73 mm
Name | 24 Hout gevelbekleding Lariks master, Mass (kg) | 24 Hout gevelbekleding Lariks master, Projected Component Area (Net) (m2) = 24 Hout gevelbekleding Lariks master, Projected Component Area (Gross) (m2) | 24 Hout gevelbekleding Lariks master, Component Volume (Net) (m3) = 24 Hout gevelbekleding Lariks master, Component Volume (Gross) (m3)
3 x 72_74 vaste inrichting | 56.1192 | 0.046325 | 0.0863372
72_74 vaste inrichting | 154.078 | 0.127187 | 0.237043

# IfcFurnishingElement: 24 Hout gevelbekleding Lariks master 2880, 72_74 vaste inrichting
In: verdieping
Type - ElementType: SHELF
Classification: Legplank (ARCHICAD Classification); 72.1 standaard (NL/SfB (4 cijfers)); Material: 24 Hout gevelbekleding Lariks master
CPset_Phasing - Renovation Phase: Bestaand
Component Quantities - 24 Hout gevelbekleding Lariks master, Mass: 145.706 kg; 24 Hout gevelbekleding Lariks master, Projected Component Area (Net): 0.0778347 m2; 24 Hout gevelbekleding Lariks master, Projected Component Area (Gross): 0.0778347 m2; 24 Hout gevelbekleding Lariks master, Component Thickness: 2880 mm; 24 Hout gevelbekleding Lariks master, Component Volume (Net): 0.224162 m3; 24 Hout gevelbekleding Lariks master, Component Volume (Gross): 0.224162 m3

# IfcFurnishingElement: 24 Hout gevelbekleding Lariks master 3200, 72_74 vaste inrichting
In: begane grond
Type - ElementType: SHELF
Classification: Legplank (ARCHICAD Classification); 72.1 standaard (NL/SfB (4 cijfers)); Material: 24 Hout gevelbekleding Lariks master
CPset_Phasing - Renovation Phase: Bestaand
Component Quantities - 24 Hout gevelbekleding Lariks master, Mass: 1.2896 kg; 24 Hout gevelbekleding Lariks master, Projected Component Area (Net): 0.000620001 m2; 24 Hout gevelbekleding Lariks master, Projected Component Area (Gross): 0.000620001 m2; 24 Hout gevelbekleding Lariks master, Component Thickness: 3200 mm; 24 Hout gevelbekleding Lariks master, Component Volume (Net): 0.001984 m3; 24 Hout gevelbekleding Lariks master, Component Volume (Gross): 0.001984 m3

# IfcFurnishingElement: 24 Hout gevelbekleding Lariks master 3280 (4)
In: begane grond
Type - ElementType: SHELF
Classification: Legplank (ARCHICAD Classification); 72.1 standaard (NL/SfB (4 cijfers)); Material: 24 Hout gevelbekleding Lariks master
CPset_Phasing - Renovation Phase: Bestaand
Component Quantities - 24 Hout gevelbekleding Lariks master, Mass: 6.02257 kg; 24 Hout gevelbekleding Lariks master, Projected Component Area (Net): 0.002825 m2; 24 Hout gevelbekleding Lariks master, Projected Component Area (Gross): 0.002825 m2; 24 Hout gevelbekleding Lariks master, Component Thickness: 3279.82 mm; 24 Hout gevelbekleding Lariks master, Component Volume (Net): 0.0092655 m3; 24 Hout gevelbekleding Lariks master, Component Volume (Gross): 0.0092655 m3

# IfcFurnishingElement: 24 Hout gevelbekleding Lariks master 3400, 72_74 vaste inrichting
In: begane grond
Type - ElementType: SHELF
Classification: Legplank (ARCHICAD Classification); 72.1 standaard (NL/SfB (4 cijfers)); Material: 24 Hout gevelbekleding Lariks master
CPset_Phasing - Renovation Phase: Bestaand
Component Quantities - 24 Hout gevelbekleding Lariks master, Mass: 6.24326 kg; 24 Hout gevelbekleding Lariks master, Projected Component Area (Net): 0.002825 m2; 24 Hout gevelbekleding Lariks master, Projected Component Area (Gross): 0.002825 m2; 24 Hout gevelbekleding Lariks master, Component Thickness: 3400 mm; 24 Hout gevelbekleding Lariks master, Component Volume (Net): 0.00960501 m3; 24 Hout gevelbekleding Lariks master, Component Volume (Gross): 0.00960501 m3

# IfcFurnishingElement: 24 Hout gevelbekleding Lariks master 3470, 72_74 vaste inrichting
In: verdieping
Type - ElementType: SHELF
Classification: Legplank (ARCHICAD Classification); 72.1 standaard (NL/SfB (4 cijfers)); Material: 24 Hout gevelbekleding Lariks master
CPset_Phasing - Renovation Phase: Bestaand
Component Quantities - 24 Hout gevelbekleding Lariks master, Mass: 178.523 kg; 24 Hout gevelbekleding Lariks master, Projected Component Area (Net): 0.07915 m2; 24 Hout gevelbekleding Lariks master, Projected Component Area (Gross): 0.07915 m2; 24 Hout gevelbekleding Lariks master, Component Thickness: 3470 mm; 24 Hout gevelbekleding Lariks master, Component Volume (Net): 0.27465 m3; 24 Hout gevelbekleding Lariks master, Component Volume (Gross): 0.27465 m3

# IfcFurnishingElement: 24 Hout gevelbekleding Lariks master 4980, 72_74 vaste inrichting
In: begane grond
Type - ElementType: SHELF
Classification: Legplank (ARCHICAD Classification); 72.1 standaard (NL/SfB (4 cijfers)); Material: 24 Hout gevelbekleding Lariks master
CPset_Phasing - Renovation Phase: Bestaand
Component Quantities - 24 Hout gevelbekleding Lariks master, Mass: 1.76093 kg; 24 Hout gevelbekleding Lariks master, Projected Component Area (Net): 0.000544 m2; 24 Hout gevelbekleding Lariks master, Projected Component Area (Gross): 0.000544 m2; 24 Hout gevelbekleding Lariks master, Component Thickness: 4980 mm; 24 Hout gevelbekleding Lariks master, Component Volume (Net): 0.00270912 m3; 24 Hout gevelbekleding Lariks master, Component Volume (Gross): 0.00270912 m3

# IfcFurnishingElement: 42 vensterbank 15, 72_73 vaste inrichting
In: verdieping
Type - ElementType: SHELF
Classification: Legplank (ARCHICAD Classification); 72.1 standaard (NL/SfB (4 cijfers)); Material: 42 vensterbank
CPset_Phasing - Renovation Phase: Bestaand
Component Quantities - 42 vensterbank, Mass: 115.628 kg; 42 vensterbank, Projected Component Area (Net): 4.81784 m2; 42 vensterbank, Projected Component Area (Gross): 4.81784 m2; 42 vensterbank, Component Thickness: 15 mm; 42 vensterbank, Component Volume (Net): 0.0722676 m3; 42 vensterbank, Component Volume (Gross): 0.0722676 m3

# IfcFurnishingElement: 42 vensterbank 20 (11)
In: begane grond
Type - ElementType: SHELF
Classification: Legplank (ARCHICAD Classification); 72.1 standaard (NL/SfB (4 cijfers)); Material: 42 vensterbank
CPset_Phasing - Renovation Phase: Bestaand
Component Quantities - 42 vensterbank, Component Thickness: 20 mm
Name | 42 vensterbank, Mass (kg) | 42 vensterbank, Projected Component Area (Net) (m2) = 42 vensterbank, Projected Component Area (Gross) (m2) | 42 vensterbank, Component Volume (Net) (m3) = 42 vensterbank, Component Volume (Gross) (m3)
72_73 vaste inrichting | 23.5824 | 0.73695 | 0.014739
72_73 vaste inrichting | 12.96 | 0.405 | 0.00809999
72_73 vaste inrichting | 21.36 | 0.6675 | 0.01335
72_73 vaste inrichting | 12.9602 | 0.405007 | 0.00810015
72_73 vaste inrichting | 23.76 | 0.7425 | 0.01485
3 x 72_73 vaste inrichting | 21.2304 | 0.66345 | 0.013269
2 x 72_73 vaste inrichting | 24.72 | 0.7725 | 0.01545
72_73 vaste inrichting | 25.812 | 0.806625 | 0.0161325

# IfcFurnishingElement: 43 Fresco Moonstone 3883 2 (10)
Type - ElementType: SHELF
Classification: Legplank (ARCHICAD Classification); 72.1 standaard (NL/SfB (4 cijfers)); Material: 43 Fresco Moonstone 3883
CPset_Phasing - Renovation Phase: Bestaand
Component Quantities - 43 Fresco Moonstone 3883, Component Thickness: 2 mm
Name | In | 43 Fresco Moonstone 3883, Mass (kg) | 43 Fresco Moonstone 3883, Projected Component Area (Net) (m2) | 43 Fresco Moonstone 3883, Projected Component Area (Gross) (m2) | 43 Fresco Moonstone 3883, Component Volume (Net) (m3) | 43 Fresco Moonstone 3883, Component Volume (Gross) (m3)
72_43 marmoleum | begane grond | 56.028 | 12.18 | 12.18 | 0.02436 | 0.02436
72_43 marmoleum | begane grond | 72.5688 | 15.7758 | 15.7758 | 0.0315517 | 0.0315517
72_76 vaste inrichting | begane grond | 71.8133 | 15.6116 | 15.6116 | 0.0312232 | 0.0312232
72_43 marmoleum | begane grond | 8.94884 | 1.9454 | 1.9454 | 0.0038908 | 0.0038908
72_43 marmoleum | begane grond | 394.526 | 85.7666 | 85.7666 | 0.171533 | 0.171533
72_43 marmoleum | begane grond | 621.875 | 135.19 | 137.17 | 0.270381 | 0.274341
72_43 marmoleum | begane grond | 28.773 | 6.255 | 6.255 | 0.01251 | 0.01251
72_43 marmoleum | verdieping | 280.357 | 60.9473 | 60.9473 | 0.121895 | 0.121895
72_43 marmoleum | verdieping | 68.816 | 14.96 | 14.96 | 0.02992 | 0.02992
72_43 marmoleum | verdieping | 738.302 | 160.5 | 160.5 | 0.321001 | 0.321001

# IfcFurnishingElement: 43 fresco Arabian pearl 3861 2 (6)
Type - ElementType: SHELF
Classification: Legplank (ARCHICAD Classification); 72.1 standaard (NL/SfB (4 cijfers)); Material: 43 fresco Arabian pearl 3861
CPset_Phasing - Renovation Phase: Bestaand
Component Quantities - 43 fresco Arabian pearl 3861, Component Thickness: 2 mm
Name | In | 43 fresco Arabian pearl 3861, Mass (kg) | 43 fresco Arabian pearl 3861, Projected Component Area (Net) (m2) = 43 fresco Arabian pearl 3861, Projected Component Area (Gross) (m2) | 43 fresco Arabian pearl 3861, Component Volume (Net) (m3) = 43 fresco Arabian pearl 3861, Component Volume (Gross) (m3)
72_43 marmoleum | begane grond | 155.762 | 33.8614 | 0.0677228
72_76 vaste inrichting | begane grond | 81.5455 | 17.7273 | 0.0354546
72_76 vaste inrichting | begane grond | 80.9883 | 17.6062 | 0.0352123
72_43 marmoleum | begane grond | 8.08082 | 1.7567 | 0.0035134
72_43 marmoleum | verdieping | 114.159 | 24.8173 | 0.0496345
72_43 marmoleum | verdieping | 102.873 | 22.3636 | 0.0447272

# IfcFurnishingElement: 43 fresco Barbados 3858 2 (19)
Type - ElementType: SHELF
Classification: Legplank (ARCHICAD Classification); 72.1 standaard (NL/SfB (4 cijfers)); Material: 43 fresco Barbados 3858
CPset_Phasing - Renovation Phase: Bestaand
Component Quantities - 43 fresco Barbados 3858, Component Thickness: 2 mm
Name | In | 43 fresco Barbados 3858, Mass (kg) | 43 fresco Barbados 3858, Projected Component Area (Net) (m2) = 43 fresco Barbados 3858, Projected Component Area (Gross) (m2) | 43 fresco Barbados 3858, Component Volume (Net) (m3) = 43 fresco Barbados 3858, Component Volume (Gross) (m3)
72_43 marmoleum | begane grond | 780.403 | 169.653 | 0.339306
72_43 marmoleum | begane grond | 173.37 | 37.6892 | 0.0753783
72_43 marmoleum | begane grond | 795.387 | 172.91 | 0.34582
72_43 marmoleum | begane grond | 198.747 | 43.2059 | 0.0864118
72_43 marmoleum | begane grond | 290.816 | 63.2208 | 0.126442
72_43 marmoleum | begane grond | 281.402 | 61.1745 | 0.122349
72_43 marmoleum | begane grond | 750.73 | 163.202 | 0.326405
72_43 marmoleum | begane grond | 508.22 | 110.483 | 0.220965
72_43 marmoleum | begane grond | 471.193 | 102.433 | 0.204867
3 x 72_43 marmoleum | begane grond | 3.036 | 0.66 | 0.00132
2 x 72_44 marmoleum | begane grond | 3.036 | 0.66 | 0.00132
72_43 marmoleum | verdieping | 499.112 | 108.503 | 0.217005
72_43 marmoleum | verdieping | 748.181 | 162.648 | 0.325296
72_43 marmoleum | verdieping | 256.634 | 55.79 | 0.11158
72_43 marmoleum | verdieping | 1138.63 | 247.529 | 0.495058
72_43 marmoleum | verdieping | 894.331 | 194.42 | 0.38884

# IfcFurnishingElement: 44 koof plaf 50 (87)
Type - ElementType: SHELF
Classification: Legplank (ARCHICAD Classification); 72.1 standaard (NL/SfB (4 cijfers)); Material: ALG - LICHTE SCHEIDINGSWAND
CPset_Phasing - Renovation Phase: Bestaand
Component Quantities - ALG - LICHTE SCHEIDINGSWAND, Component Thickness: 12 mm
Name | In | ALG - LICHTE SCHEIDINGSWAND, Mass (kg) | ALG - LICHTE SCHEIDINGSWAND, Projected Component Area (Net) (m2) | ALG - LICHTE SCHEIDINGSWAND, Projected Component Area (Gross) (m2) | ALG - LICHTE SCHEIDINGSWAND, Component Volume (Net) (m3) | ALG - LICHTE SCHEIDINGSWAND, Component Volume (Gross) (m3)
72_75 vaste inrichting | begane grond | 31.809 | 3.31344 | 3.31344 | 0.0397613 | 0.0397613
72_75 vaste inrichting | begane grond | 5.8776 | 0.61225 | 0.61225 | 0.007347 | 0.007347
72_75 vaste inrichting | begane grond | 438.704 | 45.6983 | 45.6983 | 0.54838 | 0.54838
4 x 72_75 vaste inrichting | begane grond | 40.896 | 4.26 | 4.26 | 0.05112 | 0.05112
72_75 vaste inrichting | begane grond | 39.5827 | 4.1232 | 8.4432 | 0.0494784 | 0.101318
72_75 vaste inrichting | begane grond | 6.048 | 0.63 | 0.63 | 0.00756 | 0.00756
72_75 vaste inrichting | begane grond | 18.2016 | 1.896 | 1.896 | 0.022752 | 0.022752
72_75 vaste inrichting | begane grond | 95.2981 | 9.92688 | 9.92688 | 0.119123 | 0.119123
72_75 vaste inrichting | begane grond | 87.1709 | 9.0803 | 9.0803 | 0.108964 | 0.108964
72_75 vaste inrichting | begane grond | 14.9728 | 1.55966 | 1.55966 | 0.0187159 | 0.0187159
72_75 vaste inrichting | begane grond | 87.8777 | 9.15392 | 9.15392 | 0.109847 | 0.109847
72_75 vaste inrichting | begane grond | 277.578 | 28.9143 | 39.7143 | 0.346972 | 0.476572
72_75 vaste inrichting | begane grond | 163.797 | 17.0622 | 17.0622 | 0.204747 | 0.204747
72_75 vaste inrichting | begane grond | 380.927 | 39.6799 | 41.8399 | 0.476159 | 0.502079
72_75 vaste inrichting | begane grond | 66.8993 | 6.96867 | 6.96867 | 0.0836241 | 0.0836241
72_75 vaste inrichting | begane grond | 4.83 | 0.503125 | 0.503125 | 0.0060375 | 0.0060375
72_75 vaste inrichting | begane grond | 98.115 | 10.2203 | 10.2203 | 0.122644 | 0.122644
72_75 vaste inrichting | begane grond | 32.4576 | 3.381 | 3.381 | 0.040572 | 0.040572
72_75 vaste inrichting | begane grond | 31.0098 | 3.23019 | 3.23019 | 0.0387623 | 0.0387623
72_75 vaste inrichting | begane grond | 17.712 | 1.845 | 3.285 | 0.02214 | 0.03942
72_75 vaste inrichting | begane grond | 2.16 | 0.225 | 0.225 | 0.0027 | 0.0027
72_75 vaste inrichting | begane grond | 6.624 | 0.69 | 0.69 | 0.00828 | 0.00828
2 x 72_75 vaste inrichting | begane grond | 13.4664 | 1.40275 | 1.40275 | 0.016833 | 0.016833
72_75 vaste inrichting | begane grond | 14.9728 | 1.55966 | 1.55966 | 0.018716 | 0.018716
72_75 vaste inrichting | begane grond | 47.1355 | 4.90995 | 4.90995 | 0.0589194 | 0.0589194
72_75 vaste inrichting | begane grond | 559.342 | 58.2648 | 58.2648 | 0.699178 | 0.699178
72_75 vaste inrichting | begane grond | 12.6 | 1.3125 | 1.3125 | 0.01575 | 0.01575
72_75 vaste inrichting | begane grond | 25.5355 | 2.65995 | 2.65995 | 0.0319194 | 0.0319194
72_76 vaste inrichting | begane grond | 25.5486 | 2.66131 | 2.66131 | 0.0319357 | 0.0319357
72_75 vaste inrichting | begane grond | 77.5037 | 8.0733 | 8.0733 | 0.0968796 | 0.0968796
72_75 vaste inrichting | begane grond | 40.4784 | 4.2165 | 4.2165 | 0.050598 | 0.050598
72_75 vaste inrichting | begane grond | 2.12633 | 0.221493 | 0.221493 | 0.00265792 | 0.00265792
72_75 vaste inrichting | begane grond | 289.354 | 30.5801 | 30.5801 | 0.361692 | 0.361692
2 x 72_75 vaste inrichting | begane grond | 24.888 | 2.5925 | 2.5925 | 0.03111 | 0.03111
72_75 vaste inrichting | begane grond | 4.85184 | 0.5054 | 0.5054 | 0.0060648 | 0.0060648
72_75 vaste inrichting | begane grond | 19.3962 | 2.02044 | 2.02044 | 0.0242453 | 0.0242453
72_75 vaste inrichting | begane grond | 12.3418 | 1.5575 | 1.5575 | 0.0154273 | 0.0154273
72_76 vaste inrichting | begane grond | 21.585 | 2.24844 | 2.24844 | 0.0269813 | 0.0269813
72_77 vaste inrichting | begane grond | 21.585 | 2.24844 | 2.24844 | 0.0269813 | 0.0269813
72_78 vaste inrichting | begane grond | 31.809 | 3.31344 | 3.31344 | 0.0397613 | 0.0397613
72_79 vaste inrichting | begane grond | 31.809 | 3.31344 | 3.31344 | 0.0397613 | 0.0397613
72_80 vaste inrichting | begane grond | 31.809 | 3.31344 | 3.31344 | 0.0397613 | 0.0397613
72_81 vaste inrichting | begane grond | 31.9104 | 3.324 | 3.324 | 0.039888 | 0.039888
2 x 72_75 vaste inrichting | verdieping | 21.585 | 2.24844 | 2.24844 | 0.0269813 | 0.0269813
72_75 vaste inrichting | verdieping | 33.7277 | 3.5133 | 3.5133 | 0.0421596 | 0.0421596
72_75 vaste inrichting | verdieping | 1205.43 | 125.565 | 125.565 | 1.50679 | 1.50679
72_75 vaste inrichting | verdieping | 17.6083 | 1.8342 | 3.2742 | 0.0220104 | 0.0392904
72_75 vaste inrichting | verdieping | 4.2336 | 0.441 | 0.441 | 0.005292 | 0.005292
72_75 vaste inrichting | verdieping | 53.6256 | 5.586 | 5.586 | 0.067032 | 0.067032
72_75 vaste inrichting | verdieping | 137.47 | 14.3204 | 34.0819 | 0.171837 | 0.408974
72_75 vaste inrichting | verdieping | 3.4272 | 0.357 | 0.357 | 0.004284 | 0.004284
72_75 vaste inrichting | verdieping | 3.41568 | 0.3558 | 0.3558 | 0.0042696 | 0.0042696
72_75 vaste inrichting | verdieping | 143.616 | 14.96 | 14.96 | 0.17952 | 0.17952
72_75 vaste inrichting | verdieping | 361.368 | 37.6425 | 37.6425 | 0.45171 | 0.45171
72_75 vaste inrichting | verdieping | 41.893 | 4.36385 | 4.36385 | 0.0523662 | 0.0523662
72_75 vaste inrichting | verdieping | 11.7698 | 1.22602 | 1.22602 | 0.0147123 | 0.0147123
72_75 vaste inrichting | verdieping | 11.7304 | 1.22191 | 1.22191 | 0.014663 | 0.014663
4 x 72_75 vaste inrichting | verdieping | 40.896 | 4.26 | 4.26 | 0.05112 | 0.05112
72_75 vaste inrichting | verdieping | 81.4712 | 8.48658 | 8.48658 | 0.101839 | 0.101839
72_75 vaste inrichting | verdieping | 77.5046 | 8.07339 | 8.07339 | 0.0968807 | 0.0968807
72_75 vaste inrichting | verdieping | 89.6821 | 9.34188 | 9.34188 | 0.112103 | 0.112103
72_75 vaste inrichting | verdieping | 40.4784 | 4.2165 | 4.2165 | 0.050598 | 0.050598
72_75 vaste inrichting | verdieping | 2.47913 | 0.258243 | 0.258243 | 0.00309892 | 0.00309892
72_75 vaste inrichting | verdieping | 11.3735 | 1.18474 | 1.18474 | 0.0142169 | 0.0142169
72_75 vaste inrichting | verdieping | 31.9111 | 3.32407 | 3.32407 | 0.0398889 | 0.0398889
4 x 72_75 vaste inrichting | verdieping | 31.809 | 3.31344 | 3.31344 | 0.0397613 | 0.0397613
7 x 72_75 vaste inrichting | verdieping | 1.728 | 0.18 | 0.18 | 0.00216 | 0.00216
72_75 vaste inrichting | verdieping | 21.6115 | 2.2512 | 2.2512 | 0.0270144 | 0.0270144
72_75 vaste inrichting | verdieping | 153.275 | 15.9661 | 15.9661 | 0.191594 | 0.191594

# IfcFurnishingElement: 48 plafond Sonar G 60, 72_75 vaste inrichting
In: begane grond
Type - ElementType: SHELF
Classification: Legplank (ARCHICAD Classification); 72.1 standaard (NL/SfB (4 cijfers)); Material: 48 plafond Sonar G
CPset_Phasing - Renovation Phase: Bestaand
Component Quantities - 48 plafond Sonar G, Mass: 777.6 kg; 48 plafond Sonar G, Projected Component Area (Net): 16.2 m2; 48 plafond Sonar G, Projected Component Area (Gross): 16.2 m2; 48 plafond Sonar G, Component Thickness: 60 mm; 48 plafond Sonar G, Component Volume (Net): 0.972 m3; 48 plafond Sonar G, Component Volume (Gross): 0.972 m3

# IfcFurnishingElement: 48 vloeivloer Bolidt 2 (23)
Type - ElementType: SHELF
Classification: Legplank (ARCHICAD Classification); 72.1 standaard (NL/SfB (4 cijfers)); Material: 48 vloeivloer Bolidt
CPset_Phasing - Renovation Phase: Bestaand
Component Quantities - 48 vloeivloer Bolidt, Component Thickness: 2 mm
Name | In | 48 vloeivloer Bolidt, Mass (kg) | 48 vloeivloer Bolidt, Projected Component Area (Net) (m2) = 48 vloeivloer Bolidt, Projected Component Area (Gross) (m2) | 48 vloeivloer Bolidt, Component Volume (Net) (m3) = 48 vloeivloer Bolidt, Component Volume (Gross) (m3)
72_44 vloeivloer | begane grond | 2.085 | 0.75 | 0.0015
2 x 72_43 vloeivloer | begane grond | 3.42635 | 1.2325 | 0.002465
72_43 vloeivloer | begane grond | 3.04827 | 1.0965 | 0.002193
72_43 vloeivloer | begane grond | 4.18946 | 1.507 | 0.003014
72_43 vloeivloer | begane grond | 12.2146 | 4.39375 | 0.0087875
72_43 vloeivloer | begane grond | 22.085 | 7.94425 | 0.0158885
72_43 vloeivloer | begane grond | 4.9034 | 1.76381 | 0.00352763
72_43 vloeivloer | begane grond | 9.71158 | 3.49338 | 0.00698675
72_43 vloeivloer | begane grond | 7.87463 | 2.8326 | 0.0056652
72_43 vloeivloer | begane grond | 12.1847 | 4.383 | 0.008766
72_43 vloeivloer | begane grond | 19.611 | 7.05432 | 0.0141086
72_43 vloeivloer | begane grond | 9.65668 | 3.47363 | 0.00694725
72_43 vloeivloer | begane grond | 25.1043 | 9.03032 | 0.0180606
72_43 vloeivloer | verdieping | 3.04827 | 1.0965 | 0.002193
72_43 vloeivloer | verdieping | 3.47222 | 1.249 | 0.002498
2 x 72_44 vloeivloer | verdieping | 4.59812 | 1.654 | 0.003308
72_43 vloeivloer | verdieping | 7.87463 | 2.8326 | 0.0056652
72_43 vloeivloer | verdieping | 12.1847 | 4.383 | 0.008766
72_44 vloeivloer | verdieping | 19.5962 | 7.049 | 0.014098
2 x 72_43 vloeivloer | verdieping | 19.611 | 7.05432 | 0.0141086

# IfcFurnishingElement: ALG - LICHTE SCHEIDINGSWAND 450, 72_72 vaste inrichting
In: begane grond
Type - ElementType: SHELF
Classification: Legplank (ARCHICAD Classification); 72.1 standaard (NL/SfB (4 cijfers)); Material: ALG - LICHTE SCHEIDINGSWAND
CPset_Phasing - Renovation Phase: Bestaand
Component Quantities - ALG - LICHTE SCHEIDINGSWAND, Mass: 395.64 kg; ALG - LICHTE SCHEIDINGSWAND, Projected Component Area (Net): 1.099 m2; ALG - LICHTE SCHEIDINGSWAND, Projected Component Area (Gross): 1.099 m2; ALG - LICHTE SCHEIDINGSWAND, Component Thickness: 450 mm; ALG - LICHTE SCHEIDINGSWAND, Component Volume (Net): 0.49455 m3; ALG - LICHTE SCHEIDINGSWAND, Component Volume (Gross): 0.49455 m3

# IfcFurnishingElement: ALG - TERREIN 1740, 72_75 vaste inrichting
In: fundering
Type - ElementType: SHELF
Classification: Legplank (ARCHICAD Classification); 72.1 standaard (NL/SfB (4 cijfers)); Material: ALG - TERREIN
CPset_Phasing - Renovation Phase: Bestaand
Component Quantities - ALG - TERREIN, Mass: 5756103 kg; ALG - TERREIN, Projected Component Area (Net): 1503.68 m2; ALG - TERREIN, Projected Component Area (Gross): 1503.68 m2; ALG - TERREIN, Component Thickness: 1740 mm; ALG - TERREIN, Component Volume (Net): 2616.41 m3; ALG - TERREIN, Component Volume (Gross): 2616.41 m3

# IfcFurnishingElement: ALG - TERREIN 3000, 72_75 vaste inrichting
In: fundering
Type - ElementType: SHELF
Classification: Legplank (ARCHICAD Classification); 72.1 standaard (NL/SfB (4 cijfers)); Material: ALG - TERREIN
CPset_Phasing - Renovation Phase: Bestaand
Component Quantities - ALG - TERREIN, Mass: 55913477 kg; ALG - TERREIN, Projected Component Area (Net): 8496.32 m2; ALG - TERREIN, Projected Component Area (Gross): 10000 m2; ALG - TERREIN, Component Thickness: 3000 mm; ALG - TERREIN, Component Volume (Net): 25415.2 m3; ALG - TERREIN, Component Volume (Gross): 29743.6 m3

# IfcFurnishingElement: Cement 8, 72_75 vaste inrichting
In: verdieping
Type - ElementType: SHELF
Classification: Legplank (ARCHICAD Classification); 72.1 standaard (NL/SfB (4 cijfers)); Material: Cement
CPset_Phasing - Renovation Phase: Bestaand
Component Quantities - Cement, Mass: 7.6608 kg; Cement, Projected Component Area (Net): 0.504 m2; Cement, Projected Component Area (Gross): 0.504 m2; Cement, Component Thickness: 8 mm; Cement, Component Volume (Net): 0.004032 m3; Cement, Component Volume (Gross): 0.004032 m3

# IfcFurnishingElement: Gipsplaat 8 (2)
In: verdieping
Type - ElementType: SHELF
Classification: Legplank (ARCHICAD Classification); 72.1 standaard (NL/SfB (4 cijfers)); Material: Gipsplaat
CPset_Phasing - Renovation Phase: Bestaand
Component Quantities - Gipsplaat, Component Thickness: 8 mm
Name | Gipsplaat, Mass (kg) | Gipsplaat, Projected Component Area (Net) (m2) = Gipsplaat, Projected Component Area (Gross) (m2) | Gipsplaat, Component Volume (Net) (m3) = Gipsplaat, Component Volume (Gross) (m3)
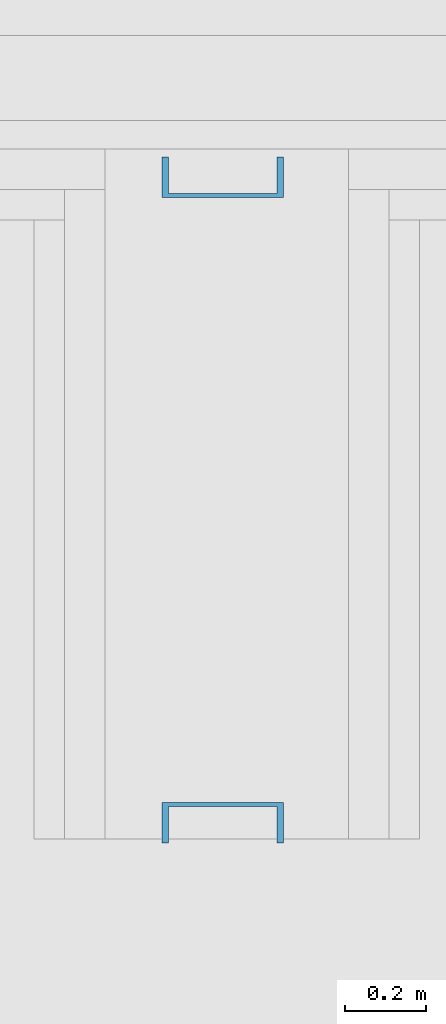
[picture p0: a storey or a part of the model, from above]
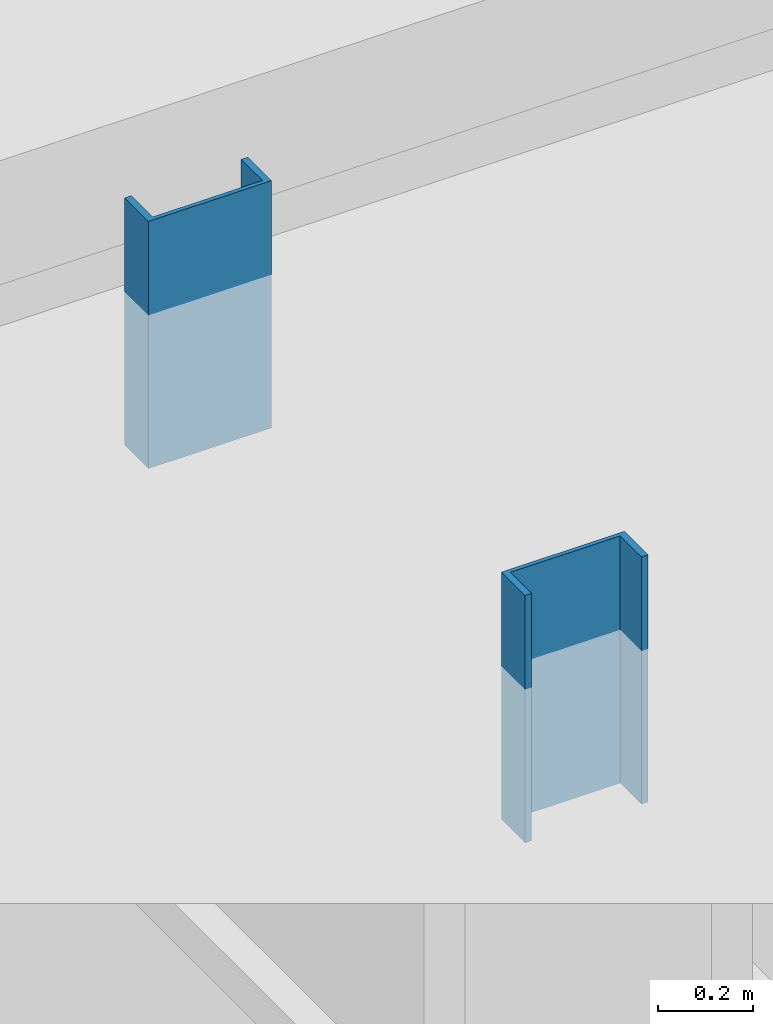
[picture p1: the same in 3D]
Properties of the parts of a building model (IFC2X3), part 6 of 9

# IfcFurnishingElement: Gipsplaat 8 (2)
Name | Gipsplaat, Mass (kg) | Gipsplaat, Projected Component Area (Net) (m2) = Gipsplaat, Projected Component Area (Gross) (m2) | Gipsplaat, Component Volume (Net) (m3) = Gipsplaat, Component Volume (Gross) (m3)
72_75 vaste inrichting | 14.2945 | 2.23351 | 0.0178681
72_75 vaste inrichting | 22.6019 | 3.53154 | 0.0282523

# IfcFurnishingElement: Glas 1400 (2)
In: begane grond
Type - ElementType: SHELF
Classification: Legplank (ARCHICAD Classification); 72.1 standaard (NL/SfB (4 cijfers)); Material: Glas
CPset_Phasing - Renovation Phase: Bestaand
Component Quantities - Glas, Mass: 2.45991 kg; Glas, Projected Component Area (Net): 0.000806 m2; Glas, Projected Component Area (Gross): 0.000806 m2; Glas, Component Thickness: 1400 mm; Glas, Component Volume (Net): 0.0011284 m3; Glas, Component Volume (Gross): 0.0011284 m3

# IfcFurnishingElement: Glas matte folie 1400, 72_73 vaste inrichting
In: begane grond
Type - ElementType: SHELF
Classification: Legplank (ARCHICAD Classification); 72.1 standaard (NL/SfB (4 cijfers)); Material: Glas matte folie
CPset_Phasing - Renovation Phase: Bestaand
Component Quantities - Glas matte folie, Mass: 4.9595 kg; Glas matte folie, Projected Component Area (Net): 0.001625 m2; Glas matte folie, Projected Component Area (Gross): 0.001625 m2; Glas matte folie, Component Thickness: 1400 mm; Glas matte folie, Component Volume (Net): 0.002275 m3; Glas matte folie, Component Volume (Gross): 0.002275 m3

# IfcFurnishingElement: Hout - Multiplex wbp 45, 72_75 vaste inrichting
In: dakaanzicht
Type - ElementType: SHELF
Classification: Legplank (ARCHICAD Classification); 72.1 standaard (NL/SfB (4 cijfers)); Material: Hout - Multiplex wbp
CPset_Phasing - Renovation Phase: Bestaand
Component Quantities - Hout - Multiplex wbp, Mass: 142.619 kg; Hout - Multiplex wbp, Projected Component Area (Net): 4.5276 m2; Hout - Multiplex wbp, Projected Component Area (Gross): 4.5276 m2; Hout - Multiplex wbp, Component Thickness: 45 mm; Hout - Multiplex wbp, Component Volume (Net): 0.203742 m3; Hout - Multiplex wbp, Component Volume (Gross): 0.203742 m3

# IfcFurnishingElement: Hout - Spaanplaat 20 (56)
Type - ElementType: SHELF
Classification: Legplank (ARCHICAD Classification); 72.1 standaard (NL/SfB (4 cijfers)); Material: Hout - Spaanplaat
CPset_Phasing - Renovation Phase: Bestaand
Component Quantities - Hout - Spaanplaat, Component Thickness: 20 mm
Name | In | Hout - Spaanplaat, Mass (kg) | Hout - Spaanplaat, Projected Component Area (Net) (m2) = Hout - Spaanplaat, Projected Component Area (Gross) (m2) | Hout - Spaanplaat, Component Volume (Net) (m3) = Hout - Spaanplaat, Component Volume (Gross) (m3)
10 x 72_72 vaste inrichting | begane grond | 36 | 3 | 0.06
10 x 72_73 vaste inrichting | begane grond | 35.4413 | 2.95344 | 0.0590688
2 x 72_72 vaste inrichting | begane grond | 17.28 | 1.44 | 0.0288
2 x 72_72 vaste inrichting | begane grond | 20.52 | 1.71 | 0.0342
72_72 vaste inrichting | begane grond | 7.536 | 0.628 | 0.01256
72_72 vaste inrichting | begane grond | 16.32 | 1.36 | 0.0272
10 x 72_73 vaste inrichting | verdieping | 35.4413 | 2.95344 | 0.0590688
10 x 72_72 vaste inrichting | verdieping | 68.202 | 5.6835 | 0.11367
10 x 72_72 vaste inrichting | verdieping | 36 | 3 | 0.06

# IfcFurnishingElement: Hout - Spaanplaat 30, 72_72 vaste inrichting
In: verdieping
Type - ElementType: SHELF
Classification: Legplank (ARCHICAD Classification); 72.1 standaard (NL/SfB (4 cijfers)); Material: Hout - Spaanplaat
CPset_Phasing - Renovation Phase: Bestaand
Component Quantities - Hout - Spaanplaat, Mass: 45.09 kg; Hout - Spaanplaat, Projected Component Area (Net): 2.505 m2; Hout - Spaanplaat, Projected Component Area (Gross): 2.505 m2; Hout - Spaanplaat, Component Thickness: 30 mm; Hout - Spaanplaat, Component Volume (Net): 0.07515 m3; Hout - Spaanplaat, Component Volume (Gross): 0.07515 m3

# IfcFurnishingElement: Kopieerapparaat 25 (2)
Classification: Inrichting (ARCHICAD Classification); 72.10 algemeen (verzamelniveau) (NL/SfB (4 cijfers))
CPset_Phasing - Renovation Phase: Bestaand
Component Quantities - Component, Component Volume (Net): 0.767537 m3; Component, Component Volume (Gross): 0.767537 m3
Name | In
72_kopieerapparaat | begane grond
72_kopieerapparaat | verdieping

# IfcFurnishingElement: Metaal - Aluminium 25 (13)
In: begane grond
Type - ElementType: SHELF
Classification: Legplank (ARCHICAD Classification); 72.1 standaard (NL/SfB (4 cijfers)); Material: Metaal - Aluminium
CPset_Phasing - Renovation Phase: Bestaand
Component Quantities - Metaal - Aluminium, Component Thickness: 25 mm
Name | Metaal - Aluminium, Mass (kg) | Metaal - Aluminium, Projected Component Area (Net) (m2) = Metaal - Aluminium, Projected Component Area (Gross) (m2) | Metaal - Aluminium, Component Volume (Net) (m3) = Metaal - Aluminium, Component Volume (Gross) (m3)
72_43 schoonloop zone 1 | 304.08 | 4.344 | 0.1086
72_43 schoonloop zone 1 | 299.466 | 4.27808 | 0.106952
72_43 schoonloop zone 1 | 705.6 | 10.08 | 0.252
10 x 72_43 schoonloop zone 1 | 96.6 | 1.38 | 0.0345

# IfcFurnishingElement: Metaal - Staal C 3, 72_75 vaste inrichting
In: verdieping
Type - ElementType: SHELF
Classification: Legplank (ARCHICAD Classification); 72.1 standaard (NL/SfB (4 cijfers)); Material: Metaal - Staal C
CPset_Phasing - Renovation Phase: Bestaand
Component Quantities - Metaal - Staal C, Mass: 1450.35 kg; Metaal - Staal C, Projected Component Area (Net): 60.8112 m2; Metaal - Staal C, Projected Component Area (Gross): 60.8112 m2; Metaal - Staal C, Component Thickness: 3 mm; Metaal - Staal C, Component Volume (Net): 0.182434 m3; Metaal - Staal C, Component Volume (Gross): 0.182434 m3

# IfcMember: 31 pui (3200+) 62 x 3200 (2)
In: begane grond
Type - PredefinedType: MEMBER
Classification: 21.22 spouwwanden (NL/SfB (4 cijfers)); Onderdeel (ARCHICAD Classification); Material: 31 pui/kozijn
CPset_Phasing - Renovation Phase: Bestaand
Pset_MemberCommon - LoadBearing: no; IsExternal: yes
BaseQuantities - CrossSectionArea: 0.1984 m2; NetVolume: 0.002976 m3
Component Quantities - 31 pui/kozijn, Mass: 2.3808 kg; 31 pui/kozijn, Rectangular Component Height: 3200 mm; 31 pui/kozijn, Rectangular Component Width: 62 mm; 31 pui/kozijn, Component Cross Section Area: 0.1984 m2; 31 pui/kozijn, Component Volume (Net): 0.002976 m3
Name | Length (mm) | OuterSurfaceArea (m2) | TotalSurfaceArea (m2) = GrossSurfaceArea (m2) | GrossVolume (m3) = 31 pui/kozijn, Component Volume (Gross) (m3)
21_31 buitenkozijn pui | 6100 | 39.0419 | 39.0437 | 1.21024
21_31 buitenkozijn pui | 6300 | 40.3219 | 40.3237 | 1.24992

# IfcMember: 31 pui/kozijn 112 (2)
Type - PredefinedType: MEMBER
Classification: 21.22 spouwwanden (NL/SfB (4 cijfers)); Onderdeel (ARCHICAD Classification); Material: 31 pui/kozijn
CPset_Phasing - Renovation Phase: Bestaand
Pset_MemberCommon - LoadBearing: no; IsExternal: yes
BaseQuantities - Length: 1919 mm
Component Quantities - 31 pui/kozijn, Component Thickness: 112 mm; 31 pui/kozijn, Rectangular Component Width: 112 mm
Name | In | CrossSectionArea (m2) = 31 pui/kozijn, Component Cross Section Area (m2) | OuterSurfaceArea (m2) | TotalSurfaceArea (m2) = GrossSurfaceArea (m2) | GrossVolume (m3) = 31 pui/kozijn, Component Volume (Gross) (m3) | NetVolume (m3) = 31 pui/kozijn, Component Volume (Net) (m3) | 31 pui/kozijn, Mass (kg) | 31 pui/kozijn, Projected Component Area (Net) (m2) | 31 pui/kozijn, Projected Component Area (Gross) (m2) | 31 pui/kozijn, Rectangular Component Height (mm)
21_31 buitenkozijn pui | begane grond | 0.4928 | 17.6875 | 18.1243 | 0.96096 | 0.398794 | 319.035 | 3.56066 | 8.58 | 4400
21_31 buitenkozijn pui | verdieping | 0.4424 | 15.6884 | 16.1252 | 0.86268 | 0.24877 | 199.016 | 2.22116 | 7.7025 | 3950

# IfcMember: 31 pui/kozijn 62 (19)
Type - PredefinedType: MEMBER
Classification: 21.22 spouwwanden (NL/SfB (4 cijfers)); Onderdeel (ARCHICAD Classification); Material: 31 pui/kozijn
CPset_Phasing - Renovation Phase: Bestaand
Pset_MemberCommon - LoadBearing: no; IsExternal: yes
Component Quantities - 31 pui/kozijn, Component Thickness: 62 mm; 31 pui/kozijn, Rectangular Component Width: 62 mm
Name | In | Length (mm) | CrossSectionArea (m2) = 31 pui/kozijn, Component Cross Section Area (m2) | OuterSurfaceArea (m2) | TotalSurfaceArea (m2) = GrossSurfaceArea (m2) | GrossVolume (m3) = 31 pui/kozijn, Component Volume (Gross) (m3) | NetVolume (m3) = 31 pui/kozijn, Component Volume (Net) (m3) | 31 pui/kozijn, Mass (kg) | 31 pui/kozijn, Projected Component Area (Net) (m2) | 31 pui/kozijn, Projected Component Area (Gross) (m2) | 31 pui/kozijn, Rectangular Component Height (mm)
21_31 buitenkozijn pui | begane grond | 6200 | 0.1302 | 26.9962 | 27.6191 | 0.80724 | 0.0827238 | 66.179 | 1.33426 | 13.02 | 2100
21_31 buitenkozijn pui | begane grond | 2344 | 0.2728 | 20.4683 | 20.752 | 0.624166 | 0.118447 | 94.7573 | 1.91043 | 10.0672 | 4400
21_31 buitenkozijn pui | begane grond | 3056 | 0.1302 | 13.4784 | 13.8612 | 0.401927 | 0.0479344 | 38.3475 | 0.773135 | 6.4827 | 2100
21_31 buitenkozijn pui | begane grond | 1718 | 0.1302 | 7.42479 | 7.63398 | 0.219647 | 0.0302374 | 24.1899 | 0.4877 | 3.5427 | 2100
2 x 21_31 buitenkozijn pui | begane grond | 2800 | 0.1302 | 12.3676 | 12.7148 | 0.36456 | 0.049848 | 39.8784 | 0.804 | 5.88 | 2100
21_31 buitenkozijn pui | begane grond | 2169 | 0.1302 | 9.52644 | 9.79924 | 0.28644 | 0.030008 | 24.0064 | 0.484 | 4.62 | 2100
3 x 21_31 buitenkozijn pui | begane grond | 5700 | 0.1302 | 24.8342 | 25.3951 | 0.74214 | 0.0759038 | 60.723 | 1.22426 | 11.97 | 2100
21_31 buitenkozijn pui | begane grond | 2156 | 0.1302 | 9.20214 | 9.46564 | 0.276675 | 0.028985 | 23.188 | 0.4675 | 4.4625 | 2100
3 x 21_31 buitenkozijn pui | begane grond | 6400 | 0.1302 | 27.861 | 28.5087 | 0.83328 | 0.0854518 | 68.3614 | 1.37826 | 13.44 | 2100
2 x 21_31 buitenkozijn pui | begane grond | 2100 | 0.1302 | 9.3408 | 9.6012 | 0.27342 | 0.0403 | 32.24 | 0.65 | 4.41 | 2100
21_31 buitenkozijn pui | verdieping | 621 | 0.24056 | 4.20409 | 4.27487 | 0.129518 | 0.0284908 | 22.7926 | 0.46416 | 2.09436 | 3880
21_31 buitenkozijn pui | verdieping | 13553 | 0.24056 | 106.501 | 108.186 | 3.26777 | 1.14674 | 917.389 | 18.4958 | 52.7059 | 3880
21_31 buitenkozijn pui | verdieping | 2344 | 0.2449 | 18.2195 | 18.5032 | 0.560331 | 0.00901108 | 7.20887 | 0.14534 | 9.0376 | 3950

# IfcMember: IfcMember (23)
Type - ElementType: Rail; PredefinedType: USERDEFINED
Classification: Reling - regel (ARCHICAD Classification)
CPset_Phasing - Renovation Phase: Bestaand
Name | In | GrossVolume (m3) = NetVolume (m3) | Length (mm) | Material
2 x _Handregel-x | begane grond | 0.00460793 | 2341.24
2 x _Handregel-x | begane grond | 0.000993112 | 516.127
2 x _Handregel-x | begane grond | 0.00852519 | 4328.95
_Handregel-x | begane grond | 0.00141691 | 725
_Einde handregel-x | begane grond | 0.00000976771 | 5 | Hout AFW | Component Quantities - Hout AFW, Mass: 0.00537224 kg; Hout AFW, Component Volume (Net): 0.00000976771 m3; Hout AFW, Component Volume (Gross): 0.00000976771 m3
_Handregel-x | begane grond | 0.00140671 | 719.781
_ | begane grond | 0.00117619 | 2453.39 | Metaal - Aluminium | Component Quantities - Metaal - Aluminium, Mass: 3.29333 kg; Metaal - Aluminium, Component Volume (Net): 0.00117619 m3; Metaal - Aluminium, Component Volume (Gross): 0.00117619 m3
_ | begane grond | 0.00117456 | 2450 | Metaal - Aluminium | Component Quantities - Metaal - Aluminium, Mass: 3.28877 kg; Metaal - Aluminium, Component Volume (Net): 0.00117456 m3; Metaal - Aluminium, Component Volume (Gross): 0.00117456 m3
_ | begane grond | 0.00070512 | 1475 | Metaal - Aluminium | Component Quantities - Metaal - Aluminium, Mass: 1.97434 kg; Metaal - Aluminium, Component Volume (Net): 0.00070512 m3; Metaal - Aluminium, Component Volume (Gross): 0.00070512 m3
_Regel-x | begane grond | 0.000708 | 1475 | Metaal - RVS | Component Quantities - Metaal - RVS, Mass: 5.5932 kg; Metaal - RVS, Component Volume (Net): 0.000708 m3; Metaal - RVS, Component Volume (Gross): 0.000708 m3
_ | verdieping | 0.00064656 | 1350 | Metaal - Aluminium | Component Quantities - Metaal - Aluminium, Mass: 1.81037 kg; Metaal - Aluminium, Component Volume (Net): 0.00064656 m3; Metaal - Aluminium, Component Volume (Gross): 0.00064656 m3
_ | verdieping | 0.00117444 | 2449.76 | Metaal - Aluminium | Component Quantities - Metaal - Aluminium, Mass: 3.28844 kg; Metaal - Aluminium, Component Volume (Net): 0.00117444 m3; Metaal - Aluminium, Component Volume (Gross): 0.00117444 m3
_ | verdieping | 0.00101616 | 2120 | Metaal - Aluminium | Component Quantities - Metaal - Aluminium, Mass: 2.84525 kg; Metaal - Aluminium, Component Volume (Net): 0.00101616 m3; Metaal - Aluminium, Component Volume (Gross): 0.00101616 m3
_Regel-x | verdieping | 0.0010176 | 2120 | Metaal - RVS | Component Quantities - Metaal - RVS, Mass: 8.03904 kg; Metaal - RVS, Component Volume (Net): 0.0010176 m3; Metaal - RVS, Component Volume (Gross): 0.0010176 m3
_ | verdieping | 0.000611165 | 1274.23 | Metaal - Aluminium | Component Quantities - Metaal - Aluminium, Mass: 1.71126 kg; Metaal - Aluminium, Component Volume (Net): 0.000611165 m3; Metaal - Aluminium, Component Volume (Gross): 0.000611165 m3
_Regel-x | verdieping | 0.00061163 | 1275.2 | Metaal - RVS | Component Quantities - Metaal - RVS, Mass: 4.83187 kg; Metaal - RVS, Component Volume (Net): 0.00061163 m3; Metaal - RVS, Component Volume (Gross): 0.00061163 m3
_ | verdieping | 0.00290224 | 6049.23 | Metaal - Aluminium | Component Quantities - Metaal - Aluminium, Mass: 8.12627 kg; Metaal - Aluminium, Component Volume (Net): 0.00290224 m3; Metaal - Aluminium, Component Volume (Gross): 0.00290224 m3
_Regel-x | verdieping | 0.00309681 | 6452.66 | Metaal - RVS | Component Quantities - Metaal - RVS, Mass: 24.4648 kg; Metaal - RVS, Component Volume (Net): 0.00309681 m3; Metaal - RVS, Component Volume (Gross): 0.00309681 m3
_ | verdieping | 0.00057456 | 1200 | Metaal - Aluminium | Component Quantities - Metaal - Aluminium, Mass: 1.60877 kg; Metaal - Aluminium, Component Volume (Net): 0.00057456 m3; Metaal - Aluminium, Component Volume (Gross): 0.00057456 m3
_Regel-x | verdieping | 0.000576 | 1200 | Metaal - RVS | Component Quantities - Metaal - RVS, Mass: 4.5504 kg; Metaal - RVS, Component Volume (Net): 0.000576 m3; Metaal - RVS, Component Volume (Gross): 0.000576 m3

# IfcMember: IfcMember (22)
In: begane grond
Type - ElementType: Stair Tread; PredefinedType: USERDEFINED
Classification: Trap - trede (ARCHICAD Classification); 44.10 algemeen (verzamelniveau) (NL/SfB (4 cijfers)); Material: Metaal - Staal C wit
CPset_Phasing - Renovation Phase: Bestaand
Name | GrossVolume (m3) = NetVolume (m3) = Metaal - Staal C wit, Component Volume (Net) (m3) = Metaal - Staal C wit, Component Volume (Gross) (m3) | Metaal - Staal C wit, Mass (kg)
21 x 44_Traptrede-x | 0.0222741 | 177.079
44_Traptrede-x | 0.290375 | 2308.48

# IfcMember: IfcMember (111)
Type - PredefinedType: MEMBER
Classification: Onderdeel (ARCHICAD Classification); Material: Metaal - RVS
CPset_Phasing - Renovation Phase: Bestaand
Name | In | GrossVolume (m3) = NetVolume (m3) | Length (mm)
_Spijlen-x | begane grond | 0.0011712 | 2440 | Component Quantities - Metaal - RVS, Mass: 9.25248 kg; Metaal - RVS, Component Volume (Net): 0.0011712 m3; Metaal - RVS, Component Volume (Gross): 0.0011712 m3
13 x _Spijlen-x | begane grond | 0.0011712 | 2440
_Spijlen-x | verdieping | 0.0006432 | 1340 | Component Quantities - Metaal - RVS, Mass: 5.08128 kg; Metaal - RVS, Component Volume (Net): 0.0006432 m3; Metaal - RVS, Component Volume (Gross): 0.0006432 m3
33 x _Spijlen-x | verdieping | 0.0006432 | 1340
_Spijlen-x | verdieping | 0.000638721 | 1334.99 | Component Quantities - Metaal - RVS, Mass: 5.04589 kg; Metaal - RVS, Component Volume (Net): 0.000638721 m3; Metaal - RVS, Component Volume (Gross): 0.000638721 m3
34 x _Spijlen-x | verdieping | 0.000638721 | 1334.99
_Spijlen-x | verdieping | 0.000666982 | 1391.71 | Component Quantities - Metaal - RVS, Mass: 5.26916 kg; Metaal - RVS, Component Volume (Net): 0.000666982 m3; Metaal - RVS, Component Volume (Gross): 0.000666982 m3
_Spijlen-x | verdieping | 0.000701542 | 1463.71 | Component Quantities - Metaal - RVS, Mass: 5.54218 kg; Metaal - RVS, Component Volume (Net): 0.000701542 m3; Metaal - RVS, Component Volume (Gross): 0.000701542 m3
_Spijlen-x | verdieping | 0.000736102 | 1535.71 | Component Quantities - Metaal - RVS, Mass: 5.81521 kg; Metaal - RVS, Component Volume (Net): 0.000736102 m3; Metaal - RVS, Component Volume (Gross): 0.000736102 m3
_Spijlen-x | verdieping | 0.000770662 | 1607.71 | Component Quantities - Metaal - RVS, Mass: 6.08823 kg; Metaal - RVS, Component Volume (Net): 0.000770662 m3; Metaal - RVS, Component Volume (Gross): 0.000770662 m3
_Spijlen-x | verdieping | 0.000805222 | 1679.71 | Component Quantities - Metaal - RVS, Mass: 6.36125 kg; Metaal - RVS, Component Volume (Net): 0.000805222 m3; Metaal - RVS, Component Volume (Gross): 0.000805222 m3
_Spijlen-x | verdieping | 0.000839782 | 1751.71 | Component Quantities - Metaal - RVS, Mass: 6.63428 kg; Metaal - RVS, Component Volume (Net): 0.000839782 m3; Metaal - RVS, Component Volume (Gross): 0.000839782 m3
_Spijlen-x | verdieping | 0.000874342 | 1823.71 | Component Quantities - Metaal - RVS, Mass: 6.9073 kg; Metaal - RVS, Component Volume (Net): 0.000874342 m3; Metaal - RVS, Component Volume (Gross): 0.000874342 m3
_Spijlen-x | verdieping | 0.000908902 | 1895.71 | Component Quantities - Metaal - RVS, Mass: 7.18033 kg; Metaal - RVS, Component Volume (Net): 0.000908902 m3; Metaal - RVS, Component Volume (Gross): 0.000908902 m3
_Spijlen-x | verdieping | 0.000943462 | 1967.71 | Component Quantities - Metaal - RVS, Mass: 7.45335 kg; Metaal - RVS, Component Volume (Net): 0.000943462 m3; Metaal - RVS, Component Volume (Gross): 0.000943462 m3
_Spijlen-x | verdieping | 0.000978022 | 2039.71 | Component Quantities - Metaal - RVS, Mass: 7.72637 kg; Metaal - RVS, Component Volume (Net): 0.000978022 m3; Metaal - RVS, Component Volume (Gross): 0.000978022 m3
_Spijlen-x | verdieping | 0.00101258 | 2111.71 | Component Quantities - Metaal - RVS, Mass: 7.9994 kg; Metaal - RVS, Component Volume (Net): 0.00101258 m3; Metaal - RVS, Component Volume (Gross): 0.00101258 m3
_Spijlen-x | verdieping | 0.00104714 | 2183.71 | Component Quantities - Metaal - RVS, Mass: 8.27242 kg; Metaal - RVS, Component Volume (Net): 0.00104714 m3; Metaal - RVS, Component Volume (Gross): 0.00104714 m3
_Spijlen-x | verdieping | 0.0010817 | 2255.71 | Component Quantities - Metaal - RVS, Mass: 8.54545 kg; Metaal - RVS, Component Volume (Net): 0.0010817 m3; Metaal - RVS, Component Volume (Gross): 0.0010817 m3
_Spijlen-x | verdieping | 0.00111626 | 2327.71 | Component Quantities - Metaal - RVS, Mass: 8.81847 kg; Metaal - RVS, Component Volume (Net): 0.00111626 m3; Metaal - RVS, Component Volume (Gross): 0.00111626 m3
_Spijlen-x | verdieping | 0.00115082 | 2399.71 | Component Quantities - Metaal - RVS, Mass: 9.09149 kg; Metaal - RVS, Component Volume (Net): 0.00115082 m3; Metaal - RVS, Component Volume (Gross): 0.00115082 m3
_Spijlen-x | verdieping | 0.00118538 | 2471.71 | Component Quantities - Metaal - RVS, Mass: 9.36452 kg; Metaal - RVS, Component Volume (Net): 0.00118538 m3; Metaal - RVS, Component Volume (Gross): 0.00118538 m3
_Spijlen-x | verdieping | 0.00121994 | 2543.71 | Component Quantities - Metaal - RVS, Mass: 9.63754 kg; Metaal - RVS, Component Volume (Net): 0.00121994 m3; Metaal - RVS, Component Volume (Gross): 0.00121994 m3
_Spijlen-x | verdieping | 0.00117108 | 2439.76 | Component Quantities - Metaal - RVS, Mass: 9.25155 kg; Metaal - RVS, Component Volume (Net): 0.00117108 m3; Metaal - RVS, Component Volume (Gross): 0.00117108 m3
10 x _Spijlen-x | verdieping | 0.00117108 | 2439.76

# IfcOpeningElement (402)
Name | In | Depth (mm) | Height (mm) | Width (mm) | Area (m2) | Volume (m3)
3 x 32_10.02 | begane grond | 125 | 2600 | 893 | 2.3218 | 0.0027624
5 x 31_- | begane grond | 125 | 2600 | 25 | 0.065 | 0.008385
3 x 32_- | begane grond | 125 | 2600 | 7 | 0.0182 | 0.0502307
10 x 31_11.01 | begane grond | 125 | 1400 | 1831 | 2.5634 | 0.0025528
6 x 32_10.01 | begane grond | 125 | 2600 | 724 | 1.8824 | 0.0026272
5 x 32_- | begane grond | 125 | 2600 | 139 | 0.3614 | 0.0502307
32_10.06 | begane grond | 125 | 2600 | 258.5 | 0.6721 | 0.0022548
3 x 32_06.02 | begane grond | 125 | 2600 | 3400 | 8.84 | 0.215411
2 x 31_11.02 | begane grond | 125 | 1400 | 893 | 1.2502 | 0.0018024
2 x 31_07.01 | begane grond | 125 | 2600 | 848 | 2.2048 | 0.0817654
31_06.03 | begane grond | 125 | 2600 | 3400 | 8.84 | 0.169834
32_01.03 | begane grond | 125 | 2600 | 1064 | 2.7664 | 0.163376
2 x 32_- | begane grond | 100 | 2600 | 2675 | 6.955 | 0
32_- | begane grond | 125 | 0 | 0 | 0 | 0.0502307
32_04.02 | begane grond | 125 | 2600 | 1336 | 3.4736 | 0.161659
2 x 32_05.07 | begane grond | 125 | 2600 | 1700 | 4.42 | 0.209779
32_01.04 | begane grond | 210 | 3050 | 1064 | 3.2452 | 0.138377
32_04.05 | begane grond | 210 | 3050 | 2100 | 6.405 | 0.168524
2 x 31_10.17 | begane grond | 125 | 2600 | 1250 | 3.25 | 0.003048
32_- | begane grond | 125 | 2600 | 4000 | 10.4 | 0
6 x 32_02.01 | begane grond | 125 | 2600 | 1064 | 2.7664 | 0.12458
2 x 32_01.06 | begane grond | 125 | 2600 | 1064 | 2.7664 | 0.164251
32_04.07 | begane grond | 125 | 2600 | 1432.1 | 3.72347 | 0.164064
6 x 32_02.05 | begane grond | 125 | 2600 | 1064 | 2.7664 | 0.164251
32_- | begane grond | 210 | 2670 | 1800 | 4.806 | 0
32_- | begane grond | 210 | 2680 | 1800 | 4.824 | 0
3 x 31_merk-AV | begane grond | 72 | 2570 | 2090 | 5.3713 | 0.127243
31_merk-AB2 | begane grond | 62 | 1880 | 3475 | 6.533 | 0.0867418
32_merk-AB1 | begane grond | 62 | 2065 | 2625 | 5.15274 | 0.0897764
3 x 31_12.01 | begane grond | 125 | 600 | 2100 | 1.26 | 0.002128
3 x 32_05.01 | begane grond | 125 | 2600 | 2100 | 5.46 | 0.204631
9 x 74_A. | begane grond | 20 | 2100 | 600 | 1.26 | 0.01638
31_06.04 | begane grond | 125 | 2600 | 3400 | 8.84 | 0.169834
32_02.03 | begane grond | 125 | 2600 | 1064 | 2.7664 | 0.163376
2 x 32_10.07 | begane grond | 125 | 2600 | 461 | 1.1986 | 0.0024168
2 x 32_10.08 | begane grond | 125 | 2600 | 520.5 | 1.3533 | 0.0024644
32_05.05 | begane grond | 125 | 2600 | 4155.5 | 10.8043 | 0.361777
7 x 32_01.01 | begane grond | 125 | 2600 | 1064 | 2.7664 | 0.12458
32_merk-AN1 | begane grond | 62 | 3210 | 1802 | 5.78442 | 0.0471148
2 x 32_10.19 | begane grond | 125 | 2600 | 1208.5 | 3.1421 | 0.0030148
2 x 32_10.05 | begane grond | 125 | 2600 | 1750 | 4.55 | 0.003448
31_11.05 | begane grond | 125 | 1400 | 1221 | 1.7094 | 0.0019848
2 x 31_11.08 | begane grond | 125 | 1400 | 1206.25 | 1.68875 | 0.002053
32_- | begane grond | 125 | 0 | 0 | 0 | 0
31_11.07 | begane grond | 125 | 1400 | 1142 | 1.5988 | 0.0019216
31_11.06 | begane grond | 125 | 1400 | 1280 | 1.792 | 0.002032
31_11.10 | begane grond | 125 | 1400 | 1651.25 | 2.31175 | 0.002329
31_11.11 | begane grond | 125 | 1400 | 770.25 | 1.07835 | 0.0016242
31_11.09 | begane grond | 125 | 1400 | 1082.62 | 1.51568 | 0.0018741
31_11.09 | begane grond | 125 | 1400 | 982.625 | 1.37567 | 0.0018741
2 x 31_11.07 | begane grond | 125 | 1400 | 1042 | 1.4588 | 0.0019216
3 x 31_11.05 | begane grond | 125 | 1400 | 1121 | 1.5694 | 0.0019848
2 x 31_11.06 | begane grond | 125 | 1400 | 1180 | 1.652 | 0.002032
32_02.06 | begane grond | 125 | 2600 | 1064 | 2.7664 | 0.164251
31_11.13 | begane grond | 125 | 1400 | 72.5 | 0.1015 | 0.001146
32_10.16 | begane grond | 125 | 2600 | 1629 | 4.2354 | 0.0033512
32_01.02 | begane grond | 125 | 2600 | 1064 | 2.7664 | 0.163376
32_05.08 | begane grond | 210 | 2670 | 1244 | 3.32148 | 0.159883
32_03.01 | begane grond | 125 | 2600 | 1250 | 3.25 | 0.132051
32_02.04 | begane grond | 125 | 2600 | 1064 | 2.7664 | 0.138377
31_merk-AU | begane grond | 60 | 2600 | 2120 | 5.512 | 0.12973
32_10.20 | begane grond | 125 | 2600 | 1400 | 3.64 | 0.003168
32_- | begane grond | 125 | 2600 | 3600 | 9.36 | 0
32_- | begane grond | 125 | 2600 | 7000 | 18.2 | 0
32_01.02 | begane grond | 125 | 2600 | 1064 | 2.7664 | 0.164251
32_04.04 | begane grond | 125 | 2600 | 1625 | 4.225 | 0.16889
32_05.02 | begane grond | 125 | 2600 | 2120 | 5.512 | 0.205465
32_08.01 | begane grond | 105 | 2990 | 7000 | 20.93 | 1.04328
2 x 32_05.06 | begane grond | 125 | 2475 | 1544 | 3.8214 | 0.183857
2 x 32_merk-AP | begane grond | 62 | 3210 | 635 | 2.03835 | 0.146761
32_merk-AO1 | begane grond | 62 | 3210 | 1000 | 3.21 | 0.0683023
32_merk-AO2 | begane grond | 62 | 3210 | 2880 | 9.24479 | 0.0687052
31_07.02 | begane grond | 125 | 2600 | 893 | 2.3218 | 0.0828913
32_merk-C1 | begane grond | 212 | 2640 | 1202 | 3.17568 | 0.0778404
32_03.02 | begane grond | 125 | 2600 | 1336 | 3.4736 | 0.161659
32_merk-AD | begane grond | 280 | 2610 | 1520 | 3.9672 | 0.0312751
31_10.18 | begane grond | 210 | 2600 | 1600 | 4.16 | 0.003328
32_- | begane grond | 210 | 2670 | 1600 | 4.272 | 0
2 x 32_06.01 | begane grond | 125 | 2600 | 3400 | 8.84 | 0.215411
32_04.06 | begane grond | 125 | 2600 | 2455.5 | 6.3843 | 0.189669
32_merk-AT | begane grond | 112 | 3590 | 1400 | 5.01934 | 0.154537
31_- | begane grond | 430 | 1900 | 2338 | 4.4422 | 0
3 x 31_- | begane grond | 430 | 1900 | 4423 | 8.40369 | 0
5 x 31_- | begane grond | 430 | 2600 | 1177 | 3.0602 | 0
2 x 31_- | begane grond | 430 | 1900 | 2000 | 3.8 | 0
2 x 31_- | begane grond | 430 | 1900 | 2700 | 5.12999 | 0
31_- | begane grond | 430 | 1900 | 1825 | 3.4675 | 0
31_- | begane grond | 430 | 1900 | 2325 | 4.4175 | 0
31_merk-AJ4 | begane grond | 62 | 3200 | 3467.5 | 11.096 | 0.128177
32_merk-AJ3 | begane grond | 62 | 3200 | 2617.5 | 8.376 | 0.108274
31_merk-AK | begane grond | 62 | 3190 | 1150 | 3.6685 | 0.0596316
32_merk-AN6 | begane grond | 62 | 3210 | 1802 | 5.78442 | 0.0519428
32_merk-AN5 | begane grond | 62 | 3210 | 1919.5 | 6.1616 | 0.0978596
32_merk-AN4 | begane grond | 62 | 3210 | 2640 | 8.4744 | 0.0940004
32_merk-AN3 | begane grond | 62 | 3210 | 2753 | 8.83713 | 0.0953184
32_merk-AN2 | begane grond | 62 | 3210 | 625.503 | 2.00787 | 0.0349283
2 x 31_- | begane grond | 490 | 0 | 0 | 0 | 0
32_- | begane grond | 300 | 3005 | 7000 | 21.035 | 0
32_- | begane grond | 210 | 3110 | 1400 | 4.354 | 0
32_- | begane grond | 210 | 3110 | 1500 | 4.665 | 0
32_05.03 | begane grond | 210 | 2670 | 2212.5 | 5.90738 | 0.17056
32_02.04 | begane grond | 210 | 3050 | 1064 | 3.2452 | 0.138377
32_03.03 | begane grond | 210 | 3050 | 2100 | 6.405 | 0.168524
32_merk-AS | begane grond | 62 | 3590 | 2278 | 8.15677 | 0.088416
31_- | begane grond | 430 | 1900 | 3175 | 6.03251 | 0
31_merk-AH1 | begane grond | 62 | 1880 | 2975 | 5.59301 | 0.0650259
31_merk-AH2 | begane grond | 62 | 1880 | 1625 | 3.055 | 0.0306501
2 x 31_merk-AF | begane grond | 62 | 1880 | 2700 | 5.076 | 0.0586524
31_merk-AE2 | begane grond | 62 | 1880 | 2138 | 4.01944 | 0.0585174
3 x 31_merk-AC1 | begane grond | 62 | 1880 | 2700 | 5.076 | 0.0568372
3 x 32_merk-AC2 | begane grond | 62 | 2065 | 2900 | 5.66974 | 0.0919148
31_merk-AE1 | begane grond | 62 | 1880 | 2125 | 3.995 | 0.0345381
32_05.04 | begane grond | 125 | 2600 | 4155.5 | 10.8043 | 0.361777
31_- | begane grond | 430 | 0 | 0 | 0 | 0
31_merk-AJ2 | begane grond | 62 | 3200 | 3567.5 | 11.416 | 0.129344
32_merk-AJ1 | begane grond | 62 | 3200 | 2717.5 | 8.696 | 0.10944
3 x 31_merk-AA1 | begane grond | 62 | 1880 | 3575 | 6.721 | 0.0875194
3 x 32_merk-AA2 | begane grond | 62 | 2065 | 2725 | 5.34074 | 0.090554
2 x 31_merk-AG | begane grond | 62 | 1880 | 2000 | 3.76 | 0.0532092
32_merk-AR2 | begane grond | 62 | 3210 | 1000 | 3.21 | 0.0683023
32_merk-AR1 | begane grond | 62 | 3210 | 2555 | 8.20155 | 0.0649145
32_merk-AQ | begane grond | 62 | 435 | 6600 | 2.871 | 0.0564071
32_- | begane grond | 62 | 2600 | 6300 | 16.38 | 0
2 x 32_01.07 | begane grond | 125 | 2600 | 1064 | 2.7664 | 0.164251
2 x 32_Lift deur | begane grond | 40 | 2600 | 1462 | 3.8012 | 0.10454
3 x 31_- | begane grond | 430 | 1900 | 5150 | 9.785 | 0
2 x 31_- | begane grond | 430 | 2600 | 1150 | 2.99 | 0
31_- | begane grond | 430 | 1900 | 4923 | 9.3537 | 0
32_02.03 | verdieping | 125 | 2600 | 1064 | 2.7664 | 0.163376
31_12.04 | verdieping | 125 | 3000 | 618 | 1.854 | 0.0028624
31_11.12 | verdieping | 125 | 1400 | 470.5 | 0.6587 | 0.0014644
31_12.03 | verdieping | 125 | 400 | 1064 | 0.4256 | 0.0011392
6 x 32_02.01 | verdieping | 125 | 2600 | 1064 | 2.7664 | 0.12458
31_merk-BM1 | verdieping | 62 | 2860 | 570 | 1.6302 | 0.03407
2 x 32_10.04 | verdieping | 150 | 2600 | 693 | 1.8018 | 0.0026024
2 x 31_- | verdieping | 150 | 2600 | 25 | 0.065 | 0.008385
2 x 31_11.02 | verdieping | 125 | 1400 | 893 | 1.2502 | 0.0018024
2 x 31_10.11 | verdieping | 125 | 2600 | 552.5 | 1.4365 | 0.00249
8 x 31_- | verdieping | 125 | 2600 | 25 | 0.065 | 0.008385
3 x 32_10.02 | verdieping | 125 | 2600 | 893 | 2.3218 | 0.0027624
3 x 32_- | verdieping | 125 | 2600 | 7 | 0.0182 | 0.0502307
10 x 31_11.01 | verdieping | 125 | 1400 | 1831 | 2.5634 | 0.0025528
3 x 32_10.01 | verdieping | 125 | 2600 | 724 | 1.8824 | 0.0026272
8 x 32_- | verdieping | 125 | 2600 | 139 | 0.3614 | 0.0502307
32_10.06 | verdieping | 125 | 2600 | 258.5 | 0.6721 | 0.0022548
3 x 32_06.02 | verdieping | 125 | 2600 | 3400 | 8.84 | 0.215411
7 x 31_- | verdieping | 430 | 0 | 0 | 0 | 0
31_merk-BE3 | verdieping | 430 | 2860 | 2569.01 | 7.34737 | 0.0646103
31_merk-BF2 | verdieping | 430 | 2860 | 2238.75 | 6.40282 | 0.0640152
31_merk-BF1 | verdieping | 430 | 2860 | 2238.75 | 6.40282 | 0.0643175
31_merk-BG | verdieping | 430 | 2860 | 2422.5 | 6.92835 | 0.0687511
31_merk-BH | verdieping | 430 | 2860 | 2375 | 6.7925 | 0.0681971
31_merk-BJ2 | verdieping | 430 | 2860 | 2062.5 | 5.89875 | 0.0622617
31_merk-BJ1 | verdieping | 430 | 2860 | 2062.5 | 5.89875 | 0.0622617
31_merk-BE2 | verdieping | 430 | 2860 | 2552.5 | 7.30015 | 0.0717653
31_merk-BE1 | verdieping | 430 | 2860 | 2300 | 6.578 | 0.0650319
31_merk-BK4 | verdieping | 430 | 2860 | 2460 | 7.0356 | 0.0460594
31_merk-BK4 | verdieping | 430 | 2860 | 2015 | 5.7629 | 0.0744343
31_merk-BK3 | verdieping | 430 | 2860 | 2415 | 6.9069 | 0.0639843
31_merk-BK2 | verdieping | 430 | 2860 | 1537.5 | 4.39725 | 0.0446864
32_09.05A | verdieping | 300 | 1700 | 3525 | 5.9925 | 0.01625
2 x 32_09.02 | verdieping | 300 | 1700 | 3075 | 5.2275 | 0.013375
2 x 32_09.01 | verdieping | 300 | 1700 | 2815 | 4.7855 | 0.01295
2 x 32_02.04 | verdieping | 210 | 2600 | 1064 | 2.7664 | 0.138377
32_02.04 | verdieping | 125 | 2600 | 1064 | 2.7664 | 0.138377
32_09.03B | verdieping | 300 | 1700 | 3525 | 5.9925 | 0.01625
32_09.04 | verdieping | 300 | 1700 | 3020 | 5.134 | 0.0137125
32_09.03A | verdieping | 300 | 1700 | 3070 | 5.219 | 0.01535
32_09.05B | verdieping | 300 | 1700 | 3070 | 5.219 | 0.01535
32_01.03 | verdieping | 125 | 2600 | 1064 | 2.7664 | 0.163376
31_10.13c | verdieping | 125 | 2600 | 1110 | 2.886 | 0.001962
32_01.05 | verdieping | 125 | 2600 | 1064 | 2.7664 | 0.164251
2 x 32_10.09 | verdieping | 125 | 2600 | 374.5 | 0.9737 | 0.0023476
2 x 31_11.04 | verdieping | 125 | 1400 | 1798 | 2.5172 | 0.0025264
2 x 32_10.10 | verdieping | 125 | 2600 | 536 | 1.3936 | 0.0024768
4 x 31_11.03 | verdieping | 125 | 1400 | 1481 | 2.0734 | 0.0022728
4 x 32_01.01 | verdieping | 125 | 2600 | 1064 | 2.7664 | 0.12458
31_06.03 | verdieping | 125 | 2600 | 3400 | 8.84 | 0.169834
31_06.04 | verdieping | 125 | 2600 | 3400 | 8.84 | 0.169834
32_10.04 | verdieping | 125 | 2600 | 693 | 1.8018 | 0.0026024
9 x 74_A. | verdieping | 20 | 2100 | 600 | 1.26 | 0.01638
32_04.01 | verdieping | 125 | 2600 | 2100 | 5.46 | 0.168524
3 x 31_10.03 | verdieping | 125 | 2600 | 493 | 1.2818 | 0.0024424
31_10.14 | verdieping | 125 | 2600 | 1241.5 | 3.2279 | 0.0030412
2 x 31_10.23 | verdieping | 125 | 2600 | 2027.75 | 5.27215 | 0.0036702
31_10.15 | verdieping | 125 | 2600 | 1289 | 3.3514 | 0.0030792
2 x 31_10.22 | verdieping | 125 | 2600 | 1672 | 4.3472 | 0.0033856
2 x 31_10.21 | verdieping | 125 | 2600 | 1414.5 | 3.6777 | 0.0031796
31_07.04 | verdieping | 210 | 2600 | 3000 | 7.8 | 0.196157
31_merk-BL1 | verdieping | 62 | 3550 | 2122.5 | 7.53488 | 0.0459968
31_merk-BM2 | verdieping | 62 | 2860 | 1088 | 3.11168 | 0.0371981
31_merk-BK1 | verdieping | 62 | 2860 | 1499 | 4.28714 | 0.0571569
32_merk-BL2 | verdieping | 62 | 3547 | 2307.5 | 8.1847 | 0.0967309
32_merk-BM3 | verdieping | 62 | 3547 | 3540 | 10.9145 | 0.107741
31_10.13b | verdieping | 125 | 2600 | 1311.25 | 3.40925 | 0.002123
31_10.13a | verdieping | 125 | 2600 | 1363.75 | 3.54575 | 0.003139
32_02.02 | verdieping | 125 | 2600 | 1064 | 2.7664 | 0.163376
32_01.02 | verdieping | 125 | 2600 | 1064 | 2.7664 | 0.163376
32_10.12 | verdieping | 125 | 2600 | 731 | 1.9006 | 0.0026328
2 x 32_06.01 | verdieping | 125 | 2600 | 3400 | 8.84 | 0.215411
32_12.02 | verdieping | 125 | 600 | 2400 | 1.44 | 0.002368
32_04.03 | verdieping | 210 | 2600 | 1399 | 3.6374 | 0.150985
32_04.09 | verdieping | 210 | 2600 | 2760 | 7.176 | 0.227562
32_04.08 | verdieping | 125 | 2600 | 3295 | 8.567 | 0.241705
2 x 31_merk-BD1 | verdieping | 430 | 1800 | 3795 | 6.831 | 0.0870208
2 x 31_merk-BD2 | verdieping | 430 | 1800 | 2805 | 5.049 | 0.0571685
31_merk-BD3 | verdieping | 430 | 1800 | 3100 | 5.58 | 0.0816165
31_merk-BD4 | verdieping | 430 | 1800 | 3795 | 6.831 | 0.0648667
32_- | verdieping | 210 | 2680 | 2100 | 5.628 | 0
31_merk-BC1 | verdieping | 430 | 1800 | 2725 | 4.905 | 0.0565464
31_merk-BC2 | verdieping | 430 | 1800 | 3575 | 6.435 | 0.0853101
2 x 31_merk-BB1 | verdieping | 430 | 1800 | 2625 | 4.725 | 0.0557688
2 x 31_merk-BB2 | verdieping | 430 | 1800 | 3475 | 6.255 | 0.0845325
32_- | verdieping | 210 | 2680 | 1400 | 3.752 | 0
2 x 32_- | verdieping | 100 | 2600 | 2675 | 6.955 | 0
32_04.01 | verdieping | 210 | 2670 | 2100 | 5.607 | 0.168524
32_merk-BN | verdieping | 62 | 3920 | 2278 | 8.89226 | 0.0909315
32_merk-BO | verdieping | 112 | 3920 | 1400 | 5.48134 | 0.180127
3 x 31_merk-BA1 | verdieping | 430 | 1800 | 3575 | 6.435 | 0.0853101
3 x 31_merk-BA2 | verdieping | 430 | 1800 | 2725 | 4.905 | 0.0565464
32_- | verdieping | 125 | 0 | 0 | 0 | 0

# IfcPlate: 24 Hout gevelbekleding Lariks master 25, 72_73 vaste inrichting
In: begane grond
Type - PredefinedType: SHEET
Classification: Blad (ARCHICAD Classification); 72.0 algemeen (NL/SfB (4 cijfers)); Material: 24 Hout gevelbekleding Lariks master
CPset_Phasing - Renovation Phase: Bestaand
Pset_PlateCommon - LoadBearing: yes; IsExternal: yes
BaseQuantities - Width: 25 mm; Perimeter: 3888 mm; GrossArea: 0.52488 m2; NetArea: 0.52488 m2; GrossVolume: 0.013122 m3; NetVolume: 0.013122 m3
Component Quantities - 24 Hout gevelbekleding Lariks master, Mass: 8.5293 kg; 24 Hout gevelbekleding Lariks master, Projected Component Area (Net): 0.52488 m2; 24 Hout gevelbekleding Lariks master, Projected Component Area (Gross): 0.52488 m2; 24 Hout gevelbekleding Lariks master, Component Thickness: 25 mm; 24 Hout gevelbekleding Lariks master, Component Volume (Net): 0.013122 m3; 24 Hout gevelbekleding Lariks master, Component Volume (Gross): 0.013122 m3

# IfcPlate: 42 vensterbank 15 (3)
In: verdieping
Type - PredefinedType: SHEET
Classification: Blad (ARCHICAD Classification); 72.0 algemeen (NL/SfB (4 cijfers)); Material: 42 vensterbank
CPset_Phasing - Renovation Phase: Bestaand
Pset_PlateCommon - LoadBearing: yes; IsExternal: yes
BaseQuantities - Width: 15 mm
Component Quantities - 42 vensterbank, Component Thickness: 15 mm
Name | Perimeter (mm) | GrossArea (m2) | NetArea (m2) = 42 vensterbank, Projected Component Area (Net) (m2) = 42 vensterbank, Projected Component Area (Gross) (m2) | GrossVolume (m3) | NetVolume (m3) = 42 vensterbank, Component Volume (Net) (m3) = 42 vensterbank, Component Volume (Gross) (m3) | 42 vensterbank, Mass (kg)
2 x 72_73 vaste inrichting | 11780 | 0.833025 | 0.833025 | 0.0124954 | 0.0124954 | 19.9926
72_73 vaste inrichting | 18200.1 | 1.50048 | 1.49441 | 0.0225072 | 0.0224162 | 35.8659

# IfcPlate: ALG - LICHTE SCHEIDINGSWAND - master 1700 (10)
In: verdieping
Type - PredefinedType: SHEET
Classification: Blad (ARCHICAD Classification); 72.0 algemeen (NL/SfB (4 cijfers)); Material: ALG - LICHTE SCHEIDINGSWAND - master
CPset_Phasing - Renovation Phase: Bestaand
Pset_PlateCommon - LoadBearing: yes; IsExternal: yes
BaseQuantities - Width: 1700 mm
Component Quantities - ALG - LICHTE SCHEIDINGSWAND - master, Component Thickness: 1700 mm
Name | Perimeter (mm) | GrossArea (m2) | NetArea (m2) = ALG - LICHTE SCHEIDINGSWAND - master, Projected Component Area (Net) (m2) = ALG - LICHTE SCHEIDINGSWAND - master, Projected Component Area (Gross) (m2) | GrossVolume (m3) | NetVolume (m3) = ALG - LICHTE SCHEIDINGSWAND - master, Component Volume (Net) (m3) = ALG - LICHTE SCHEIDINGSWAND - master, Component Volume (Gross) (m3) | ALG - LICHTE SCHEIDINGSWAND - master, Mass (kg)
72_72 vaste inrichting | 500 | 0.01 | 0.01 | 0.017 | 0.017 | 13.6
72_73 vaste inrichting | 500 | 0.01 | 0.01 | 0.017 | 0.017 | 13.6
72_74 vaste inrichting | 500 | 0.01 | 0.01 | 0.017 | 0.017 | 13.6
72_75 vaste inrichting | 500 | 0.01 | 0.01 | 0.017 | 0.017 | 13.6
2 x 72_72 vaste inrichting | 1000 | 0.0625 | 0.04 | 0.10625 | 0.068 | 54.4
4 x 72_72 vaste inrichting | 780 | 0.038 | 0.0155 | 0.0646 | 0.02635 | 21.08

# IfcPlate: ALG - LICHTE SCHEIDINGSWAND - master 1835, 72_72 vaste inrichting
In: verdieping
Type - PredefinedType: SHEET
Classification: Blad (ARCHICAD Classification); 72.0 algemeen (NL/SfB (4 cijfers)); Material: ALG - LICHTE SCHEIDINGSWAND - master
CPset_Phasing - Renovation Phase: Bestaand
Pset_PlateCommon - LoadBearing: yes; IsExternal: yes
BaseQuantities - Width: 1835 mm; Perimeter: 17144 mm; GrossArea: 0.10272 m2; NetArea: 0.10272 m2; GrossVolume: 0.188491 m3; NetVolume: 0.188491 m3
Component Quantities - ALG - LICHTE SCHEIDINGSWAND - master, Mass: 150.793 kg; ALG - LICHTE SCHEIDINGSWAND - master, Projected Component Area (Net): 0.10272 m2; ALG - LICHTE SCHEIDINGSWAND - master, Projected Component Area (Gross): 0.10272 m2; ALG - LICHTE SCHEIDINGSWAND - master, Component Thickness: 1835 mm; ALG - LICHTE SCHEIDINGSWAND - master, Component Volume (Net): 0.188491 m3; ALG - LICHTE SCHEIDINGSWAND - master, Component Volume (Gross): 0.188491 m3

# IfcPlate: ALG - LICHTE SCHEIDINGSWAND - master 25 (17)
Type - PredefinedType: SHEET
Classification: Blad (ARCHICAD Classification); 72.0 algemeen (NL/SfB (4 cijfers)); Material: ALG - LICHTE SCHEIDINGSWAND - master
CPset_Phasing - Renovation Phase: Bestaand
Pset_PlateCommon - LoadBearing: yes; IsExternal: yes
BaseQuantities - Width: 25 mm
Component Quantities - ALG - LICHTE SCHEIDINGSWAND - master, Component Thickness: 25 mm
Name | In | Perimeter (mm) | GrossArea (m2) = ALG - LICHTE SCHEIDINGSWAND - master, Projected Component Area (Gross) (m2) | NetArea (m2) = ALG - LICHTE SCHEIDINGSWAND - master, Projected Component Area (Net) (m2) | GrossVolume (m3) = ALG - LICHTE SCHEIDINGSWAND - master, Component Volume (Gross) (m3) | NetVolume (m3) = ALG - LICHTE SCHEIDINGSWAND - master, Component Volume (Net) (m3) | ALG - LICHTE SCHEIDINGSWAND - master, Mass (kg)
13 x 72_73 vaste inrichting | begane grond | 3468 | 0.18468 | 0.18468 | 0.004617 | 0.004617 | 3.6936
72_72 vaste inrichting | verdieping | 57600 | 5.41202 | 5.36702 | 0.1353 | 0.134175 | 107.34
72_72 vaste inrichting | verdieping | 18430 | 0.45825 | 0.45825 | 0.0114563 | 0.0114563 | 9.165
72_72 vaste inrichting | verdieping | 18430 | 0.458249 | 0.458249 | 0.0114562 | 0.0114562 | 9.16498
72_72 vaste inrichting | verdieping | 17220 | 0.428008 | 0.428008 | 0.0107002 | 0.0107002 | 8.56017

# IfcPlate: ALG - LICHTE SCHEIDINGSWAND - master 2600 (12)
Type - PredefinedType: SHEET
Classification: Blad (ARCHICAD Classification); 72.0 algemeen (NL/SfB (4 cijfers)); Material: ALG - LICHTE SCHEIDINGSWAND - master
CPset_Phasing - Renovation Phase: Bestaand
Pset_PlateCommon - LoadBearing: yes; IsExternal: yes
BaseQuantities - Width: 2600 mm
Component Quantities - ALG - LICHTE SCHEIDINGSWAND - master, Component Thickness: 2600 mm
Name | In | Perimeter (mm) | GrossArea (m2) = NetArea (m2) | GrossVolume (m3) = NetVolume (m3) = ALG - LICHTE SCHEIDINGSWAND - master, Component Volume (Net) (m3) = ALG - LICHTE SCHEIDINGSWAND - master, Component Volume (Gross) (m3) | ALG - LICHTE SCHEIDINGSWAND - master, Mass (kg) | ALG - LICHTE SCHEIDINGSWAND - master, Projected Component Area (Net) (m2) = ALG - LICHTE SCHEIDINGSWAND - master, Projected Component Area (Gross) (m2)
4 x 72_72 vaste inrichting | begane grond | 1961 | 0.0121 | 0.03146 | 25.168 | 0.0121
72_73 vaste inrichting | begane grond | 4210 | 0.0251159 | 0.0652896 | 52.2317 | 0.0251159
72_72 vaste inrichting | begane grond | 4210 | 0.025116 | 0.0652897 | 52.2318 | 0.0251159
2 x 72_72 vaste inrichting | begane grond | 11478 | 0.0687653 | 0.17879 | 143.032 | 0.0687653
3 x 72_72 vaste inrichting | verdieping | 1961 | 0.0121 | 0.03146 | 25.168 | 0.0121
72_72 vaste inrichting | verdieping | 1960 | 0.011616 | 0.0302016 | 24.1613 | 0.011616

# IfcPlate: ALG - LICHTE SCHEIDINGSWAND - master 3000 (2)
In: begane grond
Type - PredefinedType: SHEET
Classification: Blad (ARCHICAD Classification); 72.0 algemeen (NL/SfB (4 cijfers)); Material: ALG - LICHTE SCHEIDINGSWAND - master
CPset_Phasing - Renovation Phase: Bestaand
Pset_PlateCommon - LoadBearing: yes; IsExternal: yes
BaseQuantities - Width: 3000 mm; Perimeter: 1960 mm
Component Quantities - ALG - LICHTE SCHEIDINGSWAND - master, Mass: 29.025 kg; ALG - LICHTE SCHEIDINGSWAND - master, Component Thickness: 3000 mm
Name | GrossArea (m2) = NetArea (m2) = ALG - LICHTE SCHEIDINGSWAND - master, Projected Component Area (Net) (m2) = ALG - LICHTE SCHEIDINGSWAND - master, Projected Component Area (Gross) (m2) | GrossVolume (m3) = NetVolume (m3) = ALG - LICHTE SCHEIDINGSWAND - master, Component Volume (Net) (m3) = ALG - LICHTE SCHEIDINGSWAND - master, Component Volume (Gross) (m3)
72_72 vaste inrichting | 0.0120938 | 0.0362813
72_72 vaste inrichting | 0.0120937 | 0.0362812

# IfcPlate: ALG - LICHTE SCHEIDINGSWAND - master 590 (2)
In: begane grond
Type - PredefinedType: SHEET
Classification: Blad (ARCHICAD Classification); 72.0 algemeen (NL/SfB (4 cijfers)); Material: ALG - LICHTE SCHEIDINGSWAND - master
CPset_Phasing - Renovation Phase: Bestaand
Pset_PlateCommon - LoadBearing: yes; IsExternal: yes
BaseQuantities - Width: 590 mm; Perimeter: 3324 mm; GrossArea: 0.0198 m2; NetArea: 0.0198 m2; GrossVolume: 0.011682 m3; NetVolume: 0.011682 m3
Component Quantities - ALG - LICHTE SCHEIDINGSWAND - master, Mass: 9.3456 kg; ALG - LICHTE SCHEIDINGSWAND - master, Projected Component Area (Net): 0.0198 m2; ALG - LICHTE SCHEIDINGSWAND - master, Projected Component Area (Gross): 0.0198 m2; ALG - LICHTE SCHEIDINGSWAND - master, Component Thickness: 590 mm; ALG - LICHTE SCHEIDINGSWAND - master, Component Volume (Net): 0.011682 m3; ALG - LICHTE SCHEIDINGSWAND - master, Component Volume (Gross): 0.011682 m3

# IfcPlate: ALG - LICHTE SCHEIDINGSWAND - master 875, 72_72 vaste inrichting
In: verdieping
Type - PredefinedType: SHEET
Classification: Blad (ARCHICAD Classification); 72.0 algemeen (NL/SfB (4 cijfers)); Material: ALG - LICHTE SCHEIDINGSWAND - master
CPset_Phasing - Renovation Phase: Bestaand
Pset_PlateCommon - LoadBearing: yes; IsExternal: yes
BaseQuantities - Width: 875 mm; Perimeter: 55956 mm; GrossArea: 0.335591 m2; NetArea: 0.335591 m2; GrossVolume: 0.293642 m3; NetVolume: 0.293642 m3
Component Quantities - ALG - LICHTE SCHEIDINGSWAND - master, Mass: 234.914 kg; ALG - LICHTE SCHEIDINGSWAND - master, Projected Component Area (Net): 0.335591 m2; ALG - LICHTE SCHEIDINGSWAND - master, Projected Component Area (Gross): 0.335591 m2; ALG - LICHTE SCHEIDINGSWAND - master, Component Thickness: 875 mm; ALG - LICHTE SCHEIDINGSWAND - master, Component Volume (Net): 0.293642 m3; ALG - LICHTE SCHEIDINGSWAND - master, Component Volume (Gross): 0.293642 m3

# IfcPlate: Hout - Lockers 1075 (3)
In: begane grond
Type - PredefinedType: SHEET
Classification: Blad (ARCHICAD Classification); 72.0 algemeen (NL/SfB (4 cijfers)); Material: Hout - Lockers
CPset_Phasing - Renovation Phase: Bestaand
Pset_PlateCommon - LoadBearing: yes; IsExternal: yes
BaseQuantities - Width: 1075 mm; Perimeter: 6200 mm; GrossArea: 0.3 m2; NetArea: 0.3 m2; GrossVolume: 0.3225 m3; NetVolume: 0.3225 m3
Component Quantities - Hout - Lockers, Mass: 193.5 kg; Hout - Lockers, Projected Component Area (Net): 0.3 m2; Hout - Lockers, Projected Component Area (Gross): 0.3 m2; Hout - Lockers, Component Thickness: 1075 mm; Hout - Lockers, Component Volume (Net): 0.3225 m3; Hout - Lockers, Component Volume (Gross): 0.3225 m3

# IfcPlate: Hout - Lockers 1175 (19)
Type - PredefinedType: SHEET
Classification: Blad (ARCHICAD Classification); 72.0 algemeen (NL/SfB (4 cijfers)); Material: Hout - Lockers
CPset_Phasing - Renovation Phase: Bestaand
Pset_PlateCommon - LoadBearing: yes; IsExternal: yes
BaseQuantities - Width: 1175 mm
Component Quantities - Hout - Lockers, Component Thickness: 1175 mm
Name | In | Perimeter (mm) | GrossArea (m2) = NetArea (m2) = Hout - Lockers, Projected Component Area (Net) (m2) = Hout - Lockers, Projected Component Area (Gross) (m2) | GrossVolume (m3) = NetVolume (m3) = Hout - Lockers, Component Volume (Net) (m3) = Hout - Lockers, Component Volume (Gross) (m3) | Hout - Lockers, Mass (kg)
5 x 72_72 vaste inrichting | begane grond | 7525.14 | 0.0449609 | 0.052829 | 31.6974
2 x 72_72 vaste inrichting | begane grond | 1788 | 0.000893 | 0.00104927 | 0.629565
72_72 vaste inrichting | begane grond | 7122 | 0.00356 | 0.004183 | 2.5098
3 x 72_72 vaste inrichting | verdieping | 7340.97 | 0.043872 | 0.0515496 | 30.9298
72_72 vaste inrichting | verdieping | 7341 | 0.0438726 | 0.0515503 | 30.9302
72_72 vaste inrichting | verdieping | 7341.02 | 0.0438729 | 0.0515507 | 30.9304
2 x 72_72 vaste inrichting | verdieping | 9529.94 | 0.056976 | 0.0669468 | 40.1681
2 x 72_72 vaste inrichting | verdieping | 1810 | 0.010716 | 0.0125913 | 7.55478
2 x 72_72 vaste inrichting | verdieping | 844 | 0.0088 | 0.01034 | 6.204

# IfcPlate: Hout - Lockers 1178 (49)
Type - PredefinedType: SHEET
Classification: Blad (ARCHICAD Classification); 72.0 algemeen (NL/SfB (4 cijfers)); Material: Hout - Lockers
CPset_Phasing - Renovation Phase: Bestaand
Pset_PlateCommon - LoadBearing: yes; IsExternal: yes
BaseQuantities - Width: 1178 mm
Component Quantities - Hout - Lockers, Component Thickness: 1178 mm
Name | In | Perimeter (mm) | GrossArea (m2) = NetArea (m2) = Hout - Lockers, Projected Component Area (Net) (m2) = Hout - Lockers, Projected Component Area (Gross) (m2) | GrossVolume (m3) = NetVolume (m3) = Hout - Lockers, Component Volume (Net) (m3) = Hout - Lockers, Component Volume (Gross) (m3) | Hout - Lockers, Mass (kg)
5 x 72_72 vaste inrichting | begane grond | 1127.36 | 0.0116079 | 0.0136741 | 8.20446
5 x 72_72 vaste inrichting | begane grond | 1.99722 | 1.59431e-07 | 1.8781e-07 | 0.000112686
5 x 72_72 vaste inrichting | begane grond | 1127.44 | 0.0116087 | 0.013675 | 8.20499
2 x 72_72 vaste inrichting | begane grond | 454 | 0.003762 | 0.00443164 | 2.65898
2 x 72_72 vaste inrichting | begane grond | 880 | 0.009196 | 0.0108329 | 6.49973
2 x 72_72 vaste inrichting | begane grond | 992 | 0.010428 | 0.0122842 | 7.37051
4 x 72_72 vaste inrichting | begane grond | 884 | 0.00924 | 0.0108847 | 6.53083
6 x 72_72 vaste inrichting | verdieping | 1117.11 | 0.011704 | 0.0137873 | 8.27239
7 x 72_72 vaste inrichting | verdieping | 992 | 0.010428 | 0.0122842 | 7.37051
72_72 vaste inrichting | verdieping | 1116.57 | 0.0116184 | 0.0136865 | 8.21188
2 x 72_72 vaste inrichting | verdieping | 1008 | 0.008748 | 0.0103051 | 6.18309
2 x 72_72 vaste inrichting | verdieping | 1081.14 | 0.0113182 | 0.0133328 | 7.99967
2 x 72_72 vaste inrichting | verdieping | 844 | 0.0088 | 0.0103664 | 6.21984
2 x 72_72 vaste inrichting | verdieping | 454 | 0.003762 | 0.00443164 | 2.65898
2 x 72_72 vaste inrichting | verdieping | 880 | 0.009196 | 0.0108329 | 6.49973

# IfcPlate: Hout - Lockers 1200, 72_72 vaste inrichting
In: verdieping
Type - PredefinedType: SHEET
Classification: Blad (ARCHICAD Classification); 72.0 algemeen (NL/SfB (4 cijfers)); Material: Hout - Lockers
CPset_Phasing - Renovation Phase: Bestaand
Pset_PlateCommon - LoadBearing: yes; IsExternal: yes
BaseQuantities - Width: 1200 mm; Perimeter: 1405 mm; GrossArea: 0.032625 m2; NetArea: 0.032625 m2; GrossVolume: 0.03915 m3; NetVolume: 0.03915 m3
Component Quantities - Hout - Lockers, Mass: 23.49 kg; Hout - Lockers, Projected Component Area (Net): 0.032625 m2; Hout - Lockers, Projected Component Area (Gross): 0.032625 m2; Hout - Lockers, Component Thickness: 1200 mm; Hout - Lockers, Component Volume (Net): 0.03915 m3; Hout - Lockers, Component Volume (Gross): 0.03915 m3

# IfcPlate: Hout - Lockers 125 (3)
In: begane grond
Type - PredefinedType: SHEET
Classification: Blad (ARCHICAD Classification); 72.0 algemeen (NL/SfB (4 cijfers)); Material: Hout - Lockers
CPset_Phasing - Renovation Phase: Bestaand
Pset_PlateCommon - LoadBearing: yes; IsExternal: yes
BaseQuantities - Width: 125 mm; Perimeter: 5600 mm; GrossArea: 0.96 m2; NetArea: 0.96 m2; GrossVolume: 0.12 m3; NetVolume: 0.12 m3
Component Quantities - Hout - Lockers, Mass: 72 kg; Hout - Lockers, Projected Component Area (Net): 0.96 m2; Hout - Lockers, Projected Component Area (Gross): 0.96 m2; Hout - Lockers, Component Thickness: 125 mm; Hout - Lockers, Component Volume (Net): 0.12 m3; Hout - Lockers, Component Volume (Gross): 0.12 m3

# IfcPlate: Hout - Lockers 22 (20)
Type - PredefinedType: SHEET
Classification: Blad (ARCHICAD Classification); 72.0 algemeen (NL/SfB (4 cijfers)); Material: Hout - Lockers
CPset_Phasing - Renovation Phase: Bestaand
Pset_PlateCommon - LoadBearing: yes; IsExternal: yes
BaseQuantities - Width: 22 mm
Component Quantities - Hout - Lockers, Component Thickness: 22 mm
Name | In | Perimeter (mm) | GrossArea (m2) = NetArea (m2) = Hout - Lockers, Projected Component Area (Net) (m2) = Hout - Lockers, Projected Component Area (Gross) (m2) | GrossVolume (m3) = NetVolume (m3) = Hout - Lockers, Component Volume (Net) (m3) = Hout - Lockers, Component Volume (Gross) (m3) | Hout - Lockers, Mass (kg)
4 x 72_72 vaste inrichting | begane grond | 7840.3 | 1.5884 | 0.0349448 | 20.9669
72_72 vaste inrichting | begane grond | 7840.6 | 1.58895 | 0.0349569 | 20.9741
2 x 72_72 vaste inrichting | begane grond | 4564 | 0.78204 | 0.0172049 | 10.3229
2 x 72_72 vaste inrichting | begane grond | 6277 | 1.16211 | 0.0255663 | 15.3398
2 x 72_72 vaste inrichting | verdieping | 8265 | 1.72297 | 0.0379052 | 22.7431
72_72 vaste inrichting | verdieping | 8264.78 | 1.72292 | 0.0379041 | 22.7425
2 x 72_72 vaste inrichting | verdieping | 8265 | 1.72297 | 0.0379054 | 22.7432
72_72 vaste inrichting | verdieping | 4537 | 0.845959 | 0.0186111 | 11.1667
72_72 vaste inrichting | verdieping | 6865 | 1.39362 | 0.0306597 | 18.3958
72_72 vaste inrichting | verdieping | 4422 | 0.818905 | 0.0180159 | 10.8095
72_72 vaste inrichting | verdieping | 6940 | 1.41126 | 0.0310478 | 18.6287
2 x 72_72 vaste inrichting | verdieping | 6284 | 1.16523 | 0.0256351 | 15.3811

# IfcPlate: Hout - Lockers 25 (15)
Type - PredefinedType: SHEET
Classification: Blad (ARCHICAD Classification); 72.0 algemeen (NL/SfB (4 cijfers)); Material: Hout - Lockers
CPset_Phasing - Renovation Phase: Bestaand
Pset_PlateCommon - LoadBearing: yes; IsExternal: yes
BaseQuantities - Width: 25 mm
Component Quantities - Hout - Lockers, Component Thickness: 25 mm
Name | In | Perimeter (mm) | GrossArea (m2) = NetArea (m2) = Hout - Lockers, Projected Component Area (Net) (m2) = Hout - Lockers, Projected Component Area (Gross) (m2) | GrossVolume (m3) = NetVolume (m3) = Hout - Lockers, Component Volume (Net) (m3) = Hout - Lockers, Component Volume (Gross) (m3) | Hout - Lockers, Mass (kg)
2 x 72_72 vaste inrichting | begane grond | 7436 | 0.205072 | 0.0051268 | 3.07608
72_72 vaste inrichting | begane grond | 1891 | 0.0468825 | 0.00117206 | 0.703238
72_72 vaste inrichting | begane grond | 7429 | 0.192255 | 0.00480637 | 2.88382
72_72 vaste inrichting | begane grond | 1898 | 0.050008 | 0.0012502 | 0.75012
72_72 vaste inrichting | begane grond | 7225 | 0.1869 | 0.0046725 | 2.8035
4 x 72_72 vaste inrichting | verdieping | 7429 | 0.192255 | 0.00480637 | 2.88382
72_72 vaste inrichting | verdieping | 1891 | 0.0468825 | 0.00117206 | 0.703238
72_72 vaste inrichting | verdieping | 1898 | 0.050008 | 0.0012502 | 0.75012
72_72 vaste inrichting | verdieping | 9632 | 0.26656 | 0.006664 | 3.9984
72_72 vaste inrichting | verdieping | 9625 | 0.2499 | 0.00624751 | 3.7485
72_72 vaste inrichting | verdieping | 7232 | 0.19936 | 0.004984 | 2.9904

# IfcPlate: Hout AFW 38 (2)
In: verdieping
Type - PredefinedType: SHEET
Classification: Blad (ARCHICAD Classification); 72.0 algemeen (NL/SfB (4 cijfers)); Material: Hout AFW
CPset_Phasing - Renovation Phase: Bestaand
Pset_PlateCommon - LoadBearing: yes; IsExternal: yes
BaseQuantities - Width: 38 mm
Component Quantities - Hout AFW, Component Thickness: 38 mm
Name | Perimeter (mm) | GrossArea (m2) | NetArea (m2) | GrossVolume (m3) | NetVolume (m3) = Hout AFW, Component Volume (Net) (m3) = Hout AFW, Component Volume (Gross) (m3) | Hout AFW, Mass (kg) | Hout AFW, Projected Component Area (Net) (m2) = Hout AFW, Projected Component Area (Gross) (m2)
72_73 vaste inrichting | 8126 | 1.96168 | 1.92995 | 0.0745958 | 0.07339 | 40.3645 | 1.93255
72_72 vaste inrichting | 8740 | 0.8736 | 0.8736 | 0.0331968 | 0.0331968 | 18.2582 | 0.8736

# IfcRailing: Railing Type (4)
Classification: Reling (ARCHICAD Classification)
CPset_Phasing - Renovation Phase: Bestaand
Pset_RailingCommon - IsExternal: no
Name | In | GrossVolume (m3) = NetVolume (m3) | Length (mm)
_Reling-x | begane grond | 0.0155431 | 7879.06
_Reling-x | begane grond | 0.0155427 | 7873.84
_Reling-x | begane grond | 0.0201607 | 1475
_Reling-x | verdieping | 0.085372 | 11045.9

# IfcRoof (30)
Classification: Dak (ARCHICAD Classification); 27.22 hellende daken (NL/SfB (4 cijfers))
Pset_RoofCommon - IsExternal: yes
CPset_Phasing - Renovation Phase: Bestaand
Name | In | Material | TotalArea (m2) = TotalSurfaceArea (m2)
4 x 27_Dak-x | begane grond | Metaal - Staal C wit | 0.00123217 | Component Quantities - Metaal - Staal C wit, Mass: 0.685705 kg; Metaal - Staal C wit, Projected Component Area (Net): 0.00425574 m2; Metaal - Staal C wit, Projected Component Area (Gross): 0.00425574 m2; Metaal - Staal C wit, Component Thickness: 70 mm; Metaal - Staal C wit, Component Volume (Net): 0.0000862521 m3; Metaal - Staal C wit, Component Volume (Gross): 0.0000862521 m3
27_Dak-x | verdieping | Isolatie - Kunststof hard afschot | 81.5402 | Component Quantities - Isolatie - Kunststof hard afschot, Mass: 1630.8 kg; Isolatie - Kunststof hard afschot, Projected Component Area (Net): 81.5792 m2; Isolatie - Kunststof hard afschot, Projected Component Area (Gross): 81.5792 m2; Isolatie - Kunststof hard afschot, Component Thickness: 200 mm; Isolatie - Kunststof hard afschot, Component Volume (Net): 16.308 m3; Isolatie - Kunststof hard afschot, Component Volume (Gross): 16.308 m3
27_Dak-x | verdieping | Isolatie - Kunststof hard afschot | 84.7236 | Component Quantities - Isolatie - Kunststof hard afschot, Mass: 1694.47 kg; Isolatie - Kunststof hard afschot, Projected Component Area (Net): 84.7626 m2; Isolatie - Kunststof hard afschot, Projected Component Area (Gross): 84.7626 m2; Isolatie - Kunststof hard afschot, Component Thickness: 200 mm; Isolatie - Kunststof hard afschot, Component Volume (Net): 16.9447 m3; Isolatie - Kunststof hard afschot, Component Volume (Gross): 16.9447 m3
4 x 27_Dak-x | techniek | Glas | 2.61632 | Component Quantities - Glas, Mass: 199.625 kg; Glas, Projected Component Area (Net): 2.61632 m2; Glas, Projected Component Area (Gross): 2.61632 m2; Glas, Component Thickness: 35 mm; Glas, Component Volume (Net): 0.0915711 m3; Glas, Component Volume (Gross): 0.0915711 m3
27_Dak-x | techniek | Isolatie - Kunststof zacht | 2.99533 | Component Quantities - Isolatie - Kunststof zacht, Mass: 65.9489 kg; Isolatie - Kunststof zacht, Projected Component Area (Net): 7.75026 m2; Isolatie - Kunststof zacht, Projected Component Area (Gross): 19.6425 m2; Isolatie - Kunststof zacht, Component Thickness: 800 mm; Isolatie - Kunststof zacht, Component Volume (Net): 3.29745 m3; Isolatie - Kunststof zacht, Component Volume (Gross): 13.812 m3
2 x 27_Dak-x | techniek | Glas | 3.03783 | Component Quantities - Glas, Mass: 231.786 kg; Glas, Projected Component Area (Net): 3.03783 m2; Glas, Projected Component Area (Gross): 3.03783 m2; Glas, Component Thickness: 35 mm; Glas, Component Volume (Net): 0.106324 m3; Glas, Component Volume (Gross): 0.106324 m3
27_Dak-x | techniek | Glas | 3.10559 | Component Quantities - Glas, Mass: 236.956 kg; Glas, Projected Component Area (Net): 3.10559 m2; Glas, Projected Component Area (Gross): 3.10559 m2; Glas, Component Thickness: 35 mm; Glas, Component Volume (Net): 0.108696 m3; Glas, Component Volume (Gross): 0.108696 m3
27_Dak-x | techniek | Glas | 3.15829 | Component Quantities - Glas, Mass: 240.977 kg; Glas, Projected Component Area (Net): 3.15829 m2; Glas, Projected Component Area (Gross): 3.15829 m2; Glas, Component Thickness: 35 mm; Glas, Component Volume (Net): 0.11054 m3; Glas, Component Volume (Gross): 0.11054 m3
4 x 27_Dak-x | techniek | Glas | 3.13194 | Component Quantities - Glas, Mass: 238.967 kg; Glas, Projected Component Area (Net): 3.13194 m2; Glas, Projected Component Area (Gross): 3.13194 m2; Glas, Component Thickness: 35 mm; Glas, Component Volume (Net): 0.109618 m3; Glas, Component Volume (Gross): 0.109618 m3
27_Dak-x | techniek | Isolatie - Kunststof zacht | 3.55367 | Component Quantities - Isolatie - Kunststof zacht, Mass: 40.5927 kg; Isolatie - Kunststof zacht, Projected Component Area (Net): 4.72402 m2; Isolatie - Kunststof zacht, Projected Component Area (Gross): 31.9664 m2; Isolatie - Kunststof zacht, Component Thickness: 1085.06 mm; Isolatie - Kunststof zacht, Component Volume (Net): 2.02964 m3; Isolatie - Kunststof zacht, Component Volume (Gross): 33.7504 m3
27_Dak-x | techniek | 47 Dakbedekking | 126.162 | Component Quantities - 47 Dakbedekking, Mass: 0 kg; 47 Dakbedekking, Projected Component Area (Net): 126.163 m2; 47 Dakbedekking, Projected Component Area (Gross): 126.163 m2; 47 Dakbedekking, Component Thickness: 2.99966 mm; 47 Dakbedekking, Component Volume (Net): 0.378445 m3; 47 Dakbedekking, Component Volume (Gross): 0.378445 m3
27_Dak-x | techniek | 47 Dakbedekking | 51.1256 | Component Quantities - 47 Dakbedekking, Mass: 0 kg; 47 Dakbedekking, Projected Component Area (Net): 51.1257 m2; 47 Dakbedekking, Projected Component Area (Gross): 51.1257 m2; 47 Dakbedekking, Component Thickness: 2.99966 mm; 47 Dakbedekking, Component Volume (Net): 0.15336 m3; 47 Dakbedekking, Component Volume (Gross): 0.15336 m3
27_Dak-x | techniek | 47 Dakbedekking | 239.713 | Component Quantities - 47 Dakbedekking, Mass: 0 kg; 47 Dakbedekking, Projected Component Area (Net): 239.714 m2; 47 Dakbedekking, Projected Component Area (Gross): 239.714 m2; 47 Dakbedekking, Component Thickness: 2.99966 mm; 47 Dakbedekking, Component Volume (Net): 0.719058 m3; 47 Dakbedekking, Component Volume (Gross): 0.719058 m3
27_Dak-x | techniek | 47 Dakbedekking | 34.5559 | Component Quantities - 47 Dakbedekking, Mass: 0 kg; 47 Dakbedekking, Projected Component Area (Net): 34.556 m2; 47 Dakbedekking, Projected Component Area (Gross): 34.556 m2; 47 Dakbedekking, Component Thickness: 2.99966 mm; 47 Dakbedekking, Component Volume (Net): 0.103656 m3; 47 Dakbedekking, Component Volume (Gross): 0.103656 m3
27_Dak-x | techniek | 47 Dakbedekking | 51.1267 | Component Quantities - 47 Dakbedekking, Mass: 0 kg; 47 Dakbedekking, Projected Component Area (Net): 51.127 m2; 47 Dakbedekking, Projected Component Area (Gross): 51.127 m2; 47 Dakbedekking, Component Thickness: 2.99966 mm; 47 Dakbedekking, Component Volume (Net): 0.153363 m3; 47 Dakbedekking, Component Volume (Gross): 0.153363 m3
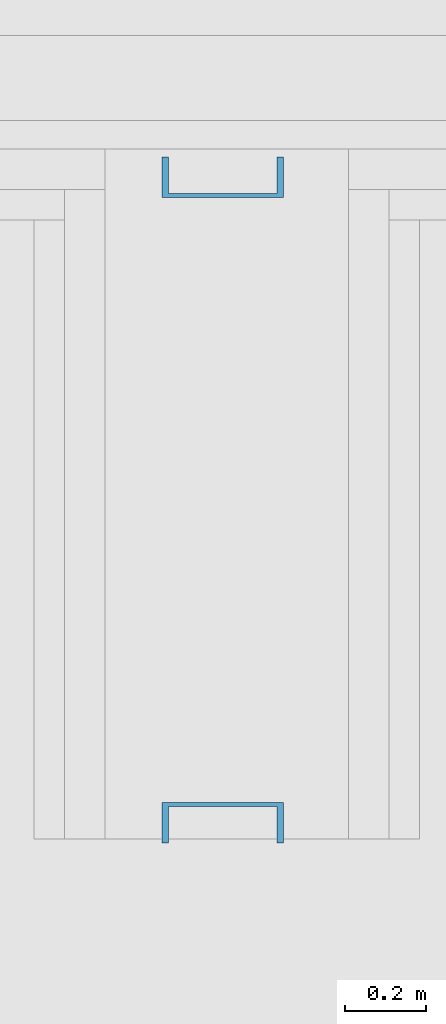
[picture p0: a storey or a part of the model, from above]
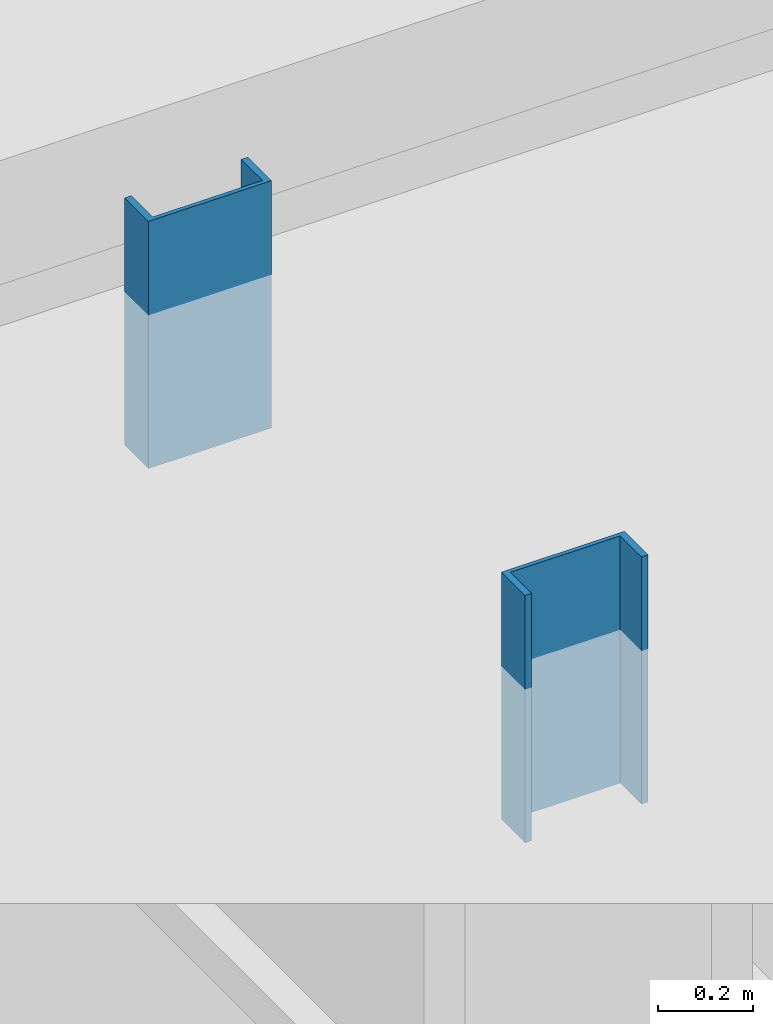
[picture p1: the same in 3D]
Properties of the parts of a building model (IFC2X3), part 7 of 9

# IfcRoof (30)
Name | In | Material | TotalArea (m2) = TotalSurfaceArea (m2)
27_Dak-x | techniek | 47 Dakbedekking | 147.425 | Component Quantities - 47 Dakbedekking, Mass: 0 kg; 47 Dakbedekking, Projected Component Area (Net): 147.426 m2; 47 Dakbedekking, Projected Component Area (Gross): 147.426 m2; 47 Dakbedekking, Component Thickness: 2.99966 mm; 47 Dakbedekking, Component Volume (Net): 0.442224 m3; 47 Dakbedekking, Component Volume (Gross): 0.442224 m3
27_Dak-x | techniek | 47 Dakbedekking | 162.256 | Component Quantities - 47 Dakbedekking, Mass: 0 kg; 47 Dakbedekking, Projected Component Area (Net): 162.257 m2; 47 Dakbedekking, Projected Component Area (Gross): 162.257 m2; 47 Dakbedekking, Component Thickness: 2.99966 mm; 47 Dakbedekking, Component Volume (Net): 0.486714 m3; 47 Dakbedekking, Component Volume (Gross): 0.486714 m3
27_Dak-x | techniek | 47 Dakbedekking | 126.163 | Component Quantities - 47 Dakbedekking, Mass: 0 kg; 47 Dakbedekking, Projected Component Area (Net): 126.164 m2; 47 Dakbedekking, Projected Component Area (Gross): 126.164 m2; 47 Dakbedekking, Component Thickness: 2.99966 mm; 47 Dakbedekking, Component Volume (Net): 0.378447 m3; 47 Dakbedekking, Component Volume (Gross): 0.378447 m3
27_Dak-x | techniek | 47 Dakbedekking | 22.4025 | Component Quantities - 47 Dakbedekking, Mass: 0 kg; 47 Dakbedekking, Projected Component Area (Net): 22.4025 m2; 47 Dakbedekking, Projected Component Area (Gross): 22.4025 m2; 47 Dakbedekking, Component Thickness: 2.99966 mm; 47 Dakbedekking, Component Volume (Net): 0.0672 m3; 47 Dakbedekking, Component Volume (Gross): 0.0672 m3
27_Dak-x | techniek | 47 Dakbedekking | 282.452 | Component Quantities - 47 Dakbedekking, Mass: 0 kg; 47 Dakbedekking, Projected Component Area (Net): 282.453 m2; 47 Dakbedekking, Projected Component Area (Gross): 282.453 m2; 47 Dakbedekking, Component Thickness: 2.99966 mm; 47 Dakbedekking, Component Volume (Net): 0.847259 m3; 47 Dakbedekking, Component Volume (Gross): 0.847259 m3

# IfcSlab: 23 kanaalplaat + cmd 320+80 400 (12)
In: verdieping
Classification: Vloer (ARCHICAD Classification); 23.21 vrijdragende vloeren (NL/SfB (4 cijfers))
CPset_Phasing - Renovation Phase: Bestaand
Pset_SlabCommon - LoadBearing: yes; IsExternal: yes
BaseQuantities - Width: 400 mm
Name | Perimeter (mm) | GrossArea (m2) | NetArea (m2) | GrossVolume (m3) | NetVolume (m3)
23_23 VBI 260 + druklaag | 9250 | 4.99065 | 3.97978 | 2.31974 | 1.91539
23_23 VBI 260 + druklaag | 11920 | 8.8755 | 8.113 | 3.7942 | 3.4892
23_23 VBI 260 + druklaag | 11790 | 8.64725 | 7.83244 | 3.71964 | 3.39372
23_23 VBI 260 + druklaag | 36049 | 81.0507 | 81.0507 | 32.4203 | 32.4203
23_23 VBI 260 + druklaag | 40720 | 102.355 | 100.572 | 41.5129 | 40.7995
23_23 VBI 260 + druklaag | 11790 | 8.64725 | 7.875 | 3.70602 | 3.39712
23_23 VBI 260 + druklaag | 92194 | 385.722 | 380.304 | 156.022 | 153.855
23_23 VBI 260 + druklaag | 74394 | 289.252 | 287.759 | 116.179 | 115.582
23_23 VBI 260 + druklaag | 45871.2 | 83.162 | 82.2978 | 33.5405 | 33.1948
23_23 VBI 260 + druklaag | 47670.5 | 115.274 | 115.147 | 46.15 | 46.0993
23_23 VBI 260 + druklaag | 29880 | 33.9729 | 32.1609 | 14.169 | 13.4442
23_breedplaatvloer | 26760 | 25.2197 | 22.7032 | 10.1667 | 9.16005

# IfcSlab: 23 kanaalplaat + cmd 320+80 aanstorting 400 (6)
In: verdieping
Classification: Vloer (ARCHICAD Classification); 23.21 vrijdragende vloeren (NL/SfB (4 cijfers))
CPset_Phasing - Renovation Phase: Bestaand
Pset_SlabCommon - LoadBearing: yes; IsExternal: yes
BaseQuantities - Width: 400 mm
Name | Perimeter (mm) | GrossArea (m2) | NetArea (m2) | GrossVolume (m3) | NetVolume (m3)
23_23 VBI 260 + druklaag | 111606 | 24.187 | 15.6395 | 12.4118 | 8.99278
23_23 VBI 260 + druklaag | 17800 | 2.58 | 1.8996 | 1.24973 | 0.977568
23_23 VBI 260 + druklaag | 55340 | 5.1936 | 0.582405 | 3.54697 | 1.70249
23_23 VBI 260 + druklaag | 53020 | 9.41395 | 5.44387 | 5.03601 | 3.44797
23_23 VBI 260 + druklaag | 70284 | 12.5215 | 7.17039 | 6.72111 | 4.58066
23_23 VBI 260 + druklaag | 5610 | 0.533 | 0.492 | 0.22632 | 0.20992

# IfcSlab: 23 kanaalplaat + cmd 320-80 320 (8)
Classification: Vloer (ARCHICAD Classification); 23.21 vrijdragende vloeren (NL/SfB (4 cijfers)); Material: Beton gewapend prefab vloer
CPset_Phasing - Renovation Phase: Bestaand
Pset_SlabCommon - LoadBearing: yes; IsExternal: yes
BaseQuantities - Width: 320 mm; GrossArea: 0 m2; NetArea: 0 m2
Component Quantities - Beton gewapend prefab vloer, Component Thickness: 320 mm
Name | In | Perimeter (mm) | GrossVolume (m3) = NetVolume (m3) = Beton gewapend prefab vloer, Component Volume (Net) (m3) | Beton gewapend prefab vloer, Mass (kg) | Beton gewapend prefab vloer, Projected Component Area (Net) (m2) | Beton gewapend prefab vloer, Projected Component Area (Gross) (m2) | Beton gewapend prefab vloer, Component Volume (Gross) (m3)
23_23 VBI 260 + druklaag | verdieping | 39578.8 | 27.6217 | 66292 | 86.3177 | 86.3177 | 27.6217
23_23 VBI 260 + druklaag | verdieping | 40079.5 | 28.6954 | 68869 | 89.6732 | 89.6732 | 28.6954
23_23 VBI 260 + druklaag | techniek | 47170 | 36.0541 | 86529.9 | 112.669 | 112.669 | 36.0541
23_23 VBI 260 + druklaag | techniek | 26030 | 12.1501 | 29160.2 | 37.969 | 37.969 | 12.1501
23_23 VBI 260 + druklaag | techniek | 90954 | 120.876 | 290103 | 377.738 | 377.738 | 120.876
23_23 VBI 260 + druklaag | techniek | 102804 | 131.711 | 316107 | 411.598 | 411.598 | 131.711
23_23 VBI 260 + druklaag | techniek | 73354 | 67.9362 | 163047 | 212.301 | 241.462 | 77.2679
23_23 VBI 260 + druklaag | techniek | 30510 | 18.194 | 43665.5 | 56.8562 | 56.8562 | 18.194

# IfcSlab: 23 kanaalplaat + cmd 320-80 aanstorting 320, 23_23 VBI 260 + druklaag
In: techniek
Classification: Vloer (ARCHICAD Classification); 23.21 vrijdragende vloeren (NL/SfB (4 cijfers)); Material: Beton gewapend C vloer
CPset_Phasing - Renovation Phase: Bestaand
Pset_SlabCommon - LoadBearing: yes; IsExternal: yes
BaseQuantities - Width: 320 mm; Perimeter: 159614 mm; GrossArea: 1332.02 m2; NetArea: 43.5887 m2; GrossVolume: 426.246 m3; NetVolume: 13.9484 m3
Component Quantities - Beton gewapend C vloer, Mass: 33476.1 kg; Beton gewapend C vloer, Projected Component Area (Net): 43.5887 m2; Beton gewapend C vloer, Projected Component Area (Gross): 1332.02 m2; Beton gewapend C vloer, Component Thickness: 320 mm; Beton gewapend C vloer, Component Volume (Net): 13.9484 m3; Beton gewapend C vloer, Component Volume (Gross): 426.246 m3

# IfcSlab: 23 kanaaplaat VBI Rc 3,7 132mm 450 (2)
In: fundering
Classification: Vloer (ARCHICAD Classification); 23.21 vrijdragende vloeren (NL/SfB (4 cijfers))
CPset_Phasing - Renovation Phase: Bestaand
Pset_SlabCommon - LoadBearing: yes; IsExternal: yes
BaseQuantities - Width: 450 mm; Perimeter: 4300 mm; GrossArea: 0.3 m2; NetArea: 0 m2; GrossVolume: 0.249 m3; NetVolume: 0.114 m3
Name
23_23 VBI 260 Rc 3,8
23_23 VBI 260 Rc 3,7

# IfcSlab: 27 Overstek HSB 308, 23_dakisolatie
In: techniek
Classification: Vloer (ARCHICAD Classification); 23.21 vrijdragende vloeren (NL/SfB (4 cijfers))
CPset_Phasing - Renovation Phase: Bestaand
Pset_SlabCommon - LoadBearing: no; IsExternal: yes
BaseQuantities - Width: 308 mm; Perimeter: 116280 mm; GrossArea: 0 m2; NetArea: 0 m2; GrossVolume: 16.2647 m3; NetVolume: 16.2647 m3

# IfcSlab: 47 Dakbedekking 3 (4)
In: techniek
Classification: Vloer (ARCHICAD Classification); 23.21 vrijdragende vloeren (NL/SfB (4 cijfers)); Material: 47 Dakbedekking
CPset_Phasing - Renovation Phase: Bestaand
Pset_SlabCommon - LoadBearing: no; IsExternal: yes
BaseQuantities - Width: 3 mm
Component Quantities - 47 Dakbedekking, Mass: 0 kg; 47 Dakbedekking, Component Thickness: 3 mm
Name | Perimeter (mm) | GrossArea (m2) | NetArea (m2) = 47 Dakbedekking, Projected Component Area (Net) (m2) = 47 Dakbedekking, Projected Component Area (Gross) (m2) | GrossVolume (m3) | NetVolume (m3) = 47 Dakbedekking, Component Volume (Net) (m3) = 47 Dakbedekking, Component Volume (Gross) (m3)
23_dakisolatie | 9140 | 4.044 | 4.044 | 0.012132 | 0.012132
23_dakisolatie | 38600.1 | 21.7208 | 21.7208 | 0.0651624 | 0.0651624
23_dakisolatie | 65600 | 37.92 | 37.8075 | 0.11376 | 0.113423
23_dakisolatie | 65600 | 37.92 | 37.92 | 0.11376 | 0.11376

# IfcSlab: ALG - PREFAB 185, 23_23 VBI 261 + druklaag
In: begane grond
Classification: Vloer (ARCHICAD Classification); 23.21 vrijdragende vloeren (NL/SfB (4 cijfers)); Material: ALG - PREFAB
CPset_Phasing - Renovation Phase: Bestaand
Pset_SlabCommon - LoadBearing: no; IsExternal: yes
BaseQuantities - Width: 185 mm; Perimeter: 15134 mm; GrossArea: 5.98299 m2; NetArea: 5.97999 m2; GrossVolume: 1.10508 m3; NetVolume: 1.10453 m3
Component Quantities - ALG - PREFAB, Mass: 2540.41 kg; ALG - PREFAB, Projected Component Area (Net): 5.98299 m2; ALG - PREFAB, Projected Component Area (Gross): 5.98299 m2; ALG - PREFAB, Component Thickness: 185 mm; ALG - PREFAB, Component Volume (Net): 1.10453 m3; ALG - PREFAB, Component Volume (Gross): 1.10453 m3

# IfcSlab: Beton C 50, 23_dakisolatie
In: verdieping
Classification: Vloer (ARCHICAD Classification); 23.21 vrijdragende vloeren (NL/SfB (4 cijfers)); Material: Beton C
CPset_Phasing - Renovation Phase: Bestaand
Pset_SlabCommon - LoadBearing: no; IsExternal: yes
BaseQuantities - Width: 50 mm; Perimeter: 53586 mm; GrossArea: 179.213 m2; NetArea: 179.213 m2; GrossVolume: 8.96063 m3; NetVolume: 8.96063 m3
Component Quantities - Beton C, Mass: 21505.5 kg; Beton C, Projected Component Area (Net): 179.213 m2; Beton C, Projected Component Area (Gross): 179.213 m2; Beton C, Component Thickness: 50 mm; Beton C, Component Volume (Net): 8.96063 m3; Beton C, Component Volume (Gross): 8.96063 m3

# IfcSlab: Beton gewapend C 440 (2)
In: fundering
Classification: Vloer (ARCHICAD Classification); 23.21 vrijdragende vloeren (NL/SfB (4 cijfers)); Material: Beton gewapend C
CPset_Phasing - Renovation Phase: Bestaand
Pset_SlabCommon - LoadBearing: yes; IsExternal: yes
BaseQuantities - Width: 440 mm; Perimeter: 2400 mm; GrossArea: 0.36 m2; NetArea: 0.36 m2; GrossVolume: 0.1584 m3; NetVolume: 0.1584 m3
Component Quantities - Beton gewapend C, Mass: 364.32 kg; Beton gewapend C, Projected Component Area (Net): 0.36 m2; Beton gewapend C, Projected Component Area (Gross): 0.36 m2; Beton gewapend C, Component Thickness: 440 mm; Beton gewapend C, Component Volume (Net): 0.1584 m3; Beton gewapend C, Component Volume (Gross): 0.1584 m3

# IfcSlab: Beton gewapend C 60, 23_72 vaste inrichting
In: begane grond
Classification: Vloer (ARCHICAD Classification); 23.21 vrijdragende vloeren (NL/SfB (4 cijfers)); Material: Beton gewapend C
CPset_Phasing - Renovation Phase: Bestaand
Pset_SlabCommon - LoadBearing: no; IsExternal: yes
BaseQuantities - Width: 60 mm; Perimeter: 7429 mm; GrossArea: 0.192255 m2; NetArea: 0.192255 m2; GrossVolume: 0.0115353 m3; NetVolume: 0.0115353 m3
Component Quantities - Beton gewapend C, Mass: 26.5312 kg; Beton gewapend C, Projected Component Area (Net): 0.192255 m2; Beton gewapend C, Projected Component Area (Gross): 0.192255 m2; Beton gewapend C, Component Thickness: 60 mm; Beton gewapend C, Component Volume (Net): 0.0115353 m3; Beton gewapend C, Component Volume (Gross): 0.0115353 m3

# IfcSlab: Beton gewapend C vloer 320, 23_23 VBI 260 + druklaag
In: verdieping
Classification: Vloer (ARCHICAD Classification); 23.21 vrijdragende vloeren (NL/SfB (4 cijfers)); Material: Beton gewapend C vloer
CPset_Phasing - Renovation Phase: Bestaand
Pset_SlabCommon - LoadBearing: yes; IsExternal: yes
BaseQuantities - Width: 320 mm; Perimeter: 82200 mm; GrossArea: 14.6664 m2; NetArea: 14.6664 m2; GrossVolume: 4.69325 m3; NetVolume: 4.69325 m3
Component Quantities - Beton gewapend C vloer, Mass: 11263.8 kg; Beton gewapend C vloer, Projected Component Area (Net): 14.6664 m2; Beton gewapend C vloer, Projected Component Area (Gross): 14.6664 m2; Beton gewapend C vloer, Component Thickness: 320 mm; Beton gewapend C vloer, Component Volume (Net): 4.69325 m3; Beton gewapend C vloer, Component Volume (Gross): 4.69325 m3

# IfcSlab: Beton gewapend prefab 250 (2)
In: verdieping
Classification: Vloer (ARCHICAD Classification); 23.21 vrijdragende vloeren (NL/SfB (4 cijfers)); Material: Beton gewapend prefab
CPset_Phasing - Renovation Phase: Bestaand
Pset_SlabCommon - LoadBearing: yes; IsExternal: yes
BaseQuantities - Width: 250 mm
Component Quantities - Beton gewapend prefab, Component Thickness: 250 mm
Name | Perimeter (mm) | GrossArea (m2) = NetArea (m2) = Beton gewapend prefab, Projected Component Area (Net) (m2) = Beton gewapend prefab, Projected Component Area (Gross) (m2) | GrossVolume (m3) = NetVolume (m3) = Beton gewapend prefab, Component Volume (Net) (m3) = Beton gewapend prefab, Component Volume (Gross) (m3) | Beton gewapend prefab, Mass (kg)
23_23 VBI 260 + druklaag | 5400 | 1.8 | 0.45 | 1080
23_23 VBI 260 + druklaag | 8 | 0.000004 | 1e-06 | 0.0024

# IfcSlab: Hout AFW 180, 23_23 VBI 260 + druklaag
In: verdieping
Classification: Vloer (ARCHICAD Classification); 23.21 vrijdragende vloeren (NL/SfB (4 cijfers)); Material: Hout AFW
CPset_Phasing - Renovation Phase: Bestaand
Pset_SlabCommon - LoadBearing: no; IsExternal: yes
BaseQuantities - Width: 180 mm; Perimeter: 2860 mm; GrossArea: 0.339 m2; NetArea: 0.339 m2; GrossVolume: 0.06102 m3; NetVolume: 0.06102 m3
Component Quantities - Hout AFW, Mass: 33.561 kg; Hout AFW, Projected Component Area (Net): 0.339 m2; Hout AFW, Projected Component Area (Gross): 0.339 m2; Hout AFW, Component Thickness: 180 mm; Hout AFW, Component Volume (Net): 0.06102 m3; Hout AFW, Component Volume (Gross): 0.06102 m3

# IfcSlab: Hout AFW 260, 23_23 VBI 260 + druklaag
In: verdieping
Classification: Vloer (ARCHICAD Classification); 23.21 vrijdragende vloeren (NL/SfB (4 cijfers)); Material: Hout AFW
CPset_Phasing - Renovation Phase: Bestaand
Pset_SlabCommon - LoadBearing: no; IsExternal: yes
BaseQuantities - Width: 260 mm; Perimeter: 9130 mm; GrossArea: 1.07875 m2; NetArea: 1.06729 m2; GrossVolume: 0.280475 m3; NetVolume: 0.277496 m3
Component Quantities - Hout AFW, Mass: 152.623 kg; Hout AFW, Projected Component Area (Net): 1.06729 m2; Hout AFW, Projected Component Area (Gross): 1.06729 m2; Hout AFW, Component Thickness: 260 mm; Hout AFW, Component Volume (Net): 0.277496 m3; Hout AFW, Component Volume (Gross): 0.277496 m3

# IfcSlab: Hout AFW 360, 23_23 VBI 260 + druklaag
In: verdieping
Classification: Vloer (ARCHICAD Classification); 23.21 vrijdragende vloeren (NL/SfB (4 cijfers)); Material: Hout AFW
CPset_Phasing - Renovation Phase: Bestaand
Pset_SlabCommon - LoadBearing: no; IsExternal: yes
BaseQuantities - Width: 360 mm; Perimeter: 2560 mm; GrossArea: 0.1695 m2; NetArea: 0.1695 m2; GrossVolume: 0.06102 m3; NetVolume: 0.06102 m3
Component Quantities - Hout AFW, Mass: 33.561 kg; Hout AFW, Projected Component Area (Net): 0.1695 m2; Hout AFW, Projected Component Area (Gross): 0.1695 m2; Hout AFW, Component Thickness: 360 mm; Hout AFW, Component Volume (Net): 0.06102 m3; Hout AFW, Component Volume (Gross): 0.06102 m3

# IfcSlab: Hout AFW 440, 23_23 VBI 260 + druklaag
In: verdieping
Classification: Vloer (ARCHICAD Classification); 23.21 vrijdragende vloeren (NL/SfB (4 cijfers)); Material: Hout AFW
CPset_Phasing - Renovation Phase: Bestaand
Pset_SlabCommon - LoadBearing: no; IsExternal: yes
BaseQuantities - Width: 440 mm; Perimeter: 8930 mm; GrossArea: 0.64725 m2; NetArea: 0.64465 m2; GrossVolume: 0.285864 m3; NetVolume: 0.28472 m3
Component Quantities - Hout AFW, Mass: 156.596 kg; Hout AFW, Projected Component Area (Net): 0.64725 m2; Hout AFW, Projected Component Area (Gross): 0.64725 m2; Hout AFW, Component Thickness: 440 mm; Hout AFW, Component Volume (Net): 0.28472 m3; Hout AFW, Component Volume (Gross): 0.28472 m3

# IfcSlab: IfcSlab (2)
In: begane grond
Type - PredefinedType: LANDING
Classification: Trapbordes (ARCHICAD Classification); 24.15 bordessen (NL/SfB (4 cijfers)); Material: Beton gewapend prefab
CPset_Phasing - Renovation Phase: Bestaand
Name | GrossVolume (m3) = NetVolume (m3) = Beton gewapend prefab, Component Volume (Net) (m3) = Beton gewapend prefab, Component Volume (Gross) (m3) | Beton gewapend prefab, Mass (kg)
24_Trapconstructie-x | 0.902848 | 2166.84
24_Trapconstructie-x | 0.437363 | 1049.67

# IfcSlab: Isolatie - Kunststof hard 140 (2)
Classification: Vloer (ARCHICAD Classification); 23.21 vrijdragende vloeren (NL/SfB (4 cijfers)); Material: Isolatie - Kunststof hard
CPset_Phasing - Renovation Phase: Bestaand
Pset_SlabCommon - LoadBearing: no; IsExternal: yes
BaseQuantities - Width: 140 mm
Component Quantities - Isolatie - Kunststof hard, Component Thickness: 140 mm
Name | In | Perimeter (mm) | GrossArea (m2) | NetArea (m2) = Isolatie - Kunststof hard, Projected Component Area (Net) (m2) | GrossVolume (m3) | NetVolume (m3) = Isolatie - Kunststof hard, Component Volume (Net) (m3) | Isolatie - Kunststof hard, Mass (kg) | Isolatie - Kunststof hard, Projected Component Area (Gross) (m2) | Isolatie - Kunststof hard, Component Volume (Gross) (m3)
23_dakisolatie | verdieping | 53966 | 181.762 | 181.762 | 25.4467 | 25.4467 | 2544.67 | 181.762 | 25.4467
23_dakisolatie | techniek | 158514 | 1315.11 | 1273.25 | 184.065 | 178.205 | 17820.5 | 1315.05 | 184.106

# IfcSlab: Isolatie - Kunststof hard afschot 140, 23_dakisolatie
In: techniek
Classification: Vloer (ARCHICAD Classification); 23.21 vrijdragende vloeren (NL/SfB (4 cijfers)); Material: Isolatie - Kunststof hard afschot
CPset_Phasing - Renovation Phase: Bestaand
Pset_SlabCommon - LoadBearing: no; IsExternal: yes
BaseQuantities - Width: 140 mm; Perimeter: 106122 mm; GrossArea: 19.0386 m2; NetArea: 19.0386 m2; GrossVolume: 2.66541 m3; NetVolume: 2.66541 m3
Component Quantities - Isolatie - Kunststof hard afschot, Mass: 266.541 kg; Isolatie - Kunststof hard afschot, Projected Component Area (Net): 19.0386 m2; Isolatie - Kunststof hard afschot, Projected Component Area (Gross): 19.0386 m2; Isolatie - Kunststof hard afschot, Component Thickness: 140 mm; Isolatie - Kunststof hard afschot, Component Volume (Net): 2.66541 m3; Isolatie - Kunststof hard afschot, Component Volume (Gross): 2.66541 m3

# IfcSlab: Isolatie - Kunststof hard afschot 350, 23_dakisolatie
In: techniek
Classification: Vloer (ARCHICAD Classification); 23.21 vrijdragende vloeren (NL/SfB (4 cijfers)); Material: Isolatie - Kunststof hard afschot
CPset_Phasing - Renovation Phase: Bestaand
Pset_SlabCommon - LoadBearing: no; IsExternal: yes
BaseQuantities - Width: 350 mm; Perimeter: 158514 mm; GrossArea: 31.221 m2; NetArea: 3.77272 m2; GrossVolume: 230.249 m3; NetVolume: 220.642 m3
Component Quantities - Isolatie - Kunststof hard afschot, Mass: 22064.2 kg; Isolatie - Kunststof hard afschot, Projected Component Area (Net): 1270.76 m2; Isolatie - Kunststof hard afschot, Projected Component Area (Gross): 1315.05 m2; Isolatie - Kunststof hard afschot, Component Thickness: 350 mm; Isolatie - Kunststof hard afschot, Component Volume (Net): 220.642 m3; Isolatie - Kunststof hard afschot, Component Volume (Gross): 460.266 m3

# IfcSlab: Isolatie - Kunststof hard afschot 60, 23_dakisolatie
In: verdieping
Classification: Vloer (ARCHICAD Classification); 23.21 vrijdragende vloeren (NL/SfB (4 cijfers)); Material: Isolatie - Kunststof hard afschot
CPset_Phasing - Renovation Phase: Bestaand
Pset_SlabCommon - LoadBearing: no; IsExternal: yes
BaseQuantities - Width: 60 mm; Perimeter: 28366 mm; GrossArea: 15.5796 m2; NetArea: 15.5796 m2; GrossVolume: 0.934776 m3; NetVolume: 0.934776 m3
Component Quantities - Isolatie - Kunststof hard afschot, Mass: 93.4776 kg; Isolatie - Kunststof hard afschot, Projected Component Area (Net): 15.5796 m2; Isolatie - Kunststof hard afschot, Projected Component Area (Gross): 15.5796 m2; Isolatie - Kunststof hard afschot, Component Thickness: 60 mm; Isolatie - Kunststof hard afschot, Component Volume (Net): 0.934776 m3; Isolatie - Kunststof hard afschot, Component Volume (Gross): 0.934776 m3

# IfcStair (3)
In: begane grond
Classification: Trap (ARCHICAD Classification); 24.10 algemeen (verzamelniveau) (NL/SfB (4 cijfers))
CPset_Phasing - Renovation Phase: Bestaand
BaseQuantities - Height: 3960 mm
Name | IsExternal | Length (mm) | GrossVolume (m3) = NetVolume (m3)
24_Trap-x | no | 8100 | 2.5823
24_Trap-x | no | 6000 | 5.10575
24_Trap-x | yes | 5500 | 0.758132

# IfcStairFlight: IfcStairFlight (4)
In: begane grond
Classification: 24.10 algemeen (verzamelniveau) (NL/SfB (4 cijfers)); Trapsegment (ARCHICAD Classification); Material: Beton gewapend prefab
CPset_Phasing - Renovation Phase: Bestaand
Name | Beton gewapend prefab, Mass (kg) | Beton gewapend prefab, Component Volume (Net) (m3) = Beton gewapend prefab, Component Volume (Gross) (m3)
24_Trapconstructie-x | 1968.83 | 0.820344
24_Trapconstructie-x | 2061.86 | 0.859108
24_Trapconstructie-x | 3507.87 | 1.46161
24_Trapconstructie-x | 7696.26 | 3.20677

# IfcWall: 21 buitenwand spouwmuur excl. 280 (2)
In: begane grond
Classification: Wand (ARCHICAD Classification); 21.22 spouwwanden (NL/SfB (4 cijfers))
CPset_Phasing - Renovation Phase: Bestaand
Pset_WallCommon - LoadBearing: yes; IsExternal: yes
BaseQuantities - Height: 1275 mm; Width: 280 mm
Name | Length (mm) | GrossFootprintArea (m2) = NetFootprintArea (m2) | GrossSideArea (m2) = NetSideArea (m2) | GrossVolume (m3) = NetVolume (m3)
21_21 betonwand | 695 | 0.179 | 0.733575 | 0.224673
21_21 betonwand | 2190 | 0.6288 | 2.8815 | 0.80172

# IfcWall: 22 beg hout (2600+) borstwering' 430 x 4390 (4)
In: begane grond
Classification: Wand (ARCHICAD Classification); 21.22 spouwwanden (NL/SfB (4 cijfers))
CPset_Phasing - Renovation Phase: Bestaand
Pset_WallCommon - LoadBearing: yes; IsExternal: yes
BaseQuantities - Width: 430 mm
Name | Length (mm) | Height (mm) | GrossFootprintArea (m2) = NetFootprintArea (m2) | GrossSideArea (m2) | NetSideArea (m2) | GrossVolume (m3) | NetVolume (m3)
21_21 betonwand | 29000 | 4390 | 12.4661 | 125.081 | 78.8309 | 46.7974 | 30.5687
21_21 betonwand | 14350 | 4390 | 5.35375 | 51.5155 | 38.945 | 20.0902 | 15.7035
21_21 betonwand | 6600 | 4390 | 2.83405 | 28.4863 | 17.7353 | 10.6107 | 6.8785
21_21 betonwand | 33109.5 | 4070 | 14.2349 | 121.668 | 70.7056 | 41.6872 | 23.7515

# IfcWall: 22 beg hout (3200+) 350 x 4010 (5)
In: begane grond
Classification: Wand (ARCHICAD Classification); 21.22 spouwwanden (NL/SfB (4 cijfers))
CPset_Phasing - Renovation Phase: Bestaand
Pset_WallCommon - LoadBearing: yes; IsExternal: yes
BaseQuantities - Height: 4010 mm; Width: 350 mm
Name | Length (mm) | GrossFootprintArea (m2) = NetFootprintArea (m2) | GrossSideArea (m2) = NetSideArea (m2) | GrossVolume (m3) = NetVolume (m3)
21_21 betonwand | 1625 | 0.567 | 6.50813 | 2.00911
21_21 betonwand | 1417.5 | 0.494375 | 5.67709 | 1.75025
21_21 betonwand | 1784.5 | 0.624575 | 7.14692 | 2.22616
21_21 betonwand | 2375 | 0.830375 | 9.51188 | 2.95377
21_21 betonwand | 3988 | 1.3958 | 15.9719 | 4.97503

# IfcWall: 22 beg mets (2600+) 430 x 4010, 21_21 betonwand
In: begane grond
Classification: Wand (ARCHICAD Classification); 21.22 spouwwanden (NL/SfB (4 cijfers))
CPset_Phasing - Renovation Phase: Bestaand
Pset_WallCommon - LoadBearing: no; IsExternal: yes
BaseQuantities - Length: 227.5 mm; Height: 4010 mm; Width: 430 mm; GrossFootprintArea: 0.097825 m2; NetFootprintArea: 0.097825 m2; GrossSideArea: 0.908863 m2; NetSideArea: 0.908863 m2; GrossVolume: 0.318113 m3; NetVolume: 0.318113 m3

# IfcWall: 22 beg mets (speellokaal) 280 x 4390 (2)
In: begane grond
Classification: Wand (ARCHICAD Classification); 21.22 spouwwanden (NL/SfB (4 cijfers))
CPset_Phasing - Renovation Phase: Bestaand
Pset_WallCommon - LoadBearing: yes; IsExternal: yes
BaseQuantities - Width: 280 mm
Name | Length (mm) | Height (mm) | GrossFootprintArea (m2) = NetFootprintArea (m2) | GrossSideArea (m2) | NetSideArea (m2) | GrossVolume (m3) | NetVolume (m3)
21_21 betonwand | 5265 | 4390 | 1.5099 | 23.7499 | 19.7827 | 6.62846 | 5.51765
21_21 betonwand | 1602 | 4070 | 0.44856 | 6.52014 | 6.52014 | 1.82564 | 1.82564

# IfcWall: 22 beg mets + verd (beton) 490 x 8410 (4)
In: begane grond
Classification: Wand (ARCHICAD Classification); 21.22 spouwwanden (NL/SfB (4 cijfers))
CPset_Phasing - Renovation Phase: Bestaand
Pset_WallCommon - LoadBearing: yes; IsExternal: yes
BaseQuantities - Width: 490 mm
Name | Length (mm) | Height (mm) | GrossFootprintArea (m2) = NetFootprintArea (m2) | GrossSideArea (m2) | NetSideArea (m2) | GrossVolume (m3) | NetVolume (m3)
21_21 betonwand | 8135 | 8350 | 3.94943 | 67.7023 | 67.7023 | 31.9148 | 31.9148
21_21 betonwand | 885 | 8350 | 0.4704 | 8.30319 | 8.26492 | 3.79135 | 3.77277
21_21 betonwand | 845 | 8410 | 0.4508 | 7.96335 | 7.96335 | 3.64951 | 3.64951
21_21 betonwand | 9005 | 8410 | 4.37573 | 74.7103 | 74.7103 | 35.2519 | 35.2519

# IfcWall: 22 beg metselwerk (entree) 280 x 4330, 21_21 betonwand
In: begane grond
Classification: Wand (ARCHICAD Classification); 21.22 spouwwanden (NL/SfB (4 cijfers))
CPset_Phasing - Renovation Phase: Bestaand
Pset_WallCommon - LoadBearing: yes; IsExternal: yes
BaseQuantities - Length: 620 mm; Height: 4330 mm; Width: 280 mm; GrossFootprintArea: 0.2093 m2; NetFootprintArea: 0.2093 m2; GrossSideArea: 3.13485 m2; NetSideArea: 3.13485 m2; GrossVolume: 0.856541 m3; NetVolume: 0.856541 m3

# IfcWall: 22 beg metselwerk 430 x 4390 (2)
In: begane grond
Classification: Wand (ARCHICAD Classification); 21.22 spouwwanden (NL/SfB (4 cijfers))
CPset_Phasing - Renovation Phase: Bestaand
Pset_WallCommon - LoadBearing: yes; IsExternal: yes
BaseQuantities - Height: 4390 mm; Width: 430 mm
Name | Length (mm) | GrossFootprintArea (m2) = NetFootprintArea (m2) | GrossSideArea (m2) = NetSideArea (m2) | GrossVolume (m3) = NetVolume (m3)
21_21 betonwand | 4720 | 1.9624 | 20.1797 | 8.11529
21_21 betonwand | 10970 | 4.6184 | 47.2424 | 19.088

# IfcWall: 22 borstwering 460 x 1030 (4)
In: verdieping
Classification: Wand (ARCHICAD Classification); 21.22 spouwwanden (NL/SfB (4 cijfers))
CPset_Phasing - Renovation Phase: Bestaand
Pset_WallCommon - LoadBearing: yes; IsExternal: yes
BaseQuantities - Height: 1030 mm; Width: 460 mm
Name | Length (mm) | GrossFootprintArea (m2) = NetFootprintArea (m2) | GrossSideArea (m2) = NetSideArea (m2) | GrossVolume (m3) = NetVolume (m3)
21_22 betonwand | 605 | 0.248672 | 0.823907 | 0.243763
21_22 betonwand | 13585 | 6.01267 | 21.6181 | 6.01303
21_22 betonwand | 14400 | 6.37209 | 22.8943 | 6.37281
21_21 betonwand | 13455 | 5.97348 | 21.5571 | 5.97906

# IfcWall: 22 borstwering dakterras 30 x 880 (2)
In: verdieping
Classification: Wand (ARCHICAD Classification); 21.22 spouwwanden (NL/SfB (4 cijfers))
CPset_Phasing - Renovation Phase: Bestaand
Pset_WallCommon - LoadBearing: yes; IsExternal: yes
BaseQuantities - Height: 880 mm; Width: 30 mm
Name | Length (mm) | GrossFootprintArea (m2) = NetFootprintArea (m2) | GrossSideArea (m2) = NetSideArea (m2) | GrossVolume (m3) = NetVolume (m3)
21_21 betonwand | 3967 | 0.0435729 | 3.81744 | 0.0219437
21_21 betonwand | 1470 | 0.016251 | 1.4281 | 0.00817981

# IfcWall: 22 dak 430 x 3000, 21_GF 125 ECO DGS/2.75.2A
In: techniek
Classification: Wand (ARCHICAD Classification); 21.22 spouwwanden (NL/SfB (4 cijfers))
CPset_Phasing - Renovation Phase: Bestaand
Pset_WallCommon - LoadBearing: yes; IsExternal: yes
BaseQuantities - Length: 9180 mm; Height: 3000 mm; Width: 430 mm; GrossFootprintArea: 3.9474 m2; NetFootprintArea: 3.9474 m2; GrossSideArea: 26.88 m2; NetSideArea: 26.88 m2; GrossVolume: 11.6352 m3; NetVolume: 11.6352 m3

# IfcWall: 22 dak opstand (650+) 463 x 560 (4)
In: techniek
Classification: Wand (ARCHICAD Classification); 21.22 spouwwanden (NL/SfB (4 cijfers))
CPset_Phasing - Renovation Phase: Bestaand
Pset_WallCommon - LoadBearing: yes; IsExternal: yes
BaseQuantities - Height: 560 mm; Width: 463 mm
Name | Length (mm) | GrossFootprintArea (m2) = NetFootprintArea (m2) | GrossSideArea (m2) = NetSideArea (m2) | GrossVolume (m3) = NetVolume (m3)
21_21 betonwand | 19340.5 | 8.37634 | 19.1923 | 4.52598
21_21 betonwand | 9198.5 | 3.98485 | 9.08794 | 2.14272
21_21 betonwand | 35144 | 15.4037 | 35.0547 | 8.28128
21_21 betonwand | 32057 | 13.9758 | 31.8828 | 7.52571

# IfcWall: 22 verd (2600+) 430 x 5240, 21_21 betonwand
In: verdieping
Classification: Wand (ARCHICAD Classification); 21.22 spouwwanden (NL/SfB (4 cijfers))
CPset_Phasing - Renovation Phase: Bestaand
Pset_WallCommon - LoadBearing: yes; IsExternal: yes
BaseQuantities - Length: 33337 mm; Height: 5230 mm; Width: 430 mm; GrossFootprintArea: 14.3334 m2; NetFootprintArea: 14.3334 m2; GrossSideArea: 158.478 m2; NetSideArea: 105.351 m2; GrossVolume: 66.5944 m3; NetVolume: 45.2843 m3

# IfcWall: 22 verd (3200+) 430 x 4640 (2)
In: verdieping
Classification: Wand (ARCHICAD Classification); 21.22 spouwwanden (NL/SfB (4 cijfers))
CPset_Phasing - Renovation Phase: Bestaand
Pset_WallCommon - LoadBearing: yes; IsExternal: yes
BaseQuantities - Height: 4640 mm; Width: 430 mm
Name | Length (mm) | GrossFootprintArea (m2) = NetFootprintArea (m2) | GrossSideArea (m2) | NetSideArea (m2) | GrossVolume (m3) | NetVolume (m3)
21_21 betonwand | 23865 | 10.2392 | 110.586 | 71.4752 | 44.9874 | 28.6782
21_21 betonwand | 28507 | 12.284 | 131.575 | 107.456 | 53.7261 | 43.6665

# IfcWall: 22 verd (achtergevel) 430 x 3960 (2)
In: verdieping
Classification: Wand (ARCHICAD Classification); 21.22 spouwwanden (NL/SfB (4 cijfers))
CPset_Phasing - Renovation Phase: Bestaand
Pset_WallCommon - LoadBearing: yes; IsExternal: yes
BaseQuantities - Width: 430 mm
Name | Length (mm) | Height (mm) | GrossFootprintArea (m2) = NetFootprintArea (m2) | GrossSideArea (m2) | NetSideArea (m2) | GrossVolume (m3) | NetVolume (m3)
21_21 betonwand | 5265 | 3960 | 2.238 | 19.7079 | 9.29185 | 8.30203 | 4.67601
21_21 betonwand | 26465 | 1100 | 11.4059 | 105.301 | 28.5937 | 45.2549 | 12.2972

# IfcWall: 24 Hout gevelbekleding Lariks 25, 21_22 betonwand
In: begane grond
Classification: Wand (ARCHICAD Classification); 21.22 spouwwanden (NL/SfB (4 cijfers)); Material: 24 Hout gevelbekleding Lariks
CPset_Phasing - Renovation Phase: Bestaand
Pset_WallCommon - LoadBearing: no; IsExternal: yes
BaseQuantities - Length: 103 mm; Height: 1901.76 mm; Width: 25 mm; GrossFootprintArea: 0.002575 m2; NetFootprintArea: 0.002575 m2; GrossSideArea: 0.195882 m2; NetSideArea: 0.195882 m2; GrossVolume: 0.00489705 m3; NetVolume: 0.00489705 m3
Component Quantities - 24 Hout gevelbekleding Lariks, Mass: 3.18308 kg; 24 Hout gevelbekleding Lariks, Projected Component Area (Net): 0.195882 m2; 24 Hout gevelbekleding Lariks, Projected Component Area (Gross): 0.195882 m2; 24 Hout gevelbekleding Lariks, Component Thickness: 25 mm; 24 Hout gevelbekleding Lariks, Rectangular Component Height: 1901.76 mm; 24 Hout gevelbekleding Lariks, Rectangular Component Width: 25 mm; 24 Hout gevelbekleding Lariks, Component Cross Section Area: 0.0475441 m2; 24 Hout gevelbekleding Lariks, Component Volume (Net): 0.00489705 m3; 24 Hout gevelbekleding Lariks, Component Volume (Gross): 0.00489705 m3

# IfcWall: 31 pui (3200+) 62 x 3200, 21_21 betonwand
In: begane grond
Classification: Wand (ARCHICAD Classification); 21.22 spouwwanden (NL/SfB (4 cijfers)); Material: 31 pui/kozijn
CPset_Phasing - Renovation Phase: Bestaand
Pset_WallCommon - LoadBearing: yes; IsExternal: yes
BaseQuantities - Length: 1150 mm; Height: 10 mm; Width: 62 mm; GrossFootprintArea: 0 m2; NetFootprintArea: 0 m2; GrossSideArea: 3.656 m2; NetSideArea: 0.011425 m2; GrossVolume: 0.228064 m3; NetVolume: 0.0007127 m3
Component Quantities - 31 pui/kozijn, Mass: 0.57016 kg; 31 pui/kozijn, Rectangular Component Height: 3200 mm; 31 pui/kozijn, Rectangular Component Width: 62 mm; 31 pui/kozijn, Component Cross Section Area: 0.1984 m2; 31 pui/kozijn, Component Volume (Net): 0.0007127 m3; 31 pui/kozijn, Component Volume (Gross): 0.228064 m3

# IfcWall: 31 pui/kozijn 62 (6)
In: begane grond
Classification: Wand (ARCHICAD Classification); 21.22 spouwwanden (NL/SfB (4 cijfers)); Material: 31 pui/kozijn
CPset_Phasing - Renovation Phase: Bestaand
Pset_WallCommon - LoadBearing: no; IsExternal: yes
BaseQuantities - Width: 62 mm
Component Quantities - 31 pui/kozijn, Component Thickness: 62 mm; 31 pui/kozijn, Rectangular Component Width: 62 mm
Name | Length (mm) | Height (mm) = 31 pui/kozijn, Rectangular Component Height (mm) | GrossFootprintArea (m2) = NetFootprintArea (m2) | GrossSideArea (m2) | NetSideArea (m2) | GrossVolume (m3) = 31 pui/kozijn, Component Volume (Gross) (m3) | NetVolume (m3) = 31 pui/kozijn, Component Volume (Net) (m3) | 31 pui/kozijn, Mass (kg) | 31 pui/kozijn, Projected Component Area (Net) (m2) | 31 pui/kozijn, Projected Component Area (Gross) (m2) | 31 pui/kozijn, Component Cross Section Area (m2)
21_21 betonwand | 1884 | 3710 | 0.076924 | 6.34967 | 0.57426 | 0.402698 | 0.0444248 | 35.5398 | 0.9752 | 6.75962 | 0.23002
21_53 wandtegels keramisch | 4601 | 4010 | 0.298654 | 18.79 | 4.29689 | 1.165 | 0.266421 | 213.137 | 4.30249 | 18.7956 | 0.24862
21_21 betonwand | 1883 | 3710 | 0.118668 | 7.10094 | 1.1175 | 0.440258 | 0.069285 | 55.428 | 1.1175 | 7.10094 | 0.23002
21_21 betonwand | 8045 | 3710 | 0.49879 | 29.838 | 4.15795 | 1.84995 | 0.257793 | 206.234 | 4.15795 | 29.838 | 0.23002
21_53 wandtegels keramisch | 4540 | 4010 | 0.29295 | 18.4189 | 4.96898 | 1.14198 | 0.30809 | 246.472 | 4.97458 | 18.4245 | 0.24862
21_53 wandtegels keramisch | 6600 | 4010 | 0.4092 | 21.6231 | 2.5005 | 1.34067 | 0.155069 | 124.055 | 2.511 | 21.6336 | 0.24862

# IfcWall: 32 schuideur 60 (14)
Classification: Wand (ARCHICAD Classification); 22.13 systeemwanden; vast (NL/SfB (4 cijfers)); Material: 32 schuideur
CPset_Phasing - Renovation Phase: Bestaand
Pset_WallCommon - LoadBearing: yes; IsExternal: yes
BaseQuantities - Height: 2600 mm; Width: 60 mm
Component Quantities - 32 schuideur, Component Thickness: 60 mm; 32 schuideur, Rectangular Component Height: 2600 mm; 32 schuideur, Rectangular Component Width: 60 mm; 32 schuideur, Component Cross Section Area: 0.156 m2
Name | In | Length (mm) | GrossFootprintArea (m2) = NetFootprintArea (m2) | GrossSideArea (m2) = NetSideArea (m2) = 32 schuideur, Projected Component Area (Net) (m2) = 32 schuideur, Projected Component Area (Gross) (m2) | GrossVolume (m3) = NetVolume (m3) = 32 schuideur, Component Volume (Net) (m3) = 32 schuideur, Component Volume (Gross) (m3) | 32 schuideur, Mass (kg)
7 x 22_GF 100 RD/2.50.2. | begane grond | 700 | 0.042 | 1.82 | 0.1092 | 60.06
22_GF 100 RD/2.50.2. | verdieping | 700.006 | 0.0420073 | 1.82017 | 0.10921 | 60.0655
6 x 22_GF 100 RD/2.50.2. | verdieping | 700 | 0.042 | 1.82 | 0.1092 | 60.06

# IfcWall: 32 waterslag (negge 210mm) 252 x 90 (15)
Classification: Wand (ARCHICAD Classification); 21.22 spouwwanden (NL/SfB (4 cijfers)); Material: Metaal - Aluminium beige
CPset_Phasing - Renovation Phase: Bestaand
Pset_WallCommon - LoadBearing: no; IsExternal: yes
BaseQuantities - Height: 90.01 mm; Width: 251.999 mm
Component Quantities - Metaal - Aluminium beige, Component Cross Section Area: 0.00066909 m2
Name | In | Length (mm) | GrossFootprintArea (m2) = NetFootprintArea (m2) | GrossSideArea (m2) = NetSideArea (m2) | GrossVolume (m3) = NetVolume (m3) = Metaal - Aluminium beige, Component Volume (Net) (m3) = Metaal - Aluminium beige, Component Volume (Gross) (m3) | Metaal - Aluminium beige, Mass (kg)
21_31 waterslag | begane grond | 6775 | 0.101625 | 2.17334 | 0.00453309 | 12.6926
21_31 waterslag | begane grond | 6748 | 0.10122 | 2.16467 | 0.00451502 | 12.6421
21_31 waterslag | begane grond | 5150 | 0.07725 | 1.65206 | 0.00344582 | 9.64828
21_31 waterslag | begane grond | 4859.5 | 0.0728925 | 1.55887 | 0.00325145 | 9.10405
21_31 waterslag | begane grond | 4933 | 0.073995 | 1.58244 | 0.00330062 | 9.24174
2 x 21_31 waterslag | begane grond | 8473 | 0.127095 | 2.71803 | 0.0056692 | 15.8738
21_31 waterslag | begane grond | 6759 | 0.103275 | 2.17357 | 0.00453662 | 12.7025
21_31 waterslag | begane grond | 14669 | 0.223615 | 4.71014 | 0.00983034 | 27.5249
21_31 waterslag | begane grond | 8682 | 0.131921 | 2.78422 | 0.00581025 | 16.2687
21_31 waterslag | verdieping | 22770 | 0.34155 | 7.29992 | 0.0152264 | 42.6339
21_31 waterslag | verdieping | 14025 | 0.210375 | 4.45257 | 0.00929076 | 26.0141
21_31 waterslag | verdieping | 26856 | 0.404727 | 8.62022 | 0.0179829 | 50.3522
21_31 waterslag | verdieping | 5384 | 0.0824509 | 1.72435 | 0.00359977 | 10.0794
21_31 waterslag | verdieping | 33119.5 | 0.496793 | 10.4038 | 0.0217174 | 60.8088

# IfcWall: 32 waterslag (negge 60mm) 60 x 90 (2)
In: verdieping
Classification: Wand (ARCHICAD Classification); 21.22 spouwwanden (NL/SfB (4 cijfers)); Material: Metaal - Aluminium beige
CPset_Phasing - Renovation Phase: Bestaand
Pset_WallCommon - LoadBearing: no; IsExternal: yes
BaseQuantities - Height: 90.01 mm; Width: 60 mm
Component Quantities - Metaal - Aluminium beige, Component Cross Section Area: 0.000313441 m2
Name | Length (mm) | GrossFootprintArea (m2) = NetFootprintArea (m2) | GrossSideArea (m2) = NetSideArea (m2) | GrossVolume (m3) = NetVolume (m3) | Metaal - Aluminium beige, Mass (kg) | Metaal - Aluminium beige, Component Volume (Net) (m3) = Metaal - Aluminium beige, Component Volume (Gross) (m3)
21_31 waterslag | 1708 | 0.0276565 | 0.239458 | 0.000568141 | 1.59081 | 0.000568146
21_31 waterslag | 3565 | 0.053475 | 0.468251 | 0.00111742 | 3.12877 | 0.00111742

# IfcWall: 44 koof 50 (75)
Classification: Wand (ARCHICAD Classification); 21.22 spouwwanden (NL/SfB (4 cijfers)); Material: ALG - LICHTE SCHEIDINGSWAND
CPset_Phasing - Renovation Phase: Bestaand
Pset_WallCommon - LoadBearing: yes; IsExternal: yes
BaseQuantities - Width: 50 mm
Component Quantities - ALG - LICHTE SCHEIDINGSWAND, Component Thickness: 12 mm; ALG - LICHTE SCHEIDINGSWAND, Rectangular Component Width: 12 mm
Name | In | Length (mm) | Height (mm) | GrossFootprintArea (m2) = NetFootprintArea (m2) | GrossSideArea (m2) = NetSideArea (m2) | GrossVolume (m3) = NetVolume (m3) | ALG - LICHTE SCHEIDINGSWAND, Mass (kg) | ALG - LICHTE SCHEIDINGSWAND, Projected Component Area (Net) (m2) = ALG - LICHTE SCHEIDINGSWAND, Projected Component Area (Gross) (m2) | ALG - LICHTE SCHEIDINGSWAND, Rectangular Component Height (mm) | ALG - LICHTE SCHEIDINGSWAND, Component Cross Section Area (m2) | ALG - LICHTE SCHEIDINGSWAND, Component Volume (Net) (m3) = ALG - LICHTE SCHEIDINGSWAND, Component Volume (Gross) (m3)
21_22 betonwand | begane grond | 5122.5 | 960 | 0.256919 | 4.76423 | 0.236141 | 46.5013 | 4.84389 | 960 | 0.01152 | 0.0581267
21_22 betonwand | begane grond | 9140 | 948 | 0.457795 | 8.49627 | 0.420754 | 83.063 | 8.6524 | 960 | 0.01152 | 0.103829
21_22 betonwand | begane grond | 4162.5 | 948 | 0.208124 | 3.86696 | 0.191292 | 37.8819 | 3.94605 | 960 | 0.01152 | 0.0473523
21_22 betonwand | begane grond | 3823 | 948 | 0.1849 | 3.43544 | 0.169945 | 33.6548 | 3.5057 | 960 | 0.01152 | 0.0420685
21_23 betonwand | begane grond | 1825 | 948 | 0.090456 | 1.67766 | 0.0831358 | 16.3814 | 1.7064 | 960 | 0.01152 | 0.0204768
21_22 betonwand | begane grond | 6287.5 | 948 | 0.314375 | 5.84109 | 0.288948 | 57.2214 | 5.96055 | 960 | 0.01152 | 0.0715267
21_22 betonwand | begane grond | 3875 | 948 | 0.19375 | 3.59987 | 0.17808 | 35.2656 | 3.6735 | 960 | 0.01152 | 0.044082
2 x 21_22 betonwand | begane grond | 5425 | 358 | 0.272044 | 1.84044 | 0.0895015 | 18.5988 | 1.93738 | 370 | 0.00444 | 0.0232485
21_22 betonwand | begane grond | 6287.5 | 948 | 0.314375 | 5.84109 | 0.288948 | 57.2212 | 5.96055 | 960 | 0.01152 | 0.0715265
21_22 betonwand | begane grond | 3000 | 448 | 0.15 | 1.287 | 0.062868 | 12.9024 | 1.344 | 460 | 0.00552 | 0.016128
2 x 21_22 betonwand | begane grond | 9115 | 868 | 0.45575 | 6.28023 | 0.353261 | 75.9535 | 7.91182 | 880 | 0.01056 | 0.0949418
21_22 betonwand | begane grond | 3903 | 948 | 0.188901 | 3.50976 | 0.173622 | 34.3831 | 3.58154 | 960 | 0.01152 | 0.0429789
21_22 betonwand | begane grond | 8740 | 548 | 0.437001 | 4.62346 | 0.226855 | 45.9794 | 4.78952 | 560 | 0.00672 | 0.0574742
21_23 betonwand | begane grond | 23700 | 948 | 1.18579 | 22.0225 | 1.08987 | 215.571 | 22.4553 | 960 | 0.01152 | 0.269463
21_23 betonwand | begane grond | 28825 | 960 | 1.407 | 26.17 | 1.29504 | 256.2 | 26.6875 | 960 | 0.01152 | 0.32025
21_22 betonwand | begane grond | 9525 | 948 | 0.46075 | 8.56073 | 0.423484 | 83.8637 | 8.73582 | 960 | 0.01152 | 0.10483
21_22 betonwand | begane grond | 3470 | 948 | 0.172706 | 3.20586 | 0.158733 | 31.3523 | 3.26586 | 960 | 0.01152 | 0.0391903
21_22 betonwand | begane grond | 6350 | 948 | 0.3175 | 5.8866 | 0.291803 | 57.4442 | 5.98378 | 960 | 0.01152 | 0.0718053
21_22 betonwand | begane grond | 3050 | 348 | 0.150912 | 0.99072 | 0.0481507 | 10.0224 | 1.044 | 360 | 0.00432 | 0.012528
21_23 betonwand | begane grond | 5255 | 948 | 0.26075 | 4.84474 | 0.239661 | 47.4607 | 4.94382 | 960 | 0.01152 | 0.0593258
21_22 betonwand | begane grond | 1225 | 948 | 0.062044 | 1.14324 | 0.0570127 | 11.0302 | 1.14898 | 960 | 0.01152 | 0.0137877
2 x 21_22 betonwand | begane grond | 11012.5 | 948 | 0.55142 | 10.2358 | 0.506807 | 100.104 | 10.4275 | 960 | 0.01152 | 0.12513
21_22 betonwand | begane grond | 4162.5 | 948 | 0.208125 | 3.86696 | 0.191292 | 37.8821 | 3.94605 | 960 | 0.01152 | 0.0473526
21_23 betonwand | begane grond | 3875 | 948 | 0.19375 | 3.59987 | 0.178079 | 35.2656 | 3.6735 | 960 | 0.01152 | 0.044082
21_22 betonwand | begane grond | 2660 | 200 | 0.133 | 0.4576 | 0.0216944 | 4.83071 | 0.5032 | 250 | 0.003 | 0.00603838
21_22 betonwand | begane grond | 1150 | 555 | 0.0575 | 0.63825 | 0.0319125 | 6.1272 | 0.63825 | 555 | 0.00666 | 0.007659
3 x 21_22 betonwand | begane grond | 2425 | 948 | 0.120456 | 2.23506 | 0.110709 | 21.8419 | 2.2752 | 960 | 0.01152 | 0.0273024
21_22 betonwand | begane grond | 2425 | 948 | 0.120456 | 2.23506 | 0.11071 | 21.842 | 2.2752 | 960 | 0.01152 | 0.0273026
21_22 betonwand | begane grond | 13305 | 948 | 0.666044 | 12.3656 | 0.612161 | 120.968 | 12.6008 | 960 | 0.01152 | 0.15121
21_23 betonwand | begane grond | 1290 | 948 | 0.0575 | 1.06835 | 0.0528494 | 10.4659 | 1.0902 | 960 | 0.01152 | 0.0130824
4 x 21_22 betonwand | begane grond | 7125 | 948 | 0.357044 | 6.62434 | 0.328153 | 64.7249 | 6.74218 | 960 | 0.01152 | 0.0809061
4 x 21_22 betonwand | begane grond | 1225 | 948 | 0.060456 | 1.12026 | 0.0555622 | 10.921 | 1.1376 | 960 | 0.01152 | 0.0136512
21_22 betonwand | begane grond | 7052.5 | 948 | 0.351831 | 6.53401 | 0.323371 | 63.9559 | 6.66207 | 960 | 0.01152 | 0.0799449
21_22 betonwand | verdieping | 23750 | 960 | 1.16865 | 21.7649 | 1.07423 | 214.119 | 22.3041 | 960 | 0.01152 | 0.267649
21_23 betonwand | verdieping | 20170 | 948 | 1.0085 | 18.7379 | 0.926933 | 183.563 | 19.1212 | 960 | 0.01152 | 0.229454
4 x 21_24 betonwand | verdieping | 1225 | 948 | 0.060456 | 1.12026 | 0.0555622 | 10.921 | 1.1376 | 960 | 0.01152 | 0.0136512
21_23 betonwand | verdieping | 11375 | 948 | 0.567956 | 10.5496 | 0.522016 | 103.294 | 10.7598 | 960 | 0.01152 | 0.129118
21_22 betonwand | verdieping | 3534.5 | 960 | 0.17835 | 3.28549 | 0.164119 | 31.598 | 3.29146 | 960 | 0.01152 | 0.0394975
2 x 21_24 betonwand | verdieping | 7125 | 948 | 0.357044 | 6.62434 | 0.328153 | 64.7249 | 6.74218 | 960 | 0.01152 | 0.0809061
21_22 betonwand | verdieping | 5852.5 | 948 | 0.293419 | 5.44219 | 0.269674 | 53.1442 | 5.53585 | 960 | 0.01152 | 0.0664302
21_24 betonwand | verdieping | 7099.11 | 948 | 0.355749 | 6.60029 | 0.326963 | 64.4892 | 6.71763 | 960 | 0.01152 | 0.0806115
21_22 betonwand | verdieping | 13305 | 948 | 0.666044 | 12.3656 | 0.612161 | 120.968 | 12.6008 | 960 | 0.01152 | 0.15121
21_23 betonwand | verdieping | 14010 | 948 | 0.695837 | 12.9096 | 0.639532 | 126.128 | 13.1383 | 960 | 0.01152 | 0.15766
21_22 betonwand | verdieping | 17575 | 948 | 0.879544 | 16.3449 | 0.808411 | 160.175 | 16.6848 | 960 | 0.01152 | 0.200218
21_23 betonwand | verdieping | 17425 | 948 | 0.84 | 15.6072 | 0.772061 | 152.893 | 15.9264 | 960 | 0.01152 | 0.191117
21_22 betonwand | verdieping | 825 | 948 | 0.040456 | 0.761212 | 0.0371971 | 7.62647 | 0.794424 | 960 | 0.01152 | 0.00953309
2 x 21_23 betonwand | verdieping | 25640 | 448 | 1.282 | 10.9996 | 0.537312 | 110.273 | 11.4867 | 460 | 0.00552 | 0.137841
2 x 21_22 betonwand | verdieping | 2100 | 948 | 0.105 | 1.9509 | 0.0965076 | 19.1117 | 1.9908 | 960 | 0.01152 | 0.0238896
21_22 betonwand | verdieping | 5877.28 | 948 | 0.294658 | 5.46521 | 0.270813 | 53.3697 | 5.55934 | 960 | 0.01152 | 0.0667121
21_24 betonwand | verdieping | 1225 | 948 | 0.0620439 | 1.14324 | 0.0570127 | 11.0301 | 1.14898 | 960 | 0.01152 | 0.0137877
21_24 betonwand | verdieping | 7125 | 948 | 0.355456 | 6.60136 | 0.326703 | 64.6157 | 6.7308 | 960 | 0.01152 | 0.0807696
21_24 betonwand | verdieping | 7052.5 | 948 | 0.353419 | 6.55699 | 0.324821 | 64.0651 | 6.67345 | 960 | 0.01152 | 0.0800814
21_22 betonwand | verdieping | 10637.5 | 948 | 0.531876 | 9.86969 | 0.48884 | 96.464 | 10.0483 | 960 | 0.01152 | 0.12058
4 x 21_22 betonwand | verdieping | 2425 | 948 | 0.120456 | 2.23506 | 0.110709 | 21.8419 | 2.2752 | 960 | 0.01152 | 0.0273024
21_22 betonwand | verdieping | 10637.5 | 948 | 0.531875 | 9.86969 | 0.488839 | 96.4638 | 10.0483 | 960 | 0.01152 | 0.12058

# IfcWall: 74 Kupan tussenwand 13 x 2100 (12)
Classification: Wand (ARCHICAD Classification); 22.13 systeemwanden; vast (NL/SfB (4 cijfers)); Material: Kunststof Kupan
CPset_Phasing - Renovation Phase: Bestaand
Pset_WallCommon - LoadBearing: yes; IsExternal: no
BaseQuantities - Length: 978.5 mm; Height: 2100 mm; Width: 13 mm; GrossFootprintArea: 0.0127205 m2; NetFootprintArea: 0.0127205 m2; GrossSideArea: 2.05485 m2; NetSideArea: 2.05485 m2
Component Quantities - Kunststof Kupan, Mass: 37.1311 kg; Kunststof Kupan, Rectangular Component Height: 2100 mm; Kunststof Kupan, Rectangular Component Width: 13 mm; Kunststof Kupan, Component Cross Section Area: 0.0273 m2
Name | In | GrossVolume (m3) = NetVolume (m3) = Kunststof Kupan, Component Volume (Net) (m3) = Kunststof Kupan, Component Volume (Gross) (m3)
4 x 22_74 sanitaire wand | begane grond | 0.026713
2 x 22_74 sanitaire wand | begane grond | 0.0267131
3 x 22_74 sanitaire wand | verdieping | 0.026713
3 x 22_74 sanitaire wand | verdieping | 0.0267131

# IfcWall: 74 Kupan wand 20 x 2150 (6)
Classification: Wand (ARCHICAD Classification); 22.13 systeemwanden; vast (NL/SfB (4 cijfers))
CPset_Phasing - Renovation Phase: Bestaand
Pset_WallCommon - LoadBearing: yes; IsExternal: no
BaseQuantities - Height: 2150 mm; Width: 20 mm
Name | In | Length (mm) | GrossFootprintArea (m2) = NetFootprintArea (m2) | GrossSideArea (m2) | NetSideArea (m2) | GrossVolume (m3) | NetVolume (m3)
22_74 sanitaire wand | begane grond | 3559 | 0.0401799 | 7.65235 | 2.61235 | 0.10073 | 0.0352097
22_74 sanitaire wand | begane grond | 1758 | 0.01956 | 3.7797 | 1.2597 | 0.0497514 | 0.0169914
22_74 sanitaire wand | begane grond | 2758 | 0.03176 | 5.9297 | 2.1497 | 0.0780514 | 0.0289114
22_74 sanitaire wand | verdieping | 2758 | 0.03176 | 5.9297 | 2.1497 | 0.0780514 | 0.0289114
2 x 22_74 sanitaire wand | verdieping | 2758 | 0.0317599 | 5.9297 | 2.1497 | 0.0780514 | 0.0289114

# IfcWall: ALG - CONSTRUCTIEF 40, 22_GF 125 ECO DGS/2.75.2A
In: begane grond
Classification: Wand (ARCHICAD Classification); 22.13 systeemwanden; vast (NL/SfB (4 cijfers)); Material: ALG - CONSTRUCTIEF
CPset_Phasing - Renovation Phase: Bestaand
Pset_WallCommon - LoadBearing: yes; IsExternal: yes
BaseQuantities - Length: 1462 mm; Height: 4920 mm; Width: 40 mm; GrossFootprintArea: 0 m2; NetFootprintArea: 0 m2; GrossSideArea: 10.7603 m2; NetSideArea: 3.09944 m2; GrossVolume: 0.428775 m3; NetVolume: 0.121931 m3
Component Quantities - ALG - CONSTRUCTIEF, Mass: 280.441 kg; ALG - CONSTRUCTIEF, Projected Component Area (Net): 3.39184 m2; ALG - CONSTRUCTIEF, Projected Component Area (Gross): 10.9942 m2; ALG - CONSTRUCTIEF, Component Thickness: 40 mm; ALG - CONSTRUCTIEF, Rectangular Component Height: 7520 mm; ALG - CONSTRUCTIEF, Rectangular Component Width: 40 mm; ALG - CONSTRUCTIEF, Component Cross Section Area: 0.3008 m2; ALG - CONSTRUCTIEF, Component Volume (Net): 0.121931 m3; ALG - CONSTRUCTIEF, Component Volume (Gross): 0.428775 m3

# IfcWall: ALG - LICHTE SCHEIDINGSWAND - master 210, 22_GF 125 ECO DGS/2.75.3A
In: begane grond
Classification: Wand (ARCHICAD Classification); 22.13 systeemwanden; vast (NL/SfB (4 cijfers)); Material: ALG - LICHTE SCHEIDINGSWAND - master
CPset_Phasing - Renovation Phase: Bestaand
Pset_WallCommon - LoadBearing: yes; IsExternal: yes
BaseQuantities - Length: 122 mm; Height: 3570 mm; Width: 210 mm; GrossFootprintArea: 0.02562 m2; NetFootprintArea: 0.02562 m2; GrossSideArea: 0.43493 m2; NetSideArea: 0.43493 m2; GrossVolume: 0.0912804 m3; NetVolume: 0.0912804 m3
Component Quantities - ALG - LICHTE SCHEIDINGSWAND - master, Mass: 73.0243 kg; ALG - LICHTE SCHEIDINGSWAND - master, Projected Component Area (Net): 0.43554 m2; ALG - LICHTE SCHEIDINGSWAND - master, Projected Component Area (Gross): 0.43554 m2; ALG - LICHTE SCHEIDINGSWAND - master, Component Thickness: 210 mm; ALG - LICHTE SCHEIDINGSWAND - master, Rectangular Component Height: 3570 mm; ALG - LICHTE SCHEIDINGSWAND - master, Rectangular Component Width: 210 mm; ALG - LICHTE SCHEIDINGSWAND - master, Component Cross Section Area: 0.7497 m2; ALG - LICHTE SCHEIDINGSWAND - master, Component Volume (Net): 0.0912804 m3; ALG - LICHTE SCHEIDINGSWAND - master, Component Volume (Gross): 0.0912804 m3

# IfcWall: ALG - LICHTE SCHEIDINGSWAND - master 50 (5)
In: begane grond
Classification: Wand (ARCHICAD Classification); 22.13 systeemwanden; vast (NL/SfB (4 cijfers)); Material: ALG - LICHTE SCHEIDINGSWAND - master
CPset_Phasing - Renovation Phase: Bestaand
Pset_WallCommon - LoadBearing: yes; IsExternal: yes
BaseQuantities - Height: 3200 mm; Width: 50 mm
Component Quantities - ALG - LICHTE SCHEIDINGSWAND - master, Component Thickness: 50 mm; ALG - LICHTE SCHEIDINGSWAND - master, Rectangular Component Height: 3200 mm; ALG - LICHTE SCHEIDINGSWAND - master, Rectangular Component Width: 50 mm; ALG - LICHTE SCHEIDINGSWAND - master, Component Cross Section Area: 0.16 m2
Name | Length (mm) | GrossFootprintArea (m2) = NetFootprintArea (m2) | GrossSideArea (m2) = NetSideArea (m2) = ALG - LICHTE SCHEIDINGSWAND - master, Projected Component Area (Net) (m2) = ALG - LICHTE SCHEIDINGSWAND - master, Projected Component Area (Gross) (m2) | GrossVolume (m3) = NetVolume (m3) = ALG - LICHTE SCHEIDINGSWAND - master, Component Volume (Net) (m3) = ALG - LICHTE SCHEIDINGSWAND - master, Component Volume (Gross) (m3) | ALG - LICHTE SCHEIDINGSWAND - master, Mass (kg)
22_GF 125 ECO DGS/2.75.5A | 167.5 | 0.007125 | 0.456 | 0.0228 | 18.24
22_GF 125 ECO DGS/2.75.4A | 575 | 0.03 | 1.92 | 0.096 | 76.8
22_GF 125 ECO DGS/2.75.3A | 575 | 0.0275 | 1.76 | 0.088 | 70.4
22_GF 125 ECO DGS/2.75.3A | 260 | 0.013 | 0.832 | 0.0416 | 33.28
22_GF 125 ECO DGS/2.75.3A | 575 | 0.03 | 1.92 | 0.096 | 76.8

# IfcWall: ALG - LICHTE SCHEIDINGSWAND - master 60 (4)
Classification: Wand (ARCHICAD Classification); 22.13 systeemwanden; vast (NL/SfB (4 cijfers)); Material: ALG - LICHTE SCHEIDINGSWAND - master
CPset_Phasing - Renovation Phase: Bestaand
Pset_WallCommon - LoadBearing: yes; IsExternal: yes
BaseQuantities - Height: 2510 mm; Width: 60 mm
Component Quantities - ALG - LICHTE SCHEIDINGSWAND - master, Component Thickness: 60 mm; ALG - LICHTE SCHEIDINGSWAND - master, Rectangular Component Height: 2510 mm; ALG - LICHTE SCHEIDINGSWAND - master, Rectangular Component Width: 60 mm; ALG - LICHTE SCHEIDINGSWAND - master, Component Cross Section Area: 0.1506 m2
Name | In | Length (mm) | GrossFootprintArea (m2) = NetFootprintArea (m2) | GrossSideArea (m2) = NetSideArea (m2) = ALG - LICHTE SCHEIDINGSWAND - master, Projected Component Area (Net) (m2) = ALG - LICHTE SCHEIDINGSWAND - master, Projected Component Area (Gross) (m2) | GrossVolume (m3) = NetVolume (m3) = ALG - LICHTE SCHEIDINGSWAND - master, Component Volume (Net) (m3) = ALG - LICHTE SCHEIDINGSWAND - master, Component Volume (Gross) (m3) | ALG - LICHTE SCHEIDINGSWAND - master, Mass (kg)
22_GF 125 ECO DGS/2.75.2A | begane grond | 572.5 | 0.0381 | 1.59385 | 0.095631 | 76.5048
22_GF 125 ECO DGS/2.75.2A | begane grond | 725 | 0.0435 | 1.81975 | 0.109185 | 87.348
2 x 22_GF 125 ECO DGS/2.75.2A | verdieping | 662.5 | 0.0435 | 1.81975 | 0.109185 | 87.348

# IfcWall: ALG - LICHTE SCHEIDINGSWAND - slave 50 (2)
In: begane grond
Classification: Wand (ARCHICAD Classification); 22.13 systeemwanden; vast (NL/SfB (4 cijfers)); Material: ALG - LICHTE SCHEIDINGSWAND - slave
CPset_Phasing - Renovation Phase: Bestaand
Pset_WallCommon - LoadBearing: no; IsExternal: yes
BaseQuantities - Length: 1777.51 mm; Height: 1283.49 mm; Width: 50 mm; GrossFootprintArea: 0.0874199 m2; NetFootprintArea: 0.0874199 m2; GrossSideArea: 1.07994 m2; NetSideArea: 1.07994 m2; GrossVolume: 0.0559155 m3; NetVolume: 0.0559155 m3
Component Quantities - ALG - LICHTE SCHEIDINGSWAND - slave, Mass: 44.7324 kg; ALG - LICHTE SCHEIDINGSWAND - slave, Projected Component Area (Net): 1.14389 m2; ALG - LICHTE SCHEIDINGSWAND - slave, Projected Component Area (Gross): 2.08088 m2; ALG - LICHTE SCHEIDINGSWAND - slave, Component Thickness: 50 mm; ALG - LICHTE SCHEIDINGSWAND - slave, Rectangular Component Height: 1300 mm; ALG - LICHTE SCHEIDINGSWAND - slave, Rectangular Component Width: 50 mm; ALG - LICHTE SCHEIDINGSWAND - slave, Component Cross Section Area: 0.065 m2; ALG - LICHTE SCHEIDINGSWAND - slave, Component Volume (Net): 0.0559155 m3; ALG - LICHTE SCHEIDINGSWAND - slave, Component Volume (Gross): 0.0886657 m3

# IfcWall: ALG - LICHTE SCHEIDINGSWAND 105, 21_GF 125 ECO DGS/2.75.3A
In: begane grond
Classification: Wand (ARCHICAD Classification); 21.21 massieve wanden (NL/SfB (4 cijfers)); Material: ALG - LICHTE SCHEIDINGSWAND
CPset_Phasing - Renovation Phase: Bestaand
Pset_WallCommon - LoadBearing: yes; IsExternal: no
BaseQuantities - Length: 7000 mm; Height: 10 mm; Width: 105 mm; GrossFootprintArea: 0 m2; NetFootprintArea: 0 m2; GrossSideArea: 21 m2; NetSideArea: 0.07 m2; GrossVolume: 2.205 m3; NetVolume: 0.00735 m3
Component Quantities - ALG - LICHTE SCHEIDINGSWAND, Mass: 5.88 kg; ALG - LICHTE SCHEIDINGSWAND, Projected Component Area (Net): 0.07 m2; ALG - LICHTE SCHEIDINGSWAND, Projected Component Area (Gross): 21 m2; ALG - LICHTE SCHEIDINGSWAND, Component Thickness: 105 mm; ALG - LICHTE SCHEIDINGSWAND, Rectangular Component Height: 3000 mm; ALG - LICHTE SCHEIDINGSWAND, Rectangular Component Width: 105 mm; ALG - LICHTE SCHEIDINGSWAND, Component Cross Section Area: 0.315 m2; ALG - LICHTE SCHEIDINGSWAND, Component Volume (Net): 0.00735 m3; ALG - LICHTE SCHEIDINGSWAND, Component Volume (Gross): 2.205 m3

# IfcWall: ALG - LICHTE SCHEIDINGSWAND 120, 22_GF 125 ECO DGS/2.75.2A
In: begane grond
Classification: Wand (ARCHICAD Classification); 22.13 systeemwanden; vast (NL/SfB (4 cijfers)); Material: ALG - LICHTE SCHEIDINGSWAND
CPset_Phasing - Renovation Phase: Bestaand
Pset_WallCommon - LoadBearing: yes; IsExternal: yes
BaseQuantities - Length: 790 mm; Height: 2400 mm; Width: 120 mm; GrossFootprintArea: 0.0948 m2; NetFootprintArea: 0.0948 m2; GrossSideArea: 1.896 m2; NetSideArea: 1.896 m2; GrossVolume: 0.22752 m3; NetVolume: 0.22752 m3
Component Quantities - ALG - LICHTE SCHEIDINGSWAND, Mass: 182.016 kg; ALG - LICHTE SCHEIDINGSWAND, Projected Component Area (Net): 1.896 m2; ALG - LICHTE SCHEIDINGSWAND, Projected Component Area (Gross): 1.896 m2; ALG - LICHTE SCHEIDINGSWAND, Component Thickness: 120 mm; ALG - LICHTE SCHEIDINGSWAND, Rectangular Component Height: 2400 mm; ALG - LICHTE SCHEIDINGSWAND, Rectangular Component Width: 120 mm; ALG - LICHTE SCHEIDINGSWAND, Component Cross Section Area: 0.288 m2; ALG - LICHTE SCHEIDINGSWAND, Component Volume (Net): 0.22752 m3; ALG - LICHTE SCHEIDINGSWAND, Component Volume (Gross): 0.22752 m3

# IfcWall: ALG - LICHTE SCHEIDINGSWAND 125, 22_53 wandtegels keramisch
In: begane grond
Classification: Wand (ARCHICAD Classification); 22.13 systeemwanden; vast (NL/SfB (4 cijfers)); Material: ALG - LICHTE SCHEIDINGSWAND
CPset_Phasing - Renovation Phase: Bestaand
Pset_WallCommon - LoadBearing: yes; IsExternal: yes
BaseQuantities - Length: 6300 mm; Height: 348 mm; Width: 125 mm; GrossFootprintArea: 0.7875 m2; NetFootprintArea: 0.7875 m2; GrossSideArea: 22.3524 m2; NetSideArea: 2.1924 m2; GrossVolume: 2.79405 m3; NetVolume: 0.27405 m3
Component Quantities - ALG - LICHTE SCHEIDINGSWAND, Mass: 219.24 kg; ALG - LICHTE SCHEIDINGSWAND, Projected Component Area (Net): 2.1924 m2; ALG - LICHTE SCHEIDINGSWAND, Projected Component Area (Gross): 22.3524 m2; ALG - LICHTE SCHEIDINGSWAND, Component Thickness: 125 mm; ALG - LICHTE SCHEIDINGSWAND, Rectangular Component Height: 3560 mm; ALG - LICHTE SCHEIDINGSWAND, Rectangular Component Width: 125 mm; ALG - LICHTE SCHEIDINGSWAND, Component Cross Section Area: 0.445 m2; ALG - LICHTE SCHEIDINGSWAND, Component Volume (Net): 0.27405 m3; ALG - LICHTE SCHEIDINGSWAND, Component Volume (Gross): 2.79405 m3

# IfcWall: ALG - LICHTE SCHEIDINGSWAND 140, 22_GF 125 ECO DGS/2.75.2A
In: begane grond
Classification: Wand (ARCHICAD Classification); 22.13 systeemwanden; vast (NL/SfB (4 cijfers)); Material: ALG - LICHTE SCHEIDINGSWAND
CPset_Phasing - Renovation Phase: Bestaand
Pset_WallCommon - LoadBearing: yes; IsExternal: yes
BaseQuantities - Length: 790 mm; Height: 2400 mm; Width: 140 mm; GrossFootprintArea: 0.1106 m2; NetFootprintArea: 0.1106 m2; GrossSideArea: 1.896 m2; NetSideArea: 1.896 m2; GrossVolume: 0.26544 m3; NetVolume: 0.26544 m3
Component Quantities - ALG - LICHTE SCHEIDINGSWAND, Mass: 212.352 kg; ALG - LICHTE SCHEIDINGSWAND, Projected Component Area (Net): 1.896 m2; ALG - LICHTE SCHEIDINGSWAND, Projected Component Area (Gross): 1.896 m2; ALG - LICHTE SCHEIDINGSWAND, Component Thickness: 140 mm; ALG - LICHTE SCHEIDINGSWAND, Rectangular Component Height: 2400 mm; ALG - LICHTE SCHEIDINGSWAND, Rectangular Component Width: 140 mm; ALG - LICHTE SCHEIDINGSWAND, Component Cross Section Area: 0.336 m2; ALG - LICHTE SCHEIDINGSWAND, Component Volume (Net): 0.26544 m3; ALG - LICHTE SCHEIDINGSWAND, Component Volume (Gross): 0.26544 m3

# IfcWall: ALG - LICHTE SCHEIDINGSWAND 210 (2)
In: begane grond
Classification: Wand (ARCHICAD Classification); 21.21 massieve wanden (NL/SfB (4 cijfers)); Material: ALG - LICHTE SCHEIDINGSWAND
CPset_Phasing - Renovation Phase: Bestaand
Pset_WallCommon - LoadBearing: yes; IsExternal: no
BaseQuantities - Length: 2062.5 mm; Height: 370 mm; Width: 210 mm; GrossFootprintArea: 0.433125 m2; NetFootprintArea: 0.433125 m2; GrossSideArea: 0.75075 m2; NetSideArea: 0.75075 m2
Component Quantities - ALG - LICHTE SCHEIDINGSWAND, Mass: 124.067 kg; ALG - LICHTE SCHEIDINGSWAND, Projected Component Area (Net): 0.763125 m2; ALG - LICHTE SCHEIDINGSWAND, Projected Component Area (Gross): 0.763125 m2; ALG - LICHTE SCHEIDINGSWAND, Component Thickness: 210 mm; ALG - LICHTE SCHEIDINGSWAND, Rectangular Component Height: 690 mm; ALG - LICHTE SCHEIDINGSWAND, Rectangular Component Width: 210 mm; ALG - LICHTE SCHEIDINGSWAND, Component Cross Section Area: 0.1449 m2
Name | GrossVolume (m3) = NetVolume (m3) = ALG - LICHTE SCHEIDINGSWAND, Component Volume (Net) (m3) = ALG - LICHTE SCHEIDINGSWAND, Component Volume (Gross) (m3)
21_GF 125 ECO DGS/2.75.2A | 0.155083
21_GF 125 ECO DGS/2.75.2A | 0.155084

# IfcWall: ALG - LICHTE SCHEIDINGSWAND 33, 22_GF 125 ECO DGS/2.75.2A
In: begane grond
Classification: Wand (ARCHICAD Classification); 22.13 systeemwanden; vast (NL/SfB (4 cijfers)); Material: ALG - LICHTE SCHEIDINGSWAND
CPset_Phasing - Renovation Phase: Bestaand
Pset_WallCommon - LoadBearing: yes; IsExternal: yes
BaseQuantities - Length: 92 mm; Height: 3560 mm; Width: 33 mm; GrossFootprintArea: 0.003036 m2; NetFootprintArea: 0.003036 m2; GrossSideArea: 0.32752 m2; NetSideArea: 0.32752 m2; GrossVolume: 0.0108082 m3; NetVolume: 0.0108082 m3
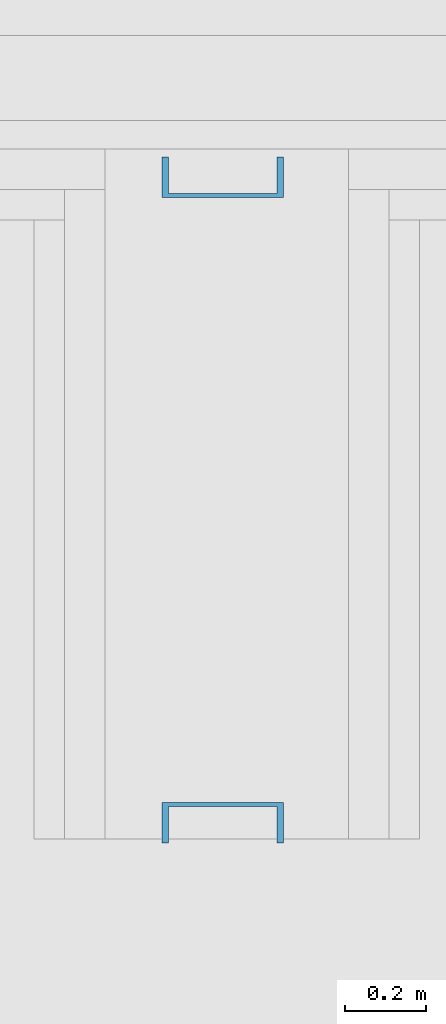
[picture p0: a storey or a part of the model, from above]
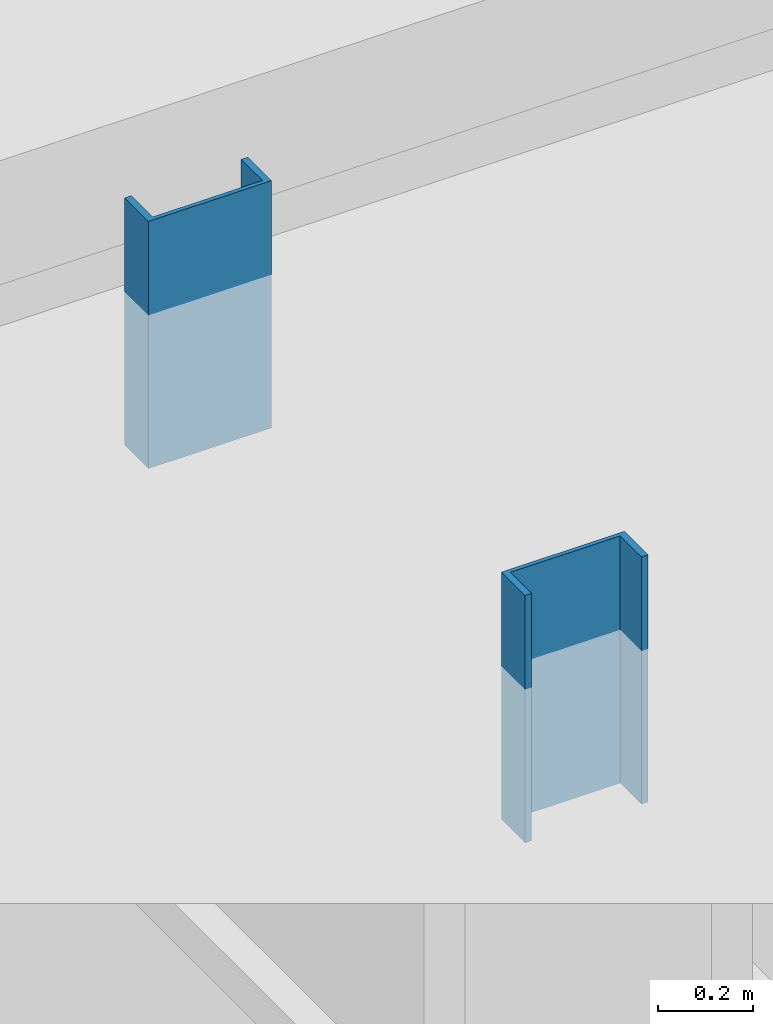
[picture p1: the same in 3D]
Properties of the parts of a building model (IFC2X3), part 8 of 9

# IfcWall: ALG - LICHTE SCHEIDINGSWAND 33, 22_GF 125 ECO DGS/2.75.2A
Component Quantities - ALG - LICHTE SCHEIDINGSWAND, Mass: 8.64653 kg; ALG - LICHTE SCHEIDINGSWAND, Projected Component Area (Net): 0.32752 m2; ALG - LICHTE SCHEIDINGSWAND, Projected Component Area (Gross): 0.32752 m2; ALG - LICHTE SCHEIDINGSWAND, Component Thickness: 33 mm; ALG - LICHTE SCHEIDINGSWAND, Rectangular Component Height: 3560 mm; ALG - LICHTE SCHEIDINGSWAND, Rectangular Component Width: 33 mm; ALG - LICHTE SCHEIDINGSWAND, Component Cross Section Area: 0.11748 m2; ALG - LICHTE SCHEIDINGSWAND, Component Volume (Net): 0.0108082 m3; ALG - LICHTE SCHEIDINGSWAND, Component Volume (Gross): 0.0108082 m3

# IfcWall: ALG - PREFAB 185 (2)
In: begane grond
Classification: Wand (ARCHICAD Classification); 22.13 systeemwanden; vast (NL/SfB (4 cijfers)); Material: ALG - PREFAB
CPset_Phasing - Renovation Phase: Bestaand
Pset_WallCommon - LoadBearing: no; IsExternal: yes
BaseQuantities - Length: 897 mm; Height: 2580 mm; Width: 185 mm; GrossFootprintArea: 0.144205 m2; NetFootprintArea: 0.144205 m2; GrossSideArea: 2.05626 m2; NetSideArea: 2.05626 m2; GrossVolume: 0.372049 m3; NetVolume: 0.372049 m3
Component Quantities - ALG - PREFAB, Mass: 855.712 kg; ALG - PREFAB, Projected Component Area (Net): 2.31426 m2; ALG - PREFAB, Projected Component Area (Gross): 2.31426 m2; ALG - PREFAB, Component Thickness: 185 mm; ALG - PREFAB, Rectangular Component Height: 2600 mm; ALG - PREFAB, Rectangular Component Width: 185 mm; ALG - PREFAB, Component Cross Section Area: 0.481 m2; ALG - PREFAB, Component Volume (Net): 0.372049 m3; ALG - PREFAB, Component Volume (Gross): 0.372049 m3

# IfcWall: ALG 050 60 (17)
Classification: Wand (ARCHICAD Classification); 21.22 spouwwanden (NL/SfB (4 cijfers)); Material: ALG - LICHTE SCHEIDINGSWAND
CPset_Phasing - Renovation Phase: Bestaand
Pset_WallCommon - LoadBearing: yes; IsExternal: yes
BaseQuantities - Width: 60 mm
Component Quantities - ALG - LICHTE SCHEIDINGSWAND, Component Thickness: 60 mm
Name | In | Length (mm) | Height (mm) | GrossFootprintArea (m2) = NetFootprintArea (m2) | GrossSideArea (m2) = NetSideArea (m2) | GrossVolume (m3) = NetVolume (m3) = ALG - LICHTE SCHEIDINGSWAND, Component Volume (Net) (m3) | ALG - LICHTE SCHEIDINGSWAND, Mass (kg) | ALG - LICHTE SCHEIDINGSWAND, Projected Component Area (Net) (m2) | ALG - LICHTE SCHEIDINGSWAND, Projected Component Area (Gross) (m2) | ALG - LICHTE SCHEIDINGSWAND, Rectangular Component Height (mm) | ALG - LICHTE SCHEIDINGSWAND, Rectangular Component Width (mm) | ALG - LICHTE SCHEIDINGSWAND, Component Cross Section Area (m2) | ALG - LICHTE SCHEIDINGSWAND, Component Volume (Gross) (m3)
5 x 21_GF 125 ECO DGS/2.75.3A | verdieping | 3000 | 950.466 | 0.18 | 2.4577 | 0.147462 | 117.97 | 2.4577 | 1.61601 | 1000 | 60 | 0.06 | 0.0960307
2 x 21_GF 125 ECO DGS/2.75.3A | verdieping | 3000 | 950.466 | 0.18 | 2.4577 | 0.147462 | 117.97 | 2.4577 | 2.54001 | 1000 | 60 | 0.06 | 0.151471
21_GF 125 ECO DGS/2.75.3A | techniek | 8620 | 700 | 0.5208 | 6.06463 | 0.363196 | 290.557 | 6.076 | 6.076 | 700 | 60 | 0.042 | 0.363196
21_GF 125 ECO DGS/2.75.3A | techniek | 2348.9 | 813.305 | 0.128256 | 1.22629 | 0.0752083 | 60.1666 | 1.30783 | 0.723324 | 813.305 | 60 | 0.0487983 | 0.0399193
21_GF 125 ECO DGS/2.75.3A | techniek | 2348.9 | 813.305 | 0.128256 | 1.22629 | 0.0752083 | 60.1667 | 1.30783 | 0.723324 | 813.305 | 60 | 0.0487983 | 0.0399193
21_GF 125 ECO DGS/2.75.3A | techniek | 8680 | 1768.95 | 0.542062 | 17.6121 | 1.06198 | 849.583 | 17.9563 | 16.8077 |  |  | 0.122556 | 0.972056
21_GF 125 ECO DGS/2.75.3A | techniek | 3120 | 962.466 | 0.1872 | 2.59329 | 0.155597 | 124.478 | 2.59329 | 2.63938 | 962.466 | 60 | 0.057748 | 0.157692
21_GF 125 ECO DGS/2.75.3A | techniek | 3060 | 962.466 | 0.1872 | 2.58689 | 0.155213 | 124.171 | 2.58689 | 1.63622 | 962.466 | 60 | 0.057748 | 0.0975447
21_GF 125 ECO DGS/2.75.3A | techniek | 2100 | 701 | 0.126 | 1.46827 | 0.08787 | 70.296 | 1.47204 | 1.47204 | 701 | 60 | 0.04206 | 0.08787
21_GF 125 ECO DGS/2.75.3A | techniek | 2100 | 962.466 | 0.126 | 2.02118 | 0.121271 | 97.0166 | 2.02118 | 2.02118 | 962.466 | 60 | 0.057748 | 0.121271
21_GF 125 ECO DGS/2.75.3A | techniek | 6607.5 | 700 | 0.39465 | 3.59236 | 0.255156 | 204.125 | 4.60425 | 2.49945 | 700 | 60 | 0.042 | 0.148933
21_GF 125 ECO DGS/2.75.3A | techniek | 6607.5 | 962.466 | 0.39465 | 5.32735 | 0.359772 | 287.817 | 6.33062 | 4.22582 | 962.466 | 60 | 0.057748 | 0.253549

# IfcWall: ALG LSW 100 (8)
Classification: Wand (ARCHICAD Classification); 22.13 systeemwanden; vast (NL/SfB (4 cijfers)); Material: ALG - LICHTE SCHEIDINGSWAND
CPset_Phasing - Renovation Phase: Bestaand
Pset_WallCommon - LoadBearing: yes; IsExternal: yes
BaseQuantities - Height: 3560 mm; Width: 100 mm
Component Quantities - ALG - LICHTE SCHEIDINGSWAND, Component Thickness: 100 mm; ALG - LICHTE SCHEIDINGSWAND, Rectangular Component Height: 3630 mm; ALG - LICHTE SCHEIDINGSWAND, Rectangular Component Width: 100 mm; ALG - LICHTE SCHEIDINGSWAND, Component Cross Section Area: 0.363 m2
Name | In | Length (mm) | GrossFootprintArea (m2) = NetFootprintArea (m2) | GrossSideArea (m2) = ALG - LICHTE SCHEIDINGSWAND, Projected Component Area (Gross) (m2) | NetSideArea (m2) = ALG - LICHTE SCHEIDINGSWAND, Projected Component Area (Net) (m2) | GrossVolume (m3) = ALG - LICHTE SCHEIDINGSWAND, Component Volume (Gross) (m3) | NetVolume (m3) = ALG - LICHTE SCHEIDINGSWAND, Component Volume (Net) (m3) | ALG - LICHTE SCHEIDINGSWAND, Mass (kg)
22_GF 125 ECO DGS/2.75.2A | begane grond | 3875 | 0.3875 | 13.7629 | 6.8079 | 1.37629 | 0.68079 | 544.632
22_GF 125 ECO DGS/2.75.2A | begane grond | 662.5 | 0.06 | 2.136 | 2.136 | 0.2136 | 0.2136 | 170.88
22_GF 125 ECO DGS/2.75.4A | begane grond | 1300 | 0.135 | 4.806 | 4.806 | 0.4806 | 0.4806 | 384.48
22_GF 125 ECO DGS/2.75.4A | begane grond | 440 | 0.039 | 1.3884 | 1.3884 | 0.13884 | 0.13884 | 111.072
22_GF 125 ECO DGS/2.75.2A | begane grond | 3925 | 0.3875 | 13.7629 | 6.8079 | 1.37629 | 0.68079 | 544.632
22_GF 125 ECO DGS/2.75.2A | begane grond | 600 | 0.06 | 2.136 | 2.136 | 0.2136 | 0.2136 | 170.88
22_GF 125 ECO DGS/2.75.2A | verdieping | 3875 | 0.3975 | 13.8589 | 6.9039 | 1.38589 | 0.69039 | 552.312
22_GF 125 ECO DGS/2.75.2A | verdieping | 3875 | 0.3875 | 13.7629 | 6.8079 | 1.37629 | 0.68079 | 544.632

# IfcWall: ALG LSW 100 kast 100 (27)
Material: ALG - LICHTE SCHEIDINGSWAND
CPset_Phasing - Renovation Phase: Bestaand
Pset_WallCommon - LoadBearing: yes; IsExternal: yes
BaseQuantities - Width: 100 mm
Component Quantities - ALG - LICHTE SCHEIDINGSWAND, Component Thickness: 100 mm; ALG - LICHTE SCHEIDINGSWAND, Rectangular Component Width: 100 mm
Name | In | Classification | Length (mm) | Height (mm) = ALG - LICHTE SCHEIDINGSWAND, Rectangular Component Height (mm) | GrossFootprintArea (m2) = NetFootprintArea (m2) | GrossSideArea (m2) = NetSideArea (m2) | GrossVolume (m3) = NetVolume (m3) = ALG - LICHTE SCHEIDINGSWAND, Component Volume (Net) (m3) = ALG - LICHTE SCHEIDINGSWAND, Component Volume (Gross) (m3) | ALG - LICHTE SCHEIDINGSWAND, Mass (kg) | ALG - LICHTE SCHEIDINGSWAND, Projected Component Area (Net) (m2) = ALG - LICHTE SCHEIDINGSWAND, Projected Component Area (Gross) (m2) | ALG - LICHTE SCHEIDINGSWAND, Component Cross Section Area (m2)
4 x 22_GF 125 ECO DGS/2.75.2A | begane grond | Wand (ARCHICAD Classification); 22.13 systeemwanden; vast (NL/SfB (4 cijfers)) | 650 | 960 | 0.06 | 0.576 | 0.0576 | 46.08 | 0.576 | 0.096
4 x 22_GF 125 ECO DGS/2.75.2A | begane grond | Wand (ARCHICAD Classification); 22.13 systeemwanden; vast (NL/SfB (4 cijfers)) | 5650 | 960 | 0.57 | 5.472 | 0.5472 | 437.76 | 5.472 | 0.096
22_GF 125 ECO DGS/2.75.2A | begane grond | Wand (ARCHICAD Classification); 22.13 systeemwanden; vast (NL/SfB (4 cijfers)) | 5589 | 960 | 0.5639 | 5.41344 | 0.541344 | 433.075 | 5.41344 | 0.096
22_GF 125 ECO DGS/2.75.2A | begane grond | Wand (ARCHICAD Classification); 22.13 systeemwanden; vast (NL/SfB (4 cijfers)) | 650 | 960 | 0.081 | 0.5886 | 0.05886 | 47.088 | 0.5886 | 0.096
22_GF 125 ECO DGS/2.75.2A | begane grond | Wand (ARCHICAD Classification); 22.13 systeemwanden; vast (NL/SfB (4 cijfers)) | 600 | 960 | 0.07 | 0.672 | 0.0672 | 53.76 | 0.672 | 0.096
22_GF 125 ECO DGS/2.75.3A | begane grond | Wand (ARCHICAD Classification); 22.13 systeemwanden; vast (NL/SfB (4 cijfers)) | 3875 | 960 | 0.3825 | 3.672 | 0.3672 | 293.76 | 3.672 | 0.096
22_GF 125 ECO DGS/2.75.4A | begane grond | Wand (ARCHICAD Classification); 22.13 systeemwanden; vast (NL/SfB (4 cijfers)) | 3875 | 960 | 0.3925 | 3.768 | 0.3768 | 301.44 | 3.768 | 0.096
22_GF 125 ECO DGS/2.75.5A | begane grond | Wand (ARCHICAD Classification); 22.13 systeemwanden; vast (NL/SfB (4 cijfers)) | 650 | 960 | 0.06 | 0.576 | 0.0576 | 46.08 | 0.576 | 0.096
21_22 betonwand | verdieping | Wand (ARCHICAD Classification); 21.22 spouwwanden (NL/SfB (4 cijfers)) | 650 | 960 | 0.05 | 0.48 | 0.048 | 38.4 | 0.48 | 0.096
21_22 betonwand | verdieping | Wand (ARCHICAD Classification); 21.22 spouwwanden (NL/SfB (4 cijfers)) | 3875 | 960 | 0.3901 | 3.672 | 0.374496 | 299.597 | 3.768 | 0.096
21_22 betonwand | verdieping | Wand (ARCHICAD Classification); 21.22 spouwwanden (NL/SfB (4 cijfers)) | 3925 | 960 | 0.3925 | 3.768 | 0.3768 | 301.44 | 3.768 | 0.096
5 x 22_GF 125 ECO DGS/2.75.2A | verdieping | Wand (ARCHICAD Classification); 22.13 systeemwanden; vast (NL/SfB (4 cijfers)) | 650 | 360 | 0.06 | 0.216 | 0.0216 | 17.28 | 0.216 | 0.036
5 x 22_GF 125 ECO DGS/2.75.2A | verdieping | Wand (ARCHICAD Classification); 22.13 systeemwanden; vast (NL/SfB (4 cijfers)) | 5650 | 960 | 0.57 | 5.472 | 0.5472 | 437.76 | 5.472 | 0.096

# IfcWall: ALG LSW 100 voorzetwand 100 (12)
Classification: Wand (ARCHICAD Classification); 22.13 systeemwanden; vast (NL/SfB (4 cijfers)); Material: ALG - LICHTE SCHEIDINGSWAND
CPset_Phasing - Renovation Phase: Bestaand
Pset_WallCommon - LoadBearing: yes; IsExternal: yes
BaseQuantities - Width: 100 mm
Component Quantities - ALG - LICHTE SCHEIDINGSWAND, Component Thickness: 100 mm; ALG - LICHTE SCHEIDINGSWAND, Rectangular Component Width: 100 mm
Name | In | Length (mm) | Height (mm) | GrossFootprintArea (m2) = NetFootprintArea (m2) | GrossSideArea (m2) = NetSideArea (m2) = ALG - LICHTE SCHEIDINGSWAND, Projected Component Area (Net) (m2) | GrossVolume (m3) = NetVolume (m3) = ALG - LICHTE SCHEIDINGSWAND, Component Volume (Net) (m3) | ALG - LICHTE SCHEIDINGSWAND, Mass (kg) | ALG - LICHTE SCHEIDINGSWAND, Projected Component Area (Gross) (m2) | ALG - LICHTE SCHEIDINGSWAND, Rectangular Component Height (mm) | ALG - LICHTE SCHEIDINGSWAND, Component Cross Section Area (m2) | ALG - LICHTE SCHEIDINGSWAND, Component Volume (Gross) (m3)
22_GF 125 ECO DGS/2.75.2A | begane grond | 4186 | 3558 | 0.4236 | 15.0209 | 1.50209 | 1201.67 | 15.0293 | 3560 | 0.356 | 1.50293
22_GF 125 ECO DGS/2.75.2A | begane grond | 845 | 3560 | 0.0895 | 3.1862 | 0.31862 | 254.896 | 3.1862 | 3560 | 0.356 | 0.31862
22_GF 125 ECO DGS/2.75.2A | begane grond | 350 | 3560 | 0.03 | 1.068 | 0.1068 | 85.44 | 1.068 | 3560 | 0.356 | 0.1068
22_GF 125 ECO DGS/2.75.3A | begane grond | 125 | 3558 | 0.0075 | 0.26595 | 0.026595 | 21.276 | 0.2661 | 3560 | 0.356 | 0.02661
22_GF 125 ECO DGS/2.75.2A | verdieping | 187.5 | 3100 | 0.0075 | 0.2325 | 0.02325 | 18.6 | 0.2325 | 3100 | 0.31 | 0.02325
22_GF 125 ECO DGS/2.75.2A | verdieping | 4018 | 3560 | 0.398 | 14.1591 | 1.41591 | 1132.73 | 14.1591 | 3560 | 0.356 | 1.41591
2 x 22_GF 125 ECO DGS/2.75.2A | verdieping | 350 | 3560 | 0.03 | 1.068 | 0.1068 | 85.44 | 1.068 | 3560 | 0.356 | 0.1068
22_GF 125 ECO DGS/2.75.2A | verdieping | 125 | 3560 | 0.0175 | 0.623 | 0.0623 | 49.84 | 0.623 | 3560 | 0.356 | 0.0623
22_GF 125 ECO DGS/2.75.2A | verdieping | 750 | 3560 | 0.075 | 2.67 | 0.267 | 213.6 | 2.67 | 3560 | 0.356 | 0.267
22_GF 125 ECO DGS/2.75.2A | verdieping | 350 | 3560 | 0.04 | 1.424 | 0.1424 | 113.92 | 1.424 | 3560 | 0.356 | 0.1424
22_GF 125 ECO DGS/2.75.2A | verdieping | 845 | 3560 | 0.0895 | 3.1862 | 0.31862 | 254.896 | 3.1862 | 3560 | 0.356 | 0.31862

# IfcWall: ALG LSW 125 125 (111)
Material: ALG - LICHTE SCHEIDINGSWAND
CPset_Phasing - Renovation Phase: Bestaand
Pset_WallCommon - LoadBearing: yes
BaseQuantities - Width: 125 mm
Component Quantities - ALG - LICHTE SCHEIDINGSWAND, Component Thickness: 125 mm; ALG - LICHTE SCHEIDINGSWAND, Rectangular Component Width: 125 mm
Name | In | Classification | IsExternal | Length (mm) | Height (mm) | GrossFootprintArea (m2) = NetFootprintArea (m2) | GrossSideArea (m2) | NetSideArea (m2) | GrossVolume (m3) | NetVolume (m3) = ALG - LICHTE SCHEIDINGSWAND, Component Volume (Net) (m3) | ALG - LICHTE SCHEIDINGSWAND, Mass (kg) | ALG - LICHTE SCHEIDINGSWAND, Projected Component Area (Net) (m2) | ALG - LICHTE SCHEIDINGSWAND, Projected Component Area (Gross) (m2) | ALG - LICHTE SCHEIDINGSWAND, Rectangular Component Height (mm) | ALG - LICHTE SCHEIDINGSWAND, Component Cross Section Area (m2) | ALG - LICHTE SCHEIDINGSWAND, Component Volume (Gross) (m3)
3 x 22_GF 125 ECO DGS/2.75.2A | begane grond | Wand (ARCHICAD Classification); 22.13 systeemwanden; vast (NL/SfB (4 cijfers)) | yes | 7800 | 3560 | 0.975 | 27.7572 | 25.4354 | 3.46965 | 3.17943 | 2543.54 | 25.4354 | 27.7572 | 3560 | 0.445 | 3.46965
22_GF 125 ECO DGS/2.75.2A | begane grond | Wand (ARCHICAD Classification); 22.13 systeemwanden; vast (NL/SfB (4 cijfers)) | yes | 23640 | 3560 | 2.98906 | 77.3033 | 30.0625 | 10.3245 | 4.41936 | 3535.49 | 36.9933 | 84.0716 | 3560 | 0.445 | 10.3245
22_GF 125 ECO DGS/2.75.2A | begane grond | Wand (ARCHICAD Classification); 22.13 systeemwanden; vast (NL/SfB (4 cijfers)) | yes | 7862.5 | 3560 | 0.959375 | 26.7536 | 25.5034 | 3.40932 | 3.25305 | 2602.44 | 26.062 | 27.3122 | 3560 | 0.445 | 3.40932
22_GF 125 ECO DGS/2.75.2A | begane grond | Wand (ARCHICAD Classification); 22.13 systeemwanden; vast (NL/SfB (4 cijfers)) | yes | 6065.5 | 3560 | 0.773813 | 22.0382 | 22.0382 | 2.75477 | 2.75477 | 2203.82 | 22.0382 | 22.0382 | 3560 | 0.445 | 2.75477
22_GF 125 ECO DGS/2.75.2A | begane grond | Wand (ARCHICAD Classification); 22.13 systeemwanden; vast (NL/SfB (4 cijfers)) | yes | 12075 | 3560 | 0.99625 | 42.5218 | 31.477 | 5.31522 | 3.93462 | 3147.7 | 31.477 | 42.5218 | 3560 | 0.445 | 5.31522
22_GF 125 ECO DGS/2.75.2A | begane grond | Wand (ARCHICAD Classification); 22.13 systeemwanden; vast (NL/SfB (4 cijfers)) | yes | 7862.5 | 3560 | 0.990625 | 27.6421 | 26.2294 | 3.52031 | 3.34372 | 2674.97 | 26.9505 | 28.2007 | 3560 | 0.445 | 3.52031
22_GF 125 ECO DGS/2.75.2A | begane grond | Wand (ARCHICAD Classification); 22.13 systeemwanden; vast (NL/SfB (4 cijfers)) | yes | 3030 | 3560 | 0.2495 | 8.2262 | 5.4598 | 1.27995 | 0.934155 | 747.324 | 7.9766 | 10.743 | 3560 | 0.445 | 1.27995
22_GF 125 ECO DGS/2.75.2A | begane grond | Wand (ARCHICAD Classification); 22.13 systeemwanden; vast (NL/SfB (4 cijfers)) | yes | 3903 | 3560 | 0.109575 | 14.1172 | 6.23108 | 1.76465 | 0.761715 | 609.372 | 6.56358 | 14.1172 | 3560 | 0.445 | 1.76465
2 x 22_GF 125 ECO DGS/2.75.2A | begane grond | Wand (ARCHICAD Classification); 22.13 systeemwanden; vast (NL/SfB (4 cijfers)) | yes | 4662.5 | 3560 | 0.57425 | 16.3673 | 14.4849 | 2.04591 | 1.81061 | 1448.49 | 14.4849 | 16.3673 | 3560 | 0.445 | 2.04591
22_GF 125 ECO DGS/2.75.2A | begane grond | Wand (ARCHICAD Classification); 22.13 systeemwanden; vast (NL/SfB (4 cijfers)) | yes | 12272.5 | 3560 | 1.41375 | 43.2165 | 23.5501 | 5.4018 | 2.94376 | 2355.01 | 23.5501 | 43.2165 | 3560 | 0.445 | 5.4018
22_GF 125 ECO DGS/2.75.2A | begane grond | Wand (ARCHICAD Classification); 22.13 systeemwanden; vast (NL/SfB (4 cijfers)) | yes | 2660 | 7520 | 0.3325 | 19.152 | 19.152 | 2.394 | 2.394 | 1915.2 | 19.152 | 19.152 | 7520 | 0.94 | 2.394
22_GF 125 ECO DGS/2.75.2A | begane grond | Wand (ARCHICAD Classification); 22.13 systeemwanden; vast (NL/SfB (4 cijfers)) | yes | 1490 | 7520 | 0.18625 | 10.728 | 10.728 | 1.341 | 1.341 | 1072.8 | 10.728 | 10.728 | 7520 | 0.94 | 1.341
22_GF 125 ECO DGS/2.75.2A | begane grond | Wand (ARCHICAD Classification); 22.13 systeemwanden; vast (NL/SfB (4 cijfers)) | yes | 3407.5 | 7520 | 0.30075 | 24.984 | 19.3661 | 3.123 | 2.42076 | 1936.61 | 19.3661 | 24.984 | 7520 | 0.94 | 3.123
22_GF 125 ECO DGS/2.75.2A | begane grond | Wand (ARCHICAD Classification); 22.13 systeemwanden; vast (NL/SfB (4 cijfers)) | yes | 1700 | 7520 | 0.2125 | 12.24 | 12.24 | 1.53 | 1.53 | 1224 | 12.24 | 12.24 | 7520 | 0.94 | 1.53
22_GF 125 ECO DGS/2.75.2A | begane grond | Wand (ARCHICAD Classification); 22.13 systeemwanden; vast (NL/SfB (4 cijfers)) | yes | 3105 | 3560 | 0.375 | 10.6584 | 6.93493 | 1.3323 | 0.866867 | 693.493 | 6.93493 | 10.6584 | 3560 | 0.445 | 1.3323
22_GF 125 ECO DGS/2.75.2A | begane grond | Wand (ARCHICAD Classification); 22.13 systeemwanden; vast (NL/SfB (4 cijfers)) | yes | 3000 | 1975.16 | 0.375 | 5.79049 | 5.79049 | 0.723812 | 0.723812 | 579.049 | 5.92549 | 10.68 | 3560 | 0.445 | 1.335
22_GF 125 ECO DGS/2.75.2A | begane grond | Wand (ARCHICAD Classification); 22.13 systeemwanden; vast (NL/SfB (4 cijfers)) | yes | 2765 | 7520 | 0.0665 | 19.152 | 7.91616 | 2.394 | 0.98952 | 791.616 | 7.91616 | 19.152 | 7520 | 0.94 | 2.394
22_GF 125 ECO DGS/2.75.2A | begane grond | Wand (ARCHICAD Classification); 22.13 systeemwanden; vast (NL/SfB (4 cijfers)) | yes | 2009.5 | 3560 | 0.266813 | 7.59882 | 7.59882 | 0.949852 | 0.949852 | 759.882 | 7.59882 | 7.59882 | 3560 | 0.445 | 0.949852
22_GF 125 ECO DGS/2.75.2A | begane grond | Wand (ARCHICAD Classification); 22.13 systeemwanden; vast (NL/SfB (4 cijfers)) | yes | 662.5 | 3560 | 0.075 | 2.136 | 2.136 | 0.267 | 0.267 | 213.6 | 2.136 | 2.136 | 3560 | 0.445 | 0.267
22_GF 125 ECO DGS/2.75.2A | begane grond | Wand (ARCHICAD Classification); 22.13 systeemwanden; vast (NL/SfB (4 cijfers)) | yes | 2102 | 3560 | 0.276813 | 7.88362 | 7.88362 | 0.985452 | 0.985452 | 788.362 | 7.88362 | 7.88362 | 3560 | 0.445 | 0.985452
22_GF 125 ECO DGS/2.75.2A | begane grond | Wand (ARCHICAD Classification); 22.13 systeemwanden; vast (NL/SfB (4 cijfers)) | yes | 2660 | 3560 | 0.3325 | 9.4696 | 9.4696 | 1.1837 | 1.1837 | 946.96 | 9.4696 | 9.4696 | 3560 | 0.445 | 1.1837
22_GF 125 ECO DGS/2.75.2A | begane grond | Wand (ARCHICAD Classification); 22.13 systeemwanden; vast (NL/SfB (4 cijfers)) | yes | 12075 | 3560 | 1.01187 | 42.5205 | 31.8007 | 5.31506 | 3.97509 | 3180.07 | 31.8007 | 42.5205 | 3560 | 0.445 | 5.31506
22_GF 125 ECO DGS/2.75.2A | begane grond | Wand (ARCHICAD Classification); 22.13 systeemwanden; vast (NL/SfB (4 cijfers)) | yes | 3000 | 3560 | 0.257625 | 9.0532 | 6.10805 | 1.38333 | 0.996905 | 797.524 | 8.4786 | 11.57 | 3560 | 0.445 | 1.38333
22_GF 125 ECO DGS/2.75.2A | begane grond | Wand (ARCHICAD Classification); 22.13 systeemwanden; vast (NL/SfB (4 cijfers)) | yes | 6137.5 | 3560 | 0.767188 | 21.8495 | 21.8495 | 2.73119 | 2.73119 | 2184.95 | 21.8495 | 21.8495 | 3560 | 0.445 | 2.73119
22_GF 125 ECO DGS/2.75.2A | begane grond | Wand (ARCHICAD Classification); 22.13 systeemwanden; vast (NL/SfB (4 cijfers)) | yes | 6287.5 | 948 | 0.785937 | 21.511 | 5.96055 | 2.68888 | 0.745069 | 596.055 | 5.96055 | 21.511 | 3560 | 0.445 | 2.68888
3 x 22_GF 125 ECO DGS/2.75.2A | begane grond | Wand (ARCHICAD Classification); 22.13 systeemwanden; vast (NL/SfB (4 cijfers)) | yes | 3000 | 3560 | 0.375 | 10.68 | 10.68 | 1.335 | 1.335 | 1068 | 10.68 | 10.68 | 3560 | 0.445 | 1.335
22_GF 125 ECO DGS/2.75.3A | begane grond | Wand (ARCHICAD Classification); 22.13 systeemwanden; vast (NL/SfB (4 cijfers)) | yes | 7062.5 | 3560 | 0.322 | 25.1286 | 11.9037 | 3.14107 | 1.48796 | 1190.37 | 11.9037 | 25.1286 | 3560 | 0.445 | 3.14107
22_GF 125 ECO DGS/2.75.3A | begane grond | Wand (ARCHICAD Classification); 22.13 systeemwanden; vast (NL/SfB (4 cijfers)) | yes | 30435 | 3560 | 3.80437 | 95.8125 | 59.6704 | 11.9224 | 7.41806 | 5934.45 | 59.767 | 102.926 | 3560 | 0.445 | 12.8093
22_GF 125 ECO DGS/2.75.3A | begane grond | Wand (ARCHICAD Classification); 22.13 systeemwanden; vast (NL/SfB (4 cijfers)) | yes | 7062.5 | 3560 | 0.247 | 25.1286 | 11.9037 | 3.14107 | 1.48796 | 1190.37 | 11.9037 | 25.1286 | 3560 | 0.445 | 3.14107
22_GF 125 ECO DGS/2.75.3A | begane grond | Wand (ARCHICAD Classification); 22.13 systeemwanden; vast (NL/SfB (4 cijfers)) | yes | 7062.5 | 3560 | 0.882812 | 25.1286 | 25.1286 | 3.14107 | 3.14107 | 2512.86 | 25.1286 | 25.1286 | 3560 | 0.445 | 3.14107
22_GF 125 ECO DGS/2.75.3A | begane grond | Wand (ARCHICAD Classification); 22.13 systeemwanden; vast (NL/SfB (4 cijfers)) | yes | 7115 | 3560 | 0.889375 | 25.3148 | 25.3148 | 3.16435 | 3.16435 | 2531.48 | 25.3148 | 25.3148 | 3560 | 0.445 | 3.16435
22_GF 125 ECO DGS/2.75.3A | begane grond | Wand (ARCHICAD Classification); 22.13 systeemwanden; vast (NL/SfB (4 cijfers)) | yes | 4475 | 3560 | 0.559375 | 15.9205 | 15.9205 | 1.99006 | 1.99006 | 1592.05 | 15.9205 | 15.9205 | 3560 | 0.445 | 1.99006
22_GF 125 ECO DGS/2.75.3A | begane grond | Wand (ARCHICAD Classification); 22.13 systeemwanden; vast (NL/SfB (4 cijfers)) | yes | 9527.5 | 3560 | 1.19875 | 33.8917 | 21.1586 | 4.25305 | 2.64483 | 2115.86 | 21.1586 | 34.0546 | 3560 | 0.445 | 4.25305
22_GF 125 ECO DGS/2.75.3A | begane grond | Wand (ARCHICAD Classification); 22.13 systeemwanden; vast (NL/SfB (4 cijfers)) | yes | 4475 | 3560 | 0.559375 | 15.9266 | 15.9266 | 1.99083 | 1.99083 | 1592.66 | 15.9266 | 15.9266 | 3560 | 0.445 | 1.99083
22_GF 125 ECO DGS/2.75.3A | begane grond | Wand (ARCHICAD Classification); 22.13 systeemwanden; vast (NL/SfB (4 cijfers)) | yes | 1250 | 960 | 0 | 4.45 | 1.2 | 0.555914 | 0.15 | 120 | 1.2 | 4.45 | 3560 | 0.445 | 0.555914
22_GF 125 ECO DGS/2.75.4A | begane grond | Wand (ARCHICAD Classification); 22.13 systeemwanden; vast (NL/SfB (4 cijfers)) | yes | 2015 | 3560 | 0.251875 | 7.16902 | 7.16902 | 0.896127 | 0.896127 | 716.902 | 7.16902 | 7.16902 | 3560 | 0.445 | 0.896127
22_GF 125 ECO DGS/2.75.4A | begane grond | Wand (ARCHICAD Classification); 22.13 systeemwanden; vast (NL/SfB (4 cijfers)) | yes | 1207.5 | 3560 | 0.143125 | 4.0762 | 4.0762 | 0.509525 | 0.509525 | 407.62 | 4.0762 | 4.0762 | 3560 | 0.445 | 0.509525
22_GF 125 ECO DGS/2.75.3A | begane grond | Wand (ARCHICAD Classification); 22.13 systeemwanden; vast (NL/SfB (4 cijfers)) | yes | 2212.5 | 3560 | 0.143563 | 7.8765 | 5.1101 | 0.984563 | 0.638763 | 511.01 | 5.1101 | 7.8765 | 3560 | 0.445 | 0.984563
22_GF 125 ECO DGS/2.75.3A | begane grond | Wand (ARCHICAD Classification); 22.13 systeemwanden; vast (NL/SfB (4 cijfers)) | yes | 1607.5 | 3560 | 0.193125 | 5.5002 | 5.5002 | 0.687525 | 0.687525 | 550.02 | 5.5002 | 5.5002 | 3560 | 0.445 | 0.687525
22_GF 125 ECO DGS/2.75.2A | begane grond | Wand (ARCHICAD Classification); 22.13 systeemwanden; vast (NL/SfB (4 cijfers)) | yes | 1000 | 3560 | 0.11125 | 2.83881 | 2.83881 | 0.355058 | 0.355058 | 284.046 | 2.8434 | 2.8434 | 3560 | 0.445 | 0.355058
2 x 22_GF 125 ECO DGS/2.75.2A | begane grond | Wand (ARCHICAD Classification); 22.13 systeemwanden; vast (NL/SfB (4 cijfers)) | yes | 765 | 3560 | 0.095625 | 2.7234 | 2.7234 | 0.340425 | 0.340425 | 272.34 | 2.7234 | 2.7234 | 3560 | 0.445 | 0.340425
22_GF 125 ECO DGS/2.75.3A | begane grond | Wand (ARCHICAD Classification); 22.13 systeemwanden; vast (NL/SfB (4 cijfers)) | yes | 7062.5 | 3560 | 0.649812 | 25.1286 | 18.7222 | 3.14107 | 2.34027 | 1872.22 | 18.7222 | 25.1286 | 3560 | 0.445 | 3.14107
22_GF 125 ECO DGS/2.75.3A | begane grond | Wand (ARCHICAD Classification); 22.13 systeemwanden; vast (NL/SfB (4 cijfers)) | yes | 7062.5 | 3560 | 0.299812 | 25.1425 | 13.0161 | 3.14281 | 1.62701 | 1301.61 | 13.0161 | 25.1425 | 3560 | 0.445 | 3.14281
22_GF 125 ECO DGS/2.75.3A | begane grond | Wand (ARCHICAD Classification); 22.13 systeemwanden; vast (NL/SfB (4 cijfers)) | yes | 8740 | 3560 | 0.2175 | 31.1144 | 12.9144 | 3.8893 | 1.6143 | 1291.44 | 12.9144 | 31.1144 | 3630 | 0.45375 | 3.8893
22_GF 125 ECO DGS/2.75.3A | begane grond | Wand (ARCHICAD Classification); 22.13 systeemwanden; vast (NL/SfB (4 cijfers)) | yes | 2237.5 | 3560 | 0.1545 | 8.0265 | 5.2601 | 1.01543 | 0.669625 | 535.7 | 5.4216 | 8.188 | 3560 | 0.445 | 1.01543
22_GF 125 ECO DGS/2.75.3A | begane grond | Wand (ARCHICAD Classification); 22.13 systeemwanden; vast (NL/SfB (4 cijfers)) | yes | 3595 | 3560 | 0.24625 | 12.7982 | 8.5732 | 1.59933 | 1.07165 | 857.32 | 8.5732 | 12.7982 | 3560 | 0.445 | 1.59933
22_GF 125 ECO DGS/2.75.3A | begane grond | Wand (ARCHICAD Classification); 22.13 systeemwanden; vast (NL/SfB (4 cijfers)) | yes | 1545 | 3560 | 0.193125 | 5.5002 | 5.5002 | 0.687525 | 0.687525 | 550.02 | 5.5002 | 5.5002 | 3560 | 0.445 | 0.687525
22_GF 125 ECO DGS/2.75.3A | begane grond | Wand (ARCHICAD Classification); 22.13 systeemwanden; vast (NL/SfB (4 cijfers)) | yes | 1145 | 3560 | 0.010125 | 4.0762 | 1.3098 | 0.509525 | 0.163725 | 130.98 | 1.3098 | 4.0762 | 3560 | 0.445 | 0.509525
22_GF 125 ECO DGS/2.75.3A | begane grond | Wand (ARCHICAD Classification); 22.13 systeemwanden; vast (NL/SfB (4 cijfers)) | yes | 2820 | 3560 | 0.0875 | 10.0392 | 4.5272 | 1.25435 | 0.5659 | 452.72 | 4.5272 | 10.0392 | 3560 | 0.445 | 1.25435
22_GF 125 ECO DGS/2.75.2A | begane grond | Wand (ARCHICAD Classification); 22.13 systeemwanden; vast (NL/SfB (4 cijfers)) | yes | 1762.5 | 7520 | 0.0207 | 12.24 | 4.79338 | 1.53 | 0.566883 | 453.506 | 5.11308 | 12.24 | 7520 | 0.94 | 1.53
2 x 22_GF 125 ECO DGS/2.75.2A | begane grond | Wand (ARCHICAD Classification); 22.13 systeemwanden; vast (NL/SfB (4 cijfers)) | yes | 662.5 | 3560 | 0.075 | 2.13045 | 2.13045 | 0.266201 | 0.266201 | 212.961 | 2.136 | 2.136 | 3560 | 0.445 | 0.266201
22_GF 125 ECO DGS/2.75.2A | begane grond | Wand (ARCHICAD Classification); 22.13 systeemwanden; vast (NL/SfB (4 cijfers)) | yes | 7800 | 3560 | 0.863375 | 27.768 | 25.4462 | 3.471 | 3.18078 | 2544.62 | 25.4462 | 27.768 | 3560 | 0.445 | 3.471
22_GF 125 ECO DGS/2.75.2A | begane grond | Wand (ARCHICAD Classification); 22.13 systeemwanden; vast (NL/SfB (4 cijfers)) | yes | 3903 | 3560 | 0.116512 | 14.1157 | 6.21138 | 1.76446 | 0.759252 | 607.402 | 6.54388 | 14.1157 | 3560 | 0.445 | 1.76446
22_GF 125 ECO DGS/2.75.2A | begane grond | Wand (ARCHICAD Classification); 22.13 systeemwanden; vast (NL/SfB (4 cijfers)) | yes | 21437.5 | 3560 | 2.35625 | 71.6355 | 32.8118 | 9.38607 | 4.53311 | 3626.49 | 37.2769 | 76.1006 | 3560 | 0.445 | 9.38607
22_GF 125 ECO DGS/2.75.2A | begane grond | Wand (ARCHICAD Classification); 22.13 systeemwanden; vast (NL/SfB (4 cijfers)) | yes | 6287.5 | 3560 | 0.785938 | 21.5361 | 5.98557 | 2.69201 | 0.748196 | 598.557 | 5.98557 | 21.5361 | 3560 | 0.445 | 2.69201
22_GF 125 ECO DGS/2.75.2A | begane grond | Wand (ARCHICAD Classification); 22.13 systeemwanden; vast (NL/SfB (4 cijfers)) | yes | 1693 | 7520 | 0.078 | 11.7896 | 6.17168 | 1.4737 | 0.77146 | 617.168 | 6.17168 | 11.7896 | 7520 | 0.94 | 1.4737
22_GF 125 ECO DGS/2.75.2A | verdieping | Wand (ARCHICAD Classification); 22.13 systeemwanden; vast (NL/SfB (4 cijfers)) | yes | 3030 | 3560 | 0.2495 | 8.2262 | 5.4598 | 1.27995 | 0.934155 | 747.324 | 7.9766 | 10.743 | 3560 | 0.445 | 1.27995
22_GF 125 ECO DGS/2.75.2A | verdieping | Wand (ARCHICAD Classification); 22.13 systeemwanden; vast (NL/SfB (4 cijfers)) | yes | 2100 | 3570 | 0.269112 | 7.44203 | 1.81083 | 0.926167 | 0.225867 | 180.694 | 1.82002 | 7.45122 | 3570 | 0.44625 | 0.926167
22_GF 125 ECO DGS/2.75.2A | verdieping | Wand (ARCHICAD Classification); 22.13 systeemwanden; vast (NL/SfB (4 cijfers)) | yes | 7862.5 | 3560 | 0.990625 | 27.6421 | 26.2294 | 3.50877 | 3.33219 | 2665.75 | 26.9505 | 28.2007 | 3560 | 0.445 | 3.50877
22_GF 125 ECO DGS/2.75.2A | verdieping | Wand (ARCHICAD Classification); 22.13 systeemwanden; vast (NL/SfB (4 cijfers)) | yes | 4568 | 3560 | 0.5725 | 15.6122 | 14.3122 | 1.94181 | 1.77931 | 1423.45 | 14.3122 | 15.6122 | 3560 | 0.445 | 1.94181
3 x 22_GF 125 ECO DGS/2.75.2A | verdieping | Wand (ARCHICAD Classification); 22.13 systeemwanden; vast (NL/SfB (4 cijfers)) | yes | 7800 | 3560 | 0.975 | 27.7572 | 25.4354 | 3.46965 | 3.17943 | 2543.54 | 25.4354 | 27.7572 | 3560 | 0.445 | 3.46965
22_GF 125 ECO DGS/2.75.2A | verdieping | Wand (ARCHICAD Classification); 22.13 systeemwanden; vast (NL/SfB (4 cijfers)) | yes | 23640 | 3560 | 2.97344 | 76.8806 | 29.8023 | 10.2639 | 4.3791 | 3503.28 | 36.564 | 83.6423 | 3560 | 0.445 | 10.2639
22_GF 125 ECO DGS/2.75.2A | verdieping | Wand (ARCHICAD Classification); 22.13 systeemwanden; vast (NL/SfB (4 cijfers)) | yes | 2765 | 3560 | 0.1995 | 9.4696 | 6.7032 | 1.1837 | 0.8379 | 670.32 | 6.7032 | 9.4696 | 3560 | 0.445 | 1.1837
22_GF 125 ECO DGS/2.75.2A | verdieping | Wand (ARCHICAD Classification); 22.13 systeemwanden; vast (NL/SfB (4 cijfers)) | yes | 7862.5 | 3560 | 0.990625 | 27.6421 | 26.2294 | 3.50869 | 3.33211 | 2665.69 | 26.9505 | 28.2007 | 3560 | 0.445 | 3.50869
22_GF 125 ECO DGS/2.75.2A | verdieping | Wand (ARCHICAD Classification); 22.13 systeemwanden; vast (NL/SfB (4 cijfers)) | yes | 3030 | 3560 | 0.2495 | 8.2262 | 5.4598 | 1.28121 | 0.935413 | 748.331 | 7.9766 | 10.743 | 3560 | 0.445 | 1.28121
22_GF 125 ECO DGS/2.75.2A | verdieping | Wand (ARCHICAD Classification); 22.13 systeemwanden; vast (NL/SfB (4 cijfers)) | yes | 4760 | 3560 | 0.336812 | 17.1533 | 8.40948 | 2.14416 | 1.05118 | 840.948 | 8.40948 | 17.1533 | 3560 | 0.445 | 2.14416
22_GF 125 ECO DGS/2.75.2A | verdieping | Wand (ARCHICAD Classification); 22.13 systeemwanden; vast (NL/SfB (4 cijfers)) | yes | 31600 | 3560 | 3.76875 | 106.371 | 58.5154 | 13.859 | 7.877 | 6301.6 | 64.3154 | 112.171 | 3560 | 0.445 | 13.859
22_GF 125 ECO DGS/2.75.2A | verdieping | Wand (ARCHICAD Classification); 22.13 systeemwanden; vast (NL/SfB (4 cijfers)) | yes | 7799.5 | 3560 | 0.974937 | 27.7506 | 25.9488 | 3.46883 | 3.2436 | 2594.88 | 25.9488 | 27.7506 | 3560 | 0.445 | 3.46883
22_GF 125 ECO DGS/2.75.2A | verdieping | Wand (ARCHICAD Classification); 22.13 systeemwanden; vast (NL/SfB (4 cijfers)) | yes | 2660 | 3560 | 0.3325 | 9.4696 | 9.4696 | 1.1837 | 1.1837 | 946.96 | 9.4696 | 9.4696 | 3560 | 0.445 | 1.1837
22_GF 125 ECO DGS/2.75.2A | verdieping | Wand (ARCHICAD Classification); 22.13 systeemwanden; vast (NL/SfB (4 cijfers)) | yes | 2125 | 960 | 0.0015 | 7.48752 | 2.02752 | 0.93594 | 0.25344 | 202.752 | 2.02752 | 7.48752 | 3560 | 0.445 | 0.93594
2 x 22_GF 125 ECO DGS/2.75.3A | verdieping | Wand (ARCHICAD Classification); 22.13 systeemwanden; vast (NL/SfB (4 cijfers)) | yes | 2660 | 3560 | 0.3325 | 9.4696 | 9.4696 | 1.1837 | 1.1837 | 946.96 | 9.4696 | 9.4696 | 3560 | 0.445 | 1.1837
2 x 22_GF 125 ECO DGS/2.75.2A | verdieping | Wand (ARCHICAD Classification); 22.13 systeemwanden; vast (NL/SfB (4 cijfers)) | yes | 4568 | 3560 | 0.5725 | 16.2891 | 15.0073 | 2.03614 | 1.87591 | 1500.73 | 15.0073 | 16.2891 | 3560 | 0.445 | 2.03614
22_GF 125 ECO DGS/2.75.2A | verdieping | Wand (ARCHICAD Classification); 22.13 systeemwanden; vast (NL/SfB (4 cijfers)) | yes | 4568 | 3560 | 0.5725 | 16.2891 | 14.9891 | 2.03614 | 1.87364 | 1498.91 | 14.9891 | 16.2891 | 3560 | 0.445 | 2.03614
22_GF 125 ECO DGS/2.75.2A | verdieping | Wand (ARCHICAD Classification); 22.13 systeemwanden; vast (NL/SfB (4 cijfers)) | yes | 4630.5 | 3560 | 0.588125 | 16.7326 | 15.2883 | 2.09158 | 1.91104 | 1528.83 | 15.4508 | 16.7326 | 3560 | 0.445 | 2.09158
22_GF 125 ECO DGS/2.75.2A | verdieping | Wand (ARCHICAD Classification); 22.13 systeemwanden; vast (NL/SfB (4 cijfers)) | yes | 17362.5 | 948 | 2.1625 | 61.3804 | 16.4004 | 7.67255 | 2.05005 | 1640.04 | 16.4004 | 61.3804 | 3560 | 0.445 | 7.67255
22_GF 125 ECO DGS/2.75.2A | verdieping | Wand (ARCHICAD Classification); 22.13 systeemwanden; vast (NL/SfB (4 cijfers)) | yes | 7800 | 3560 | 0.975 | 27.768 | 27.768 | 3.471 | 3.471 | 2776.8 | 27.768 | 27.768 | 3560 | 0.445 | 3.471
22_GF 125 ECO DGS/2.75.2A | verdieping | Wand (ARCHICAD Classification); 22.13 systeemwanden; vast (NL/SfB (4 cijfers)) | yes | 7862.5 | 3560 | 0.709 | 27.7359 | 15.2481 | 3.46699 | 1.90601 | 1524.81 | 15.2481 | 27.7359 | 3560 | 0.445 | 3.46699
22_GF 125 ECO DGS/2.75.2A | verdieping | Wand (ARCHICAD Classification); 22.13 systeemwanden; vast (NL/SfB (4 cijfers)) | yes | 2675 | 3560 | 0.334375 | 9.523 | 9.523 | 1.19037 | 1.19037 | 952.3 | 9.523 | 9.523 | 3560 | 0.445 | 1.19037
22_GF 125 ECO DGS/2.75.2A | verdieping | Wand (ARCHICAD Classification); 22.13 systeemwanden; vast (NL/SfB (4 cijfers)) | yes | 4572.5 | 3560 | 0.571562 | 16.2781 | 16.2781 | 2.03476 | 2.03476 | 1627.81 | 16.2781 | 16.2781 | 3560 | 0.445 | 2.03476
22_GF 125 ECO DGS/2.75.2A | verdieping | Wand (ARCHICAD Classification); 22.13 systeemwanden; vast (NL/SfB (4 cijfers)) | yes | 1400 | 3560 | 0.175 | 4.984 | 4.984 | 0.623 | 0.623 | 498.4 | 4.984 | 4.984 | 3560 | 0.445 | 0.623
2 x 22_GF 125 ECO DGS/2.75.2A | verdieping | Wand (ARCHICAD Classification); 22.13 systeemwanden; vast (NL/SfB (4 cijfers)) | yes | 4300 | 1398 | 0 | 6.18615 | 6.18615 | 0.773269 | 0.773269 | 618.615 | 6.18615 | 6.195 | 1400 | 0.175 | 0.774375
2 x 22_GF 125 ECO DGS/2.75.2A | verdieping | Wand (ARCHICAD Classification); 22.13 systeemwanden; vast (NL/SfB (4 cijfers)) | yes | 712.5 | 1398 | 0 | 0.9087 | 0.9087 | 0.113587 | 0.113587 | 90.87 | 0.9087 | 0.91 | 1400 | 0.175 | 0.11375
22_GF 125 ECO DGS/2.75.3A | verdieping | Wand (ARCHICAD Classification); 22.13 systeemwanden; vast (NL/SfB (4 cijfers)) | yes | 712.5 | 1400 | 0.08125 | 0.91 | 0.91 | 0.11375 | 0.11375 | 91 | 0.91 | 0.91 | 1400 | 0.175 | 0.11375
22_GF 125 ECO DGS/2.75.3A | verdieping | Wand (ARCHICAD Classification); 22.13 systeemwanden; vast (NL/SfB (4 cijfers)) | yes | 712.5 | 1398 | 0 | 0.9087 | 0.9087 | 0.113587 | 0.113587 | 90.87 | 0.9087 | 0.91 | 1400 | 0.175 | 0.11375
22_GF 125 ECO DGS/2.75.2A | verdieping | Wand (ARCHICAD Classification); 22.13 systeemwanden; vast (NL/SfB (4 cijfers)) | yes | 15787.5 | 3560 | 1.96562 | 51.2668 | 19.1706 | 6.84388 | 2.83186 | 2265.48 | 23.6678 | 55.764 | 3560 | 0.445 | 6.84388
22_GF 125 ECO DGS/2.75.2A | verdieping | Wand (ARCHICAD Classification); 22.13 systeemwanden; vast (NL/SfB (4 cijfers)) | yes | 5953 | 3880 | 0.745 | 21.2562 | 19.8162 | 2.65703 | 2.47703 | 1981.62 | 19.8162 | 21.2562 | 3880 | 0.485 | 2.65703
22_GF 125 ECO DGS/2.75.2A | verdieping | Wand (ARCHICAD Classification); 22.13 systeemwanden; vast (NL/SfB (4 cijfers)) | yes | 2550 | 1398 | 0 | 3.64878 | 3.64878 | 0.456097 | 0.456097 | 364.878 | 3.64878 | 3.654 | 1400 | 0.175 | 0.45675
22_GF 125 ECO DGS/2.75.3A | verdieping | Wand (ARCHICAD Classification); 22.13 systeemwanden; vast (NL/SfB (4 cijfers)) | yes | 772.5 | 1398 | 0 | 0.99258 | 0.99258 | 0.124072 | 0.124072 | 99.258 | 0.99258 | 0.994 | 1400 | 0.175 | 0.12425
22_GF 125 ECO DGS/2.75.2A | verdieping | Wand (ARCHICAD Classification); 22.13 systeemwanden; vast (NL/SfB (4 cijfers)) | yes | 2550 | 1400 | 0.32625 | 3.654 | 3.654 | 0.45675 | 0.45675 | 365.4 | 3.654 | 3.654 | 1400 | 0.175 | 0.45675
22_GF 125 ECO DGS/2.75.3A | verdieping | Wand (ARCHICAD Classification); 22.13 systeemwanden; vast (NL/SfB (4 cijfers)) | yes | 537.5 | 1398 | 0 | 0.66405 | 0.66405 | 0.0830063 | 0.0830063 | 66.405 | 0.66405 | 0.665 | 1400 | 0.175 | 0.083125
22_GF 125 ECO DGS/2.75.2A | verdieping | Wand (ARCHICAD Classification); 22.13 systeemwanden; vast (NL/SfB (4 cijfers)) | yes | 3295 | 960 | 0 | 11.7302 | 3.1632 | 1.46627 | 0.3954 | 316.32 | 3.1632 | 11.7302 | 3560 | 0.445 | 1.46627
22_GF 125 ECO DGS/2.75.2A | verdieping | Wand (ARCHICAD Classification); 22.13 systeemwanden; vast (NL/SfB (4 cijfers)) | yes | 150 | 3880 | 0.01875 | 0.582 | 0.582 | 0.07275 | 0.07275 | 58.2 | 0.582 | 0.582 | 3880 | 0.485 | 0.07275
5 x 22_GF 125 ECO DGS/2.75.2A | verdieping | Wand (ARCHICAD Classification); 22.13 systeemwanden; vast (NL/SfB (4 cijfers)) | yes | 270 | 3880 | 0.03375 | 1.0476 | 1.0476 | 0.13095 | 0.13095 | 104.76 | 1.0476 | 1.0476 | 3880 | 0.485 | 0.13095
21_GF 125 ECO DGS/2.75.3A | verdieping | Wand (ARCHICAD Classification); 21.21 massieve wanden (NL/SfB (4 cijfers)) | no | 3390.5 | 1400 | 0.414761 | 3.98345 | 3.98345 | 0.538538 | 0.538538 | 430.83 | 4.5696 | 4.5696 | 1400 | 0.175 | 0.538538

# IfcWall: ALG LSW 150 150 (2)
In: verdieping
Classification: Wand (ARCHICAD Classification); 22.13 systeemwanden; vast (NL/SfB (4 cijfers)); Material: ALG - LICHTE SCHEIDINGSWAND
CPset_Phasing - Renovation Phase: Bestaand
Pset_WallCommon - LoadBearing: yes; IsExternal: yes
BaseQuantities - Height: 3560 mm; Width: 150 mm
Component Quantities - ALG - LICHTE SCHEIDINGSWAND, Component Thickness: 150 mm; ALG - LICHTE SCHEIDINGSWAND, Rectangular Component Height: 3560 mm; ALG - LICHTE SCHEIDINGSWAND, Rectangular Component Width: 150 mm; ALG - LICHTE SCHEIDINGSWAND, Component Cross Section Area: 0.534 m2
Name | Length (mm) | GrossFootprintArea (m2) = NetFootprintArea (m2) | GrossSideArea (m2) | NetSideArea (m2) | GrossVolume (m3) = ALG - LICHTE SCHEIDINGSWAND, Component Volume (Gross) (m3) | NetVolume (m3) = ALG - LICHTE SCHEIDINGSWAND, Component Volume (Net) (m3) | ALG - LICHTE SCHEIDINGSWAND, Mass (kg) | ALG - LICHTE SCHEIDINGSWAND, Projected Component Area (Net) (m2) | ALG - LICHTE SCHEIDINGSWAND, Projected Component Area (Gross) (m2)
22_GF 125 ECO DGS/2.75.2A | 7739.5 | 1.16095 | 27.5445 | 25.7427 | 4.13168 | 3.86141 | 3089.13 | 25.7427 | 27.5445
22_GF 125 ECO DGS/2.75.2A | 7799.5 | 1.16993 | 27.7542 | 25.9524 | 4.16349 | 3.89322 | 3114.58 | 25.956 | 27.7578

# IfcWall: ALG LSW 205 205, 22_GF 125 ECO DGS/2.75.2A
In: verdieping
Classification: Wand (ARCHICAD Classification); 22.13 systeemwanden; vast (NL/SfB (4 cijfers))
CPset_Phasing - Renovation Phase: Bestaand
Pset_WallCommon - LoadBearing: yes; IsExternal: yes
BaseQuantities - Length: 2525 mm; Height: 1400 mm; Width: 205 mm; GrossFootprintArea: 0.494971 m2; NetFootprintArea: 0.494971 m2; GrossSideArea: 3.36385 m2; NetSideArea: 3.36385 m2; GrossVolume: 0.692959 m3; NetVolume: 0.692959 m3

# IfcWall: ALG LSW 210 210 (6)
In: verdieping
CPset_Phasing - Renovation Phase: Bestaand
Pset_WallCommon - LoadBearing: yes
BaseQuantities - Width: 210 mm
Name | Classification | IsExternal | Length (mm) | Height (mm) | GrossFootprintArea (m2) = NetFootprintArea (m2) | GrossSideArea (m2) | NetSideArea (m2) | GrossVolume (m3) | NetVolume (m3)
22_GF 125 ECO DGS/2.75.2A | Wand (ARCHICAD Classification); 22.13 systeemwanden; vast (NL/SfB (4 cijfers)) | yes | 3000 | 960 | 0 | 10.68 | 2.88 | 2.2428 | 0.6048
22_GF 125 ECO DGS/2.75.2A | Wand (ARCHICAD Classification); 22.13 systeemwanden; vast (NL/SfB (4 cijfers)) | yes | 1462.5 | 3560 | 0.01396 | 5.2065 | 1.5691 | 1.09559 | 0.331736
22_GF 125 ECO DGS/2.75.2A | Wand (ARCHICAD Classification); 22.13 systeemwanden; vast (NL/SfB (4 cijfers)) | yes | 2760 | 960 | 0 | 9.8256 | 2.6496 | 2.0331 | 0.556416
22_GF 125 ECO DGS/2.75.2A | Wand (ARCHICAD Classification); 22.13 systeemwanden; vast (NL/SfB (4 cijfers)) | yes | 1668 | 3560 | 0.35028 | 5.9378 | 5.9378 | 1.24694 | 1.24694
21_GF 125 ECO DGS/2.75.3A | Wand (ARCHICAD Classification); 21.21 massieve wanden (NL/SfB (4 cijfers)) | no | 4160 | 1400 | 0.8736 | 5.1584 | 5.1584 | 1.02336 | 1.02336
22_GF 125 ECO DGS/2.75.2A | Wand (ARCHICAD Classification); 22.13 systeemwanden; vast (NL/SfB (4 cijfers)) | yes | 1762.5 | 3560 | 0.37075 | 6.2745 | 6.2745 | 1.31987 | 1.31987

# IfcWall: ALG LSW 300 300 (4)
CPset_Phasing - Renovation Phase: Bestaand
Pset_WallCommon - LoadBearing: yes
BaseQuantities - Width: 300 mm
Name | In | Classification | IsExternal | Length (mm) | Height (mm) | GrossFootprintArea (m2) = NetFootprintArea (m2) | GrossSideArea (m2) | NetSideArea (m2) | GrossVolume (m3) | NetVolume (m3)
21_GF 125 ECO DGS/2.75.3A | begane grond | Wand (ARCHICAD Classification); 21.21 massieve wanden (NL/SfB (4 cijfers)) | no | 8845 | 3880 | 2.42178 | 26.2247 | 5.20741 | 9.36437 | 3.06394
22_GF 125 ECO DGS/2.75.2A | verdieping | Wand (ARCHICAD Classification); 22.13 systeemwanden; vast (NL/SfB (4 cijfers)) | yes | 9265 | 3640 | 2.7945 | 28.8752 | 13.5752 | 9.44264 | 4.92637
22_GF 125 ECO DGS/2.75.2A | verdieping | Wand (ARCHICAD Classification); 22.13 systeemwanden; vast (NL/SfB (4 cijfers)) | yes | 9265 | 3640 | 2.7945 | 28.8753 | 13.5753 | 9.4282 | 4.913
21_GF 125 ECO DGS/2.75.3A | verdieping | Wand (ARCHICAD Classification); 21.21 massieve wanden (NL/SfB (4 cijfers)) | no | 8860 | 3640 | 2.628 | 23.3003 | 8.66333 | 9.18223 | 4.79282

# IfcWall: ALG LSW sanitair 100 (16)
CPset_Phasing - Renovation Phase: Bestaand
BaseQuantities - Width: 100 mm
Name | In | Classification | LoadBearing = IsExternal | Length (mm) | Height (mm) | GrossFootprintArea (m2) = NetFootprintArea (m2) | GrossSideArea (m2) = NetSideArea (m2) | GrossVolume (m3) = NetVolume (m3)
21_GF 100 ECO RD V/75.2.A | begane grond | Wand (ARCHICAD Classification); 21.13 systeemwanden (NL/SfB (4 cijfers)) | no | 1700 | 7520 | 0.17 | 12.104 | 1.2104
21_GF 100 ECO RD V/75.2.A | begane grond | Wand (ARCHICAD Classification); 21.13 systeemwanden (NL/SfB (4 cijfers)) | no | 2660 | 7590 | 0.2535 | 18.0541 | 1.80541
21_GF 100 ECO RD V/75.2.A | begane grond | Wand (ARCHICAD Classification); 21.13 systeemwanden (NL/SfB (4 cijfers)) | no | 3810 | 2880 | 0.36 | 10.368 | 1.0368
22_GF 100 ECO RD V/75.2.A | begane grond | Wand (ARCHICAD Classification); 22.13 systeemwanden; vast (NL/SfB (4 cijfers)) | yes | 2212.5 | 3630 | 0.224375 | 7.79735 | 0.781403
22_GF 100 ECO RD V/75.2.A | begane grond | Wand (ARCHICAD Classification); 22.13 systeemwanden; vast (NL/SfB (4 cijfers)) | yes | 965 | 3560 | 0.099184 | 3.56 | 0.353095
22_GF 100 ECO RD V/75.2.A | begane grond | Wand (ARCHICAD Classification); 22.13 systeemwanden; vast (NL/SfB (4 cijfers)) | yes | 1145 | 3560 | 0.1145 | 4.0762 | 0.40762
22_GF 100 ECO RD V/75.2.A | begane grond | Wand (ARCHICAD Classification); 22.13 systeemwanden; vast (NL/SfB (4 cijfers)) | yes | 1212.5 | 3630 | 0.1275 | 4.3284 | 0.43284
22_GF 100 ECO RD V/75.2.A | begane grond | Wand (ARCHICAD Classification); 22.13 systeemwanden; vast (NL/SfB (4 cijfers)) | yes | 3000 | 3560 | 0.3 | 10.68 | 1.068
21_GF 100 ECO RD V/75.2.A | begane grond | Wand (ARCHICAD Classification); 21.13 systeemwanden (NL/SfB (4 cijfers)) | no | 3010 | 2880 | 0.28 | 8.064 | 0.8064
22_GF 100 ECO RD V/75.2.A | begane grond | Wand (ARCHICAD Classification); 22.13 systeemwanden; vast (NL/SfB (4 cijfers)) | yes | 362.5 | 3630 | 0.039816 | 1.28104 | 0.120685
22_GF 100 ECO RD V/75.2.A | begane grond | Wand (ARCHICAD Classification); 22.13 systeemwanden; vast (NL/SfB (4 cijfers)) | yes | 850 | 3560 | 0.087684 | 3.1506 | 0.312155
22_GF 100 ECO RD V/75.2.A | begane grond | Wand (ARCHICAD Classification); 22.13 systeemwanden; vast (NL/SfB (4 cijfers)) | yes | 512.5 | 3630 | 0.054816 | 1.81504 | 0.174085
3 x 21_GF 100 ECO RD V/75.2.A | verdieping | Wand (ARCHICAD Classification); 21.13 systeemwanden (NL/SfB (4 cijfers)) | no | 2800 | 3560 | 0.28 | 9.968 | 0.9968
21_GF 100 ECO RD V/75.2.A | verdieping | Wand (ARCHICAD Classification); 21.13 systeemwanden (NL/SfB (4 cijfers)) | no | 930 | 3560 | 0.093 | 3.3108 | 0.33108

# IfcWall: Betonwand 200 210 (25)
Material: Beton gewapend prefab wand
CPset_Phasing - Renovation Phase: Bestaand
Pset_WallCommon - LoadBearing: yes
BaseQuantities - Width: 210 mm
Component Quantities - Beton gewapend prefab wand, Component Thickness: 210 mm; Beton gewapend prefab wand, Rectangular Component Width: 210 mm
Name | In | Classification | IsExternal | Length (mm) | Height (mm) | GrossFootprintArea (m2) = NetFootprintArea (m2) | GrossSideArea (m2) | NetSideArea (m2) | GrossVolume (m3) | NetVolume (m3) = Beton gewapend prefab wand, Component Volume (Net) (m3) | Beton gewapend prefab wand, Mass (kg) | Beton gewapend prefab wand, Projected Component Area (Net) (m2) | Beton gewapend prefab wand, Projected Component Area (Gross) (m2) | Beton gewapend prefab wand, Rectangular Component Height (mm) | Beton gewapend prefab wand, Component Cross Section Area (m2) | Beton gewapend prefab wand, Component Volume (Gross) (m3)
22_GF 125 ECO DGS/2.75.2A | begane grond | Wand (ARCHICAD Classification); 22.13 systeemwanden; vast (NL/SfB (4 cijfers)) | yes | 1650 | 4070 | 0.3465 | 6.7155 | 6.7155 | 1.41026 | 1.41026 | 3384.61 | 6.7155 | 6.7155 | 4070 | 0.8547 | 1.41026
21_21 betonwand | begane grond | Wand (ARCHICAD Classification); 21.21 massieve wanden (NL/SfB (4 cijfers)) | no | 4557.5 | 8030 | 0.99225 | 36.6778 | 36.6778 | 7.66701 | 7.66701 | 18400.8 | 37.0702 | 37.0702 | 8030 | 1.6863 | 7.66701
2 x 21_21 betonwand | begane grond | Wand (ARCHICAD Classification); 21.21 massieve wanden (NL/SfB (4 cijfers)) | no | 8650 | 4070 | 1.15206 | 33.8133 | 25.3655 | 7.1008 | 5.32675 | 12784.2 | 25.3655 | 31.3995 | 4070 | 0.8547 | 6.59389
21_GF 125 ECO DGS/2.75.2A | begane grond | Wand (ARCHICAD Classification); 21.21 massieve wanden (NL/SfB (4 cijfers)) | no | 2870 | 4070 | 0.5586 | 10.8262 | 10.8262 | 2.2735 | 2.2735 | 5456.4 | 10.8262 | 10.8262 | 4070 | 0.8547 | 2.2735
22_GF 125 ECO DGS/2.75.2A | begane grond | Wand (ARCHICAD Classification); 22.13 systeemwanden; vast (NL/SfB (4 cijfers)) | yes | 1762.5 | 4130 | 0.38325 | 7.47725 | 7.47725 | 1.56577 | 1.56577 | 3757.84 | 7.52675 | 7.52675 | 4130 | 0.8673 | 1.56577
22_GF 125 ECO DGS/2.75.2A | begane grond | Wand (ARCHICAD Classification); 22.13 systeemwanden; vast (NL/SfB (4 cijfers)) | yes | 8950 | 8030 | 1.9236 | 70.1611 | 61.1064 | 14.6187 | 12.7279 | 30546.9 | 62.2692 | 68.1523 | 8030 | 1.6863 | 13.9386
21_GF 125 ECO DGS/2.75.2A | begane grond | Wand (ARCHICAD Classification); 21.21 massieve wanden (NL/SfB (4 cijfers)) | no | 2870 | 4070 | 0.6027 | 11.6809 | 11.6809 | 2.45299 | 2.45299 | 5887.17 | 11.6809 | 11.6809 | 4070 | 0.8547 | 2.45299
21_21 betonwand | begane grond | Wand (ARCHICAD Classification); 21.21 massieve wanden (NL/SfB (4 cijfers)) | no | 4557.5 | 8030 | 0.94815 | 35.6095 | 35.6095 | 7.42344 | 7.42344 | 17816.3 | 36.2155 | 36.2155 | 8030 | 1.6863 | 7.42344
21_GF 125 ECO DGS/2.75.3A | begane grond | Wand (ARCHICAD Classification); 21.21 massieve wanden (NL/SfB (4 cijfers)) | no | 4000 | 4070 | 0.61026 | 16.3405 | 13.019 | 3.43151 | 2.73399 | 6561.59 | 13.019 | 15.6629 | 4200 | 0.882 | 3.28921
21_GF 125 ECO DGS/2.75.3A | begane grond | Wand (ARCHICAD Classification); 21.21 massieve wanden (NL/SfB (4 cijfers)) | no | 3233 | 8040 | 0.67893 | 25.4212 | 25.4212 | 5.29392 | 5.29392 | 12705.4 | 25.9159 | 25.9159 | 8040 | 1.6884 | 5.29392
21_GF 125 ECO DGS/2.75.3A | begane grond | Wand (ARCHICAD Classification); 21.21 massieve wanden (NL/SfB (4 cijfers)) | no | 4200 | 4070 | 0.887 | 17.142 | 17.142 | 3.59454 | 3.59454 | 8626.9 | 17.19 | 17.19 | 4070 | 0.8547 | 3.59454
21_GF 125 ECO DGS/2.75.3A | begane grond | Wand (ARCHICAD Classification); 21.21 massieve wanden (NL/SfB (4 cijfers)) | no | 3523 | 4070 | 0.40383 | 13.6346 | 9.36261 | 2.86327 | 1.96615 | 4718.76 | 9.36261 | 13.0626 | 4070 | 0.8547 | 2.74315
21_GF 125 ECO DGS/2.75.3A | begane grond | Wand (ARCHICAD Classification); 21.21 massieve wanden (NL/SfB (4 cijfers)) | no | 11675 | 4070 | 1.90574 | 47.4623 | 39.7193 | 9.96706 | 8.34104 | 20018.5 | 39.7193 | 47.4623 | 4070 | 0.8547 | 9.96706
21_GF 125 ECO DGS/2.75.3A | begane grond | Wand (ARCHICAD Classification); 21.21 massieve wanden (NL/SfB (4 cijfers)) | no | 11950 | 4070 | 2.0475 | 47.6685 | 41.7611 | 10.0097 | 8.76984 | 21047.6 | 41.7611 | 47.6685 | 4070 | 0.8547 | 10.0097
21_GF 125 ECO DGS/2.75.3A | begane grond | Wand (ARCHICAD Classification); 21.21 massieve wanden (NL/SfB (4 cijfers)) | no | 6235 | 3630 | 1.30935 | 22.6331 | 22.6331 | 4.75294 | 4.75294 | 11407.1 | 22.6331 | 22.6331 | 4070 | 0.8547 | 4.75294
2 x 21_GF 125 ECO DGS/2.75.2A | verdieping | Wand (ARCHICAD Classification); 21.21 massieve wanden (NL/SfB (4 cijfers)) | no | 2167.5 | 3960 | 0.477225 | 8.6019 | 8.6019 | 1.7767 | 1.7767 | 4264.08 | 8.9319 | 8.9319 | 3960 | 0.8316 | 1.7767
21_GF 125 ECO DGS/2.75.2A | verdieping | Wand (ARCHICAD Classification); 21.21 massieve wanden (NL/SfB (4 cijfers)) | no | 2870 | 3960 | 0.38286 | 10.546 | 7.69448 | 2.2138 | 1.61498 | 3875.94 | 7.70408 | 10.5556 | 3960 | 0.8316 | 2.2138
21_GF 125 ECO DGS/2.75.2A | verdieping | Wand (ARCHICAD Classification); 21.21 massieve wanden (NL/SfB (4 cijfers)) | no | 2167.5 | 3960 | 0.433125 | 7.5619 | 7.5619 | 1.59405 | 1.59405 | 3825.73 | 8.1675 | 8.1675 | 3960 | 0.8316 | 1.59405
21_21 betonwand | verdieping | Wand (ARCHICAD Classification); 21.21 massieve wanden (NL/SfB (4 cijfers)) | no | 2272.5 | 3960 | 0.220325 | 7.5347 | 4.68318 | 1.58862 | 0.990647 | 2377.55 | 5.4011 | 8.1675 | 3960 | 0.8316 | 1.58862
21_21 betonwand | verdieping | Wand (ARCHICAD Classification); 21.21 massieve wanden (NL/SfB (4 cijfers)) | no | 8545 | 3960 | 1.3524 | 30.818 | 25.19 | 6.49782 | 5.31594 | 12758.3 | 27.7944 | 33.4224 | 3960 | 0.8316 | 6.49782
21_GF 125 ECO DGS/2.75.2A | verdieping | Wand (ARCHICAD Classification); 21.21 massieve wanden (NL/SfB (4 cijfers)) | no | 2765 | 3960 | 0.6063 | 10.514 | 10.514 | 2.20708 | 2.20708 | 5296.98 | 10.5236 | 10.5236 | 3960 | 0.8316 | 2.20708
21_GF 125 ECO DGS/2.75.3A | verdieping | Wand (ARCHICAD Classification); 21.21 massieve wanden (NL/SfB (4 cijfers)) | no | 6635.99 | 3640 | 1.09956 | 24.155 | 20.403 | 5.07255 | 4.28463 | 10283.1 | 20.403 | 24.155 | 3640 | 0.7644 | 5.07255
21_21 betonwand | verdieping | Wand (ARCHICAD Classification); 21.21 massieve wanden (NL/SfB (4 cijfers)) | no | 8545 | 3960 | 1.3965 | 31.8056 | 26.1776 | 6.70365 | 5.52198 | 13252.7 | 28.647 | 34.254 | 3960 | 0.8316 | 6.70365

# IfcWall: Gipsplaat 12 (5)
In: verdieping
Classification: Wand (ARCHICAD Classification); 21.22 spouwwanden (NL/SfB (4 cijfers)); Material: Gipsplaat
CPset_Phasing - Renovation Phase: Bestaand
Pset_WallCommon - LoadBearing: yes; IsExternal: yes
BaseQuantities - Height: 780 mm; Width: 12 mm
Component Quantities - Gipsplaat, Component Thickness: 12 mm; Gipsplaat, Rectangular Component Height: 780 mm; Gipsplaat, Rectangular Component Width: 12 mm; Gipsplaat, Component Cross Section Area: 0.00936 m2
Name | Length (mm) | GrossFootprintArea (m2) = NetFootprintArea (m2) | GrossSideArea (m2) = NetSideArea (m2) = Gipsplaat, Projected Component Area (Net) (m2) = Gipsplaat, Projected Component Area (Gross) (m2) | GrossVolume (m3) = NetVolume (m3) = Gipsplaat, Component Volume (Net) (m3) = Gipsplaat, Component Volume (Gross) (m3) | Gipsplaat, Mass (kg)
21_23 betonwand | 26228 | 0.31488 | 20.4672 | 0.245606 | 196.485
21_23 betonwand | 2003.01 | 0.0239641 | 1.55767 | 0.018692 | 14.9536
21_23 betonwand | 1374 | 0.016416 | 1.06704 | 0.0128045 | 10.2436
21_23 betonwand | 5854 | 0.0708962 | 4.58004 | 0.0549605 | 43.9684
21_23 betonwand | 8804 | 0.10572 | 6.8718 | 0.0824616 | 65.9693

# IfcWall: Hout - Multiplex 12 (8)
Classification: Wand (ARCHICAD Classification); 22.13 systeemwanden; vast (NL/SfB (4 cijfers)); Material: Hout - Multiplex
CPset_Phasing - Renovation Phase: Bestaand
Pset_WallCommon - LoadBearing: yes; IsExternal: yes
BaseQuantities - Width: 12 mm
Component Quantities - Hout - Multiplex, Component Thickness: 12 mm; Hout - Multiplex, Rectangular Component Width: 12 mm
Name | In | Length (mm) | Height (mm) = Hout - Multiplex, Rectangular Component Height (mm) | GrossFootprintArea (m2) = NetFootprintArea (m2) | GrossSideArea (m2) = NetSideArea (m2) = Hout - Multiplex, Projected Component Area (Net) (m2) = Hout - Multiplex, Projected Component Area (Gross) (m2) | GrossVolume (m3) = NetVolume (m3) = Hout - Multiplex, Component Volume (Net) (m3) = Hout - Multiplex, Component Volume (Gross) (m3) | Hout - Multiplex, Mass (kg) | Hout - Multiplex, Component Cross Section Area (m2)
4 x 22_GF 125 ECO DGS/2.75.2A | begane grond | 795.5 | 2547 | 0.009546 | 2.02614 | 0.0243137 | 17.0196 | 0.030564
2 x 22_GF 125 ECO DGS/2.75.2A | begane grond | 717.5 | 2422 | 0.00861 | 1.73778 | 0.0208534 | 14.5974 | 0.029064
2 x 22_GF 125 ECO DGS/2.75.2A | verdieping | 717.5 | 2422 | 0.00861 | 1.73778 | 0.0208534 | 14.5974 | 0.029064

# IfcWall: Hout - Multiplex 18 (2)
Classification: Wand (ARCHICAD Classification); 21.22 spouwwanden (NL/SfB (4 cijfers)); Material: Hout - Multiplex
CPset_Phasing - Renovation Phase: Bestaand
Pset_WallCommon - LoadBearing: yes; IsExternal: yes
BaseQuantities - Length: 2400 mm; Height: 570 mm; Width: 18 mm; GrossFootprintArea: 0.0432 m2; NetFootprintArea: 0.0432 m2; GrossSideArea: 1.368 m2; NetSideArea: 1.368 m2; GrossVolume: 0.024624 m3; NetVolume: 0.024624 m3
Component Quantities - Hout - Multiplex, Mass: 17.2368 kg; Hout - Multiplex, Projected Component Area (Net): 1.368 m2; Hout - Multiplex, Projected Component Area (Gross): 1.368 m2; Hout - Multiplex, Component Thickness: 18 mm; Hout - Multiplex, Rectangular Component Height: 570 mm; Hout - Multiplex, Rectangular Component Width: 18 mm; Hout - Multiplex, Component Cross Section Area: 0.01026 m2; Hout - Multiplex, Component Volume (Net): 0.024624 m3; Hout - Multiplex, Component Volume (Gross): 0.024624 m3
Name | In
21_23 betonwand | begane grond
21_23 betonwand | verdieping

# IfcWall: Hout - Spaanplaat slave 18 (6)
In: begane grond
Classification: Wand (ARCHICAD Classification); 22.13 systeemwanden; vast (NL/SfB (4 cijfers)); Material: Hout - Spaanplaat slave
CPset_Phasing - Renovation Phase: Bestaand
Pset_WallCommon - LoadBearing: yes; IsExternal: yes
BaseQuantities - Height: 3560 mm; Width: 18 mm
Component Quantities - Hout - Spaanplaat slave, Component Thickness: 18 mm; Hout - Spaanplaat slave, Rectangular Component Height: 3630 mm; Hout - Spaanplaat slave, Rectangular Component Width: 18 mm; Hout - Spaanplaat slave, Component Cross Section Area: 0.06534 m2
Name | Length (mm) | GrossFootprintArea (m2) = NetFootprintArea (m2) | GrossSideArea (m2) = NetSideArea (m2) = Hout - Spaanplaat slave, Projected Component Area (Net) (m2) = Hout - Spaanplaat slave, Projected Component Area (Gross) (m2) | GrossVolume (m3) = NetVolume (m3) = Hout - Spaanplaat slave, Component Volume (Net) (m3) = Hout - Spaanplaat slave, Component Volume (Gross) (m3) | Hout - Spaanplaat slave, Mass (kg)
22_GF 125 ECO DGS/2.75.3A | 591 | 0.0108 | 2.136 | 0.038448 | 23.0688
22_GF 125 ECO DGS/2.75.2A | 1682 | 0.0306 | 6.052 | 0.108936 | 65.3616
3 x 22_GF 125 ECO DGS/2.75.3A | 591 | 0.010476 | 2.07192 | 0.0372946 | 22.3767
22_GF 125 ECO DGS/2.75.2A | 1691 | 0.030276 | 5.98792 | 0.107783 | 64.6696

# IfcWall: Isolatie - EPS 186, 22_GF 125 ECO DGS/2.75.2A
In: begane grond
Classification: Wand (ARCHICAD Classification); 22.13 systeemwanden; vast (NL/SfB (4 cijfers)); Material: Isolatie - EPS
CPset_Phasing - Renovation Phase: Bestaand
Pset_WallCommon - LoadBearing: yes; IsExternal: yes
BaseQuantities - Length: 229 mm; Height: 7530 mm; Width: 186 mm; GrossFootprintArea: 0.042594 m2; NetFootprintArea: 0.042594 m2; GrossSideArea: 1.72437 m2; NetSideArea: 1.72437 m2; GrossVolume: 0.320733 m3; NetVolume: 0.320733 m3
Component Quantities - Isolatie - EPS, Mass: 9.62198 kg; Isolatie - EPS, Projected Component Area (Net): 1.72437 m2; Isolatie - EPS, Projected Component Area (Gross): 1.72437 m2; Isolatie - EPS, Component Thickness: 186 mm; Isolatie - EPS, Rectangular Component Height: 7530 mm; Isolatie - EPS, Rectangular Component Width: 186 mm; Isolatie - EPS, Component Cross Section Area: 1.40058 m2; Isolatie - EPS, Component Volume (Net): 0.320733 m3; Isolatie - EPS, Component Volume (Gross): 0.320733 m3

# IfcWall: Isolatie - Glaswol zacht 150, 21_22 kalkzandsteen
In: verdieping
Classification: Wand (ARCHICAD Classification); 21.22 spouwwanden (NL/SfB (4 cijfers)); Material: Isolatie - Glaswol zacht
CPset_Phasing - Renovation Phase: Bestaand
Pset_WallCommon - LoadBearing: no; IsExternal: yes
BaseQuantities - Length: 1649 mm; Height: 1080 mm; Width: 150 mm; GrossFootprintArea: 0.225 m2; NetFootprintArea: 0.225 m2; GrossSideArea: 1.62791 m2; NetSideArea: 1.62791 m2; GrossVolume: 0.244186 m3; NetVolume: 0.244186 m3
Component Quantities - Isolatie - Glaswol zacht, Mass: 3.41861 kg; Isolatie - Glaswol zacht, Projected Component Area (Net): 1.62791 m2; Isolatie - Glaswol zacht, Projected Component Area (Gross): 1.78092 m2; Isolatie - Glaswol zacht, Component Thickness: 150 mm; Isolatie - Glaswol zacht, Rectangular Component Height: 1080 mm; Isolatie - Glaswol zacht, Rectangular Component Width: 150 mm; Isolatie - Glaswol zacht, Component Cross Section Area: 0.162 m2; Isolatie - Glaswol zacht, Component Volume (Net): 0.244186 m3; Isolatie - Glaswol zacht, Component Volume (Gross): 0.267138 m3

# IfcWall: Isolatie - Glaswol zacht 215, 21_22 kalkzandsteen
In: verdieping
Classification: Wand (ARCHICAD Classification); 21.22 spouwwanden (NL/SfB (4 cijfers)); Material: Isolatie - Glaswol zacht
CPset_Phasing - Renovation Phase: Bestaand
Pset_WallCommon - LoadBearing: no; IsExternal: yes
BaseQuantities - Length: 564 mm; Height: 950 mm; Width: 215 mm; GrossFootprintArea: 0.12126 m2; NetFootprintArea: 0.12126 m2; GrossSideArea: 0.5358 m2; NetSideArea: 0.5358 m2; GrossVolume: 0.115197 m3; NetVolume: 0.115197 m3
Component Quantities - Isolatie - Glaswol zacht, Mass: 1.61276 kg; Isolatie - Glaswol zacht, Projected Component Area (Net): 0.5358 m2; Isolatie - Glaswol zacht, Projected Component Area (Gross): 0.5358 m2; Isolatie - Glaswol zacht, Component Thickness: 215 mm; Isolatie - Glaswol zacht, Rectangular Component Height: 950 mm; Isolatie - Glaswol zacht, Rectangular Component Width: 215 mm; Isolatie - Glaswol zacht, Component Cross Section Area: 0.20425 m2; Isolatie - Glaswol zacht, Component Volume (Net): 0.115197 m3; Isolatie - Glaswol zacht, Component Volume (Gross): 0.115197 m3

# IfcWall: Isolatie - Glaswol zacht 225, 21_22 kalkzandsteen
In: verdieping
Classification: Wand (ARCHICAD Classification); 21.22 spouwwanden (NL/SfB (4 cijfers)); Material: Isolatie - Glaswol zacht
CPset_Phasing - Renovation Phase: Bestaand
Pset_WallCommon - LoadBearing: no; IsExternal: yes
BaseQuantities - Length: 496.5 mm; Height: 1080 mm; Width: 225 mm; GrossFootprintArea: 0.125775 m2; NetFootprintArea: 0.125775 m2; GrossSideArea: 0.60372 m2; NetSideArea: 0.60372 m2; GrossVolume: 0.135837 m3; NetVolume: 0.135837 m3
Component Quantities - Isolatie - Glaswol zacht, Mass: 1.90172 kg; Isolatie - Glaswol zacht, Projected Component Area (Net): 0.60372 m2; Isolatie - Glaswol zacht, Projected Component Area (Gross): 0.60372 m2; Isolatie - Glaswol zacht, Component Thickness: 225 mm; Isolatie - Glaswol zacht, Rectangular Component Height: 1080 mm; Isolatie - Glaswol zacht, Rectangular Component Width: 225 mm; Isolatie - Glaswol zacht, Component Cross Section Area: 0.243 m2; Isolatie - Glaswol zacht, Component Volume (Net): 0.135837 m3; Isolatie - Glaswol zacht, Component Volume (Gross): 0.135837 m3

# IfcWall: Isolatie - Kunststof hard 140, 21_22 betonwand
In: begane grond
Classification: Wand (ARCHICAD Classification); 21.22 spouwwanden (NL/SfB (4 cijfers)); Material: Isolatie - Kunststof hard
CPset_Phasing - Renovation Phase: Bestaand
Pset_WallCommon - LoadBearing: no; IsExternal: yes
BaseQuantities - Length: 350 mm; Height: 4020.13 mm; Width: 140 mm; GrossFootprintArea: 0.049 m2; NetFootprintArea: 0.049 m2; GrossSideArea: 1.40492 m2; NetSideArea: 1.40492 m2; GrossVolume: 0.196689 m3; NetVolume: 0.196689 m3
Component Quantities - Isolatie - Kunststof hard, Mass: 19.6689 kg; Isolatie - Kunststof hard, Projected Component Area (Net): 1.40492 m2; Isolatie - Kunststof hard, Projected Component Area (Gross): 1.40492 m2; Isolatie - Kunststof hard, Component Thickness: 140 mm; Isolatie - Kunststof hard, Rectangular Component Height: 4020.13 mm; Isolatie - Kunststof hard, Rectangular Component Width: 140 mm; Isolatie - Kunststof hard, Component Cross Section Area: 0.562818 m2; Isolatie - Kunststof hard, Component Volume (Net): 0.196689 m3; Isolatie - Kunststof hard, Component Volume (Gross): 0.196689 m3

# IfcWall: Isolatie - Steenwol hard 150, 21_22 kalkzandsteen
In: verdieping
Classification: Wand (ARCHICAD Classification); 21.22 spouwwanden (NL/SfB (4 cijfers)); Material: Isolatie - Steenwol hard
CPset_Phasing - Renovation Phase: Bestaand
Pset_WallCommon - LoadBearing: no; IsExternal: yes
BaseQuantities - Length: 2950 mm; Height: 3960 mm; Width: 150 mm; GrossFootprintArea: 0.4425 m2; NetFootprintArea: 0.4425 m2; GrossSideArea: 11.682 m2; NetSideArea: 11.682 m2; GrossVolume: 1.7523 m3; NetVolume: 1.7523 m3
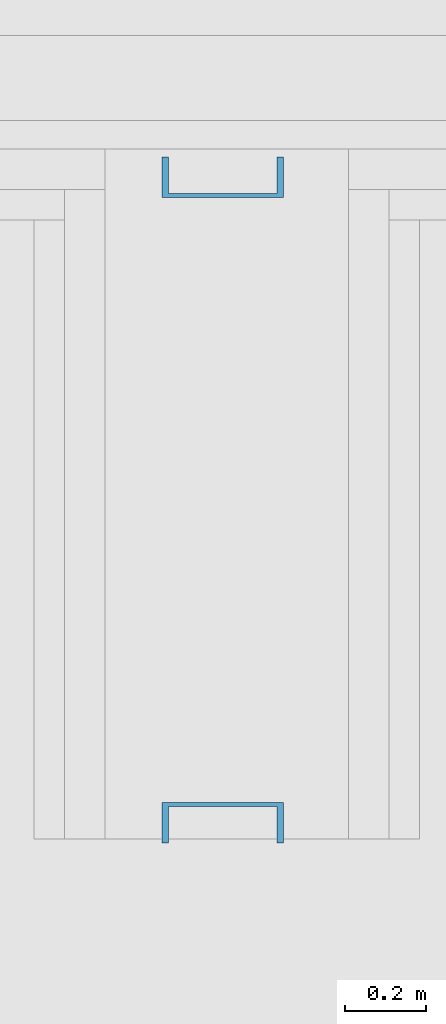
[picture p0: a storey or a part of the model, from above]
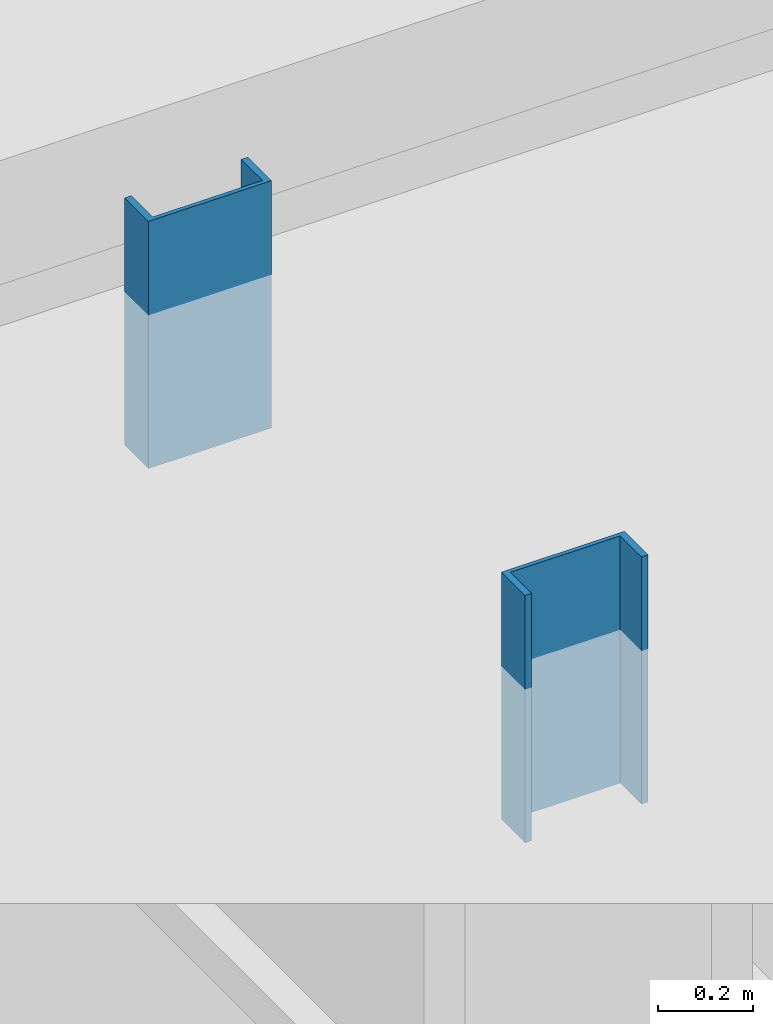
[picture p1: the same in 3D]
Properties of the parts of a building model (IFC2X3), part 9 of 9

# IfcWall: Isolatie - Steenwol hard 150, 21_22 kalkzandsteen
Component Quantities - Isolatie - Steenwol hard, Mass: 280.368 kg; Isolatie - Steenwol hard, Projected Component Area (Net): 11.682 m2; Isolatie - Steenwol hard, Projected Component Area (Gross): 11.682 m2; Isolatie - Steenwol hard, Component Thickness: 150 mm; Isolatie - Steenwol hard, Rectangular Component Height: 3964 mm; Isolatie - Steenwol hard, Rectangular Component Width: 150 mm; Isolatie - Steenwol hard, Component Cross Section Area: 0.5946 m2; Isolatie - Steenwol hard, Component Volume (Net): 1.7523 m3; Isolatie - Steenwol hard, Component Volume (Gross): 1.7523 m3

# IfcWall: KZ 150 150, 22_GF 125 ECO DGS/2.75.2A
In: verdieping
Classification: Wand (ARCHICAD Classification); 22.13 systeemwanden; vast (NL/SfB (4 cijfers)); Material: Steen - Kalkzandsteen C
CPset_Phasing - Renovation Phase: Bestaand
Pset_WallCommon - LoadBearing: yes; IsExternal: yes
BaseQuantities - Length: 1630 mm; Height: 3560 mm; Width: 150 mm; GrossFootprintArea: 0.2445 m2; NetFootprintArea: 0.2445 m2; GrossSideArea: 5.8028 m2; NetSideArea: 5.8028 m2; GrossVolume: 0.87042 m3; NetVolume: 0.87042 m3
Component Quantities - Steen - Kalkzandsteen C, Mass: 1653.8 kg; Steen - Kalkzandsteen C, Projected Component Area (Net): 5.8028 m2; Steen - Kalkzandsteen C, Projected Component Area (Gross): 5.8028 m2; Steen - Kalkzandsteen C, Component Thickness: 150 mm; Steen - Kalkzandsteen C, Rectangular Component Height: 3560 mm; Steen - Kalkzandsteen C, Rectangular Component Width: 150 mm; Steen - Kalkzandsteen C, Component Cross Section Area: 0.534 m2; Steen - Kalkzandsteen C, Component Volume (Net): 0.87042 m3; Steen - Kalkzandsteen C, Component Volume (Gross): 0.87042 m3

# IfcWall: Steen - Baksteen 70 (3)
In: begane grond
Classification: Wand (ARCHICAD Classification); 21.22 spouwwanden (NL/SfB (4 cijfers)); Material: Steen - Baksteen
CPset_Phasing - Renovation Phase: Bestaand
Pset_WallCommon - LoadBearing: no; IsExternal: yes
BaseQuantities - Width: 70 mm
Component Quantities - Steen - Baksteen, Component Thickness: 70 mm; Steen - Baksteen, Rectangular Component Width: 70 mm
Name | Length (mm) | Height (mm) | GrossFootprintArea (m2) = NetFootprintArea (m2) | GrossSideArea (m2) = NetSideArea (m2) = Steen - Baksteen, Projected Component Area (Net) (m2) = Steen - Baksteen, Projected Component Area (Gross) (m2) | GrossVolume (m3) = NetVolume (m3) = Steen - Baksteen, Component Volume (Net) (m3) = Steen - Baksteen, Component Volume (Gross) (m3) | Steen - Baksteen, Mass (kg) | Steen - Baksteen, Rectangular Component Height (mm) | Steen - Baksteen, Component Cross Section Area (m2)
21_22 betonwand | 455 | 4010 | 0.0343 | 1.6114 | 0.112798 | 180.477 | 4020.13 | 0.281409
21_21 betonwand | 245 | 3660 | 0.0196 | 1.0241 | 0.071687 | 114.699 | 3660 | 0.2562
21_21 betonwand | 138 | 1901.76 | 0.00966001 | 0.262444 | 0.018371 | 29.3937 | 1901.76 | 0.133123

# IfcWall: Steen - Kalkzandsteen C 150 (2)
Material: Steen - Kalkzandsteen C
CPset_Phasing - Renovation Phase: Bestaand
Pset_WallCommon - IsExternal: yes
BaseQuantities - Width: 150 mm
Component Quantities - Steen - Kalkzandsteen C, Component Thickness: 150 mm; Steen - Kalkzandsteen C, Rectangular Component Height: 3640 mm; Steen - Kalkzandsteen C, Rectangular Component Width: 150 mm; Steen - Kalkzandsteen C, Component Cross Section Area: 0.546 m2
Name | In | Classification | LoadBearing | Length (mm) | Height (mm) | GrossFootprintArea (m2) = NetFootprintArea (m2) | GrossSideArea (m2) = NetSideArea (m2) = Steen - Kalkzandsteen C, Projected Component Area (Net) (m2) = Steen - Kalkzandsteen C, Projected Component Area (Gross) (m2) | GrossVolume (m3) = NetVolume (m3) = Steen - Kalkzandsteen C, Component Volume (Net) (m3) = Steen - Kalkzandsteen C, Component Volume (Gross) (m3) | Steen - Kalkzandsteen C, Mass (kg)
22_GF 125 ECO DGS/2.75.2A | begane grond | Wand (ARCHICAD Classification); 22.13 systeemwanden; vast (NL/SfB (4 cijfers)) | yes | 1602 | 3630 | 0.2403 | 5.81526 | 0.872289 | 1657.35
21_22 kalkzandsteen | verdieping | Wand (ARCHICAD Classification); 21.22 spouwwanden (NL/SfB (4 cijfers)) | no | 72 | 3640 | 0.0108 | 0.26208 | 0.039312 | 74.6928

# IfcWall: balustrade ø 146 x 248 (4)
In: verdieping
Classification: Wand (ARCHICAD Classification); 21.22 spouwwanden (NL/SfB (4 cijfers))
CPset_Phasing - Renovation Phase: Bestaand
Pset_WallCommon - LoadBearing: no; IsExternal: yes
BaseQuantities - Height: 248 mm; Width: 146 mm; GrossSideArea: 0 m2; NetSideArea: 0 m2
Name | Length (mm) | GrossFootprintArea (m2) = NetFootprintArea (m2) | GrossVolume (m3) = NetVolume (m3)
21_31 waterslag | 13678 | 1.3177 | 0.0474087
21_31 waterslag | 12675 | 1.21795 | 0.0438048
21_31 waterslag | 189 | 0.016992 | 0.000584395
21_31 waterslag | 12761 | 1.2239 | 0.0440332

# IfcWall: lamellenwand 182 x 2402 (3)
In: techniek
Classification: Wand (ARCHICAD Classification); 21.22 spouwwanden (NL/SfB (4 cijfers))
CPset_Phasing - Renovation Phase: Bestaand
Pset_WallCommon - LoadBearing: yes; IsExternal: yes
BaseQuantities - Height: 2402 mm; Width: 182.004 mm
Name | Length (mm) | GrossFootprintArea (m2) = NetFootprintArea (m2) | GrossSideArea (m2) = NetSideArea (m2) | GrossVolume (m3) = NetVolume (m3)
21_GF 125 ECO DGS/2.75.2A | 20431 | 1.67473 | 77.801 | 0.229067
21_GF 125 ECO DGS/2.75.2A | 20431 | 1.67472 | 77.801 | 0.229067
21_GF 125 ECO DGS/2.75.2A | 8952 | 0.720761 | 34.3126 | 0.100398

# IfcWindow: 32 glaslatten 125mm wand (15)
Type - ParameterTakesPrecedence: no; Sizeable: no
OverallHeight: 2600 mm; OverallWidth: 25 mm; Classification: Raam (ARCHICAD Classification); 31.22 ramen draaiend aan één kant (NL/SfB (4 cijfers))
Material - Glas: Glas - algemeen
CPset_Phasing - Renovation Phase: Bestaand
Pset_WindowCommon - IsExternal: yes
BaseQuantities - GrossArea: 0.065 m2; Height: 2600 mm; Width: 25 mm; Perimeter: 5250 mm; Area: 0.065 m2; Volume: 0.008385 m3; NetVolume: 0.008385 m3
Name | In | Depth (mm)
5 x 31_- | begane grond | 125
2 x 31_- | verdieping | 150
8 x 31_- | verdieping | 125

# IfcWindow: 32 stijl 139 (20)
Type - ParameterTakesPrecedence: no; Sizeable: no
OverallHeight: 2600 mm; OverallWidth: 139 mm; Classification: Raam (ARCHICAD Classification); 32.0 algemeen (NL/SfB (4 cijfers)); Material: 32 Hout binnenkozijn oregon pine
Material - Glas: Glas - algemeen
CPset_Phasing - Renovation Phase: Bestaand
Pset_WindowCommon - IsExternal: yes
BaseQuantities - Volume: 0.0502307 m3; Depth: 125 mm; NetVolume: 0.0502307 m3
Component Quantities - 32 Hout binnenkozijn oregon pine, Mass: 27.6269 kg; 32 Hout binnenkozijn oregon pine, Component Volume (Net): 0.0502307 m3; 32 Hout binnenkozijn oregon pine, Component Volume (Gross): 0.0502307 m3
Name | In | GrossArea (m2) = Area (m2) | Height (mm) | Width (mm) | Perimeter (mm)
3 x 32_- | begane grond | 0.0182 | 2600 | 7 | 5214
5 x 32_- | begane grond | 0.3614 | 2600 | 139 | 5478
32_- | begane grond | 0 | 0 | 0 | 0
3 x 32_- | verdieping | 0.0182 | 2600 | 7 | 5214
8 x 32_- | verdieping | 0.3614 | 2600 | 139 | 5478

# IfcWindow: R1 25 (2)
In: begane grond
Type - OperationType: DOUBLE_PANEL_HORIZONTAL; ParameterTakesPrecedence: no; Sizeable: no
OverallHeight: 3210 mm; OverallWidth: 1000 mm; Classification: Raam (ARCHICAD Classification); 32.0 algemeen (NL/SfB (4 cijfers))
Pset_WindowCommon - ThermalTransmittance: 0; GlazingAreaFraction: 2.27569; IsExternal: yes
Material - Afwerking dagkant binnen: n.v.t.; Afwerking dagkant buiten: n.v.t.; Draaiend deel: n.v.t.; Frame: n.v.t.; Onderdorpel: n.v.t.; Rollaag / latei: n.v.t.; Spouwlat: n.v.t.; Vensterbank: n.v.t.; Ventilatierooster: n.v.t.; Zonwering - behuizing: n.v.t.; Zonwering - isolatie: n.v.t.; Glas: Glas - algemeen
Pset_FireRatingProperties - FireResistanceRating: ---
CPset_Phasing - Renovation Phase: Bestaand
BaseQuantities - GrossArea: 3.21 m2; Height: 3210 mm; Width: 1000 mm; Perimeter: 8420 mm; Area: 3.21 m2; Volume: 0.0683023 m3; Depth: 62 mm; NetVolume: 0.0683023 m3
Component Quantities - Component, Component Volume (Net): 0.0683023 m3; Component, Component Volume (Gross): 0.0683023 m3
Name
32_merk-AO1
32_merk-AR2

# IfcWindow: R1 25 (110)
Type - OperationType: SINGLE_PANEL; ParameterTakesPrecedence: no; Sizeable: no
Pset_WindowCommon - ThermalTransmittance: 0; IsExternal: yes
Material - Afwerking dagkant binnen: n.v.t.; Afwerking dagkant buiten: n.v.t.; Draaiend deel: n.v.t.; Frame: n.v.t.; Onderdorpel: n.v.t.; Rollaag / latei: n.v.t.; Spouwlat: n.v.t.; Vensterbank: n.v.t.; Ventilatierooster: n.v.t.; Zonwering - behuizing: n.v.t.; Zonwering - isolatie: n.v.t.; Glas: Glas - algemeen
CPset_Phasing - Renovation Phase: Bestaand
Name | In | OverallHeight (mm) = Height (mm) | OverallWidth (mm) | Classification | GlazingAreaFraction | GrossArea (m2) = Area (m2) | Width (mm) | Perimeter (mm) | Volume (m3) = NetVolume (m3) = Component, Component Volume (Net) (m3) = Component, Component Volume (Gross) (m3) | Depth (mm)
3 x 32_10.02 | begane grond | 2600 | 893 | Raam (ARCHICAD Classification); 32.0 algemeen (NL/SfB (4 cijfers)) | 2.18368 | 2.3218 | 893 | 6986 | 0.0027624 | 125
10 x 31_11.01 | begane grond | 1400 | 1831 | Raam (ARCHICAD Classification); 31.22 ramen draaiend aan één kant (NL/SfB (4 cijfers)) | 2.43576 | 2.5634 | 1831 | 6462 | 0.0025528 | 125
6 x 32_10.01 | begane grond | 2600 | 724 | Raam (ARCHICAD Classification); 32.0 algemeen (NL/SfB (4 cijfers)) | 1.75104 | 1.8824 | 724 | 6648 | 0.0026272 | 125
32_10.06 | begane grond | 2600 | 258.5 | Raam (ARCHICAD Classification); 32.0 algemeen (NL/SfB (4 cijfers)) | 0.55936 | 0.6721 | 258.5 | 5717 | 0.0022548 | 125
2 x 31_11.02 | begane grond | 1400 | 893 | Raam (ARCHICAD Classification); 31.22 ramen draaiend aan één kant (NL/SfB (4 cijfers)) | 1.16008 | 1.2502 | 893 | 4586 | 0.0018024 | 125
2 x 31_10.17 | begane grond | 2600 | 1250 | Raam (ARCHICAD Classification); 31.22 ramen draaiend aan één kant (NL/SfB (4 cijfers)) | 3.0976 | 3.25 | 1250 | 7700 | 0.003048 | 125
3 x 31_12.01 | begane grond | 600 | 2100 | Raam (ARCHICAD Classification); 31.22 ramen draaiend aan één kant (NL/SfB (4 cijfers)) | 1.1536 | 1.26 | 2100 | 5400 | 0.002128 | 125
2 x 32_10.07 | begane grond | 2600 | 461 | Raam (ARCHICAD Classification); 32.0 algemeen (NL/SfB (4 cijfers)) | 1.07776 | 1.1986 | 461 | 6122 | 0.0024168 | 125
2 x 32_10.08 | begane grond | 2600 | 520.5 | Raam (ARCHICAD Classification); 32.0 algemeen (NL/SfB (4 cijfers)) | 1.23008 | 1.3533 | 520.5 | 6241 | 0.0024644 | 125
2 x 32_10.19 | begane grond | 2600 | 1208.5 | Raam (ARCHICAD Classification); 32.0 algemeen (NL/SfB (4 cijfers)) | 2.99136 | 3.1421 | 1208.5 | 7617 | 0.0030148 | 125
2 x 32_10.05 | begane grond | 2600 | 1750 | Raam (ARCHICAD Classification); 32.0 algemeen (NL/SfB (4 cijfers)) | 4.3776 | 4.55 | 1750 | 8700 | 0.003448 | 125
31_11.05 | begane grond | 1400 | 1121 | Raam (ARCHICAD Classification); 31.22 ramen draaiend aan één kant (NL/SfB (4 cijfers)) | 1.47016 | 1.7094 | 1221 | 5242 | 0.0019848 | 125
2 x 31_11.08 | begane grond | 1400 | 1206.25 | Raam (ARCHICAD Classification); 31.22 ramen draaiend aan één kant (NL/SfB (4 cijfers)) | 1.5861 | 1.68875 | 1206.25 | 5212.5 | 0.002053 | 125
31_11.07 | begane grond | 1400 | 1042 | Raam (ARCHICAD Classification); 31.22 ramen draaiend aan één kant (NL/SfB (4 cijfers)) | 1.36272 | 1.5988 | 1142 | 5084 | 0.0019216 | 125
31_11.06 | begane grond | 1400 | 1180 | Raam (ARCHICAD Classification); 31.22 ramen draaiend aan één kant (NL/SfB (4 cijfers)) | 1.5504 | 1.792 | 1280 | 5360 | 0.002032 | 125
31_11.10 | begane grond | 1400 | 1551.25 | Raam (ARCHICAD Classification); 31.22 ramen draaiend aan één kant (NL/SfB (4 cijfers)) | 2.0553 | 2.31175 | 1651.25 | 6102.5 | 0.002329 | 125
31_11.11 | begane grond | 1400 | 670.25 | Raam (ARCHICAD Classification); 31.22 ramen draaiend aan één kant (NL/SfB (4 cijfers)) | 0.85714 | 1.07835 | 770.25 | 4340.5 | 0.0016242 | 125
31_11.09 | begane grond | 1400 | 982.625 | Raam (ARCHICAD Classification); 31.22 ramen draaiend aan één kant (NL/SfB (4 cijfers)) | 1.28197 | 1.51568 | 1082.62 | 4965.25 | 0.0018741 | 125
31_11.09 | begane grond | 1400 | 982.625 | Raam (ARCHICAD Classification); 31.22 ramen draaiend aan één kant (NL/SfB (4 cijfers)) | 1.28197 | 1.37567 | 982.625 | 4765.25 | 0.0018741 | 125
2 x 31_11.07 | begane grond | 1400 | 1042 | Raam (ARCHICAD Classification); 31.22 ramen draaiend aan één kant (NL/SfB (4 cijfers)) | 1.36272 | 1.4588 | 1042 | 4884 | 0.0019216 | 125
3 x 31_11.05 | begane grond | 1400 | 1121 | Raam (ARCHICAD Classification); 31.22 ramen draaiend aan één kant (NL/SfB (4 cijfers)) | 1.47016 | 1.5694 | 1121 | 5042 | 0.0019848 | 125
2 x 31_11.06 | begane grond | 1400 | 1180 | Raam (ARCHICAD Classification); 31.22 ramen draaiend aan één kant (NL/SfB (4 cijfers)) | 1.5504 | 1.652 | 1180 | 5160 | 0.002032 | 125
31_11.13 | begane grond | 1400 | 72.5 | Raam (ARCHICAD Classification); 31.22 ramen draaiend aan één kant (NL/SfB (4 cijfers)) | 0.0442 | 0.1015 | 72.5 | 2945 | 0.001146 | 125
32_10.16 | begane grond | 2600 | 1629 | Raam (ARCHICAD Classification); 32.0 algemeen (NL/SfB (4 cijfers)) | 4.06784 | 4.2354 | 1629 | 8458 | 0.0033512 | 125
32_10.20 | begane grond | 2600 | 1400 | Raam (ARCHICAD Classification); 32.0 algemeen (NL/SfB (4 cijfers)) | 3.4816 | 3.64 | 1400 | 8000 | 0.003168 | 125
31_10.18 | begane grond | 2600 | 1600 | Raam (ARCHICAD Classification); 31.22 ramen draaiend aan één kant (NL/SfB (4 cijfers)) | 3.9936 | 4.16 | 1600 | 8400 | 0.003328 | 210
31_merk-AH2 | begane grond | 1880 | 1625 | Raam (ARCHICAD Classification); 31.22 ramen draaiend aan één kant (NL/SfB (4 cijfers)) | 2.69698 | 3.055 | 1625 | 7010 | 0.0306501 | Pset_FireRatingProperties - FireResistanceRating: ---
31_merk-AE1 | begane grond | 1880 | 2125 | Raam (ARCHICAD Classification); 31.22 ramen draaiend aan één kant (NL/SfB (4 cijfers)) | 3.58298 | 3.995 | 2125 | 8010 | 0.0345381 | Pset_FireRatingProperties - FireResistanceRating: ---
31_12.04 | verdieping | 3000 | 618 | Raam (ARCHICAD Classification); 31.22 ramen draaiend aan één kant (NL/SfB (4 cijfers)) | 1.71088 | 1.854 | 618 | 7236 | 0.0028624 | 125
31_11.12 | verdieping | 1400 | 470.5 | Raam (ARCHICAD Classification); 31.22 ramen draaiend aan één kant (NL/SfB (4 cijfers)) | 0.58548 | 0.6587 | 470.5 | 3741 | 0.0014644 | 125
31_12.03 | verdieping | 400 | 1064 | Raam (ARCHICAD Classification); 31.22 ramen draaiend aan één kant (NL/SfB (4 cijfers)) | 0.36864 | 0.4256 | 1064 | 2928 | 0.0011392 | 125
2 x 32_10.04 | verdieping | 2600 | 693 | Raam (ARCHICAD Classification); 32.0 algemeen (NL/SfB (4 cijfers)) | 1.67168 | 1.8018 | 693 | 6586 | 0.0026024 | 150
2 x 31_11.02 | verdieping | 1400 | 893 | Raam (ARCHICAD Classification); 31.22 ramen draaiend aan één kant (NL/SfB (4 cijfers)) | 1.16008 | 1.2502 | 893 | 4586 | 0.0018024 | 125
2 x 31_10.11 | verdieping | 2600 | 552.5 | Raam (ARCHICAD Classification); 31.22 ramen draaiend aan één kant (NL/SfB (4 cijfers)) | 1.312 | 1.4365 | 552.5 | 6305 | 0.00249 | 125
3 x 32_10.02 | verdieping | 2600 | 893 | Raam (ARCHICAD Classification); 32.0 algemeen (NL/SfB (4 cijfers)) | 2.18368 | 2.3218 | 893 | 6986 | 0.0027624 | 125
10 x 31_11.01 | verdieping | 1400 | 1831 | Raam (ARCHICAD Classification); 31.22 ramen draaiend aan één kant (NL/SfB (4 cijfers)) | 2.43576 | 2.5634 | 1831 | 6462 | 0.0025528 | 125
3 x 32_10.01 | verdieping | 2600 | 724 | Raam (ARCHICAD Classification); 32.0 algemeen (NL/SfB (4 cijfers)) | 1.75104 | 1.8824 | 724 | 6648 | 0.0026272 | 125
32_10.06 | verdieping | 2600 | 258.5 | Raam (ARCHICAD Classification); 32.0 algemeen (NL/SfB (4 cijfers)) | 0.55936 | 0.6721 | 258.5 | 5717 | 0.0022548 | 125
31_10.13c | verdieping | 2600 | 1162.5 | Raam (ARCHICAD Classification); 31.22 ramen draaiend aan één kant (NL/SfB (4 cijfers)) | 2.8736 | 2.886 | 1110 | 7420 | 0.001962 | 125
2 x 32_10.09 | verdieping | 2600 | 374.5 | Raam (ARCHICAD Classification); 32.0 algemeen (NL/SfB (4 cijfers)) | 0.85632 | 0.9737 | 374.5 | 5949 | 0.0023476 | 125
2 x 31_11.04 | verdieping | 1400 | 1798 | Raam (ARCHICAD Classification); 31.22 ramen draaiend aan één kant (NL/SfB (4 cijfers)) | 2.39088 | 2.5172 | 1798 | 6396 | 0.0025264 | 125
2 x 32_10.10 | verdieping | 2600 | 536 | Raam (ARCHICAD Classification); 32.0 algemeen (NL/SfB (4 cijfers)) | 1.26976 | 1.3936 | 536 | 6272 | 0.0024768 | 125
4 x 31_11.03 | verdieping | 1400 | 1481 | Raam (ARCHICAD Classification); 31.22 ramen draaiend aan één kant (NL/SfB (4 cijfers)) | 1.95976 | 2.0734 | 1481 | 5762 | 0.0022728 | 125
32_10.04 | verdieping | 2600 | 693 | Raam (ARCHICAD Classification); 32.0 algemeen (NL/SfB (4 cijfers)) | 1.67168 | 1.8018 | 693 | 6586 | 0.0026024 | 125
3 x 31_10.03 | verdieping | 2600 | 493 | Raam (ARCHICAD Classification); 31.22 ramen draaiend aan één kant (NL/SfB (4 cijfers)) | 1.15968 | 1.2818 | 493 | 6186 | 0.0024424 | 125
31_10.14 | verdieping | 2600 | 1241.5 | Raam (ARCHICAD Classification); 31.22 ramen draaiend aan één kant (NL/SfB (4 cijfers)) | 3.07584 | 3.2279 | 1241.5 | 7683 | 0.0030412 | 125
2 x 31_10.23 | verdieping | 2600 | 2027.75 | Raam (ARCHICAD Classification); 31.22 ramen draaiend aan één kant (NL/SfB (4 cijfers)) | 5.08864 | 5.27215 | 2027.75 | 9255.5 | 0.0036702 | 125
31_10.15 | verdieping | 2600 | 1289 | Raam (ARCHICAD Classification); 31.22 ramen draaiend aan één kant (NL/SfB (4 cijfers)) | 3.19744 | 3.3514 | 1289 | 7778 | 0.0030792 | 125
2 x 31_10.22 | verdieping | 2600 | 1672 | Raam (ARCHICAD Classification); 31.22 ramen draaiend aan één kant (NL/SfB (4 cijfers)) | 4.17792 | 4.3472 | 1672 | 8544 | 0.0033856 | 125
2 x 31_10.21 | verdieping | 2600 | 1414.5 | Raam (ARCHICAD Classification); 31.22 ramen draaiend aan één kant (NL/SfB (4 cijfers)) | 3.51872 | 3.6777 | 1414.5 | 8029 | 0.0031796 | 125
31_10.13b | verdieping | 2600 | 1363.75 | Raam (ARCHICAD Classification); 31.22 ramen draaiend aan één kant (NL/SfB (4 cijfers)) | 3.3888 | 3.40925 | 1311.25 | 7822.5 | 0.002123 | 125
31_10.13a | verdieping | 2600 | 1363.75 | Raam (ARCHICAD Classification); 31.22 ramen draaiend aan één kant (NL/SfB (4 cijfers)) | 3.3888 | 3.54575 | 1363.75 | 7927.5 | 0.003139 | 125
32_10.12 | verdieping | 2600 | 731 | Raam (ARCHICAD Classification); 32.0 algemeen (NL/SfB (4 cijfers)) | 1.76896 | 1.9006 | 731 | 6662 | 0.0026328 | 125
32_12.02 | verdieping | 600 | 2400 | Raam (ARCHICAD Classification); 32.0 algemeen (NL/SfB (4 cijfers)) | 1.3216 | 1.44 | 2400 | 6000 | 0.002368 | 125

# IfcWindow: R2 bl ol 25 (4)
Type - OperationType: USERDEFINED; ParameterTakesPrecedence: no; Sizeable: no
Pset_WindowCommon - ThermalTransmittance: 0; IsExternal: yes
Material - Afwerking dagkant binnen: n.v.t.; Afwerking dagkant buiten: n.v.t.; Draaiend deel: n.v.t.; Frame: n.v.t.; Onderdorpel: n.v.t.; Rollaag / latei: n.v.t.; Spouwlat: n.v.t.; Vensterbank: n.v.t.; Ventilatierooster: n.v.t.; Zonwering - behuizing: n.v.t.; Zonwering - isolatie: n.v.t.; Glas: Glas - algemeen
CPset_Phasing - Renovation Phase: Bestaand
Name | In | OverallHeight (mm) = Height (mm) | OverallWidth (mm) | Classification | GlazingAreaFraction | FireResistanceRating | GrossArea (m2) = Area (m2) | Width (mm) | Perimeter (mm) | Volume (m3) = NetVolume (m3) = Component, Component Volume (Net) (m3) = Component, Component Volume (Gross) (m3) | Depth (mm)
32_merk-AO2 | begane grond | 3210 | 2880 | Raam (ARCHICAD Classification); 32.0 algemeen (NL/SfB (4 cijfers)) | 8.29055 | 30 minuten brandwerend | 9.24479 | 2880 | 12180 | 0.0687052 | 62
32_merk-AR1 | begane grond | 3210 | 2555 | Raam (ARCHICAD Classification); 32.0 algemeen (NL/SfB (4 cijfers)) | 7.29996 | Geen | 8.20155 | 2555 | 11530 | 0.0649145 | 62
31_merk-BE3 | verdieping | 2860 | 2289.01 | Raam (ARCHICAD Classification); 31.22 ramen draaiend aan één kant (NL/SfB (4 cijfers)) | 5.75216 | --- | 7.34737 | 2569.01 | 10858 | 0.0646103 | 430
31_merk-BK1 | verdieping | 2860 | 1650 | Raam (ARCHICAD Classification); 31.22 ramen draaiend aan één kant (NL/SfB (4 cijfers)) | 4.02811 | --- | 4.28714 | 1499 | 8718 | 0.0571569

# IfcWindow: R3 bl ol 25 (2)
In: begane grond
Type - OperationType: USERDEFINED; ParameterTakesPrecedence: no; Sizeable: no
OverallHeight: 3210 mm; Classification: Raam (ARCHICAD Classification); 31.22 ramen draaiend aan één kant (NL/SfB (4 cijfers))
Pset_WindowCommon - ThermalTransmittance: 0; IsExternal: yes
Material - Afwerking dagkant binnen: n.v.t.; Afwerking dagkant buiten: n.v.t.; Draaiend deel: n.v.t.; Frame: n.v.t.; Onderdorpel: n.v.t.; Rollaag / latei: n.v.t.; Spouwlat: n.v.t.; Vensterbank: n.v.t.; Ventilatierooster: n.v.t.; Zonwering - behuizing: n.v.t.; Zonwering - isolatie: n.v.t.; Glas: Glas - algemeen
Pset_FireRatingProperties - FireResistanceRating: ---
CPset_Phasing - Renovation Phase: Bestaand
BaseQuantities - Height: 3200 mm
Name | OverallWidth (mm) = Width (mm) | GlazingAreaFraction | GrossArea (m2) = Area (m2) | Perimeter (mm) | Volume (m3) = NetVolume (m3) = Component, Component Volume (Net) (m3) = Component, Component Volume (Gross) (m3)
31_merk-AJ4 | 3467.5 | 9.25272 | 11.096 | 13335 | 0.128177
31_merk-AJ2 | 3567.5 | 9.55752 | 11.416 | 13535 | 0.129344

# IfcWindow: Rmeerkeuze 25 (12)
Type - OperationType: DOUBLE_PANEL_HORIZONTAL; ParameterTakesPrecedence: no; Sizeable: no
Pset_WindowCommon - ThermalTransmittance: 0; IsExternal: yes
Material - Afwerking dagkant binnen: n.v.t.; Afwerking dagkant buiten: n.v.t.; Draaiend deel: n.v.t.; Frame: n.v.t.; Onderdorpel: n.v.t.; Rollaag / latei: n.v.t.; Spouwlat: n.v.t.; Vensterbank: n.v.t.; Ventilatierooster: n.v.t.; Zonwering - behuizing: n.v.t.; Zonwering - isolatie: n.v.t.; Glas: Glas - algemeen
CPset_Phasing - Renovation Phase: Bestaand
Name | In | OverallHeight (mm) | OverallWidth (mm) | Classification | GlazingAreaFraction | GrossArea (m2) = Area (m2) | Height (mm) | Width (mm) | Perimeter (mm) | Volume (m3) = NetVolume (m3) = Component, Component Volume (Net) (m3) = Component, Component Volume (Gross) (m3) | Depth (mm) | FireResistanceRating
32_merk-AN1 | begane grond | 3210 | 1802 | Raam (ARCHICAD Classification); 32.0 algemeen (NL/SfB (4 cijfers)) | 5.24561 | 5.78442 | 3210 | 1802 | 10024 | 0.0471148 | 62
2 x 32_merk-AP | begane grond | 3210 | 635 | Raam (ARCHICAD Classification); 32.0 algemeen (NL/SfB (4 cijfers)) |  | 2.03835 | 3210 | 635 | 7690 | 0.146761 | 62 | ---
31_merk-AK | begane grond | 3200 | 1150 | Raam (ARCHICAD Classification); 31.22 ramen draaiend aan één kant (NL/SfB (4 cijfers)) | 2.80117 | 3.6685 | 3190 | 1150 | 8680 | 0.0596316 | 62 | Geen
32_merk-AN6 | begane grond | 3210 | 1802 | Raam (ARCHICAD Classification); 32.0 algemeen (NL/SfB (4 cijfers)) | 5.17855 | 5.78442 | 3210 | 1802 | 10024 | 0.0519428 | 62 | ---
32_merk-AN2 | begane grond | 3210 | 625.503 | Raam (ARCHICAD Classification); 32.0 algemeen (NL/SfB (4 cijfers)) | 1.63831 | 2.00787 | 3210 | 625.503 | 7671.01 | 0.0349283 | 62 | ---
32_merk-AL | begane grond | 3210 | 700 | Raam (ARCHICAD Classification); 32.0 algemeen (NL/SfB (4 cijfers)) | 1.80442 | 2.24 | 3200 | 700 | 7800 | 0.031866 |  | ---
31_merk-BM1 | verdieping | 2860 | 570 | Raam (ARCHICAD Classification); 31.22 ramen draaiend aan één kant (NL/SfB (4 cijfers)) | 1.25997 | 1.6302 | 2860 | 570 | 6860 | 0.03407 |  | ---
31_merk-BK4 | verdieping | 2860 | 2400 | Raam (ARCHICAD Classification); 31.22 ramen draaiend aan één kant (NL/SfB (4 cijfers)) | 6.22429 | 7.0356 | 2860 | 2460 | 10640 | 0.0460594 | 430 | ---
31_merk-BK2 | verdieping | 2860 | 1730 | Raam (ARCHICAD Classification); 31.22 ramen draaiend aan één kant (NL/SfB (4 cijfers)) | 4.43012 | 4.39725 | 2860 | 1537.5 | 8795 | 0.0446864 | 430 | ---
31_merk-BL1 | verdieping | 3530 | 2010 | Raam (ARCHICAD Classification); 31.22 ramen draaiend aan één kant (NL/SfB (4 cijfers)) | 6.45646 | 7.53488 | 3550 | 2122.5 | 11345 | 0.0459968 |  | ---
31_merk-BM2 | verdieping | 2860 | 1088 | Raam (ARCHICAD Classification); 31.22 ramen draaiend aan één kant (NL/SfB (4 cijfers)) | 2.698 | 3.11168 | 2860 | 1088 | 7896 | 0.0371981 |  | ---

# IfcWindow: Rmeerkeuze 25 (7)
In: begane grond
Type - OperationType: DOUBLE_PANEL_VERTICAL; ParameterTakesPrecedence: no; Sizeable: no
OverallHeight: 1880 mm; Classification: Raam (ARCHICAD Classification); 31.22 ramen draaiend aan één kant (NL/SfB (4 cijfers))
Pset_WindowCommon - ThermalTransmittance: 0; IsExternal: yes
Material - Afwerking dagkant binnen: n.v.t.; Afwerking dagkant buiten: n.v.t.; Draaiend deel: n.v.t.; Frame: n.v.t.; Onderdorpel: n.v.t.; Rollaag / latei: n.v.t.; Spouwlat: n.v.t.; Vensterbank: n.v.t.; Ventilatierooster: n.v.t.; Zonwering - behuizing: n.v.t.; Zonwering - isolatie: n.v.t.; Glas: Glas - algemeen
Pset_FireRatingProperties - FireResistanceRating: ---
CPset_Phasing - Renovation Phase: Bestaand
BaseQuantities - Height: 1880 mm
Name | OverallWidth (mm) = Width (mm) | GlazingAreaFraction | GrossArea (m2) = Area (m2) | Perimeter (mm) | Volume (m3) = NetVolume (m3) = Component, Component Volume (Net) (m3) = Component, Component Volume (Gross) (m3)
2 x 31_merk-AF | 2700 | 4.22333 | 5.076 | 9160 | 0.0586524
3 x 31_merk-AC1 | 2700 | 4.24832 | 5.076 | 9160 | 0.0568372
2 x 31_merk-AG | 2000 | 2.98293 | 3.76 | 7760 | 0.0532092

# IfcWindow: Rmeerkeuze 25 (4)
In: begane grond
Type - OperationType: SINGLE_PANEL; ParameterTakesPrecedence: no; Sizeable: no
Pset_WindowCommon - ThermalTransmittance: 0; IsExternal: yes
Material - Afwerking dagkant binnen: n.v.t.; Afwerking dagkant buiten: n.v.t.; Draaiend deel: n.v.t.; Frame: n.v.t.; Onderdorpel: n.v.t.; Rollaag / latei: n.v.t.; Spouwlat: n.v.t.; Vensterbank: n.v.t.; Ventilatierooster: n.v.t.; Zonwering - behuizing: n.v.t.; Zonwering - isolatie: n.v.t.; Glas: Glas - algemeen
CPset_Phasing - Renovation Phase: Bestaand
Name | OverallHeight (mm) = Height (mm) | OverallWidth (mm) = Width (mm) | Classification | GlazingAreaFraction | FireResistanceRating | GrossArea (m2) = Area (m2) | Perimeter (mm) | Volume (m3) = NetVolume (m3) = Component, Component Volume (Net) (m3) = Component, Component Volume (Gross) (m3) | Depth (mm)
2 x 31_07.01 | 2600 | 848 | Raam (ARCHICAD Classification); 31.22 ramen draaiend aan één kant (NL/SfB (4 cijfers)) | 1.61656 | 30 minuten brandwerend | 2.2048 | 6896 | 0.0817654 | 125
31_07.02 | 2600 | 893 | Raam (ARCHICAD Classification); 31.22 ramen draaiend aan één kant (NL/SfB (4 cijfers)) | 1.72546 | 30 minuten brandwerend | 2.3218 | 6986 | 0.0828913 | 125
32_merk-AD | 2610 | 1520 | Raam (ARCHICAD Classification); 32.0 algemeen (NL/SfB (4 cijfers)) | 3.53282 | --- | 3.9672 | 8260 | 0.0312751 | 280

# IfcWindow: Rmeerkeuze 25 (13)
Type - OperationType: TRIPLE_PANEL_TOP; ParameterTakesPrecedence: no; Sizeable: no
Pset_WindowCommon - ThermalTransmittance: 0; IsExternal: yes
Material - Afwerking dagkant binnen: n.v.t.; Afwerking dagkant buiten: n.v.t.; Draaiend deel: n.v.t.; Frame: n.v.t.; Onderdorpel: n.v.t.; Rollaag / latei: n.v.t.; Spouwlat: n.v.t.; Vensterbank: n.v.t.; Ventilatierooster: n.v.t.; Zonwering - behuizing: n.v.t.; Zonwering - isolatie: n.v.t.; Glas: Glas - algemeen
Pset_FireRatingProperties - FireResistanceRating: ---
CPset_Phasing - Renovation Phase: Bestaand
Name | In | OverallHeight (mm) = Height (mm) | OverallWidth (mm) | Classification | GlazingAreaFraction | GrossArea (m2) = Area (m2) | Width (mm) | Perimeter (mm) | Volume (m3) = NetVolume (m3) = Component, Component Volume (Net) (m3) = Component, Component Volume (Gross) (m3) | Depth (mm)
32_merk-AN5 | begane grond | 3210 | 1919.5 | Raam (ARCHICAD Classification); 32.0 algemeen (NL/SfB (4 cijfers)) | 4.93303 | 6.1616 | 1919.5 | 10259 | 0.0978596 | 62
32_merk-AN4 | begane grond | 3210 | 2640 | Raam (ARCHICAD Classification); 32.0 algemeen (NL/SfB (4 cijfers)) | 7.18322 | 8.4744 | 2640 | 11700 | 0.0940004 | 62
32_merk-AN3 | begane grond | 3210 | 2753 | Raam (ARCHICAD Classification); 32.0 algemeen (NL/SfB (4 cijfers)) | 7.52764 | 8.83713 | 2753 | 11926 | 0.0953184 | 62
31_merk-BF2 | verdieping | 2860 | 2178.75 | Raam (ARCHICAD Classification); 31.22 ramen draaiend aan één kant (NL/SfB (4 cijfers)) | 5.30894 | 6.40282 | 2238.75 | 10197.5 | 0.0640152 | 430
31_merk-BF1 | verdieping | 2860 | 2178.75 | Raam (ARCHICAD Classification); 31.22 ramen draaiend aan één kant (NL/SfB (4 cijfers)) | 5.30407 | 6.40282 | 2238.75 | 10197.5 | 0.0643175 | 430
31_merk-BG | verdieping | 2860 | 2317.5 | Raam (ARCHICAD Classification); 31.22 ramen draaiend aan één kant (NL/SfB (4 cijfers)) | 5.63953 | 6.92835 | 2422.5 | 10565 | 0.0687511 | 430
31_merk-BH | verdieping | 2860 | 2270 | Raam (ARCHICAD Classification); 31.22 ramen draaiend aan één kant (NL/SfB (4 cijfers)) | 5.51138 | 6.7925 | 2375 | 10470 | 0.0681971 | 430
31_merk-BJ2 | verdieping | 2860 | 2002.5 | Raam (ARCHICAD Classification); 31.22 ramen draaiend aan één kant (NL/SfB (4 cijfers)) | 4.82854 | 5.89875 | 2062.5 | 9845 | 0.0622617 | 430
31_merk-BJ1 | verdieping | 2860 | 2002.5 | Raam (ARCHICAD Classification); 31.22 ramen draaiend aan één kant (NL/SfB (4 cijfers)) | 4.82854 | 5.89875 | 2062.5 | 9845 | 0.0622617 | 430
31_merk-BE2 | verdieping | 2860 | 2265 | Raam (ARCHICAD Classification); 31.22 ramen draaiend aan één kant (NL/SfB (4 cijfers)) | 5.55026 | 7.30015 | 2552.5 | 10825 | 0.0717653 | 430
31_merk-BE1 | verdieping | 2860 | 2240 | Raam (ARCHICAD Classification); 31.22 ramen draaiend aan één kant (NL/SfB (4 cijfers)) | 5.46932 | 6.578 | 2300 | 10320 | 0.0650319 | 430
31_merk-BK4 | verdieping | 2860 | 2000 | Raam (ARCHICAD Classification); 31.22 ramen draaiend aan één kant (NL/SfB (4 cijfers)) | 4.61847 | 5.7629 | 2015 | 9750 | 0.0744343 | 430
31_merk-BK3 | verdieping | 2860 | 2400 | Raam (ARCHICAD Classification); 31.22 ramen draaiend aan één kant (NL/SfB (4 cijfers)) | 5.94147 | 6.9069 | 2415 | 10550 | 0.0639843 | 430

# IfcWindow: Rnx horizontaal 25 (20)
Type - OperationType: DOUBLE_PANEL_VERTICAL; ParameterTakesPrecedence: no; Sizeable: no
Pset_WindowCommon - ThermalTransmittance: 0; IsExternal: yes
Material - Afwerking dagkant binnen: n.v.t.; Afwerking dagkant buiten: n.v.t.; Draaiend deel: n.v.t.; Frame: n.v.t.; Onderdorpel: n.v.t.; Rollaag / latei: n.v.t.; Spouwlat: n.v.t.; Vensterbank: n.v.t.; Ventilatierooster: n.v.t.; Zonwering - behuizing: n.v.t.; Zonwering - isolatie: n.v.t.; Glas: Glas - algemeen
CPset_Phasing - Renovation Phase: Bestaand
Name | In | OverallHeight (mm) = Height (mm) | OverallWidth (mm) | Classification | GlazingAreaFraction | FireResistanceRating | GrossArea (m2) = Area (m2) | Width (mm) | Perimeter (mm) | Volume (m3) = NetVolume (m3) = Component, Component Volume (Net) (m3) = Component, Component Volume (Gross) (m3) | Depth (mm)
31_merk-AH1 | begane grond | 1880 | 2975 | Raam (ARCHICAD Classification); 31.22 ramen draaiend aan één kant (NL/SfB (4 cijfers)) | 4.71949 | --- | 5.59301 | 2975 | 9710.01 | 0.0650259
31_merk-AE2 | begane grond | 1880 | 2138 | Raam (ARCHICAD Classification); 31.22 ramen draaiend aan één kant (NL/SfB (4 cijfers)) | 3.23632 | --- | 4.01944 | 2138 | 8036 | 0.0585174
32_09.05A | verdieping | 1700 | 3175 | Raam (ARCHICAD Classification); 32.0 algemeen (NL/SfB (4 cijfers)) | 5.115 | 30 minuten brandwerend | 5.9925 | 3525 | 10450 | 0.01625 | 300 | Pset_WindowCommon - FireRating: 30
2 x 32_09.02 | verdieping | 1700 | 2875 | Raam (ARCHICAD Classification); 32.0 algemeen (NL/SfB (4 cijfers)) | 4.62 | 30 minuten brandwerend | 5.2275 | 3075 | 9550 | 0.013375 | 300 | Pset_WindowCommon - FireRating: 30
2 x 32_09.01 | verdieping | 1700 | 2705 | Raam (ARCHICAD Classification); 32.0 algemeen (NL/SfB (4 cijfers)) | 4.3395 | 30 minuten brandwerend | 4.7855 | 2815 | 9030 | 0.01295 | 300 | Pset_WindowCommon - FireRating: 30
32_09.03B | verdieping | 1700 | 3175 | Raam (ARCHICAD Classification); 32.0 algemeen (NL/SfB (4 cijfers)) | 5.115 | 30 minuten brandwerend | 5.9925 | 3525 | 10450 | 0.01625 | 300 | Pset_WindowCommon - FireRating: 30
32_09.04 | verdieping | 1700 | 3010 | Raam (ARCHICAD Classification); 32.0 algemeen (NL/SfB (4 cijfers)) | 4.84275 | 30 minuten brandwerend | 5.134 | 3020 | 9440 | 0.0137125 | 300 | Pset_WindowCommon - FireRating: 30
32_09.03A | verdieping | 1700 | 2815 | Raam (ARCHICAD Classification); 32.0 algemeen (NL/SfB (4 cijfers)) | 4.521 | 30 minuten brandwerend | 5.219 | 3070 | 9540 | 0.01535 | 300 | Pset_WindowCommon - FireRating: 30
32_09.05B | verdieping | 1700 | 2815 | Raam (ARCHICAD Classification); 32.0 algemeen (NL/SfB (4 cijfers)) | 4.521 | 30 minuten brandwerend | 5.219 | 3070 | 9540 | 0.01535 | 300 | Pset_WindowCommon - FireRating: 30
2 x 31_merk-BD2 | verdieping | 1800 | 2805 | Raam (ARCHICAD Classification); 31.22 ramen draaiend aan één kant (NL/SfB (4 cijfers)) | 4.21591 | --- | 5.049 | 2805 | 9210 | 0.0571685 | 430
31_merk-BD4 | verdieping | 1800 | 3795 | Raam (ARCHICAD Classification); 31.22 ramen draaiend aan één kant (NL/SfB (4 cijfers)) | 5.89099 | --- | 6.831 | 3795 | 11190 | 0.0648667 | 430
31_merk-BC1 | verdieping | 1800 | 2725 | Raam (ARCHICAD Classification); 31.22 ramen draaiend aan één kant (NL/SfB (4 cijfers)) | 4.08055 | --- | 4.905 | 2725 | 9050 | 0.0565464 | 430
2 x 31_merk-BB1 | verdieping | 1800 | 2625 | Raam (ARCHICAD Classification); 31.22 ramen draaiend aan één kant (NL/SfB (4 cijfers)) | 3.91135 | --- | 4.725 | 2625 | 8850 | 0.0557688 | 430
3 x 31_merk-BA2 | verdieping | 1800 | 2725 | Raam (ARCHICAD Classification); 31.22 ramen draaiend aan één kant (NL/SfB (4 cijfers)) | 4.08055 | --- | 4.905 | 2725 | 9050 | 0.0565464 | 430

# IfcWindow: Rnx horizontaal 25, 31_07.03
In: verdieping
Type - OperationType: SINGLE_PANEL; ParameterTakesPrecedence: no; Sizeable: no
OverallHeight: 2600 mm; OverallWidth: 1800 mm; Classification: Raam (ARCHICAD Classification); 31.22 ramen draaiend aan één kant (NL/SfB (4 cijfers))
Pset_WindowCommon - ThermalTransmittance: 0; GlazingAreaFraction: 3.9204; IsExternal: yes
Material - Afwerking dagkant binnen: n.v.t.; Afwerking dagkant buiten: n.v.t.; Draaiend deel: n.v.t.; Frame: n.v.t.; Onderdorpel: n.v.t.; Rollaag / latei: n.v.t.; Spouwlat: n.v.t.; Vensterbank: n.v.t.; Ventilatierooster: n.v.t.; Zonwering - behuizing: n.v.t.; Zonwering - isolatie: n.v.t.; Glas: Glas - algemeen
Pset_FireRatingProperties - FireResistanceRating: 30 minuten brandwerend
CPset_Phasing - Renovation Phase: Bestaand
BaseQuantities - GrossArea: 4.518 m2; Height: 2510 mm; Width: 1800 mm; Perimeter: 8620 mm; Area: 4.518 m2; Volume: 0.250668 m3; Depth: 125 mm; NetVolume: 0.250668 m3
Component Quantities - Component, Component Volume (Net): 0.250668 m3; Component, Component Volume (Gross): 0.250668 m3

# IfcWindow: Rnx horizontaal 25 (15)
Type - OperationType: TRIPLE_PANEL_VERTICAL; ParameterTakesPrecedence: no; Sizeable: no
Pset_WindowCommon - ThermalTransmittance: 0; IsExternal: yes
Material - Afwerking dagkant binnen: n.v.t.; Afwerking dagkant buiten: n.v.t.; Draaiend deel: n.v.t.; Frame: n.v.t.; Onderdorpel: n.v.t.; Rollaag / latei: n.v.t.; Spouwlat: n.v.t.; Vensterbank: n.v.t.; Ventilatierooster: n.v.t.; Zonwering - behuizing: n.v.t.; Zonwering - isolatie: n.v.t.; Glas: Glas - algemeen
CPset_Phasing - Renovation Phase: Bestaand
Name | In | OverallHeight (mm) = Height (mm) | OverallWidth (mm) = Width (mm) | Classification | GlazingAreaFraction | FireResistanceRating | GrossArea (m2) = Area (m2) | Perimeter (mm) | Volume (m3) = NetVolume (m3) = Component, Component Volume (Net) (m3) = Component, Component Volume (Gross) (m3) | Depth (mm)
31_merk-AB2 | begane grond | 1880 | 3475 | Raam (ARCHICAD Classification); 31.22 ramen draaiend aan één kant (NL/SfB (4 cijfers)) | 5.25192 | --- | 6.533 | 10710 | 0.0867418
3 x 31_merk-AA1 | begane grond | 1880 | 3575 | Raam (ARCHICAD Classification); 31.22 ramen draaiend aan één kant (NL/SfB (4 cijfers)) | 5.42912 | --- | 6.721 | 10910 | 0.0875194
32_merk-AQ | begane grond | 435 | 6600 | Raam (ARCHICAD Classification); 32.0 algemeen (NL/SfB (4 cijfers)) | 2.08757 | --- | 2.871 | 14070 | 0.0564071 | 62
31_07.04 | verdieping | 2600 | 3000 | Raam (ARCHICAD Classification); 31.22 ramen draaiend aan één kant (NL/SfB (4 cijfers)) | 6.3888 | 30 minuten brandwerend | 7.8 | 11200 | 0.196157 | 210
2 x 31_merk-BD1 | verdieping | 1800 | 3795 | Raam (ARCHICAD Classification); 31.22 ramen draaiend aan één kant (NL/SfB (4 cijfers)) | 5.5484 | --- | 6.831 | 11190 | 0.0870208 | 430
31_merk-BD3 | verdieping | 1800 | 3100 | Raam (ARCHICAD Classification); 31.22 ramen draaiend aan één kant (NL/SfB (4 cijfers)) | 4.37246 | --- | 5.58 | 9800 | 0.0816165 | 430
31_merk-BC2 | verdieping | 1800 | 3575 | Raam (ARCHICAD Classification); 31.22 ramen draaiend aan één kant (NL/SfB (4 cijfers)) | 5.17616 | --- | 6.435 | 10750 | 0.0853101 | 430
2 x 31_merk-BB2 | verdieping | 1800 | 3475 | Raam (ARCHICAD Classification); 31.22 ramen draaiend aan één kant (NL/SfB (4 cijfers)) | 5.00696 | --- | 6.255 | 10550 | 0.0845325 | 430
3 x 31_merk-BA1 | verdieping | 1800 | 3575 | Raam (ARCHICAD Classification); 31.22 ramen draaiend aan één kant (NL/SfB (4 cijfers)) | 5.17616 | --- | 6.435 | 10750 | 0.0853101 | 430
